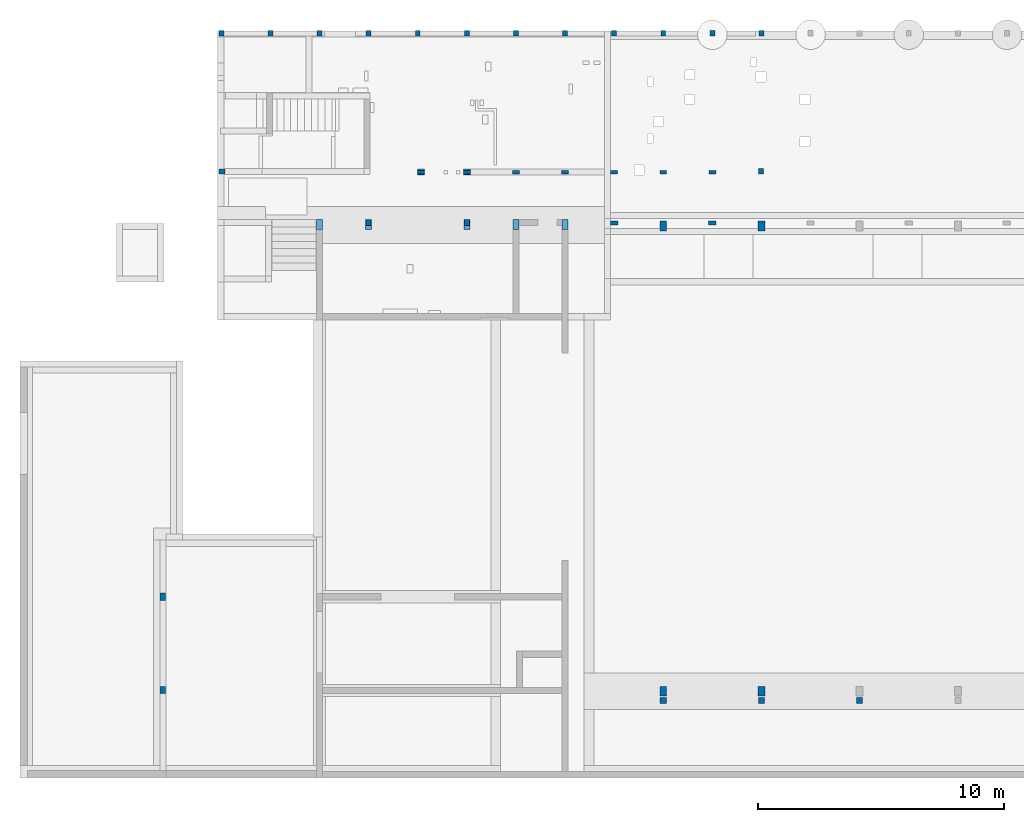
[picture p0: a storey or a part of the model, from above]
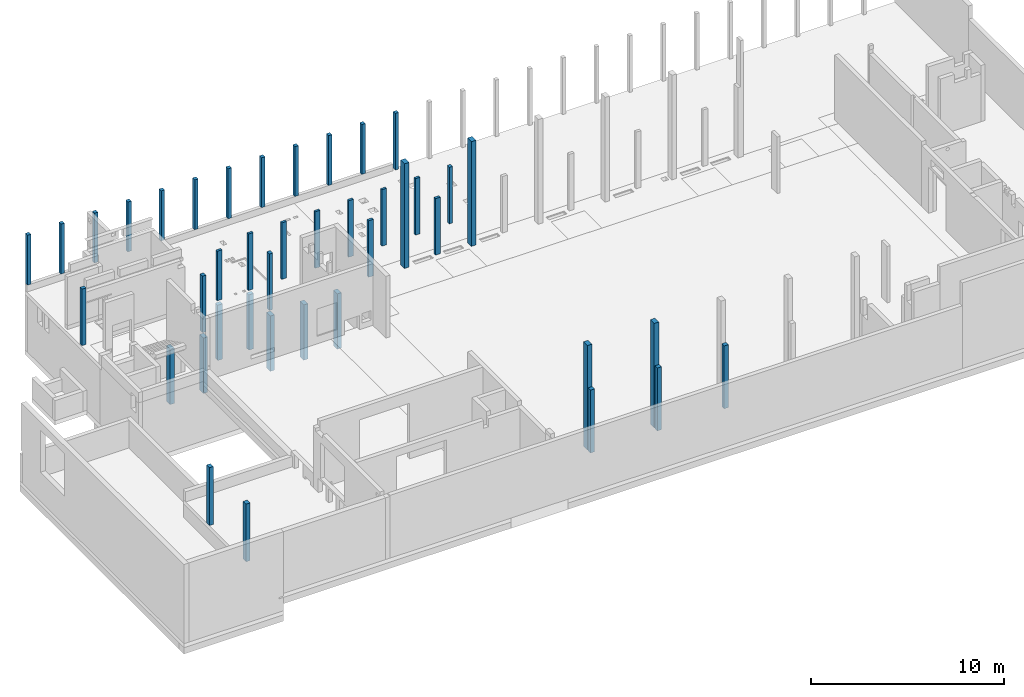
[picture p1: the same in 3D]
Properties of the parts of a building model (IFC2X3), part 1 of 6

# File
Description: ViewDefinition [CoordinationView_V2.0], RevitIdentifiers [ContentGUID: , VersionGUID: a09f6c8c-cfaa-406c-b728-5db6d23b4cc1, NumberOfSaves: 307], CoordinateReference [CoordinateBase: Projekt-Basispunkt, ProjectSite: Intern]
File name: 223092_BWS_Bürgerhaus_Weil_im_Schönbuch_rvt_23.ifc
Time: 2025-05-28T14:49:00+01:00
Written by: ODA SDAI 22.12
Made in: Autodesk Revit 23.1.60.36 (DEU) - IFC 23.4.0.0

# IfcProject, 223092
LongName: Bürgerhaus Weil im Schönbuch; Phase: Projektstatus

# IfcSite, Default
RefLatitude: 48, 8, 20, 852966; RefLongitude: 11, 34, 48, 669204; RefElevation: 0 m
Sonstige - Auftraggeber: Gemeinde Weil im Schönbuch; Kategorie: Projektinformationen; Projektadresse: Seesteige 11, 71093 Weil im Schönbuch; Projektausgabedatum: 21.02.2025; Projektname: Bürgerhaus Weil im Schönbuch; Projektnummer: 223092; Projektstatus: Projektstatus; WS_CLIENT_ADDRESS: Marktplatz 3, 71093 Weil im Schönbuch
Daten - WS_ARCHITECT: Architekt Name; WS_ARCHITECT_INFO: Architekt StraßeArchitekt PLZ OrtArchitekt Telefon; WS_PLANNER_1: Fachplaner 1 Name; WS_PLANNER_1_INFO: Fachplaner StraßeFachplaner PLZ OrtFachplaner Telefon; WS_PLANNER_2: Fachplaner 2 Name; WS_PLANNER_2_INFO: Fachplaner StraßeFachplaner PLZ OrtFachplaner Telefon; WS_PLANNER_3: Fachplaner 3 Name; WS_PLANNER_3_INFO: Fachplaner StraßeFachplaner PLZ OrtFachplaner Telefon; WS_PLANNER_4: Fachplaner 4 Name; WS_PLANNER_4_INFO: Fachplaner StraßeFachplaner PLZ OrtFachplaner Telefon; WS_PROJECT_CONTROLLER: Projektsteuerer; WS_PROJECT_CONTROLLER_INFO: Projektsteuerer StraßeProjektsteuerer PLZ OrtProjektsteuerer Telefon; WS_STRUCTURAL_PLANNER: Tragwerksplaner Name; WS_STRUCTURAL_PLANNER_INFO: Tragwerksplaner StraßeTragwerksplaner PLZ OrtTragwerksplaner Telefon; WS_SUBJECT: Objektplanung

# IfcBuilding
Pset_BuildingCommon - NumberOfStoreys: 2
Sonstige - Auftraggeber: Gemeinde Weil im Schönbuch; Kategorie: Projektinformationen; Projektadresse: Seesteige 11, 71093 Weil im Schönbuch; Projektausgabedatum: 21.02.2025; Projektname: Bürgerhaus Weil im Schönbuch; Projektnummer: 223092; Projektstatus: Projektstatus; WS_CLIENT_ADDRESS: Marktplatz 3, 71093 Weil im Schönbuch
Daten - WS_ARCHITECT: Architekt Name; WS_ARCHITECT_INFO: Architekt StraßeArchitekt PLZ OrtArchitekt Telefon; WS_PLANNER_1: Fachplaner 1 Name; WS_PLANNER_1_INFO: Fachplaner StraßeFachplaner PLZ OrtFachplaner Telefon; WS_PLANNER_2: Fachplaner 2 Name; WS_PLANNER_2_INFO: Fachplaner StraßeFachplaner PLZ OrtFachplaner Telefon; WS_PLANNER_3: Fachplaner 3 Name; WS_PLANNER_3_INFO: Fachplaner StraßeFachplaner PLZ OrtFachplaner Telefon; WS_PLANNER_4: Fachplaner 4 Name; WS_PLANNER_4_INFO: Fachplaner StraßeFachplaner PLZ OrtFachplaner Telefon; WS_PROJECT_CONTROLLER: Projektsteuerer; WS_PROJECT_CONTROLLER_INFO: Projektsteuerer StraßeProjektsteuerer PLZ OrtProjektsteuerer Telefon; WS_STRUCTURAL_PLANNER: Tragwerksplaner Name; WS_STRUCTURAL_PLANNER_INFO: Tragwerksplaner StraßeTragwerksplaner PLZ OrtTragwerksplaner Telefon; WS_SUBJECT: Objektplanung

# IfcBuildingStorey: Ebene:TAG_TFFL (2)
Pset_AirSideSystemInformation - sets with these values: 2
Sonstige - Familie: Ebene; Familie und Typ: Ebene: TAG_TFFL; Kategorie: Ebenen; Typ: TAG_TFFL; Typ-ID: 310376
Bemaßungen - Höhe für Berechnung: 0 m
ID-Daten - Gebäudegeschoss: yes; Tragwerk: no
Sonstige(Type) - Kategorie: Ebenen; Familienname: Ebene
Abhängigkeiten(Type) - Basishöhe: Projekt-Basispunkt
Grafiken(Type) - Farbe: 16711680; Linienmuster: WS_DOT; Linienstärke: 1; Symbol: WS_TAG_LEVEL1 : TAG_TFFL 2; Symbol bei Ende 1 Standard: no; Symbol bei Ende 2 Standard: yes
ID-Daten(Type) - Typname: TAG_TFFL
Name | LongName = Pset_AirSideSystemInformation, Name = ID-Daten, Name | Elevation (m) = Höhe (m) | WS_LEVEL
FB_U01_OKFB | FB_U01_OKFB | -3.8 | UG1
FB_E00_OKFB | FB_E00_OKFB | 0 | EG

# IfcBeam: WS_CBM_REC:CBM_REC_240x250 (3)
In: FB_E00_OKFB
Type - PredefinedType: BEAM
Type - Sonstige - Kategorie: Skelettbau; Familienname: WS_CBM_REC
Type - Bemaßungen - Height: 0.25 m; Höhe: 0.25 m; WS_HEIGHT: 0.25 m; WS_WIDTH: 0.24 m
Type - ID-Daten - Typname: CBM_REC_240x250; WS_COMMENT_DIMENSION: UZ 24/25cm
Type - Materialien und Oberflächen - Tragendes Material: WS_CONCRETE_REINFORCED
Type - Tragwerk - Querschnittsform: 0
Type - Pset_BeamCommon - LoadBearing: yes
Material: WS_CONCRETE_REINFORCED
Pset_BeamCommon - IsExternal: no; Slope: 0 deg; Reference: CBM_REC_240x250
Pset_QuantityTakeOff - Reference: CBM_REC_240x250; sets with these values: 2
Sonstige - Familie: WS_CBM_REC; Familie und Typ: WS_CBM_REC: CBM_REC_240x250; Typ: CBM_REC_240x250; Typ-ID: 3908165; WS_END_EXTENSION_CALCULATED: 3 m; WS_START_EXTENSION_CALCULATED: 3 m
Abhängigkeiten - Querschnittdrehung: 0 deg; Ausrichtung: Normal; Arbeitsebene: <nicht verknüpft>
Konstruktion - WS_END_EXTENSION: 0 m; WS_START_EXTENSION: 0 m
Bemaßungen - Höhe oben: 1.01 m; Höhe unten: 0.76 m
ID-Daten - Hat Verknüpfung: no; WS_COMMENT_MATERIAL: C25/30 RC; WS_POSITIONNUMBER: 003.1; WS_TYPE_BUILDING_ELEMENT: B
Phasen - Phase erstellt: Phase 1
Tragwerk - Betonüberdeckung - Andere Flächen: Bewehrungsüberdeckung 1 <25 mm>; Betonüberdeckung - Obere Fläche: Bewehrungsüberdeckung 1 <25 mm>; Betonüberdeckung - Untere Fläche: Bewehrungsüberdeckung 1 <25 mm>; Tragwerksverwendung: Sonstige; Anfangsverbindung - Typ: Endhöhe
Text - WS_LEVEL: 00
Geometrische Position - y-Ausrichtung: Ursprung; y-Versatzwert: 0 m; yz-Ausrichtung: Einheitlich; z-Ausrichtung: Oben; Verbindungsstatus: Beide Verbindungen aktiviert; z-Versatzwert: 0.08 m
Name (WS_CBM_REC:CBM_REC_240x250:...) | Span (m) = Länge (m) | Volumen (m3) | Endverbindung - Typ | Schnittlänge (m)
4185140 | 2.3125 | 0.129552 | Endhöhe | 2.16
4185141 | 3.52 | 0.21 | Endhöhe | 3.5
4185142 | 3.29271 | 0.1878 |  | 3.13001

# IfcBeam: WS_CBM_REC:CBM_REC_240x500 (3)
In: FB_E00_OKFB
Type - PredefinedType: BEAM
Type - Sonstige - Kategorie: Skelettbau; Familienname: WS_CBM_REC
Type - Bemaßungen - Height: 0.5 m; Höhe: 0.5 m; WS_HEIGHT: 0.5 m; WS_WIDTH: 0.24 m
Type - ID-Daten - Typname: CBM_REC_240x500; WS_COMMENT_DIMENSION: UZ 24/50cm
Type - Materialien und Oberflächen - Tragendes Material: WS_CONCRETE_REINFORCED
Type - Tragwerk - Querschnittsform: 0
Type - Pset_BeamCommon - LoadBearing: yes
Material: WS_CONCRETE_REINFORCED
Pset_BeamCommon - IsExternal: no; Slope: 0 deg; Reference: CBM_REC_240x500
Pset_QuantityTakeOff - Reference: CBM_REC_240x500; sets with these values: 2
Sonstige - Familie: WS_CBM_REC; Familie und Typ: WS_CBM_REC: CBM_REC_240x500; Typ: CBM_REC_240x500; Typ-ID: 3907001; WS_END_EXTENSION_CALCULATED: 3 m; WS_START_EXTENSION_CALCULATED: 3 m
Abhängigkeiten - Endebenenversatz: 0 m; Querschnittdrehung: 0 deg; Startebenenversatz: 0 m; Ausrichtung: Normal; Arbeitsebene: Ebene : Dü_EG_OKRD_+4,035; Höhe Referenzebene: 4.035 m; Referenzebene: Dü_EG_OKRD_+4,035
Konstruktion - WS_END_EXTENSION: 0 m; WS_START_EXTENSION: 0 m
Bemaßungen - Höhe oben: 4.035 m; Höhe unten: 3.535 m
ID-Daten - Hat Verknüpfung: no; WS_COMMENT_MATERIAL: C25/30 RC; WS_TYPE_BUILDING_ELEMENT: B
Phasen - Phase erstellt: Phase 1
Tragwerk - Betonüberdeckung - Andere Flächen: Bewehrungsüberdeckung 1 <25 mm>; Betonüberdeckung - Untere Fläche: Bewehrungsüberdeckung 1 <25 mm>; Tragwerksverwendung: Sonstige; Anfangsverbindung - Typ: Endhöhe
Text - WS_LEVEL: 00
Geometrische Position - y-Ausrichtung: Ursprung; y-Versatzwert: 0 m; yz-Ausrichtung: Einheitlich; z-Ausrichtung: Oben; Verbindungsstatus: Beide Verbindungen aktiviert; z-Versatzwert: 0 m
Name (WS_CBM_REC:CBM_REC_240x500:...) | Span (m) = Länge (m) | Volumen (m3) | WS_POSITIONNUMBER | Schnittlänge (m)
3907054 | 6.825 | 0.405 | 001.2 | 6.75 | Tragwerk - Endverbindung - Typ: Endhöhe
3908007 | 9.54001 | 0.5634 | 001.3 | 9.39001
3925428 | 6.225 | 0.3621 | 001.1 | 6.075

# IfcBeam: WS_CBM_REC:CBM_REC_240x600, WS_CBM_REC:CBM_REC_240x600:3857827
In: FB_U01_OKFB
Type - PredefinedType: BEAM
Type - Sonstige - Kategorie: Skelettbau; Familienname: WS_CBM_REC
Type - Bemaßungen - Height: 0.6 m; Höhe: 0.6 m; WS_HEIGHT: 0.6 m; WS_WIDTH: 0.24 m
Type - ID-Daten - Typname: CBM_REC_240x600; WS_COMMENT_DIMENSION: UZ 24/60cm
Type - Materialien und Oberflächen - Tragendes Material: WS_CONCRETE_REINFORCED
Type - Tragwerk - Querschnittsform: 0
Type - Pset_BeamCommon - LoadBearing: yes
Material: WS_CONCRETE_REINFORCED
Pset_BeamCommon - IsExternal: no; Slope: 0 deg; Reference: CBM_REC_240x600; Span: 5.725 m
Pset_QuantityTakeOff - Reference: CBM_REC_240x600; sets with these values: 2
Sonstige - Familie: WS_CBM_REC; Familie und Typ: WS_CBM_REC: CBM_REC_240x600; Typ: CBM_REC_240x600; Typ-ID: 4411974; WS_END_EXTENSION_CALCULATED: 3.15571 m; WS_START_EXTENSION_CALCULATED: 3 m
Abhängigkeiten - Endebenenversatz: 0 m; Querschnittdrehung: 0 deg; Startebenenversatz: 0 m; Ausrichtung: Normal; Referenzebene: Dü_U01_OKRD_-0,12; Arbeitsebene: Ebene : Dü_U01_OKRD_-0,12; Höhe Referenzebene: -0.12 m
Konstruktion - WS_START_EXTENSION: 0 m; WS_END_EXTENSION: 0.155715 m
Bemaßungen - Höhe oben: -0.12 m; Höhe unten: -0.72 m; Länge: 5.725 m; Volumen: 0.45864 m3
ID-Daten - Hat Verknüpfung: no; WS_COMMENT_MATERIAL: C25/30 RC; WS_POSITIONNUMBER: 001; WS_TYPE_BUILDING_ELEMENT: B
Phasen - Phase erstellt: Phase 1
Tragwerk - Betonüberdeckung - Andere Flächen: Bewehrungsüberdeckung 1 <25 mm>; Betonüberdeckung - Untere Fläche: Bewehrungsüberdeckung 1 <25 mm>; Tragwerksverwendung: Sonstige; Endverbindung - Typ: Endhöhe; Schnittlänge: 5.46 m
Text - WS_LEVEL: U1
Geometrische Position - y-Ausrichtung: Ursprung; y-Versatzwert: 0 m; yz-Ausrichtung: Einheitlich; z-Ausrichtung: Oben; Verbindungsstatus: Beide Verbindungen aktiviert; z-Versatzwert: 0 m

# IfcBeam: WS_CBM_REC:CBM_REC_250x1065, WS_CBM_REC:CBM_REC_250x1065:3713072
In: FB_E00_OKFB
Type - PredefinedType: BEAM; Material: WS_CONCRETE_REINFORCED
Type - Sonstige - Kategorie: Skelettbau; Familienname: WS_CBM_REC
Type - Bemaßungen - Height: 1.065 m; Höhe: 1.065 m; WS_HEIGHT: 1.065 m; WS_WIDTH: 0.25 m
Type - ID-Daten - Typname: CBM_REC_250x1065; WS_COMMENT_DIMENSION: UZ 25/106,5cm
Type - Materialien und Oberflächen - Tragendes Material: WS_CONCRETE_REINFORCED
Type - Tragwerk - Querschnittsform: 0
Type - Pset_BeamCommon - LoadBearing: yes
Pset_BeamCommon - IsExternal: no; Slope: 0 deg; Reference: CBM_REC_250x1065; Span: 20.18 m
Pset_QuantityTakeOff - Reference: CBM_REC_250x1065; sets with these values: 2
Sonstige - Familie: WS_CBM_REC; Familie und Typ: WS_CBM_REC: CBM_REC_250x1065; Typ: CBM_REC_250x1065; Typ-ID: 3712955; WS_END_EXTENSION_CALCULATED: 3 m; WS_START_EXTENSION_CALCULATED: 3 m
Abhängigkeiten - Endebenenversatz: 0 m; Höhe Referenzebene: 4.15 m; Querschnittdrehung: 0 deg; Referenzebene: Dü_EG_OKRD_+4,15; Startebenenversatz: 0 m
Konstruktion - WS_END_EXTENSION: 0 m; WS_START_EXTENSION: 0 m
Bemaßungen - Höhe oben: 4.61 m; Höhe unten: 3.545 m; Länge: 20.18 m; Volumen: 3.78816 m3
ID-Daten - Hat Verknüpfung: no; WS_COMMENT_MATERIAL: C25/30 RC; WS_POSITIONNUMBER: 003; WS_TYPE_BUILDING_ELEMENT: B
Phasen - Phase erstellt: Phase 1
Tragwerk - Betonüberdeckung - Andere Flächen: Bewehrungsüberdeckung 1 <25 mm>; Betonüberdeckung - Obere Fläche: Bewehrungsüberdeckung 1 <25 mm>; Betonüberdeckung - Untere Fläche: Bewehrungsüberdeckung 1 <25 mm>; Schnittlänge: 20.3074 m; Tragwerksverwendung: Sonstige
Text - WS_LEVEL: 00
Geometrische Position - Verbindungsstatus: Eine oder zwei Verbindungen deaktiviert; y-Ausrichtung: Ursprung; y-Versatzwert: 0 m; yz-Ausrichtung: Einheitlich; z-Ausrichtung: Oben; z-Versatzwert: 0.46 m

# IfcBeam: WS_CBM_REC:CBM_REC_250x580, WS_CBM_REC:CBM_REC_250x580:4160228
In: FB_E00_OKFB
Type - PredefinedType: BEAM; Material: WS_CONCRETE_REINFORCED
Type - Sonstige - Kategorie: Skelettbau; Familienname: WS_CBM_REC
Type - Bemaßungen - Height: 0.58 m; Höhe: 0.58 m; WS_HEIGHT: 0.58 m; WS_WIDTH: 0.25 m
Type - ID-Daten - Typname: CBM_REC_250x580; WS_COMMENT_DIMENSION: UZ 25/58cm
Type - Materialien und Oberflächen - Tragendes Material: WS_CONCRETE_REINFORCED
Type - Tragwerk - Querschnittsform: 0
Type - Pset_BeamCommon - LoadBearing: yes
Pset_BeamCommon - IsExternal: no; Slope: 0 deg; Reference: CBM_REC_250x580; Span: 10.075 m
Pset_QuantityTakeOff - Reference: CBM_REC_250x580; sets with these values: 2
Sonstige - Familie: WS_CBM_REC; Familie und Typ: WS_CBM_REC: CBM_REC_250x580; Typ: CBM_REC_250x580; Typ-ID: 4369942; WS_END_EXTENSION_CALCULATED: 3 m; WS_START_EXTENSION_CALCULATED: 3 m
Abhängigkeiten - Endebenenversatz: 0 m; Querschnittdrehung: 0 deg; Startebenenversatz: 0 m; Ausrichtung: Normal; Referenzebene: Dü_EG_OKRD_+4,035; Arbeitsebene: Ebene : Dü_EG_OKRD_+4,035; Höhe Referenzebene: 4.035 m
Konstruktion - WS_END_EXTENSION: 0 m; WS_START_EXTENSION: 0 m
Bemaßungen - Höhe oben: 4.035 m; Höhe unten: 3.455 m; Länge: 10.075 m; Volumen: 0.789995 m3
ID-Daten - Hat Verknüpfung: no; WS_COMMENT_MATERIAL: C25/30 RC; WS_POSITIONNUMBER: 002; WS_TYPE_BUILDING_ELEMENT: B
Phasen - Phase erstellt: Phase 1
Tragwerk - Betonüberdeckung - Andere Flächen: Bewehrungsüberdeckung 1 <25 mm>; Betonüberdeckung - Untere Fläche: Bewehrungsüberdeckung 1 <25 mm>; Tragwerksverwendung: Sonstige; Schnittlänge: 10.075 m
Text - WS_LEVEL: 00
Geometrische Position - y-Ausrichtung: Ursprung; y-Versatzwert: 0 m; yz-Ausrichtung: Einheitlich; z-Ausrichtung: Oben; Verbindungsstatus: Beide Verbindungen aktiviert; z-Versatzwert: 0 m

# IfcBeam: WS_CBM_UPST_REC:CBM_UPST_REC_200x1950, WS_CBM_UPST_REC:CBM_UPST_REC_200x1950:3713771
In: FB_E00_OKFB
Type - PredefinedType: BEAM
Type - Sonstige - Kategorie: Skelettbau; Familienname: WS_CBM_UPST_REC
Type - Bemaßungen - Height: 1.95 m; Höhe: 1.95 m; WS_HEIGHT: 1.95 m; WS_WIDTH: 0.2 m
Type - ID-Daten - Typname: CBM_UPST_REC_200x1950; WS_COMMENT_DIMENSION: ÜZ 20/195cm
Type - Materialien und Oberflächen - Tragendes Material: WS_CONCRETE_REINFORCED
Type - Tragwerk - Querschnittsform: 0
Type - Pset_BeamCommon - LoadBearing: yes
Material: WS_CONCRETE_REINFORCED
Pset_BeamCommon - IsExternal: no; Slope: 0 deg; Reference: CBM_UPST_REC_200x1950; Span: 9.905 m
Pset_QuantityTakeOff - Reference: CBM_UPST_REC_200x1950; sets with these values: 2
Sonstige - Familie: WS_CBM_UPST_REC; Familie und Typ: WS_CBM_UPST_REC: CBM_UPST_REC_200x1950; Typ: CBM_UPST_REC_200x1950; Typ-ID: 4167233; WS_END_EXTENSION_CALCULATED: 3 m; WS_START_EXTENSION_CALCULATED: 3 m
Abhängigkeiten - Endebenenversatz: 0 m; Querschnittdrehung: 0 deg; Startebenenversatz: 0 m; Arbeitsebene: Ebene : Dü_EG_UKRD_+3,85; Ausrichtung: Normal; Höhe Referenzebene: 3.85 m; Referenzebene: Dü_EG_UKRD_+3,85
Konstruktion - WS_END_EXTENSION: 0 m; WS_START_EXTENSION: 0 m
Bemaßungen - Höhe oben: 5.8 m; Höhe unten: 3.85 m; Länge: 9.905 m; Volumen: 2.8084 m3
ID-Daten - Hat Verknüpfung: no; WS_COMMENT_MATERIAL: C25/30 RC; WS_TYPE_BUILDING_ELEMENT: B
Phasen - Phase erstellt: Phase 1
Tragwerk - Betonüberdeckung - Andere Flächen: Bewehrungsüberdeckung 1 <25 mm>; Betonüberdeckung - Obere Fläche: Bewehrungsüberdeckung 1 <25 mm>; Tragwerksverwendung: Sonstige; Schnittlänge: 10.03 m
Text - WS_LEVEL: 00
Geometrische Position - y-Ausrichtung: Ursprung; y-Versatzwert: 0 m; yz-Ausrichtung: Einheitlich; Verbindungsstatus: Beide Verbindungen aktiviert; z-Ausrichtung: Unten; z-Versatzwert: 0 m

# IfcBeam: WS_CBM_UPST_REC:CBM_UPST_REC_200x850, WS_CBM_UPST_REC:CBM_UPST_REC_200x850:4435147
In: FB_E00_OKFB
Type - PredefinedType: BEAM
Type - Sonstige - Kategorie: Skelettbau; Familienname: WS_CBM_UPST_REC
Type - Bemaßungen - Height: 0.85 m; Höhe: 0.85 m; WS_HEIGHT: 0.85 m; WS_WIDTH: 0.2 m
Type - ID-Daten - Typname: CBM_UPST_REC_200x850; WS_COMMENT_DIMENSION: ÜZ 20/85cm
Type - Materialien und Oberflächen - Tragendes Material: WS_CONCRETE_REINFORCED
Type - Tragwerk - Querschnittsform: 0
Type - Pset_BeamCommon - LoadBearing: yes
Material: WS_CONCRETE_REINFORCED
Pset_BeamCommon - IsExternal: no; Slope: 0 deg; Reference: CBM_UPST_REC_200x850; Span: 8.13 m
Pset_QuantityTakeOff - Reference: CBM_UPST_REC_200x850; sets with these values: 2
Sonstige - Familie: WS_CBM_UPST_REC; Familie und Typ: WS_CBM_UPST_REC: CBM_UPST_REC_200x850; Typ: CBM_UPST_REC_200x850; Typ-ID: 4460570; WS_END_EXTENSION_CALCULATED: 3 m; WS_START_EXTENSION_CALCULATED: 3 m
Abhängigkeiten - Endebenenversatz: 0 m; Querschnittdrehung: 0 deg; Startebenenversatz: 0 m; Ausrichtung: Normal; Arbeitsebene: Ebene : Dü_EG_OKRD_+5,12; Höhe Referenzebene: 5.12 m; Referenzebene: Dü_EG_OKRD_+5,12
Konstruktion - WS_END_EXTENSION: 0 m; WS_START_EXTENSION: 0 m
Bemaßungen - Höhe oben: 5.77 m; Höhe unten: 4.92 m; Länge: 8.13 m; Volumen: 1.06665 m3
ID-Daten - Hat Verknüpfung: no; WS_COMMENT_MATERIAL: C25/30 RC; WS_POSITIONNUMBER: 004; WS_TYPE_BUILDING_ELEMENT: B
Phasen - Phase erstellt: Phase 1
Tragwerk - Betonüberdeckung - Andere Flächen: Bewehrungsüberdeckung 1 <25 mm>; Betonüberdeckung - Obere Fläche: Bewehrungsüberdeckung 1 <25 mm>; Betonüberdeckung - Untere Fläche: Bewehrungsüberdeckung 1 <25 mm>; Tragwerksverwendung: Sonstige; Schnittlänge: 8.255 m
Text - WS_LEVEL: 00
Geometrische Position - y-Ausrichtung: Ursprung; y-Versatzwert: 0 m; yz-Ausrichtung: Einheitlich; Verbindungsstatus: Beide Verbindungen aktiviert; z-Ausrichtung: Unten; z-Versatzwert: -0.2 m

# IfcBeam: WS_CBM_UPST_REC:CBM_UPST_REC_250x1015, WS_CBM_UPST_REC:CBM_UPST_REC_250x1015:4164935
In: FB_E00_OKFB
Type - PredefinedType: BEAM
Type - Sonstige - Kategorie: Skelettbau; Familienname: WS_CBM_UPST_REC
Type - Bemaßungen - Height: 1.015 m; Höhe: 1.015 m; WS_HEIGHT: 1.015 m; WS_WIDTH: 0.25 m
Type - ID-Daten - Typname: CBM_UPST_REC_250x1015; WS_COMMENT_DIMENSION: ÜZ 25/101,5
Type - Materialien und Oberflächen - Tragendes Material: WS_CONCRETE_REINFORCED
Type - Tragwerk - Querschnittsform: 0
Type - Pset_BeamCommon - LoadBearing: yes
Material: WS_CONCRETE_REINFORCED
Pset_BeamCommon - IsExternal: no; Slope: 0 deg; Reference: CBM_UPST_REC_250x1015; Span: 15.6524 m
Pset_QuantityTakeOff - Reference: CBM_UPST_REC_250x1015; sets with these values: 2
Sonstige - Familie: WS_CBM_UPST_REC; Familie und Typ: WS_CBM_UPST_REC: CBM_UPST_REC_250x1015; Typ: CBM_UPST_REC_250x1015; Typ-ID: 4164723; WS_END_EXTENSION_CALCULATED: 3 m; WS_START_EXTENSION_CALCULATED: 3 m
Abhängigkeiten - Endebenenversatz: 0 m; Querschnittdrehung: 0 deg; Startebenenversatz: 0 m; Ausrichtung: Normal; Referenzebene: Dü_EG_UKRD_+3,785; Arbeitsebene: Ebene : Dü_EG_UKRD_+3,785; Höhe Referenzebene: 3.785 m
Konstruktion - WS_END_EXTENSION: 0 m; WS_START_EXTENSION: 0 m
Bemaßungen - Höhe oben: 4.8 m; Höhe unten: 3.785 m; Länge: 15.6524 m; Volumen: 2.96369 m3
ID-Daten - Hat Verknüpfung: no; WS_COMMENT_MATERIAL: C25/30 RC; WS_POSITIONNUMBER: 021; WS_TYPE_BUILDING_ELEMENT: W
Phasen - Phase erstellt: Phase 1
Tragwerk - Betonüberdeckung - Andere Flächen: Bewehrungsüberdeckung 1 <25 mm>; Tragwerksverwendung: Sonstige; Schnittlänge: 15.6524 m
Text - WS_LEVEL: 00
Geometrische Position - y-Ausrichtung: Ursprung; y-Versatzwert: 0 m; yz-Ausrichtung: Einheitlich; Verbindungsstatus: Beide Verbindungen aktiviert; z-Ausrichtung: Unten; z-Versatzwert: 0 m

# IfcBeam: WS_CBM_UPST_REC:CBM_UPST_REC_250x137, WS_CBM_UPST_REC:CBM_UPST_REC_250x137:3872985
In: FB_E00_OKFB
Type - PredefinedType: BEAM
Type - Sonstige - Kategorie: Skelettbau; Familienname: WS_CBM_UPST_REC
Type - Bemaßungen - Height: 1.37 m; Höhe: 1.37 m; WS_HEIGHT: 1.37 m; WS_WIDTH: 0.25 m
Type - ID-Daten - Typname: CBM_UPST_REC_250x137; WS_COMMENT_DIMENSION: ÜZ 25/137cm
Type - Materialien und Oberflächen - Tragendes Material: WS_CONCRETE_REINFORCED
Type - Tragwerk - Querschnittsform: 0
Type - Pset_BeamCommon - LoadBearing: yes
Material: WS_CONCRETE_REINFORCED
Pset_BeamCommon - IsExternal: no; Slope: 0 deg; Reference: CBM_UPST_REC_250x137; Span: 5.93999 m
Pset_QuantityTakeOff - Reference: CBM_UPST_REC_250x137; sets with these values: 2
Sonstige - Familie: WS_CBM_UPST_REC; Familie und Typ: WS_CBM_UPST_REC: CBM_UPST_REC_250x137; Typ: CBM_UPST_REC_250x137; Typ-ID: 4178444; WS_END_EXTENSION_CALCULATED: 3 m; WS_START_EXTENSION_CALCULATED: 3 m
Abhängigkeiten - Endebenenversatz: 0 m; Querschnittdrehung: 0 deg; Startebenenversatz: 0 m; Ausrichtung: Normal; Referenzebene: Dü_EG_UKRD_+3,43; Arbeitsebene: Ebene : Dü_EG_UKRD_+3,43; Höhe Referenzebene: 3.43 m
Konstruktion - WS_END_EXTENSION: 0 m; WS_START_EXTENSION: 0 m
Bemaßungen - Höhe oben: 4.8 m; Höhe unten: 3.43 m; Länge: 5.93999 m; Volumen: 1.61291 m3
ID-Daten - Hat Verknüpfung: no; WS_COMMENT_MATERIAL: C25/30 RC
Phasen - Phase erstellt: Phase 1
Tragwerk - Betonüberdeckung - Andere Flächen: Bewehrungsüberdeckung 1 <25 mm>; Betonüberdeckung - Obere Fläche: Bewehrungsüberdeckung 1 <25 mm>; Tragwerksverwendung: Sonstige; Schnittlänge: 5.93999 m
Text - WS_LEVEL: 00
Geometrische Position - Verbindungsstatus: Eine oder zwei Verbindungen deaktiviert; y-Ausrichtung: Ursprung; y-Versatzwert: 0 m; yz-Ausrichtung: Einheitlich; z-Ausrichtung: Unten; z-Versatzwert: 0 m

# IfcBeam: WS_CBM_UPST_REC:CBM_UPST_REC_250x1400 (2)
In: FB_E00_OKFB
Type - PredefinedType: BEAM
Type - Sonstige - Kategorie: Skelettbau; Familienname: WS_CBM_UPST_REC
Type - Bemaßungen - Height: 1.4 m; Höhe: 1.4 m; WS_HEIGHT: 1.4 m; WS_WIDTH: 0.25 m
Type - ID-Daten - Typname: CBM_UPST_REC_250x1400; WS_COMMENT_DIMENSION: ÜZ 25/140cm
Type - Materialien und Oberflächen - Tragendes Material: WS_CONCRETE_REINFORCED
Type - Tragwerk - Querschnittsform: 0
Type - Pset_BeamCommon - LoadBearing: yes
Material: WS_CONCRETE_REINFORCED
Pset_BeamCommon - IsExternal: no; Slope: 0 deg; Reference: CBM_UPST_REC_250x1400
Pset_QuantityTakeOff - Reference: CBM_UPST_REC_250x1400; sets with these values: 2
Sonstige - Familie: WS_CBM_UPST_REC; Familie und Typ: WS_CBM_UPST_REC: CBM_UPST_REC_250x1400; Typ: CBM_UPST_REC_250x1400; Typ-ID: 3714466; WS_END_EXTENSION_CALCULATED: 3 m; WS_START_EXTENSION_CALCULATED: 3 m
Abhängigkeiten - Endebenenversatz: 0 m; Querschnittdrehung: 0 deg; Startebenenversatz: 0 m; Ausrichtung: Normal; Referenzebene: Dü_EG_UKRD_+3,85; Arbeitsebene: Ebene : Dü_EG_UKRD_+3,85; Höhe Referenzebene: 3.85 m
Konstruktion - WS_END_EXTENSION: 0 m; WS_START_EXTENSION: 0 m
Bemaßungen - Höhe oben: 5.25 m; Höhe unten: 3.85 m
ID-Daten - Hat Verknüpfung: no; WS_COMMENT_MATERIAL: C25/30 RC
Phasen - Phase erstellt: Phase 1
Tragwerk - Betonüberdeckung - Andere Flächen: Bewehrungsüberdeckung 1 <25 mm>; Betonüberdeckung - Obere Fläche: Bewehrungsüberdeckung 1 <25 mm>; Tragwerksverwendung: Sonstige
Text - WS_LEVEL: 00
Geometrische Position - y-Ausrichtung: Ursprung; y-Versatzwert: 0 m; yz-Ausrichtung: Einheitlich; Verbindungsstatus: Beide Verbindungen aktiviert; z-Ausrichtung: Unten; z-Versatzwert: 0 m
Name (WS_CBM_UPST_REC:CBM_UPST_REC_250x1400:...) | Span (m) = Länge (m) | Volumen (m3) | WS_POSITIONNUMBER | WS_TYPE_BUILDING_ELEMENT | Schnittlänge (m)
4168769 | 34.375 | 9.41875 | 103 | W | 34.25
4172455 | 3.0251 | 0.843776 | 031 | B | 3.2751

# IfcBeam: WS_CBM_UPST_REC:CBM_UPST_REC_250x2015, WS_CBM_UPST_REC:CBM_UPST_REC_250x2015:4165731
In: FB_E00_OKFB
Type - PredefinedType: BEAM; Material: WS_CONCRETE_REINFORCED
Type - Sonstige - Kategorie: Skelettbau; Familienname: WS_CBM_UPST_REC
Type - Bemaßungen - Height: 2.015 m; Höhe: 2.015 m; WS_HEIGHT: 2.015 m; WS_WIDTH: 0.25 m
Type - ID-Daten - Typname: CBM_UPST_REC_250x2015; WS_COMMENT_DIMENSION: ÜZ 25/201,5cm
Type - Materialien und Oberflächen - Tragendes Material: WS_CONCRETE_REINFORCED
Type - Tragwerk - Querschnittsform: 0
Type - Pset_BeamCommon - LoadBearing: yes
Pset_BeamCommon - IsExternal: no; Slope: 0 deg; Reference: CBM_UPST_REC_250x2015; Span: 2.68255 m
Pset_QuantityTakeOff - Reference: CBM_UPST_REC_250x2015; sets with these values: 2
Sonstige - Familie: WS_CBM_UPST_REC; Familie und Typ: WS_CBM_UPST_REC: CBM_UPST_REC_250x2015; Typ: CBM_UPST_REC_250x2015; Typ-ID: 4166134; WS_END_EXTENSION_CALCULATED: 3 m; WS_START_EXTENSION_CALCULATED: 3 m
Abhängigkeiten - Endebenenversatz: 0 m; Querschnittdrehung: 0 deg; Startebenenversatz: 0 m; Ausrichtung: Normal; Referenzebene: Dü_EG_UKRD_+3,785; Arbeitsebene: Ebene : Dü_EG_UKRD_+3,785; Höhe Referenzebene: 3.785 m
Konstruktion - WS_END_EXTENSION: 0 m; WS_START_EXTENSION: 0 m
Bemaßungen - Höhe oben: 5.8 m; Höhe unten: 3.785 m; Länge: 2.68255 m; Volumen: 0.990225 m3
ID-Daten - Hat Verknüpfung: no; WS_COMMENT_MATERIAL: C25/30 RC; WS_POSITIONNUMBER: 013; WS_TYPE_BUILDING_ELEMENT: W
Phasen - Phase erstellt: Phase 1
Tragwerk - Betonüberdeckung - Andere Flächen: Bewehrungsüberdeckung 1 <25 mm>; Betonüberdeckung - Obere Fläche: Bewehrungsüberdeckung 1 <25 mm>; Tragwerksverwendung: Sonstige; Schnittlänge: 2.68255 m
Text - WS_LEVEL: 00
Geometrische Position - y-Ausrichtung: Ursprung; y-Versatzwert: 0 m; yz-Ausrichtung: Einheitlich; Verbindungsstatus: Beide Verbindungen aktiviert; z-Ausrichtung: Unten; z-Versatzwert: 0 m

# IfcBeam: WS_CBM_UPST_REC:CBM_UPST_REC_250x2035, WS_CBM_UPST_REC:CBM_UPST_REC_250x2035:4176563
In: FB_E00_OKFB
Type - PredefinedType: BEAM
Type - Sonstige - Kategorie: Skelettbau; Familienname: WS_CBM_UPST_REC
Type - Bemaßungen - Height: 2.035 m; Höhe: 2.035 m; WS_HEIGHT: 2.035 m; WS_WIDTH: 0.25 m
Type - ID-Daten - Typname: CBM_UPST_REC_250x2035; WS_COMMENT_DIMENSION: ÜZ 25/203,5cm
Type - Materialien und Oberflächen - Tragendes Material: WS_CONCRETE_REINFORCED
Type - Tragwerk - Querschnittsform: 0
Type - Pset_BeamCommon - LoadBearing: yes
Material: WS_CONCRETE_REINFORCED
Pset_BeamCommon - IsExternal: no; Slope: 0 deg; Reference: CBM_UPST_REC_250x2035; Span: 4.90491 m
Pset_QuantityTakeOff - Reference: CBM_UPST_REC_250x2035; sets with these values: 2
Sonstige - Familie: WS_CBM_UPST_REC; Familie und Typ: WS_CBM_UPST_REC: CBM_UPST_REC_250x2035; Typ: CBM_UPST_REC_250x2035; Typ-ID: 4176715; WS_END_EXTENSION_CALCULATED: 3 m; WS_START_EXTENSION_CALCULATED: 3 m
Abhängigkeiten - Endebenenversatz: 0 m; Querschnittdrehung: 0 deg; Startebenenversatz: 0 m; Ausrichtung: Normal; Arbeitsebene: Ebene : Dü_EG_UKRD1_+3,735; Höhe Referenzebene: 3.735 m; Referenzebene: Dü_EG_UKRD1_+3,735
Konstruktion - WS_END_EXTENSION: 0 m; WS_START_EXTENSION: 0 m
Bemaßungen - Höhe oben: 5.77 m; Höhe unten: 3.735 m; Länge: 4.90491 m; Volumen: 2.17202 m3
ID-Daten - Hat Verknüpfung: no; WS_COMMENT_MATERIAL: C25/30
Phasen - Phase erstellt: Phase 1
Tragwerk - Betonüberdeckung - Andere Flächen: Bewehrungsüberdeckung 1 <25 mm>; Betonüberdeckung - Obere Fläche: Bewehrungsüberdeckung 1 <25 mm>; Betonüberdeckung - Untere Fläche: Bewehrungsüberdeckung 1 <25 mm>; Tragwerksverwendung: Sonstige; Schnittlänge: 4.84557 m
Text - WS_LEVEL: 00
Geometrische Position - Verbindungsstatus: Eine oder zwei Verbindungen deaktiviert; y-Ausrichtung: Ursprung; y-Versatzwert: 0 m; yz-Ausrichtung: Einheitlich; z-Ausrichtung: Unten; z-Versatzwert: 0 m

# IfcBeam: WS_CBM_UPST_REC:CBM_UPST_REC_250x480 (2)
In: FB_E00_OKFB
Type - PredefinedType: BEAM
Type - Sonstige - Kategorie: Skelettbau; Familienname: WS_CBM_UPST_REC
Type - Bemaßungen - Height: 0.48 m; Höhe: 0.48 m; WS_HEIGHT: 0.48 m; WS_WIDTH: 0.25 m
Type - ID-Daten - Typname: CBM_UPST_REC_250x480; WS_COMMENT_DIMENSION: ÜZ 25/48cm
Type - Materialien und Oberflächen - Tragendes Material: WS_CONCRETE_REINFORCED
Type - Tragwerk - Querschnittsform: 0
Type - Pset_BeamCommon - LoadBearing: yes
Material: WS_CONCRETE_REINFORCED
Pset_BeamCommon - IsExternal: no; Slope: 0 deg; Reference: CBM_UPST_REC_250x480
Pset_QuantityTakeOff - Reference: CBM_UPST_REC_250x480; sets with these values: 2
Sonstige - Familie: WS_CBM_UPST_REC; Familie und Typ: WS_CBM_UPST_REC: CBM_UPST_REC_250x480; Typ: CBM_UPST_REC_250x480; Typ-ID: 4168103; WS_END_EXTENSION_CALCULATED: 3 m; WS_START_EXTENSION_CALCULATED: 3 m
Abhängigkeiten - Endebenenversatz: 0 m; Querschnittdrehung: 0 deg; Startebenenversatz: 0 m; Ausrichtung: Normal; Arbeitsebene: Ebene : Dü_EG_UKRD_+3,785; Höhe Referenzebene: 3.785 m; Referenzebene: Dü_EG_UKRD_+3,785
Konstruktion - WS_END_EXTENSION: 0 m; WS_START_EXTENSION: 0 m
Bemaßungen - Höhe oben: 4.265 m; Höhe unten: 3.785 m
ID-Daten - Hat Verknüpfung: no; WS_COMMENT_MATERIAL: C25/30 RC; WS_TYPE_BUILDING_ELEMENT: W
Phasen - Phase erstellt: Phase 1
Tragwerk - Betonüberdeckung - Andere Flächen: Bewehrungsüberdeckung 1 <25 mm>; Betonüberdeckung - Obere Fläche: Bewehrungsüberdeckung 1 <25 mm>; Tragwerksverwendung: Sonstige
Text - WS_LEVEL: 00
Geometrische Position - y-Ausrichtung: Ursprung; y-Versatzwert: 0 m; yz-Ausrichtung: Einheitlich; z-Ausrichtung: Unten; z-Versatzwert: 0 m
Name (WS_CBM_UPST_REC:CBM_UPST_REC_250x480:...) | Span (m) = Länge (m) | Volumen (m3) | WS_POSITIONNUMBER | Schnittlänge (m) | Verbindungsstatus
3919060 | 11.565 | 0.672173 | 101 | 11.69 | Beide Verbindungen aktiviert
4168264 | 7.9 | 0.4485 | 107 | 7.8 | Eine oder zwei Verbindungen deaktiviert

# IfcBeam: WS_CBM_UPST_REC:CBM_UPST_REC_250x615, WS_CBM_UPST_REC:CBM_UPST_REC_250x615:4165654
In: FB_E00_OKFB
Type - PredefinedType: BEAM
Type - Sonstige - Kategorie: Skelettbau; Familienname: WS_CBM_UPST_REC
Type - Bemaßungen - Height: 0.615 m; Höhe: 0.615 m; WS_HEIGHT: 0.615 m; WS_WIDTH: 0.25 m
Type - ID-Daten - Typname: CBM_UPST_REC_250x615; WS_COMMENT_DIMENSION: Attika
Type - Materialien und Oberflächen - Tragendes Material: WS_CONCRETE_REINFORCED
Type - Tragwerk - Querschnittsform: 0
Type - Pset_BeamCommon - LoadBearing: yes
Material: WS_CONCRETE_REINFORCED
Pset_BeamCommon - IsExternal: no; Slope: 0 deg; Reference: CBM_UPST_REC_250x615; Span: 1.27 m
Pset_QuantityTakeOff - Reference: CBM_UPST_REC_250x615; sets with these values: 2
Sonstige - Familie: WS_CBM_UPST_REC; Familie und Typ: WS_CBM_UPST_REC: CBM_UPST_REC_250x615; Typ: CBM_UPST_REC_250x615; Typ-ID: 4707557; WS_END_EXTENSION_CALCULATED: 3 m; WS_START_EXTENSION_CALCULATED: 3 m
Abhängigkeiten - Endebenenversatz: 0 m; Querschnittdrehung: 0 deg; Startebenenversatz: 0 m; Ausrichtung: Normal; Referenzebene: Dü_EG_UKRD_+3,785; Arbeitsebene: Ebene : Dü_EG_UKRD_+3,785; Höhe Referenzebene: 3.785 m
Konstruktion - WS_END_EXTENSION: 0 m; WS_START_EXTENSION: 0 m
Bemaßungen - Höhe oben: 4.4 m; Höhe unten: 3.785 m; Länge: 1.27 m; Volumen: 0.0365125 m3
ID-Daten - Hat Verknüpfung: no; WS_COMMENT_MATERIAL: C25/30 RC; WS_POSITIONNUMBER: 013; WS_TYPE_BUILDING_ELEMENT: W
Phasen - Phase erstellt: Phase 1
Tragwerk - Betonüberdeckung - Andere Flächen: Bewehrungsüberdeckung 1 <25 mm>; Tragwerksverwendung: Sonstige; Schnittlänge: 1.27 m
Text - WS_LEVEL: 00
Geometrische Position - y-Ausrichtung: Ursprung; y-Versatzwert: 0 m; yz-Ausrichtung: Einheitlich; Verbindungsstatus: Beide Verbindungen aktiviert; z-Ausrichtung: Unten; z-Versatzwert: 0 m

# IfcBeam: WS_CBM_UPST_REC:CBM_UPST_REC_250x760, WS_CBM_UPST_REC:CBM_UPST_REC_250x760:4375847
In: FB_E00_OKFB
Type - PredefinedType: BEAM
Type - Sonstige - Kategorie: Skelettbau; Familienname: WS_CBM_UPST_REC
Type - Bemaßungen - Height: 0.76 m; Höhe: 0.76 m; WS_HEIGHT: 0.76 m; WS_WIDTH: 0.25 m
Type - ID-Daten - Typname: CBM_UPST_REC_250x760; WS_COMMENT_DIMENSION: ÜZ 25/76cm
Type - Materialien und Oberflächen - Tragendes Material: WS_CONCRETE_REINFORCED
Type - Tragwerk - Querschnittsform: 0
Type - Pset_BeamCommon - LoadBearing: yes
Material: WS_CONCRETE_REINFORCED
Pset_BeamCommon - IsExternal: no; Slope: 0 deg; Reference: CBM_UPST_REC_250x760; Span: 3.945 m
Pset_QuantityTakeOff - Reference: CBM_UPST_REC_250x760; sets with these values: 2
Sonstige - Familie: WS_CBM_UPST_REC; Familie und Typ: WS_CBM_UPST_REC: CBM_UPST_REC_250x760; Typ: CBM_UPST_REC_250x760; Typ-ID: 3713280; WS_END_EXTENSION_CALCULATED: 3 m; WS_START_EXTENSION_CALCULATED: 3 m
Abhängigkeiten - Endebenenversatz: 0 m; Querschnittdrehung: 0 deg; Startebenenversatz: 0 m; Ausrichtung: Normal; Referenzebene: Dü_EG_UKRD_+3,85; Arbeitsebene: Ebene : Dü_EG_UKRD_+3,85; Höhe Referenzebene: 3.85 m
Konstruktion - WS_END_EXTENSION: 0 m; WS_START_EXTENSION: 0 m
Bemaßungen - Höhe oben: 4.61 m; Höhe unten: 3.85 m; Länge: 3.945 m; Volumen: 0.399287 m3
ID-Daten - Hat Verknüpfung: no; WS_COMMENT_MATERIAL: C25/30 RC; WS_POSITIONNUMBER: 004; WS_TYPE_BUILDING_ELEMENT: B
Phasen - Phase erstellt: Phase 1
Tragwerk - Betonüberdeckung - Andere Flächen: Bewehrungsüberdeckung 1 <25 mm>; Betonüberdeckung - Obere Fläche: Bewehrungsüberdeckung 1 <25 mm>; Tragwerksverwendung: Sonstige; Schnittlänge: 3.695 m
Text - WS_LEVEL: 00
Geometrische Position - y-Ausrichtung: Ursprung; y-Versatzwert: 0 m; yz-Ausrichtung: Einheitlich; Verbindungsstatus: Beide Verbindungen aktiviert; z-Ausrichtung: Unten; z-Versatzwert: 0 m

# IfcBeam: WS_CBM_UPST_REC:CBM_UPST_REC_250x835, WS_CBM_UPST_REC:CBM_UPST_REC_250x835:3716441
In: FB_E00_OKFB
Type - PredefinedType: BEAM
Type - Sonstige - Kategorie: Skelettbau; Familienname: WS_CBM_UPST_REC
Type - Bemaßungen - Height: 0.835 m; Höhe: 0.835 m; WS_HEIGHT: 0.835 m; WS_WIDTH: 0.25 m
Type - ID-Daten - Typname: CBM_UPST_REC_250x835; WS_COMMENT_DIMENSION: ÜZ 25/83,5cm
Type - Materialien und Oberflächen - Tragendes Material: WS_CONCRETE_REINFORCED
Type - Tragwerk - Querschnittsform: 0
Type - Pset_BeamCommon - LoadBearing: yes
Material: WS_CONCRETE_REINFORCED
Pset_BeamCommon - IsExternal: no; Slope: 0 deg; Reference: CBM_UPST_REC_250x835; Span: 4.10712 m
Pset_QuantityTakeOff - Reference: CBM_UPST_REC_250x835; sets with these values: 2
Sonstige - Familie: WS_CBM_UPST_REC; Familie und Typ: WS_CBM_UPST_REC: CBM_UPST_REC_250x835; Typ: CBM_UPST_REC_250x835; Typ-ID: 3716195; WS_END_EXTENSION_CALCULATED: 3 m; WS_START_EXTENSION_CALCULATED: 3.315 m
Abhängigkeiten - Endebenenversatz: 0 m; Querschnittdrehung: 0 deg; Startebenenversatz: 0 m; Ausrichtung: Normal; Referenzebene: Dü_EG_UKRD_+3,43; Arbeitsebene: Ebene : Dü_EG_UKRD_+3,43; Höhe Referenzebene: 3.43 m
Konstruktion - WS_END_EXTENSION: 0 m; WS_START_EXTENSION: 0.315 m
Bemaßungen - Höhe oben: 4.265 m; Höhe unten: 3.43 m; Länge: 4.10712 m; Volumen: 0.595979 m3
ID-Daten - Hat Verknüpfung: no; WS_COMMENT_MATERIAL: C25/30 RC; WS_POSITIONNUMBER: 106; WS_TYPE_BUILDING_ELEMENT: W
Phasen - Phase erstellt: Phase 1
Tragwerk - Betonüberdeckung - Andere Flächen: Bewehrungsüberdeckung 1 <25 mm>; Betonüberdeckung - Obere Fläche: Bewehrungsüberdeckung 1 <25 mm>; Tragwerksverwendung: Sonstige; Schnittlänge: 4.25712 m
Text - WS_LEVEL: 00
Geometrische Position - y-Ausrichtung: Ursprung; y-Versatzwert: 0 m; yz-Ausrichtung: Einheitlich; Verbindungsstatus: Beide Verbindungen aktiviert; z-Ausrichtung: Unten; z-Versatzwert: 0 m

# IfcBeam: WS_CBM_UPST_REC:CBM_UPST_REC_250x880, WS_CBM_UPST_REC:CBM_UPST_REC_250x880:4444293
In: FB_E00_OKFB
Type - PredefinedType: BEAM
Type - Sonstige - Kategorie: Skelettbau; Familienname: WS_CBM_UPST_REC
Type - Bemaßungen - Height: 0.88 m; Höhe: 0.88 m; WS_HEIGHT: 0.88 m; WS_WIDTH: 0.25 m
Type - ID-Daten - Typname: CBM_UPST_REC_250x880; WS_COMMENT_DIMENSION: ÜZ 25/88cm
Type - Materialien und Oberflächen - Tragendes Material: WS_CONCRETE_REINFORCED
Type - Tragwerk - Querschnittsform: 0
Type - Pset_BeamCommon - LoadBearing: yes
Material: WS_CONCRETE_REINFORCED
Pset_BeamCommon - IsExternal: no; Slope: 0 deg; Reference: CBM_UPST_REC_250x880; Span: 3.8 m
Pset_QuantityTakeOff - Reference: CBM_UPST_REC_250x880; sets with these values: 2
Sonstige - Familie: WS_CBM_UPST_REC; Familie und Typ: WS_CBM_UPST_REC: CBM_UPST_REC_250x880; Typ: CBM_UPST_REC_250x880; Typ-ID: 4444380; WS_END_EXTENSION_CALCULATED: 3 m; WS_START_EXTENSION_CALCULATED: 3 m
Abhängigkeiten - Endebenenversatz: 0 m; Querschnittdrehung: 0 deg; Startebenenversatz: 0 m; Ausrichtung: Normal; Referenzebene: Dü_EG_UKRD_+3,43; Arbeitsebene: Ebene : Dü_EG_UKRD_+3,43; Höhe Referenzebene: 3.43 m
Konstruktion - WS_END_EXTENSION: 0 m; WS_START_EXTENSION: 0 m
Bemaßungen - Höhe oben: 4.31 m; Höhe unten: 3.43 m; Länge: 3.8 m; Volumen: 0.5403 m3
ID-Daten - Hat Verknüpfung: no; WS_COMMENT_MATERIAL: C25/30 RC
Phasen - Phase erstellt: Phase 1
Tragwerk - Betonüberdeckung - Andere Flächen: Bewehrungsüberdeckung 1 <25 mm>; Betonüberdeckung - Obere Fläche: Bewehrungsüberdeckung 1 <25 mm>; Tragwerksverwendung: Sonstige; Schnittlänge: 3.8 m
Text - WS_LEVEL: 00
Geometrische Position - Verbindungsstatus: Eine oder zwei Verbindungen deaktiviert; y-Ausrichtung: Ursprung; y-Versatzwert: 0 m; yz-Ausrichtung: Einheitlich; z-Ausrichtung: Unten; z-Versatzwert: 0 m

# IfcBeam: WS_CBM_UPST_REC:CBM_UPST_REC_300x605, WS_CBM_UPST_REC:CBM_UPST_REC_300x605:3716240
In: FB_E00_OKFB
Type - PredefinedType: BEAM
Type - Sonstige - Kategorie: Skelettbau; Familienname: WS_CBM_UPST_REC
Type - Bemaßungen - Height: 0.605 m; Höhe: 0.605 m; WS_HEIGHT: 0.605 m; WS_WIDTH: 0.3 m
Type - ID-Daten - Typname: CBM_UPST_REC_300x605; WS_COMMENT_DIMENSION: Attika
Type - Materialien und Oberflächen - Tragendes Material: WS_CONCRETE_REINFORCED
Type - Tragwerk - Querschnittsform: 0
Type - Pset_BeamCommon - LoadBearing: yes
Material: WS_CONCRETE_REINFORCED
Pset_BeamCommon - IsExternal: no; Slope: 0 deg; Reference: CBM_UPST_REC_300x605; Span: 6.025 m
Pset_QuantityTakeOff - Reference: CBM_UPST_REC_300x605; sets with these values: 2
Sonstige - Familie: WS_CBM_UPST_REC; Familie und Typ: WS_CBM_UPST_REC: CBM_UPST_REC_300x605; Typ: CBM_UPST_REC_300x605; Typ-ID: 4685405; WS_END_EXTENSION_CALCULATED: 3 m; WS_START_EXTENSION_CALCULATED: 3 m
Abhängigkeiten - Endebenenversatz: 0 m; Querschnittdrehung: 0 deg; Startebenenversatz: 0 m; Ausrichtung: Normal; Arbeitsebene: Ebene : Dü_EG_UKRD_+3,43; Höhe Referenzebene: 3.43 m; Referenzebene: Dü_EG_UKRD_+3,43
Konstruktion - WS_END_EXTENSION: 0 m; WS_START_EXTENSION: 0 m
Bemaßungen - Höhe oben: 4.035 m; Höhe unten: 3.43 m; Länge: 6.025 m; Volumen: 0.815505 m3
ID-Daten - Hat Verknüpfung: no; WS_COMMENT_MATERIAL: C25/30 RC; WS_POSITIONNUMBER: 005; WS_TYPE_BUILDING_ELEMENT: B
Phasen - Phase erstellt: Phase 1
Tragwerk - Betonüberdeckung - Andere Flächen: Bewehrungsüberdeckung 1 <25 mm>; Betonüberdeckung - Obere Fläche: Bewehrungsüberdeckung 1 <25 mm>; Betonüberdeckung - Untere Fläche: Bewehrungsüberdeckung 1 <25 mm>; Tragwerksverwendung: Sonstige; Schnittlänge: 6.275 m
Text - WS_LEVEL: 00
Geometrische Position - y-Ausrichtung: Ursprung; y-Versatzwert: 0 m; yz-Ausrichtung: Einheitlich; Verbindungsstatus: Beide Verbindungen aktiviert; z-Ausrichtung: Unten; z-Versatzwert: 0 m

# IfcBeam: WS_FDN_REC:FDN_REC_1500x650_WT (2)
In: FB_U01_OKFB
Type - PredefinedType: BEAM
Type - Sonstige - Kategorie: Skelettbau; Familienname: WS_FDN_REC
Type - Bemaßungen - Height: 0.65 m; Höhe: 0.65 m; WS_HEIGHT: 0.65 m; WS_WIDTH: 1.5 m
Type - ID-Daten - Typname: FDN_REC_1500x650_WT; WS_COMMENT_DIMENSION: FU-ST 150/65cm
Type - Materialien und Oberflächen - Tragendes Material: WS_CONCRETE_REINFORCED_WATERTIGHT
Type - Tragwerk - Querschnittsform: 0
Type - Pset_BeamCommon - LoadBearing: yes
Material: WS_CONCRETE_REINFORCED_WATERTIGHT
Pset_BeamCommon - IsExternal: no; Slope: 0 deg; Reference: FDN_REC_1500x650_WT
Pset_QuantityTakeOff - Reference: FDN_REC_1500x650_WT; sets with these values: 2
Sonstige - Familie: WS_FDN_REC; Familie und Typ: WS_FDN_REC: FDN_REC_1500x650_WT; Typ: FDN_REC_1500x650_WT; Typ-ID: 3903142; WS_END_EXTENSION_CALCULATED: 3 m; WS_START_EXTENSION_CALCULATED: 3 m
Abhängigkeiten - Endebenenversatz: 0 m; Querschnittdrehung: 0 deg; Startebenenversatz: 0 m; Ausrichtung: Normal
Konstruktion - WS_END_EXTENSION: 0 m; WS_START_EXTENSION: 0 m
ID-Daten - Hat Verknüpfung: no; WS_COMMENT_MATERIAL: C25/30 WU; WS_TYPE_BUILDING_ELEMENT: F
Phasen - Phase erstellt: Phase 1
Tragwerk - Betonüberdeckung - Andere Flächen: Bewehrungsüberdeckung 1 <25 mm>; Betonüberdeckung - Untere Fläche: Bewehrungsüberdeckung 1 <25 mm>
Geometrische Position - y-Ausrichtung: Ursprung; y-Versatzwert: 0 m; yz-Ausrichtung: Einheitlich; z-Ausrichtung: Oben; Verbindungsstatus: Beide Verbindungen aktiviert; z-Versatzwert: 0 m
Name (WS_FDN_REC:FDN_REC_1500x650_WT:...) | Span (m) = Länge (m) | Referenzebene | Arbeitsebene | Höhe Referenzebene (m) = Höhe oben (m) | Höhe unten (m) | Volumen (m3) | WS_POSITIONNUMBER | Tragwerksverwendung | Schnittlänge (m) | WS_LEVEL
3718978 | 31.875 | Dü_U01_OKRD_-0,12 | Ebene : Dü_U01_OKRD_-0,12 | -0.12 | -0.77 | 17.6937 | 005 | Sonstige | 30.8495 | U1
3795049 | 13.8 | BP_UG1_OKBP_-3,87 | Ebene : BP_UG1_OKBP_-3,87 | -3.87 | -4.52 | 7.29094 | 001 | Tragwerk | 14.05 | FU

# IfcBeam: WS_FDN_REC:FDN_REC_205x670 (2)
In: FB_U01_OKFB
Type - PredefinedType: BEAM
Type - Sonstige - Kategorie: Skelettbau; Familienname: WS_FDN_REC
Type - Bemaßungen - Height: 0.67 m; Höhe: 0.67 m; WS_HEIGHT: 0.67 m; WS_WIDTH: 0.205 m
Type - ID-Daten - Typname: FDN_REC_205x670; WS_COMMENT_DIMENSION: ÜZ 20,5/67cm
Type - Materialien und Oberflächen - Tragendes Material: WS_CONCRETE_REINFORCED
Type - Tragwerk - Querschnittsform: 0
Type - Pset_BeamCommon - LoadBearing: yes
Material: WS_CONCRETE_REINFORCED
Pset_BeamCommon - IsExternal: no; Slope: 0 deg; Reference: FDN_REC_205x670
Pset_QuantityTakeOff - Reference: FDN_REC_205x670; sets with these values: 2
Sonstige - Familie: WS_FDN_REC; Familie und Typ: WS_FDN_REC: FDN_REC_205x670; Typ: FDN_REC_205x670; Typ-ID: 4244128; WS_END_EXTENSION_CALCULATED: 3 m; WS_START_EXTENSION_CALCULATED: 3 m
Abhängigkeiten - Endebenenversatz: 0 m; Querschnittdrehung: 0 deg; Startebenenversatz: 0 m; Ausrichtung: Normal; Arbeitsebene: Ebene : Dü_U01_UKRD_-0,37; Höhe Referenzebene: -0.37 m; Referenzebene: Dü_U01_UKRD_-0,37
Konstruktion - WS_END_EXTENSION: 0 m; WS_START_EXTENSION: 0 m
Bemaßungen - Höhe oben: 0.3 m; Höhe unten: -0.37 m
ID-Daten - Hat Verknüpfung: no; WS_COMMENT_MATERIAL: C25/30 RC; WS_POSITIONNUMBER: 104; WS_TYPE_BUILDING_ELEMENT: W
Phasen - Phase erstellt: Phase 1
Tragwerk - Betonüberdeckung - Andere Flächen: Bewehrungsüberdeckung 1 <25 mm>; Betonüberdeckung - Obere Fläche: Bewehrungsüberdeckung 1 <25 mm>; Tragwerksverwendung: Sonstige
Text - WS_LEVEL: U1
Geometrische Position - y-Ausrichtung: Ursprung; y-Versatzwert: 0 m; yz-Ausrichtung: Einheitlich; Verbindungsstatus: Beide Verbindungen aktiviert; z-Ausrichtung: Unten; z-Versatzwert: 0 m
Name (WS_FDN_REC:FDN_REC_205x670:...) | Span (m) = Länge (m) = Schnittlänge (m) | Volumen (m3)
4244102 | 4.35 | 0.374535
4810268 | 16.29 | 1.40257 | Tragwerk - Betonüberdeckung - Untere Fläche: Bewehrungsüberdeckung 1 <25 mm>

# IfcBeam: WS_FDN_REC:FDN_REC_350x1100, WS_FDN_REC:FDN_REC_350x1100:3716911
In: FB_U01_OKFB
Type - PredefinedType: BEAM
Type - Sonstige - Kategorie: Skelettbau; Familienname: WS_FDN_REC
Type - Bemaßungen - Height: 1.1 m; Höhe: 1.1 m; WS_HEIGHT: 1.1 m; WS_WIDTH: 0.35 m
Type - ID-Daten - Typname: FDN_REC_350x1100; WS_COMMENT_DIMENSION: FU-ST 35/110cm
Type - Materialien und Oberflächen - Tragendes Material: WS_CONCRETE_REINFORCED
Type - Tragwerk - Querschnittsform: 0
Type - Pset_BeamCommon - LoadBearing: yes
Material: WS_CONCRETE_REINFORCED
Pset_BeamCommon - IsExternal: no; Slope: 0 deg; Reference: FDN_REC_350x1100; Span: 36.3 m
Pset_QuantityTakeOff - Reference: FDN_REC_350x1100; sets with these values: 2
Sonstige - Familie: WS_FDN_REC; Familie und Typ: WS_FDN_REC: FDN_REC_350x1100; Typ: FDN_REC_350x1100; Typ-ID: 3790078; WS_END_EXTENSION_CALCULATED: 3 m; WS_START_EXTENSION_CALCULATED: 3 m
Abhängigkeiten - Endebenenversatz: 0 m; Querschnittdrehung: 0 deg; Startebenenversatz: 0 m; Ausrichtung: Normal; Arbeitsebene: Ebene : Dü_U01_OKRD_-0,12; Höhe Referenzebene: -0.12 m; Referenzebene: Dü_U01_OKRD_-0,12
Konstruktion - WS_END_EXTENSION: 0 m; WS_START_EXTENSION: 0 m
Bemaßungen - Höhe oben: -0.12 m; Höhe unten: -1.22 m; Länge: 36.3 m; Volumen: 10.7992 m3
ID-Daten - Hat Verknüpfung: no; WS_COMMENT_MATERIAL: C25/30 RC; WS_POSITIONNUMBER: 016; WS_TYPE_BUILDING_ELEMENT: F
Phasen - Phase erstellt: Phase 1
Tragwerk - Betonüberdeckung - Andere Flächen: Bewehrungsüberdeckung 1 <25 mm>; Betonüberdeckung - Untere Fläche: Bewehrungsüberdeckung 1 <25 mm>; Tragwerksverwendung: Sonstige; Schnittlänge: 36.3 m
Text - WS_LEVEL: U1
Geometrische Position - y-Ausrichtung: Ursprung; y-Versatzwert: 0 m; yz-Ausrichtung: Einheitlich; z-Ausrichtung: Oben; Verbindungsstatus: Beide Verbindungen aktiviert; z-Versatzwert: 0 m

# IfcBeam: WS_FDN_REC:FDN_REC_500x1100 (4)
Type - PredefinedType: BEAM
Type - Sonstige - Kategorie: Skelettbau; Familienname: WS_FDN_REC
Type - Bemaßungen - Height: 1.1 m; Höhe: 1.1 m; WS_HEIGHT: 1.1 m; WS_WIDTH: 0.5 m
Type - ID-Daten - Typname: FDN_REC_500x1100; WS_COMMENT_DIMENSION: FU-ST 50/110cm
Type - Materialien und Oberflächen - Tragendes Material: WS_CONCRETE_REINFORCED
Type - Tragwerk - Querschnittsform: 0
Type - Pset_BeamCommon - LoadBearing: yes
Material: WS_CONCRETE_REINFORCED
Pset_BeamCommon - IsExternal: no; Slope: 0 deg; Reference: FDN_REC_500x1100
Pset_QuantityTakeOff - Reference: FDN_REC_500x1100; sets with these values: 2
Sonstige - Familie: WS_FDN_REC; Familie und Typ: WS_FDN_REC: FDN_REC_500x1100; Typ: FDN_REC_500x1100; Typ-ID: 3792184; WS_END_EXTENSION_CALCULATED: 3 m; WS_START_EXTENSION_CALCULATED: 3 m
Abhängigkeiten - Endebenenversatz: 0 m; Querschnittdrehung: 0 deg; Startebenenversatz: 0 m; Ausrichtung: Normal
Konstruktion - WS_END_EXTENSION: 0 m; WS_START_EXTENSION: 0 m
ID-Daten - Hat Verknüpfung: no; WS_COMMENT_MATERIAL: C25/30 RC; WS_TYPE_BUILDING_ELEMENT: F
Phasen - Phase erstellt: Phase 1
Tragwerk - Betonüberdeckung - Andere Flächen: Bewehrungsüberdeckung 1 <25 mm>; Betonüberdeckung - Untere Fläche: Bewehrungsüberdeckung 1 <25 mm>; Tragwerksverwendung: Sonstige
Text - WS_LEVEL: U1
Geometrische Position - y-Ausrichtung: Ursprung; y-Versatzwert: 0 m; yz-Ausrichtung: Einheitlich; z-Ausrichtung: Oben; z-Versatzwert: 0 m
Name (WS_FDN_REC:FDN_REC_500x1100:...) | In | Span (m) = Länge (m) | Arbeitsebene | Höhe Referenzebene (m) = Höhe oben (m) | Referenzebene | Höhe unten (m) | Volumen (m3) | WS_POSITIONNUMBER | Schnittlänge (m) | Verbindungsstatus
3718528 | FB_E00_OKFB | 5.47001 | Ebene : Dü_U01_OKBP_+0,78 | 0.78 | Dü_U01_OKBP_+0,78 | -0.32 | 2.22913 | 111.1 | 5.59501 | Beide Verbindungen aktiviert
3718580 | FB_E00_OKFB | 3.785 | Ebene : Dü_U01_OKBP_+0,78 | 0.78 | Dü_U01_OKBP_+0,78 | -0.32 | 1.60862 | 110 | 3.785 | Eine oder zwei Verbindungen deaktiviert
3718823 | FB_E00_OKFB | 2.44001 | Ebene : Dü_U01_OKBP_+0,78 | 0.78 | Dü_U01_OKBP_+0,78 | -0.32 | 0.930753 | 110 | 2.19001 | Beide Verbindungen aktiviert
3792157 | FB_U01_OKFB | 2.825 | Ebene : Dü_U01_OKRD_-0,12 | -0.12 | Dü_U01_OKRD_-0,12 | -1.22 | 1.12625 | 015 | 2.65 | Beide Verbindungen aktiviert

# IfcBeam: WS_FDN_REC:FDN_REC_500x650, WS_FDN_REC:FDN_REC_500x650:4218941
In: FB_U01_OKFB
Type - PredefinedType: BEAM
Type - Sonstige - Kategorie: Skelettbau; Familienname: WS_FDN_REC
Type - Bemaßungen - Height: 0.65 m; Höhe: 0.65 m; WS_HEIGHT: 0.65 m; WS_WIDTH: 0.5 m
Type - ID-Daten - Typname: FDN_REC_500x650; WS_COMMENT_DIMENSION: FU-ST 50/65cm
Type - Materialien und Oberflächen - Tragendes Material: WS_CONCRETE_REINFORCED
Type - Tragwerk - Querschnittsform: 0
Type - Pset_BeamCommon - LoadBearing: yes
Material: WS_CONCRETE_REINFORCED
Pset_BeamCommon - IsExternal: no; Slope: 0 deg; Reference: FDN_REC_500x650; Span: 5.4 m
Pset_QuantityTakeOff - Reference: FDN_REC_500x650; sets with these values: 2
Sonstige - Familie: WS_FDN_REC; Familie und Typ: WS_FDN_REC: FDN_REC_500x650; Typ: FDN_REC_500x650; Typ-ID: 3791940; WS_END_EXTENSION_CALCULATED: 3 m; WS_START_EXTENSION_CALCULATED: 3 m
Abhängigkeiten - Endebenenversatz: 0 m; Querschnittdrehung: 0 deg; Startebenenversatz: 0 m; Ausrichtung: Normal; Referenzebene: Dü_U01_OKRD_-0,12; Arbeitsebene: Ebene : Dü_U01_OKRD_-0,12; Höhe Referenzebene: -0.12 m
Konstruktion - WS_END_EXTENSION: 0 m; WS_START_EXTENSION: 0 m
Bemaßungen - Höhe oben: -0.12 m; Höhe unten: -0.77 m; Länge: 5.4 m; Volumen: 1.009 m3
ID-Daten - Hat Verknüpfung: no; WS_COMMENT_MATERIAL: C25/30 RC; WS_POSITIONNUMBER: 015; WS_TYPE_BUILDING_ELEMENT: F
Phasen - Phase erstellt: Phase 1
Tragwerk - Betonüberdeckung - Andere Flächen: Bewehrungsüberdeckung 1 <25 mm>; Betonüberdeckung - Untere Fläche: Bewehrungsüberdeckung 1 <25 mm>; Tragwerksverwendung: Sonstige; Schnittlänge: 5.045 m
Text - WS_LEVEL: U1
Geometrische Position - y-Ausrichtung: Ursprung; y-Versatzwert: 0 m; yz-Ausrichtung: Einheitlich; z-Ausrichtung: Oben; Verbindungsstatus: Beide Verbindungen aktiviert; z-Versatzwert: 0 m

# IfcBeam: WS_FDN_REC:FDN_REC_500x650_WT, WS_FDN_REC:FDN_REC_500x650_WT:3717625
In: FB_U01_OKFB
Type - PredefinedType: BEAM; Material: WS_CONCRETE_REINFORCED_WATERTIGHT
Type - Sonstige - Kategorie: Skelettbau; Familienname: WS_FDN_REC
Type - Bemaßungen - Height: 0.65 m; Höhe: 0.65 m; WS_HEIGHT: 0.65 m; WS_WIDTH: 0.5 m
Type - ID-Daten - Typname: FDN_REC_500x650_WT; WS_COMMENT_DIMENSION: FU-ST 50/65cm
Type - Materialien und Oberflächen - Tragendes Material: WS_CONCRETE_REINFORCED_WATERTIGHT
Type - Tragwerk - Querschnittsform: 0
Type - Pset_BeamCommon - LoadBearing: yes
Pset_BeamCommon - IsExternal: no; Slope: 0 deg; Reference: FDN_REC_500x650_WT; Span: 48.254 m
Pset_QuantityTakeOff - Reference: FDN_REC_500x650_WT; sets with these values: 2
Sonstige - Familie: WS_FDN_REC; Familie und Typ: WS_FDN_REC: FDN_REC_500x650_WT; Typ: FDN_REC_500x650_WT; Typ-ID: 4042624; WS_END_EXTENSION_CALCULATED: 3 m; WS_START_EXTENSION_CALCULATED: 3 m
Abhängigkeiten - Endebenenversatz: 0 m; Querschnittdrehung: 0 deg; Startebenenversatz: 0 m; Ausrichtung: Normal; Referenzebene: Dü_U01_OKRD_-0,12; Arbeitsebene: Ebene : Dü_U01_OKRD_-0,12; Höhe Referenzebene: -0.12 m
Konstruktion - WS_END_EXTENSION: 0 m; WS_START_EXTENSION: 0 m
Bemaßungen - Höhe oben: -0.12 m; Höhe unten: -0.77 m; Länge: 48.254 m; Volumen: 8.82919 m3
ID-Daten - Hat Verknüpfung: no; WS_COMMENT_MATERIAL: C25/30 WU; WS_POSITIONNUMBER: 112.2; WS_TYPE_BUILDING_ELEMENT: F
Phasen - Phase erstellt: Phase 1
Tragwerk - Betonüberdeckung - Andere Flächen: Bewehrungsüberdeckung 1 <25 mm>; Betonüberdeckung - Obere Fläche: Bewehrungsüberdeckung 1 <25 mm>; Betonüberdeckung - Untere Fläche: Bewehrungsüberdeckung 1 <25 mm>; Tragwerksverwendung: Sonstige; Schnittlänge: 47.879 m
Text - WS_LEVEL: U1
Geometrische Position - y-Ausrichtung: Ursprung; y-Versatzwert: 0 m; yz-Ausrichtung: Einheitlich; z-Ausrichtung: Oben; Verbindungsstatus: Beide Verbindungen aktiviert; z-Versatzwert: 0 m

# IfcBeam: WS_FDN_REC:FDN_REC_500x650_WT (13)
In: FB_U01_OKFB
Type - PredefinedType: BEAM
Type - Sonstige - Kategorie: Skelettbau; Familienname: WS_FDN_REC
Type - Bemaßungen - Height: 0.65 m; Höhe: 0.65 m; WS_HEIGHT: 0.65 m; WS_WIDTH: 0.5 m
Type - ID-Daten - Typname: FDN_REC_500x650_WT; WS_COMMENT_DIMENSION: FU-ST 50/65cm
Type - Materialien und Oberflächen - Tragendes Material: WS_CONCRETE_REINFORCED_WATERTIGHT
Type - Tragwerk - Querschnittsform: 0
Type - Pset_BeamCommon - LoadBearing: yes
Material: WS_CONCRETE_REINFORCED_WATERTIGHT
Pset_BeamCommon - IsExternal: no; Slope: 0 deg; Reference: FDN_REC_500x650_WT
Pset_QuantityTakeOff - Reference: FDN_REC_500x650_WT; sets with these values: 2
Sonstige - Familie: WS_FDN_REC; Familie und Typ: WS_FDN_REC: FDN_REC_500x650_WT; Typ: FDN_REC_500x650_WT; Typ-ID: 4042624; WS_END_EXTENSION_CALCULATED: 3 m; WS_START_EXTENSION_CALCULATED: 3 m
Abhängigkeiten - Endebenenversatz: 0 m; Querschnittdrehung: 0 deg; Startebenenversatz: 0 m; Ausrichtung: Normal
Konstruktion - WS_END_EXTENSION: 0 m; WS_START_EXTENSION: 0 m
ID-Daten - Hat Verknüpfung: no; WS_COMMENT_MATERIAL: C25/30 WU; WS_TYPE_BUILDING_ELEMENT: F
Phasen - Phase erstellt: Phase 1
Tragwerk - Betonüberdeckung - Andere Flächen: Bewehrungsüberdeckung 1 <25 mm>; Betonüberdeckung - Untere Fläche: Bewehrungsüberdeckung 1 <25 mm>; Tragwerksverwendung: Sonstige
Text - WS_LEVEL: U1
Geometrische Position - y-Ausrichtung: Ursprung; y-Versatzwert: 0 m; yz-Ausrichtung: Einheitlich; z-Ausrichtung: Oben; Verbindungsstatus: Beide Verbindungen aktiviert; z-Versatzwert: 0 m
Name (WS_FDN_REC:FDN_REC_500x650_WT:...) | Span (m) = Länge (m) | Referenzebene | Arbeitsebene | Höhe Referenzebene (m) = Höhe oben (m) | Höhe unten (m) | Volumen (m3) | WS_POSITIONNUMBER | Schnittlänge (m)
3717094 | 18.83 | Dü_U01_OKRD_-0,12 | Ebene : Dü_U01_OKRD_-0,12 | -0.12 | -0.77 | 3.791 | 115.1 | 18.955
3717300 | 6.025 | Dü_U01_OKRD_-0,12 | Ebene : Dü_U01_OKRD_-0,12 | -0.12 | -0.77 | 0.975 | 114 | 4.875
3717636 | 3.55501 | Dü_U01_OKRD_-0,12 | Ebene : Dü_U01_OKRD_-0,12 | -0.12 | -0.77 | 0.686001 | 113 | 3.43001
3718035 | 5.67097 | Dü_U01_OKBP_-1,22_RLT | Ebene : Dü_U01_OKBP_-1,22_RLT | -1.22 | -1.87 | 1.18919 | 112.1 | 5.94597
3718194 | 16.715 | Dü_U01_OKBP_-1,22_RLT | Ebene : Dü_U01_OKBP_-1,22_RLT | -1.22 | -1.87 | 3.298 | 111.2 | 16.49
3793288 | 8.14 | Dü_U01_OKRD_-0,12 | Ebene : Dü_U01_OKRD_-0,12 | -0.12 | -0.77 | 1.5 | 119 | 7.5
3793734 | 8.15 | Dü_U01_OKRD_-0,12 | Ebene : Dü_U01_OKRD_-0,12 | -0.12 | -0.77 | 1.5 | 118 | 7.5
3793745 | 18.655 | Dü_U01_OKRD_-0,12 | Ebene : Dü_U01_OKRD_-0,12 | -0.12 | -0.77 | 3.481 | 117 | 18.155
4428329 | 9.53001 | Dü_U01_OKBP_-1,22_RLT | Ebene : Dü_U01_OKBP_-1,22_RLT | -1.22 | -1.87 | 1.83659 | 122 | 9.68001 | Tragwerk - Betonüberdeckung - Obere Fläche: Bewehrungsüberdeckung 1 <25 mm>
4428387 | 6.35 | Dü_U01_OKBP_-1,22_RLT | Ebene : Dü_U01_OKBP_-1,22_RLT | -1.22 | -1.87 | 1.225 | 120 | 6.125
4428569 | 6.37903 | Dü_U01_OKRD_-0,12 | Ebene : Dü_U01_OKRD_-0,12 | -0.12 | -0.77 | 1.1329 | 123 | 6.00403
4428882 | 7.06 | Dü_U01_OKBP_-1,22_RLT | Ebene : Dü_U01_OKBP_-1,22_RLT | -1.22 | -1.87 | 1.362 | 121 | 6.81
4429066 | 1.055 | Dü_U01_OKBP_-1,22_RLT | Ebene : Dü_U01_OKBP_-1,22_RLT | -1.22 | -1.87 | 0.136 | 122 | 0.68

# IfcBeam: WS_FDN_REC:FDN_REC_775x650_WT, WS_FDN_REC:FDN_REC_775x650_WT:3795277
In: FB_U01_OKFB
Type - PredefinedType: BEAM
Type - Sonstige - Kategorie: Skelettbau; Familienname: WS_FDN_REC
Type - Bemaßungen - Height: 0.65 m; Höhe: 0.65 m; WS_HEIGHT: 0.65 m; WS_WIDTH: 0.775 m
Type - ID-Daten - Typname: FDN_REC_775x650_WT; WS_COMMENT_DIMENSION: FU-ST 77,5/65cm; WU-Beton
Type - Materialien und Oberflächen - Tragendes Material: WS_CONCRETE_REINFORCED_WATERTIGHT
Type - Tragwerk - Querschnittsform: 0
Type - Pset_BeamCommon - LoadBearing: yes
Material: WS_CONCRETE_REINFORCED_WATERTIGHT
Pset_BeamCommon - IsExternal: no; Slope: 0 deg; Reference: FDN_REC_775x650_WT; Span: 1.84 m
Pset_QuantityTakeOff - Reference: FDN_REC_775x650_WT; sets with these values: 2
Sonstige - Familie: WS_FDN_REC; Familie und Typ: WS_FDN_REC: FDN_REC_775x650_WT; Typ: FDN_REC_775x650_WT; Typ-ID: 4394169; WS_END_EXTENSION_CALCULATED: 3 m; WS_START_EXTENSION_CALCULATED: 3 m
Abhängigkeiten - Endebenenversatz: 0 m; Querschnittdrehung: 0 deg; Startebenenversatz: 0 m; Ausrichtung: Normal; Referenzebene: BP_UG1_OKBP_-3,87; Arbeitsebene: Ebene : BP_UG1_OKBP_-3,87; Höhe Referenzebene: -3.87 m
Konstruktion - WS_END_EXTENSION: 0 m; WS_START_EXTENSION: 0 m
Bemaßungen - Höhe oben: -3.87 m; Höhe unten: -4.52 m; Länge: 1.84 m; Volumen: 0.358312 m3
ID-Daten - Hat Verknüpfung: no; WS_COMMENT_MATERIAL: C25/30 WU; WS_POSITIONNUMBER: 001; WS_TYPE_BUILDING_ELEMENT: F
Phasen - Phase erstellt: Phase 1
Tragwerk - Betonüberdeckung - Andere Flächen: Bewehrungsüberdeckung 1 <25 mm>; Betonüberdeckung - Untere Fläche: Bewehrungsüberdeckung 1 <25 mm>; Tragwerksverwendung: Tragwerk; Schnittlänge: 1.95 m
Text - WS_LEVEL: FU
Geometrische Position - y-Ausrichtung: Ursprung; y-Versatzwert: 0 m; yz-Ausrichtung: Einheitlich; z-Ausrichtung: Oben; Verbindungsstatus: Beide Verbindungen aktiviert; z-Versatzwert: 0 m

# IfcBeam: WS_FDN_Voute:FDN_REC_250x750_Voute (3)
In: FB_U01_OKFB
Type - PredefinedType: BEAM
Type - Sonstige - Kategorie: Skelettbau; Familienname: WS_FDN_Voute
Type - Bemaßungen - Height: 0.75 m; Höhe: 0.75 m; WS_HEIGHT: 0.75 m; WS_WIDTH: 0.25 m
Type - ID-Daten - Typname: FDN_REC_250x750_Voute
Type - Materialien und Oberflächen - Tragendes Material: WS_CONCRETE_REINFORCED
Type - Tragwerk - Querschnittsform: 0
Type - Pset_BeamCommon - LoadBearing: yes
Material: WS_CONCRETE_REINFORCED
Pset_BeamCommon - IsExternal: no; Slope: 0 deg; Reference: FDN_REC_250x750_Voute
Pset_QuantityTakeOff - Reference: FDN_REC_250x750_Voute; sets with these values: 2
Sonstige - Familie: WS_FDN_Voute; Familie und Typ: WS_FDN_Voute: FDN_REC_250x750_Voute; Typ: FDN_REC_250x750_Voute; Typ-ID: 3817147; WS_END_EXTENSION_CALCULATED: 3 m; WS_START_EXTENSION_CALCULATED: 3 m
Abhängigkeiten - Endebenenversatz: 0 m; Querschnittdrehung: 0 deg; Startebenenversatz: 0 m; Ausrichtung: Normal; Referenzebene: Dü_U01_OKRD_-0,12; Arbeitsebene: Ebene : Dü_U01_OKRD_-0,12; Höhe Referenzebene: -0.12 m
Konstruktion - WS_END_EXTENSION: 0 m; WS_START_EXTENSION: 0 m
Bemaßungen - Höhe oben: -0.12 m; Höhe unten: -0.77 m
ID-Daten - Hat Verknüpfung: no; WS_COMMENT_MATERIAL: C25/30 RC; WS_POSITIONNUMBER: 003; WS_TYPE_BUILDING_ELEMENT: F
Phasen - Phase erstellt: Phase 1
Tragwerk - Betonüberdeckung - Andere Flächen: Bewehrungsüberdeckung 1 <25 mm>; Tragwerksverwendung: Tragwerk
Text - WS_LEVEL: U1
Geometrische Position - y-Ausrichtung: Ursprung; y-Versatzwert: 0 m; yz-Ausrichtung: Einheitlich; z-Ausrichtung: Oben; Verbindungsstatus: Beide Verbindungen aktiviert; z-Versatzwert: 0 m
Name (WS_FDN_Voute:FDN_REC_250x750_Voute:...) | Span (m) = Länge (m) | Volumen (m3) | Schnittlänge (m)
3819464 | 1.25659 | 0.0862661 | 1.34499
3819606 | 3.92319 | 0.305333 | 4.35
3819745 | 1.25659 | 0.0862661 | 1.34499

# IfcBeam: WS_FDN_Voute:FDN_REC_250x750_Voute_WT (11)
In: FB_U01_OKFB
Type - PredefinedType: BEAM; Material: WS_CONCRETE_REINFORCED_WATERTIGHT
Type - Sonstige - Kategorie: Skelettbau; Familienname: WS_FDN_Voute
Type - Bemaßungen - Height: 0.75 m; Höhe: 0.75 m; WS_HEIGHT: 0.75 m; WS_WIDTH: 0.25 m
Type - ID-Daten - Typname: FDN_REC_250x750_Voute_WT
Type - Materialien und Oberflächen - Tragendes Material: WS_CONCRETE_REINFORCED_WATERTIGHT
Type - Tragwerk - Querschnittsform: 0
Type - Pset_BeamCommon - LoadBearing: yes
Pset_BeamCommon - IsExternal: no; Slope: 0 deg; Reference: FDN_REC_250x750_Voute_WT
Pset_QuantityTakeOff - Reference: FDN_REC_250x750_Voute_WT; sets with these values: 2
Sonstige - Familie: WS_FDN_Voute; Familie und Typ: WS_FDN_Voute: FDN_REC_250x750_Voute_WT; Typ: FDN_REC_250x750_Voute_WT; Typ-ID: 4042904; WS_END_EXTENSION_CALCULATED: 3 m; WS_START_EXTENSION_CALCULATED: 3 m
Abhängigkeiten - Endebenenversatz: 0 m; Querschnittdrehung: 0 deg; Startebenenversatz: 0 m; Ausrichtung: Normal; Referenzebene: Dü_U01_OKRD_-0,12; Arbeitsebene: Ebene : Dü_U01_OKRD_-0,12; Höhe Referenzebene: -0.12 m
Konstruktion - WS_END_EXTENSION: 0 m; WS_START_EXTENSION: 0 m
Bemaßungen - Höhe oben: -0.12 m; Höhe unten: -0.77 m
ID-Daten - Hat Verknüpfung: no; WS_COMMENT_MATERIAL: C25/30 WU; WS_POSITIONNUMBER: 005; WS_TYPE_BUILDING_ELEMENT: F
Phasen - Phase erstellt: Phase 1
Tragwerk - Betonüberdeckung - Andere Flächen: Bewehrungsüberdeckung 1 <25 mm>; Tragwerksverwendung: Tragwerk
Text - WS_LEVEL: U1
Geometrische Position - y-Ausrichtung: Ursprung; y-Versatzwert: 0 m; yz-Ausrichtung: Einheitlich; z-Ausrichtung: Oben; Verbindungsstatus: Beide Verbindungen aktiviert; z-Versatzwert: 0 m
Name (WS_FDN_Voute:FDN_REC_250x750_Voute_WT:...) | Span (m) = Länge (m) | Volumen (m3) | Schnittlänge (m)
3816332 | 18.655 | 1.3324 | 18.155
3818139 | 18.655 | 1.3724 | 18.155
3819238 | 16.655 | 1.2924 | 16.155
3819334 | 16.68 | 1.2644 | 15.805
3969093 | 3.16655 | 0.239064 | 3.25496
3969148 | 3.16655 | 0.239064 | 3.25496
3969177 | 1.97319 | 0.149333 | 2.4
3969269 | 3.37319 | 0.261333 | 3.8
3969270 | 3.37319 | 0.261333 | 3.8
3969271 | 1.97319 | 0.149333 | 2.4
3969303 | 1.97319 | 0.149333 | 2.4

# IfcBeam: WS_SBM_L:SBM_L_100x50x6, WS_SBM_L:SBM_L_100x50x6:4558625
In: FB_E00_OKFB
Type - PredefinedType: BEAM
Type - Sonstige - Kategorie: Skelettbau; Familienname: WS_SBM_L
Type - Bemaßungen - WS_HEIGHT: 0.1 m; WS_OFFSET_1: 0.001 m; WS_OFFSET_2: 0.0005 m; WS_RADIUS_1: 0.0035 m; WS_RADIUS_2: 0.002 m; WS_THICKNESS: 0.006 m; WS_WIDTH: 0.05 m
Type - ID-Daten - OmniClass-Nummer: 23.25.30.11.14.14; OmniClass-Titel: Beams; Typname: SBM_L_100x50x6
Type - Materialien und Oberflächen - Tragendes Material: WS_STEEL
Type - Tragwerk - Querschnittsform: 0
Type - Pset_BeamCommon - LoadBearing: yes
Material: WS_STEEL
Pset_BeamCommon - IsExternal: no; Slope: 0 deg; Reference: SBM_L_100x50x6; Span: 0.240005 m
Pset_QuantityTakeOff - Reference: SBM_L_100x50x6; sets with these values: 2
Sonstige - Familie: WS_SBM_L; Familie und Typ: WS_SBM_L: SBM_L_100x50x6; Typ: SBM_L_100x50x6; Typ-ID: 4558507
Abhängigkeiten - Querschnittdrehung: 0 deg; Ausrichtung: Normal; Arbeitsebene: <nicht verknüpft>
Bemaßungen - Höhe oben: 2.594 m; Höhe unten: 2.494 m; Länge: 0.240005 m; Volumen: 0.000207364 m3
ID-Daten - Hat Verknüpfung: no
Phasen - Phase erstellt: Phase 1
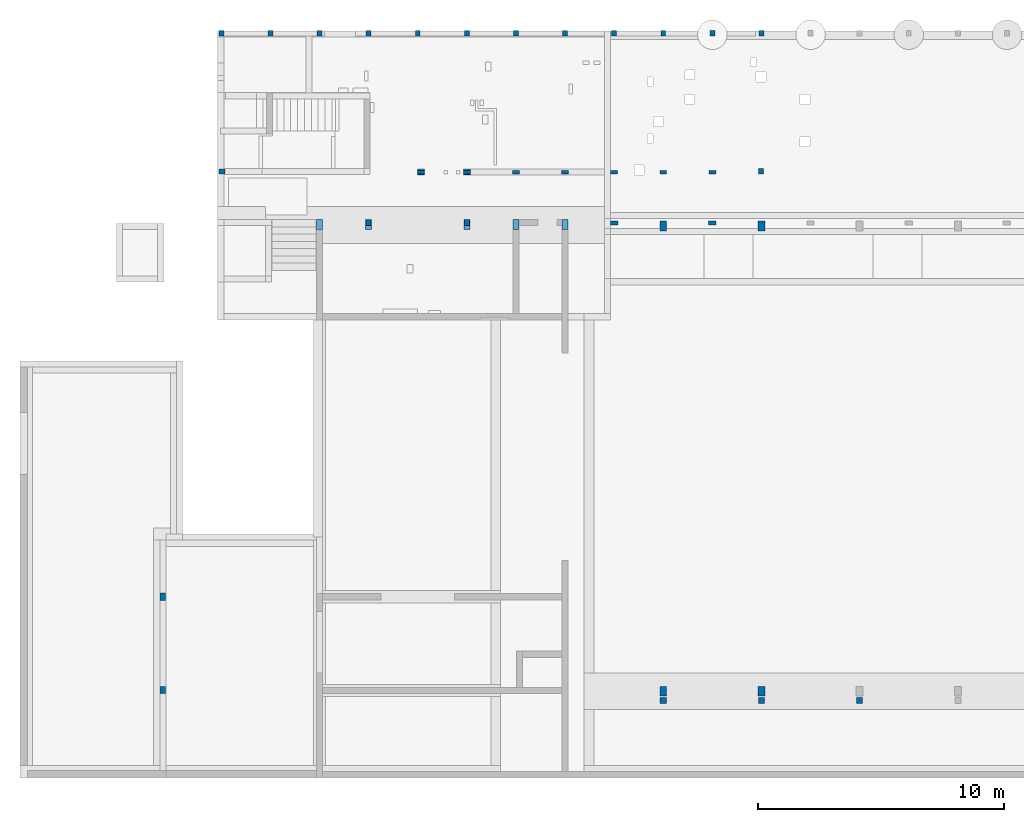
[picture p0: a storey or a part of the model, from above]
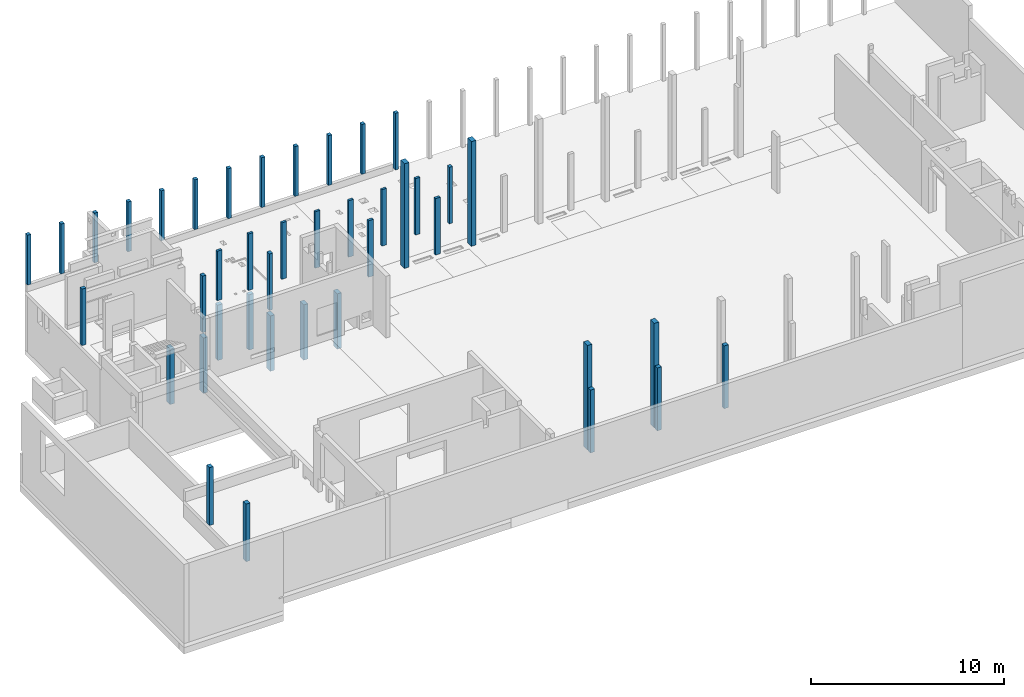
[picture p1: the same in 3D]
Properties of the parts of a building model (IFC2X3), part 2 of 6

# IfcBeam: WS_SBM_L:SBM_L_100x50x6, WS_SBM_L:SBM_L_100x50x6:4558625
Tragwerk - Tragwerksverwendung: Sonstige; Schnittlänge: 0.240005 m
Geometrische Position - y-Ausrichtung: Ursprung; y-Versatzwert: 0 m; yz-Ausrichtung: Einheitlich; z-Ausrichtung: Oben; Verbindungsstatus: Beide Verbindungen aktiviert; Endverlängerung: 0 m; Startverlängerung: 0 m; z-Versatzwert: -0.006 m

# IfcBeam: WS_TBM_GLT:TBM_GLT_120/400 (8)
In: FB_E00_OKFB
Type - PredefinedType: BEAM
Type - Sonstige - Kategorie: Skelettbau; Familienname: WS_TBM_GLT
Type - Bemaßungen - WS_HEIGHT: 0.4 m; WS_WIDTH: 0.12 m
Type - ID-Daten - Baugruppenkennzeichen: 300; OmniClass-Nummer: 23.25.30.00; OmniClass-Titel: Structural Framing Products; Typname: TBM_GLT_120/400; WS_COMMENT_DIMENSION: BSH 120/400mm
Type - Tragwerk - Querschnittsform: 0
Type - Pset_BeamCommon - LoadBearing: yes
Classification: 300 (Uniformat); Material: WS_TIMBER_GLT_0°
Pset_BeamCommon - IsExternal: no; Slope: 0 deg; Reference: TBM_GLT_120/400
Pset_QuantityTakeOff - Reference: TBM_GLT_120/400; sets with these values: 2
Sonstige - Familie: WS_TBM_GLT; Familie und Typ: WS_TBM_GLT: TBM_GLT_120/400; Typ: TBM_GLT_120/400; Typ-ID: 3802983
Abhängigkeiten - Endebenenversatz: 0 m; Querschnittdrehung: 0 deg; Startebenenversatz: 0 m; Ausrichtung: Normal; Arbeitsebene: Ebene : Dü_OG1_OKHT_+8,005_Träger OG; Höhe Referenzebene: 8.005 m; Referenzebene: Dü_OG1_OKHT_+8,005_Träger OG
Bemaßungen - Höhe oben: 8.005 m; Höhe unten: 7.605 m
ID-Daten - Hat Verknüpfung: no; WS_COMMENT_MATERIAL: GL24h; WS_POSITIONNUMBER: 013; WS_TYPE_BUILDING_ELEMENT: B
Materialien und Oberflächen - Tragendes Material: WS_TIMBER_GLT_0°
Phasen - Phase erstellt: Phase 1
Tragwerk - Tragwerksverwendung: Sonstige
Text - WS_COMMENT: OK=+8,005; WS_LEVEL: 01
Geometrische Position - y-Ausrichtung: Ursprung; y-Versatzwert: 0 m; yz-Ausrichtung: Einheitlich; z-Ausrichtung: Oben; Verbindungsstatus: Beide Verbindungen aktiviert; z-Versatzwert: 0 m; Endverlängerung: 0 m; Startverlängerung: 0 m
Name (WS_TBM_GLT:TBM_GLT_120/400:...) | Span (m) = Länge (m) | Volumen (m3) | Schnittlänge (m) | Anfangsfugenkürzung (m)
3733656 | 7.925 | 0.37656 | 7.845 | 0
3733881 | 7.925 | 0.37656 | 7.845 | 0
3733950 | 7.925 | 0.37656 | 7.845 | 0
3733960 | 7.925 | 0.37656 | 7.845 | 0
3733968 | 7.925 | 0.37656 | 7.845 | 0
3733976 | 7.925 | 0.36612 | 7.845 | 0
3733984 | 5.725 | 0.27288 | 5.725
3733992 | 5.85 | 0.27288 | 5.725 | 0

# IfcBeam: WS_TBM_GLT:TBM_GLT_150/240 (2)
In: FB_E00_OKFB
Type - PredefinedType: BEAM
Type - Sonstige - Kategorie: Skelettbau; Familienname: WS_TBM_GLT
Type - Bemaßungen - WS_HEIGHT: 0.24 m; WS_WIDTH: 0.15 m
Type - ID-Daten - Baugruppenkennzeichen: 300; OmniClass-Nummer: 23.25.30.00; OmniClass-Titel: Structural Framing Products; Typenkommentare: TBM_SST_240x150; Typname: TBM_GLT_150/240; WS_COMMENT_DIMENSION: BSH 150/240mm
Type - Tragwerk - Querschnittsform: 0
Type - Pset_BeamCommon - LoadBearing: yes
Classification: 300 (Uniformat); Material: WS_TIMBER_GLT_0°
Pset_BeamCommon - IsExternal: no; Slope: 0 deg; Reference: TBM_GLT_150/240; Span: 1.575 m
Pset_QuantityTakeOff - Reference: TBM_GLT_150/240; sets with these values: 2
Sonstige - Familie: WS_TBM_GLT; Familie und Typ: WS_TBM_GLT: TBM_GLT_150/240; Typ: TBM_GLT_150/240; Typ-ID: 3780422
Abhängigkeiten - Endebenenversatz: 0 m; Querschnittdrehung: 0 deg; Startebenenversatz: 0 m; Ausrichtung: Normal; Referenzebene: Dü_EG_OKHT_+3,765_Auskragung; Arbeitsebene: Ebene : Dü_EG_OKHT_+3,765_Auskragung; Höhe Referenzebene: 3.765 m
Bemaßungen - Höhe oben: 3.765 m; Höhe unten: 3.525 m; Länge: 1.575 m; Volumen: 0.0535158 m3
ID-Daten - Hat Verknüpfung: no; WS_COMMENT_MATERIAL: GL28h; WS_TYPE_BUILDING_ELEMENT: B
Materialien und Oberflächen - Tragendes Material: WS_TIMBER_GLT_0°
Phasen - Phase erstellt: Phase 1
Tragwerk - Tragwerksverwendung: Sonstige; Schnittlänge: 1.575 m
Text - WS_COMMENT: OK=+3,750; WS_LEVEL: 00
Geometrische Position - y-Ausrichtung: Ursprung; y-Versatzwert: 0 m; yz-Ausrichtung: Einheitlich; z-Ausrichtung: Oben; Verbindungsstatus: Beide Verbindungen aktiviert; z-Versatzwert: 0 m; Endverlängerung: 0 m; Startverlängerung: 0 m
Name (WS_TBM_GLT:TBM_GLT_150/240:...) | WS_POSITIONNUMBER
3751456 | 027
3751544 | 028

# IfcBeam: WS_TBM_GLT:TBM_GLT_160/400 (2)
In: FB_E00_OKFB
Type - PredefinedType: BEAM
Type - Sonstige - Kategorie: Skelettbau; Familienname: WS_TBM_GLT
Type - Bemaßungen - WS_HEIGHT: 0.4 m; WS_WIDTH: 0.16 m
Type - ID-Daten - Baugruppenkennzeichen: 300; OmniClass-Nummer: 23.25.30.00; OmniClass-Titel: Structural Framing Products; Typname: TBM_GLT_160/400; WS_COMMENT_DIMENSION: BSH 160/400mm
Type - Tragwerk - Querschnittsform: 0
Type - Pset_BeamCommon - LoadBearing: yes
Classification: 300 (Uniformat); Material: WS_TIMBER_GLT_0°
Pset_BeamCommon - IsExternal: no; Slope: 0 deg; Reference: TBM_GLT_160/400
Pset_QuantityTakeOff - Reference: TBM_GLT_160/400; sets with these values: 2
Sonstige - Familie: WS_TBM_GLT; Familie und Typ: WS_TBM_GLT: TBM_GLT_160/400; Typ: TBM_GLT_160/400; Typ-ID: 3802967
Abhängigkeiten - Endebenenversatz: 0 m; Querschnittdrehung: 0 deg; Startebenenversatz: 0 m; Ausrichtung: Normal; Referenzebene: Dü_OG1_OKHT_+8,005_Träger OG; Arbeitsebene: Ebene : Dü_OG1_OKHT_+8,005_Träger OG; Höhe Referenzebene: 8.005 m
Bemaßungen - Höhe oben: 8.005 m; Höhe unten: 7.605 m
ID-Daten - Hat Verknüpfung: no; WS_COMMENT_MATERIAL: GL24h; WS_POSITIONNUMBER: 017; WS_TYPE_BUILDING_ELEMENT: B
Materialien und Oberflächen - Tragendes Material: WS_TIMBER_GLT_0°
Phasen - Phase erstellt: Phase 1
Tragwerk - Tragwerksverwendung: Sonstige
Text - WS_COMMENT: OK=+8,005; WS_LEVEL: 01
Geometrische Position - y-Ausrichtung: Ursprung; y-Versatzwert: 0 m; yz-Ausrichtung: Einheitlich; z-Ausrichtung: Oben; Verbindungsstatus: Beide Verbindungen aktiviert; z-Versatzwert: 0 m; Startverlängerung: 0 m
Name (WS_TBM_GLT:TBM_GLT_160/400:...) | Span (m) = Länge (m) | Volumen (m3) | Schnittlänge (m) | Endverlängerung (m)
3866061 | 5.36 | 0.33408 | 5.22 | -0.08 | Geometrische Position - Endfugenkürzung: 0 m
3867652 | 11.39 | 0.732803 | 11.45 | 0

# IfcBeam: WS_TBM_GLT:TBM_GLT_160/480 (12)
In: FB_E00_OKFB
Type - PredefinedType: BEAM
Type - Sonstige - Kategorie: Skelettbau; Familienname: WS_TBM_GLT
Type - Bemaßungen - WS_HEIGHT: 0.48 m; WS_WIDTH: 0.16 m
Type - ID-Daten - Baugruppenkennzeichen: 300; OmniClass-Nummer: 23.25.30.00; OmniClass-Titel: Structural Framing Products; Typname: TBM_GLT_160/480; WS_COMMENT_DIMENSION: BSH 160/480mm
Type - Tragwerk - Querschnittsform: 0
Type - Pset_BeamCommon - LoadBearing: yes
Classification: 300 (Uniformat); Material: WS_TIMBER_GLT_0°
Pset_BeamCommon - IsExternal: no; Slope: 0 deg; Reference: TBM_GLT_160/480; Span: 2 m
Pset_QuantityTakeOff - Reference: TBM_GLT_160/480; sets with these values: 2
Sonstige - Familie: WS_TBM_GLT; Familie und Typ: WS_TBM_GLT: TBM_GLT_160/480; Typ: TBM_GLT_160/480; Typ-ID: 3878350
Abhängigkeiten - Endebenenversatz: 0 m; Querschnittdrehung: 0 deg; Startebenenversatz: 0 m; Ausrichtung: Normal; Referenzebene: Dü_EG_OKHT_+3,935_Foyer 1; Arbeitsebene: Ebene : Dü_EG_OKHT_+3,935_Foyer 1; Höhe Referenzebene: 3.935 m
Bemaßungen - Höhe oben: 3.935 m; Höhe unten: 3.455 m; Länge: 2 m
ID-Daten - Hat Verknüpfung: no; WS_COMMENT_MATERIAL: GL24h; WS_POSITIONNUMBER: 025; WS_TYPE_BUILDING_ELEMENT: B
Materialien und Oberflächen - Tragendes Material: WS_TIMBER_GLT_0°
Phasen - Phase erstellt: Phase 1
Tragwerk - Tragwerksverwendung: Sonstige
Text - WS_COMMENT: OK=+3,935; WS_LEVEL: 00
Geometrische Position - y-Ausrichtung: Ursprung; y-Versatzwert: 0 m; yz-Ausrichtung: Einheitlich; z-Ausrichtung: Oben; Verbindungsstatus: Beide Verbindungen aktiviert; z-Versatzwert: 0 m; Endverlängerung: -0.3 m; Startverlängerung: -0.3 m
Name (WS_TBM_GLT:TBM_GLT_160/480:...) | Volumen (m3) | Schnittlänge (m) | Endfugenkürzung (m) | Anfangsfugenkürzung (m)
3731081 | 0.131328 | 1.71 | 0 | -0.01
3919917 | 0.128256 | 1.67 | 0 | 0 | Tragwerk - Endverbindung - Typ: Endhöhe
3921274 | 0.131328 | 1.71 | 0 | -0.01
3921276 | 0.131328 | 1.71 | -0.01 | 0
3921292 | 0.131328 | 1.71 | 0 | -0.01
3921294 | 0.131328 | 1.71 | -0.01 | 0
3921308 | 0.131328 | 1.71 | 0 | -0.01
3921310 | 0.131328 | 1.71 | -0.01 | 0
3921326 | 0.131328 | 1.71 | 0 | -0.01
3921328 | 0.131328 | 1.71 | -0.01 | 0
3921342 | 0.13248 | 1.725 | 0 | -0.0249999
3921344 | 0.131328 | 1.71 | -0.01 | 0

# IfcBeam: WS_TBM_GLT:TBM_GLT_180/320 (4)
In: FB_E00_OKFB
Type - PredefinedType: BEAM
Type - Sonstige - Kategorie: Skelettbau; Familienname: WS_TBM_GLT
Type - Bemaßungen - WS_HEIGHT: 0.32 m; WS_WIDTH: 0.18 m
Type - ID-Daten - Baugruppenkennzeichen: 300; OmniClass-Nummer: 23.25.30.00; OmniClass-Titel: Structural Framing Products; Typname: TBM_GLT_180/320; WS_COMMENT_DIMENSION: BSH 180/320mm
Type - Tragwerk - Querschnittsform: 0
Type - Pset_BeamCommon - LoadBearing: yes
Classification: 300 (Uniformat); Material: WS_TIMBER_GLT_0°
Pset_BeamCommon - IsExternal: no; Slope: 0 deg; Reference: TBM_GLT_180/320
Pset_QuantityTakeOff - Reference: TBM_GLT_180/320; sets with these values: 2
Sonstige - Familie: WS_TBM_GLT; Familie und Typ: WS_TBM_GLT: TBM_GLT_180/320; Typ: TBM_GLT_180/320; Typ-ID: 3724892
Abhängigkeiten - Endebenenversatz: 0 m; Querschnittdrehung: 0 deg; Startebenenversatz: 0 m; Ausrichtung: Normal; Referenzebene: Dü_OG1_OKHT_+7,780_Binder; Arbeitsebene: Ebene : Dü_OG1_OKHT_+7,780_Binder; Höhe Referenzebene: 7.78 m
Bemaßungen - Höhe oben: 7.78 m; Höhe unten: 7.46 m
ID-Daten - Hat Verknüpfung: no; WS_COMMENT_MATERIAL: GL24c; WS_POSITIONNUMBER: 024; WS_TYPE_BUILDING_ELEMENT: B
Materialien und Oberflächen - Tragendes Material: WS_TIMBER_GLT_0°
Phasen - Phase erstellt: Phase 1
Tragwerk - Tragwerksverwendung: Sonstige
Text - WS_COMMENT: OK=+7,78; WS_LEVEL: 01
Geometrische Position - y-Ausrichtung: Ursprung; y-Versatzwert: 0 m; yz-Ausrichtung: Einheitlich; z-Ausrichtung: Oben; Verbindungsstatus: Beide Verbindungen aktiviert; z-Versatzwert: 0 m; Startverlängerung: 0 m
Name (WS_TBM_GLT:TBM_GLT_180/320:...) | Span (m) = Länge (m) | Volumen (m3) | Schnittlänge (m) | Endverlängerung (m) | Anfangsfugenkürzung (m) | Endfugenkürzung (m)
3724859 | 3.97 | 0.22608 | 3.925 | 0 | 0 | -0.16 | Tragwerk - Endverbindung - Typ: Endhöhe
3725025 | 3.82005 | 0.217443 | 3.77505 | 0 | -0.16 | 0 | Tragwerk - Anfangsverbindung - Typ: Endhöhe
3725664 | 3.97 | 0.22608 | 3.925 | 0.08 | 0
3725665 | 3.82005 | 0.217443 | 3.77505 | 0 | -0.16 | 0 | Tragwerk - Anfangsverbindung - Typ: Endhöhe

# IfcBeam: WS_TBM_GLT:TBM_GLT_180/800, WS_TBM_GLT:TBM_GLT_180/800:3801966
In: FB_E00_OKFB
Type - PredefinedType: BEAM
Type - Sonstige - Kategorie: Skelettbau; Familienname: WS_TBM_GLT
Type - Bemaßungen - WS_HEIGHT: 0.8 m; WS_WIDTH: 0.18 m
Type - ID-Daten - Baugruppenkennzeichen: 300; OmniClass-Nummer: 23.25.30.00; OmniClass-Titel: Structural Framing Products; Typname: TBM_GLT_180/800; WS_COMMENT_DIMENSION: BSH 180/800mm
Type - Tragwerk - Querschnittsform: 0
Type - Pset_BeamCommon - LoadBearing: yes
Classification: 300 (Uniformat); Material: WS_TIMBER_GLT_0°
Pset_BeamCommon - IsExternal: no; Slope: 0 deg; Reference: TBM_GLT_180/800; Span: 19.23 m
Pset_QuantityTakeOff - Reference: TBM_GLT_180/800; sets with these values: 2
Sonstige - Familie: WS_TBM_GLT; Familie und Typ: WS_TBM_GLT: TBM_GLT_180/800; Typ: TBM_GLT_180/800; Typ-ID: 3802012
Abhängigkeiten - Endebenenversatz: 0 m; Querschnittdrehung: 0 deg; Startebenenversatz: 0 m; Ausrichtung: Normal; Referenzebene: Dü_OG1_OKHT_+8,040_Nebenträger Halle; Arbeitsebene: Ebene : Dü_OG1_OKHT_+8,040_Nebenträger Halle; Höhe Referenzebene: 8.04 m
Bemaßungen - Höhe oben: 8.04 m; Höhe unten: 7.24 m; Länge: 19.23 m; Volumen: 2.77127 m3
ID-Daten - Hat Verknüpfung: no; WS_COMMENT_MATERIAL: GL24h; WS_POSITIONNUMBER: 021; WS_TYPE_BUILDING_ELEMENT: B
Materialien und Oberflächen - Tragendes Material: WS_TIMBER_GLT_0°
Phasen - Phase erstellt: Phase 1
Tragwerk - Tragwerksverwendung: Sonstige; Schnittlänge: 19.35 m
Text - WS_COMMENT: OK=+8,040; WS_LEVEL: 01
Geometrische Position - y-Ausrichtung: Ursprung; y-Versatzwert: 0 m; yz-Ausrichtung: Einheitlich; z-Ausrichtung: Oben; Verbindungsstatus: Beide Verbindungen aktiviert; z-Versatzwert: 0 m; Endverlängerung: 0 m; Startverlängerung: 0 m; Anfangsfugenkürzung: -0.12 m; Endfugenkürzung: -0.12 m

# IfcBeam: WS_TBM_GLT:TBM_GLT_200/400 (12)
In: FB_E00_OKFB
Type - PredefinedType: BEAM
Type - Sonstige - Kategorie: Skelettbau; Familienname: WS_TBM_GLT
Type - Bemaßungen - WS_HEIGHT: 0.4 m; WS_WIDTH: 0.2 m
Type - ID-Daten - Baugruppenkennzeichen: 300; OmniClass-Nummer: 23.25.30.00; OmniClass-Titel: Structural Framing Products; Typname: TBM_GLT_200/400; WS_COMMENT_DIMENSION: BSH 200/400mm
Type - Tragwerk - Querschnittsform: 0
Type - Pset_BeamCommon - LoadBearing: yes
Classification: 300 (Uniformat); Material: WS_TIMBER_GLT_0°
Pset_BeamCommon - IsExternal: no; Slope: 0 deg; Reference: TBM_GLT_200/400
Pset_QuantityTakeOff - Reference: TBM_GLT_200/400; sets with these values: 2
Sonstige - Familie: WS_TBM_GLT; Familie und Typ: WS_TBM_GLT: TBM_GLT_200/400; Typ: TBM_GLT_200/400; Typ-ID: 3825372
Abhängigkeiten - Endebenenversatz: 0 m; Querschnittdrehung: 0 deg; Startebenenversatz: 0 m; Ausrichtung: Normal; Referenzebene: Dü_OG1_OKHT_+7,780_Binder; Arbeitsebene: Ebene : Dü_OG1_OKHT_+7,780_Binder; Höhe Referenzebene: 7.78 m
Bemaßungen - Höhe oben: 7.78 m; Höhe unten: 7.38 m
ID-Daten - Hat Verknüpfung: no; WS_COMMENT_MATERIAL: GL24c; WS_POSITIONNUMBER: 016; WS_TYPE_BUILDING_ELEMENT: B
Materialien und Oberflächen - Tragendes Material: WS_TIMBER_GLT_0°
Phasen - Phase erstellt: Phase 1
Tragwerk - Tragwerksverwendung: Sonstige
Text - WS_COMMENT: OK=+7,78; WS_LEVEL: 01
Geometrische Position - y-Ausrichtung: Ursprung; y-Versatzwert: 0 m; yz-Ausrichtung: Einheitlich; z-Ausrichtung: Oben; z-Versatzwert: 0 m; Startverlängerung: 0 m; Anfangsfugenkürzung: 0 m
Name (WS_TBM_GLT:TBM_GLT_200/400:...) | Span (m) = Länge (m) | Volumen (m3) | Schnittlänge (m) | Verbindungsstatus | Endverlängerung (m)
3825231 | 3.86 | 0.2976 | 3.72 | Eine oder zwei Verbindungen deaktiviert | 0
3825817 | 3.86 | 0.2976 | 3.72 | Eine oder zwei Verbindungen deaktiviert | 0
3825827 | 3.86 | 0.2976 | 3.72 | Eine oder zwei Verbindungen deaktiviert | 0
3825839 | 3.86 | 0.2976 | 3.72 | Eine oder zwei Verbindungen deaktiviert | 0
3825848 | 4 | 0.3016 | 3.77 | Eine oder zwei Verbindungen deaktiviert | -0.0899982
3826093 | 3.86 | 0.2988 | 3.735 | Eine oder zwei Verbindungen deaktiviert | 0
3827276 | 3.86 | 0.2976 | 3.72 | Eine oder zwei Verbindungen deaktiviert | 0
3827277 | 3.86 | 0.2976 | 3.72 | Eine oder zwei Verbindungen deaktiviert | 0
3827278 | 3.86 | 0.2976 | 3.72 | Eine oder zwei Verbindungen deaktiviert | 0
3827279 | 3.86 | 0.2976 | 3.72 | Eine oder zwei Verbindungen deaktiviert | 0
3827280 | 3.97 | 0.3064 | 3.83 | Beide Verbindungen aktiviert | 0
3827281 | 3.86 | 0.2988 | 3.735 | Eine oder zwei Verbindungen deaktiviert | 0

# IfcBeam: WS_TBM_GLT:TBM_GLT_220/440, WS_TBM_GLT:TBM_GLT_220/440:3732825
In: FB_E00_OKFB
Type - PredefinedType: BEAM
Type - Sonstige - Kategorie: Skelettbau; Familienname: WS_TBM_GLT
Type - Bemaßungen - WS_HEIGHT: 0.44 m; WS_WIDTH: 0.22 m
Type - ID-Daten - Baugruppenkennzeichen: 300; OmniClass-Nummer: 23.25.30.00; OmniClass-Titel: Structural Framing Products; Typname: TBM_GLT_220/440; WS_COMMENT_DIMENSION: BSH 220/440mm
Type - Tragwerk - Querschnittsform: 0
Type - Pset_BeamCommon - LoadBearing: yes
Classification: 300 (Uniformat); Material: WS_TIMBER_GLT_0°
Pset_BeamCommon - IsExternal: no; Slope: 0 deg; Reference: TBM_GLT_220/440; Span: 2.5 m
Pset_QuantityTakeOff - Reference: TBM_GLT_220/440; sets with these values: 2
Sonstige - Familie: WS_TBM_GLT; Familie und Typ: WS_TBM_GLT: TBM_GLT_220/440; Typ: TBM_GLT_220/440; Typ-ID: 3874770
Abhängigkeiten - Endebenenversatz: 0 m; Querschnittdrehung: 0 deg; Startebenenversatz: 0 m; Ausrichtung: Normal; Arbeitsebene: Ebene : Dü_EG_UKHT_+3,455_Foyer 1, 2; Höhe Referenzebene: 3.455 m; Referenzebene: Dü_EG_UKHT_+3,455_Foyer 1, 2
Bemaßungen - Höhe oben: 3.455 m; Höhe unten: 3.015 m; Länge: 2.5 m; Volumen: 0.242 m3
ID-Daten - Hat Verknüpfung: no; WS_COMMENT_MATERIAL: GL24h; WS_POSITIONNUMBER: 026; WS_TYPE_BUILDING_ELEMENT: B
Materialien und Oberflächen - Tragendes Material: WS_TIMBER_GLT_0°
Phasen - Phase erstellt: Phase 1
Tragwerk - Tragwerksverwendung: Sonstige; Schnittlänge: 2.5 m
Text - WS_COMMENT: OK=+3,460; WS_LEVEL: 00
Geometrische Position - y-Ausrichtung: Ursprung; y-Versatzwert: 0 m; yz-Ausrichtung: Einheitlich; z-Ausrichtung: Oben; Verbindungsstatus: Beide Verbindungen aktiviert; z-Versatzwert: 0 m; Endverlängerung: 0 m; Startverlängerung: 0 m

# IfcBeam: WS_TBM_GLT:TBM_GLT_220/480 (26)
In: FB_E00_OKFB
Type - PredefinedType: BEAM
Type - Sonstige - Kategorie: Skelettbau; Familienname: WS_TBM_GLT
Type - Bemaßungen - WS_HEIGHT: 0.48 m; WS_WIDTH: 0.22 m
Type - ID-Daten - Baugruppenkennzeichen: 300; OmniClass-Nummer: 23.25.30.00; OmniClass-Titel: Structural Framing Products; Typname: TBM_GLT_220/480; WS_COMMENT_DIMENSION: BSH 220/480mm
Type - Tragwerk - Querschnittsform: 0
Type - Pset_BeamCommon - LoadBearing: yes
Classification: 300 (Uniformat); Material: WS_TIMBER_GLT_0°
Pset_BeamCommon - IsExternal: no; Slope: 0 deg; Reference: TBM_GLT_220/480
Pset_QuantityTakeOff - Reference: TBM_GLT_220/480; sets with these values: 2
Sonstige - Familie: WS_TBM_GLT; Familie und Typ: WS_TBM_GLT: TBM_GLT_220/480; Typ: TBM_GLT_220/480; Typ-ID: 3821563
Abhängigkeiten - Endebenenversatz: 0 m; Querschnittdrehung: 0 deg; Startebenenversatz: 0 m; Ausrichtung: Normal; Referenzebene: Dü_EG_OKHT_+3,935_Foyer 1; Arbeitsebene: Ebene : Dü_EG_OKHT_+3,935_Foyer 1; Höhe Referenzebene: 3.935 m
Bemaßungen - Höhe oben: 3.935 m; Höhe unten: 3.455 m
ID-Daten - Hat Verknüpfung: no; WS_COMMENT_MATERIAL: GL24h; WS_POSITIONNUMBER: 024; WS_TYPE_BUILDING_ELEMENT: B
Materialien und Oberflächen - Tragendes Material: WS_TIMBER_GLT_0°
Phasen - Phase erstellt: Phase 1
Tragwerk - Tragwerksverwendung: Sonstige
Text - WS_COMMENT: OK=+3,935; WS_LEVEL: 00
Geometrische Position - y-Ausrichtung: Ursprung; y-Versatzwert: 0 m; yz-Ausrichtung: Einheitlich; z-Ausrichtung: Oben; Verbindungsstatus: Beide Verbindungen aktiviert; z-Versatzwert: 0 m
Name (WS_TBM_GLT:TBM_GLT_220/480:...) | Span (m) = Länge (m) | Volumen (m3) | Schnittlänge (m) | Endverlängerung (m) | Startverlängerung (m) | Anfangsfugenkürzung (m)
3727989 | 2 | 0.17952 | 1.7 | -0.3 | -0.3 | Geometrische Position - Endfugenkürzung: 0 m
4308498 | 2.025 | 0.1848 | 1.75 | -0.125 | -0.81458 | 0 | Geometrische Position - Endfugenkürzung: 0 m
4310341 | 2 | 0.17952 | 1.7 | -0.3 | -0.3
4310353 | 2 | 0.17952 | 1.7 | -0.3 | -0.3 | 0
4310366 | 2 | 0.17952 | 1.7 | -0.3 | -0.3 | 0
4310376 | 2 | 0.17952 | 1.7 | -0.3 | -0.3 | 0
4310386 | 2 | 0.17952 | 1.7 | -0.3 | -0.3 | 0
4310397 | 2 | 0.17952 | 1.7 | -0.3 | -0.3 | 0
4310408 | 2 | 0.17952 | 1.7 | -0.3 | -0.3 | 0
4310419 | 2 | 0.17952 | 1.7 | -0.3 | -0.3 | 0
4310429 | 2 | 0.17952 | 1.7 | -0.3 | -0.3 | 0
4310439 | 2 | 0.17952 | 1.7 | -0.3 | -0.3 | 0
4310449 | 2 | 0.17952 | 1.7 | -0.3 | -0.3 | 0
4310459 | 2 | 0.17952 | 1.7 | -0.3 | -0.3 | 0
4310469 | 2 | 0.17952 | 1.7 | -0.3 | -0.3 | 0
4310479 | 2 | 0.17952 | 1.7 | -0.3 | -0.3 | 0
4310493 | 2 | 0.17952 | 1.7 | -0.3 | -0.3 | 0
4310503 | 2 | 0.17952 | 1.7 | -0.3 | -0.3 | 0
4310513 | 2 | 0.17952 | 1.7 | -0.3 | -0.3 | 0
4310523 | 2 | 0.17952 | 1.7 | -0.3 | -0.3 | 0
4310532 | 2 | 0.17952 | 1.7 | -0.3 | -0.3 | 0
4310543 | 2 | 0.17952 | 1.7 | -0.3 | -0.3 | 0
4310553 | 2 | 0.17952 | 1.7 | -0.3 | -0.3 | 0
4310566 | 2 | 0.17952 | 1.7 | -0.3 | -0.3 | 0
4310576 | 2 | 0.17952 | 1.7 | -0.3 | -0.3 | 0
4310586 | 2 | 0.17952 | 1.7 | -0.3 | -0.3 | 0

# IfcBeam: WS_TBM_GLT:TBM_GLT_240/440 (9)
In: FB_E00_OKFB
Type - PredefinedType: BEAM
Type - Sonstige - Kategorie: Skelettbau; Familienname: WS_TBM_GLT
Type - Bemaßungen - WS_HEIGHT: 0.44 m; WS_WIDTH: 0.24 m
Type - ID-Daten - Baugruppenkennzeichen: 300; OmniClass-Nummer: 23.25.30.00; OmniClass-Titel: Structural Framing Products; Typname: TBM_GLT_240/440; WS_COMMENT_DIMENSION: BSH 240/440mm
Type - Tragwerk - Querschnittsform: 0
Type - Pset_BeamCommon - LoadBearing: yes
Classification: 300 (Uniformat); Material: WS_TIMBER_GLT_0°
Pset_BeamCommon - IsExternal: no; Slope: 0 deg; Reference: TBM_GLT_240/440; Span: 5.85 m
Pset_QuantityTakeOff - Reference: TBM_GLT_240/440; sets with these values: 2
Sonstige - Familie: WS_TBM_GLT; Familie und Typ: WS_TBM_GLT: TBM_GLT_240/440; Typ: TBM_GLT_240/440; Typ-ID: 3913098
Abhängigkeiten - Endebenenversatz: 0 m; Querschnittdrehung: 0 deg; Startebenenversatz: 0 m; Ausrichtung: Normal; Arbeitsebene: Ebene : Dü_EG_OKHT_+3,895_Foyer 2; Höhe Referenzebene: 3.895 m; Referenzebene: Dü_EG_OKHT_+3,895_Foyer 2
Bemaßungen - Höhe oben: 3.895 m; Höhe unten: 3.455 m; Länge: 5.85 m; Volumen: 0.59976 m3
ID-Daten - Hat Verknüpfung: no; WS_COMMENT_MATERIAL: GL24h; WS_POSITIONNUMBER: 011; WS_TYPE_BUILDING_ELEMENT: B
Materialien und Oberflächen - Tragendes Material: WS_TIMBER_GLT_0°
Phasen - Phase erstellt: Phase 1
Tragwerk - Tragwerksverwendung: Sonstige; Schnittlänge: 5.725 m
Text - WS_COMMENT: OK=+3,895; WS_LEVEL: 00
Geometrische Position - y-Ausrichtung: Ursprung; y-Versatzwert: 0 m; yz-Ausrichtung: Einheitlich; z-Ausrichtung: Oben; Verbindungsstatus: Beide Verbindungen aktiviert; z-Versatzwert: 0 m; Endverlängerung: 0 m; Anfangsfugenkürzung: -1.524e-07 m
Name (WS_TBM_GLT:TBM_GLT_240/440:...) | Startverlängerung (m)
3731778 | 1.15203
3732439 | 1.15203
3732448 | 1.15203
3732457 | 1.15203
3732466 | 1.15203
3732475 | 1.15203
3732484 | 1.15203
3732493 | -0.125
3732505 | -0.125

# IfcBeam: WS_TBM_GLT:TBM_GLT_240/800 (3)
In: FB_E00_OKFB
Type - PredefinedType: BEAM
Type - Sonstige - Kategorie: Skelettbau; Familienname: WS_TBM_GLT
Type - Bemaßungen - WS_HEIGHT: 0.8 m; WS_WIDTH: 0.24 m
Type - ID-Daten - Baugruppenkennzeichen: 240; OmniClass-Nummer: 23.25.30.00; OmniClass-Titel: Structural Framing Products; Typname: TBM_GLT_240/800; WS_COMMENT_DIMENSION: BSH 240/800mm
Type - Tragwerk - Querschnittsform: 0
Type - Pset_BeamCommon - LoadBearing: yes
Classification: 240 (Uniformat); Material: WS_TIMBER_GLT_0°
Pset_BeamCommon - IsExternal: no; Slope: 0 deg; Reference: TBM_GLT_240/800; Span: 11.4 m
Pset_QuantityTakeOff - Reference: TBM_GLT_240/800; sets with these values: 2
Sonstige - Familie: WS_TBM_GLT; Familie und Typ: WS_TBM_GLT: TBM_GLT_240/800; Typ: TBM_GLT_240/800; Typ-ID: 4384989
Abhängigkeiten - Endebenenversatz: 0 m; Querschnittdrehung: 0 deg; Startebenenversatz: 0 m; Ausrichtung: Normal; Referenzebene: Dü_OG1_OKHT_+7,780_Binder; Arbeitsebene: Ebene : Dü_OG1_OKHT_+7,780_Binder; Höhe Referenzebene: 7.78 m
Bemaßungen - Höhe oben: 7.78 m; Höhe unten: 6.98 m; Länge: 11.4 m; Volumen: 2.1408 m3
ID-Daten - Hat Verknüpfung: no; WS_COMMENT_MATERIAL: GL24c; WS_TYPE_BUILDING_ELEMENT: B
Materialien und Oberflächen - Tragendes Material: WS_TIMBER_GLT_0°
Phasen - Phase erstellt: Phase 1
Tragwerk - Tragwerksverwendung: Sonstige; Schnittlänge: 11.15 m
Text - WS_COMMENT: OK=+7,78; WS_LEVEL: 01
Geometrische Position - y-Ausrichtung: Ursprung; y-Versatzwert: 0 m; yz-Ausrichtung: Einheitlich; z-Ausrichtung: Oben; Verbindungsstatus: Beide Verbindungen aktiviert; z-Versatzwert: 0 m; Endverlängerung: 0 m; Endfugenkürzung: 0 m; Startverlängerung: 0 m
Name (WS_TBM_GLT:TBM_GLT_240/800:...) | WS_POSITIONNUMBER | Anfangsfugenkürzung (m)
3724652 | 023 | -9.88723e-08
3725663 | 023 | 0
3861254 | 022 | 0

# IfcBeam: WS_TBM_GLT:TBM_GLT_260/1200, WS_TBM_GLT:TBM_GLT_260/1200:4626589
In: FB_E00_OKFB
Type - PredefinedType: BEAM
Type - Sonstige - Kategorie: Skelettbau; Familienname: WS_TBM_GLT
Type - Bemaßungen - WS_HEIGHT: 1.2 m; WS_WIDTH: 0.26 m
Type - ID-Daten - Baugruppenkennzeichen: 300; OmniClass-Nummer: 23.25.30.00; OmniClass-Titel: Structural Framing Products; Typname: TBM_GLT_260/1200; WS_COMMENT_DIMENSION: BSH 260/1200mm
Type - Tragwerk - Querschnittsform: 0
Type - Pset_BeamCommon - LoadBearing: yes
Classification: 300 (Uniformat); Material: WS_TIMBER_GLT_0°
Pset_BeamCommon - IsExternal: no; Slope: 0 deg; Reference: TBM_GLT_260/1200; Span: 19.53 m
Pset_QuantityTakeOff - Reference: TBM_GLT_260/1200; sets with these values: 2
Sonstige - Familie: WS_TBM_GLT; Familie und Typ: WS_TBM_GLT: TBM_GLT_260/1200; Typ: TBM_GLT_260/1200; Typ-ID: 4626632
Abhängigkeiten - Endebenenversatz: 0 m; Querschnittdrehung: 0 deg; Startebenenversatz: 0 m; Ausrichtung: Normal; Arbeitsebene: Ebene : Dü_EG_OKHT_+4,655_Randträger Foyer 2; Höhe Referenzebene: 4.655 m; Referenzebene: Dü_EG_OKHT_+4,655_Randträger Foyer 2
Bemaßungen - Höhe oben: 4.655 m; Höhe unten: 3.455 m; Länge: 19.53 m; Volumen: 5.19457 m3
ID-Daten - Hat Verknüpfung: no; WS_COMMENT_MATERIAL: mit Aussparung b/h=80/480mm; GL24h; WS_POSITIONNUMBER: 012; WS_TYPE_BUILDING_ELEMENT: B
Materialien und Oberflächen - Tragendes Material: WS_TIMBER_GLT_0°
Phasen - Phase erstellt: Phase 1
Tragwerk - Tragwerksverwendung: Sonstige; Anfangsverbindung - Typ: Endhöhe; Schnittlänge: 19.005 m
Text - WS_COMMENT: OK=+4,655; WS_LEVEL: 00
Geometrische Position - y-Ausrichtung: Ursprung; y-Versatzwert: 0 m; yz-Ausrichtung: Einheitlich; z-Ausrichtung: Oben; Verbindungsstatus: Beide Verbindungen aktiviert; z-Versatzwert: 0 m; Endverlängerung: 0 m; Endfugenkürzung: 0 m; Startverlängerung: 0 m; Anfangsfugenkürzung: 0 m

# IfcBeam: WS_TBM_GLT:TBM_GLT_280/1280 (5)
In: FB_E00_OKFB
Type - PredefinedType: BEAM
Type - Sonstige - Kategorie: Skelettbau; Familienname: WS_TBM_GLT
Type - Bemaßungen - WS_HEIGHT: 1.28 m; WS_WIDTH: 0.28 m
Type - ID-Daten - Baugruppenkennzeichen: 300; OmniClass-Nummer: 23.25.30.00; OmniClass-Titel: Structural Framing Products; Typname: TBM_GLT_280/1280; WS_COMMENT_DIMENSION: BSH 280/1280mm
Type - Tragwerk - Querschnittsform: 0
Type - Pset_BeamCommon - LoadBearing: yes
Classification: 300 (Uniformat); Material: WS_TIMBER_GLT_0°
Pset_BeamCommon - IsExternal: no; Slope: 0 deg; Reference: TBM_GLT_280/1280; Span: 19.15 m
Pset_QuantityTakeOff - Reference: TBM_GLT_280/1280; sets with these values: 2
Sonstige - Familie: WS_TBM_GLT; Familie und Typ: WS_TBM_GLT: TBM_GLT_280/1280; Typ: TBM_GLT_280/1280; Typ-ID: 4410857
Abhängigkeiten - Endebenenversatz: 0 m; Querschnittdrehung: 0 deg; Startebenenversatz: 0 m; Ausrichtung: Normal; Arbeitsebene: Ebene : Dü_OG1_OKHT_+7,780_Binder; Höhe Referenzebene: 7.78 m; Referenzebene: Dü_OG1_OKHT_+7,780_Binder
Bemaßungen - Höhe oben: 7.78 m; Höhe unten: 6.5 m; Länge: 19.15 m
ID-Daten - Hat Verknüpfung: no; WS_COMMENT_MATERIAL: GL28c; WS_POSITIONNUMBER: 020; WS_TYPE_BUILDING_ELEMENT: B
Materialien und Oberflächen - Tragendes Material: WS_TIMBER_GLT_0°
Phasen - Phase erstellt: Phase 1
Tragwerk - Tragwerksverwendung: Sonstige; Schnittlänge: 19.35 m
Text - WS_COMMENT: OK=+7,78; WS_LEVEL: 01
Geometrische Position - y-Ausrichtung: Ursprung; y-Versatzwert: 0 m; yz-Ausrichtung: Einheitlich; z-Ausrichtung: Oben; Verbindungsstatus: Beide Verbindungen aktiviert; z-Versatzwert: 0 m; Anfangsfugenkürzung: -0.2 m; Endfugenkürzung: -0.2 m; Endverlängerung: 0 m; Startverlängerung: 0.18 m
Name (WS_TBM_GLT:TBM_GLT_280/1280:...) | Volumen (m3)
3724477 | 6.93506
3724493 | 6.93189
3724501 | 6.93189
4045735 | 6.93189
4045742 | 6.93506

# IfcBeam: WS_TBM_GLT:TBM_GLT_280/400 (3)
In: FB_E00_OKFB
Type - PredefinedType: BEAM
Type - Sonstige - Kategorie: Skelettbau; Familienname: WS_TBM_GLT
Type - Bemaßungen - WS_HEIGHT: 0.4 m; WS_WIDTH: 0.28 m
Type - ID-Daten - Baugruppenkennzeichen: 300; OmniClass-Nummer: 23.25.30.00; OmniClass-Titel: Structural Framing Products; Typname: TBM_GLT_280/400; WS_COMMENT_DIMENSION: BSH 280/400mm
Type - Tragwerk - Querschnittsform: 0
Type - Pset_BeamCommon - LoadBearing: yes
Classification: 300 (Uniformat); Material: WS_TIMBER_GLT_0°
Pset_BeamCommon - IsExternal: no; Slope: 0 deg; Reference: TBM_GLT_280/400; Span: 7.925 m
Pset_QuantityTakeOff - Reference: TBM_GLT_280/400; sets with these values: 2
Sonstige - Familie: WS_TBM_GLT; Familie und Typ: WS_TBM_GLT: TBM_GLT_280/400; Typ: TBM_GLT_280/400; Typ-ID: 4385758
Abhängigkeiten - Endebenenversatz: 0 m; Querschnittdrehung: 0 deg; Startebenenversatz: 0 m; Ausrichtung: Normal; Referenzebene: Dü_OG1_OKHT_+8,005_Träger OG; Arbeitsebene: Ebene : Dü_OG1_OKHT_+8,005_Träger OG; Höhe Referenzebene: 8.005 m
Bemaßungen - Höhe oben: 8.005 m; Höhe unten: 7.605 m; Länge: 7.925 m
ID-Daten - Hat Verknüpfung: no; WS_COMMENT_MATERIAL: GL24h; WS_POSITIONNUMBER: 014; WS_TYPE_BUILDING_ELEMENT: B
Materialien und Oberflächen - Tragendes Material: WS_TIMBER_GLT_0°
Phasen - Phase erstellt: Phase 1
Tragwerk - Tragwerksverwendung: Sonstige
Text - WS_COMMENT: OK=+8,005; WS_LEVEL: 01
Geometrische Position - y-Ausrichtung: Ursprung; y-Versatzwert: 0 m; yz-Ausrichtung: Einheitlich; z-Ausrichtung: Oben; Verbindungsstatus: Beide Verbindungen aktiviert; z-Versatzwert: 0 m; Endverlängerung: 0 m; Startverlängerung: 0 m
Name (WS_TBM_GLT:TBM_GLT_280/400:...) | Volumen (m3) | Schnittlänge (m) | Anfangsfugenkürzung (m)
3734003 | 0.877233 | 7.845 | 0
3734012 | 0.877233 | 7.845 | 0
3734020 | 0.895153 | 8.005

# IfcBeam: WS_TBM_GLT:TBM_GLT_300/240 (11)
In: FB_E00_OKFB
Type - PredefinedType: BEAM
Type - Sonstige - Kategorie: Skelettbau; Familienname: WS_TBM_GLT
Type - Bemaßungen - WS_HEIGHT: 0.24 m; WS_WIDTH: 0.3 m
Type - ID-Daten - Baugruppenkennzeichen: 300; OmniClass-Nummer: 23.25.30.00; OmniClass-Titel: Structural Framing Products; Typenkommentare: TBM_SST_240x300; Typname: TBM_GLT_300/240; WS_COMMENT_DIMENSION: BSH 300/240mm
Type - Tragwerk - Querschnittsform: 0
Type - Pset_BeamCommon - LoadBearing: yes
Classification: 300 (Uniformat); Material: WS_TIMBER_GLT_0°
Pset_BeamCommon - IsExternal: no; Slope: 0 deg; Reference: TBM_GLT_300/240; Span: 1.575 m
Pset_QuantityTakeOff - Reference: TBM_GLT_300/240; sets with these values: 2
Sonstige - Familie: WS_TBM_GLT; Familie und Typ: WS_TBM_GLT: TBM_GLT_300/240; Typ: TBM_GLT_300/240; Typ-ID: 3762528
Abhängigkeiten - Endebenenversatz: 0 m; Querschnittdrehung: 0 deg; Startebenenversatz: 0 m; Ausrichtung: Normal; Arbeitsebene: Ebene : Dü_EG_OKHT_+3,765_Auskragung; Höhe Referenzebene: 3.765 m; Referenzebene: Dü_EG_OKHT_+3,765_Auskragung
Bemaßungen - Höhe oben: 3.765 m; Höhe unten: 3.525 m; Länge: 1.575 m; Volumen: 0.107032 m3
ID-Daten - Hat Verknüpfung: no; WS_COMMENT_MATERIAL: GL28h; WS_POSITIONNUMBER: 021; WS_TYPE_BUILDING_ELEMENT: B
Materialien und Oberflächen - Tragendes Material: WS_TIMBER_GLT_0°
Phasen - Phase erstellt: Phase 1
Tragwerk - Tragwerksverwendung: Sonstige; Schnittlänge: 1.575 m
Text - WS_COMMENT: OK=+3,765; WS_LEVEL: 00
Geometrische Position - y-Ausrichtung: Ursprung; y-Versatzwert: 0 m; yz-Ausrichtung: Einheitlich; z-Ausrichtung: Oben; Verbindungsstatus: Beide Verbindungen aktiviert; z-Versatzwert: 0 m; Endverlängerung: 0 m; Startverlängerung: 0 m
Name (WS_TBM_GLT:TBM_GLT_300/240:...)
3751220
3751438
3751446
3751470
3751478
3751486
3751496
3751508
3751518
3751526
3751534

# IfcBeam: WS_TBM_GLT:TBM_GLT_300/480 (26)
In: FB_E00_OKFB
Type - PredefinedType: BEAM
Type - Sonstige - Kategorie: Skelettbau; Familienname: WS_TBM_GLT
Type - Bemaßungen - WS_HEIGHT: 0.48 m; WS_WIDTH: 0.3 m
Type - ID-Daten - Baugruppenkennzeichen: 300; OmniClass-Nummer: 23.25.30.00; OmniClass-Titel: Structural Framing Products; Typname: TBM_GLT_300/480; WS_COMMENT_DIMENSION: BSH 300/480mm
Type - Tragwerk - Querschnittsform: 0
Type - Pset_BeamCommon - LoadBearing: yes
Classification: 300 (Uniformat); Material: WS_TIMBER_GLT_0°
Pset_BeamCommon - IsExternal: no; Slope: 0 deg; Reference: TBM_GLT_300/480
Pset_QuantityTakeOff - Reference: TBM_GLT_300/480; sets with these values: 2
Sonstige - Familie: WS_TBM_GLT; Familie und Typ: WS_TBM_GLT: TBM_GLT_300/480; Typ: TBM_GLT_300/480; Typ-ID: 3726094
Abhängigkeiten - Endebenenversatz: 0 m; Querschnittdrehung: 0 deg; Startebenenversatz: 0 m; Ausrichtung: Normal; Arbeitsebene: Ebene : Dü_EG_OKHT_+3,935_Foyer 1; Höhe Referenzebene: 3.935 m; Referenzebene: Dü_EG_OKHT_+3,935_Foyer 1
Bemaßungen - Höhe oben: 3.935 m; Höhe unten: 3.455 m
ID-Daten - Hat Verknüpfung: no; WS_COMMENT_MATERIAL: GL28h; WS_TYPE_BUILDING_ELEMENT: B
Materialien und Oberflächen - Tragendes Material: WS_TIMBER_GLT_0°
Phasen - Phase erstellt: Phase 1
Tragwerk - Tragwerksverwendung: Sonstige
Text - WS_COMMENT: OK=+3,935; WS_LEVEL: 00
Geometrische Position - y-Ausrichtung: Ursprung; y-Versatzwert: 0 m; yz-Ausrichtung: Einheitlich; z-Ausrichtung: Oben; Verbindungsstatus: Beide Verbindungen aktiviert; z-Versatzwert: 0 m; Endverlängerung: 0 m; Anfangsfugenkürzung: -0.22 m
Name (WS_TBM_GLT:TBM_GLT_300/480:...) | Span (m) = Länge (m) | Volumen (m3) | WS_POSITIONNUMBER | Schnittlänge (m) | Endfugenkürzung (m) | Startverlängerung (m)
3726130 | 7.73495 | 1.11215 | 021 | 7.76495 | 0 | 0.11
3726331 | 7.73495 | 1.13519 | 021 | 7.92495 | -0.16 | 0.11
3726339 | 7.73495 | 1.11215 | 021 | 7.76495 | 0 | 0.11
3726349 | 7.73495 | 1.13519 | 021 | 7.92495 | -0.16 | 0.11
3726359 | 7.73495 | 1.11215 | 021 | 7.76495 | 0 | 0.11
3726369 | 7.73495 | 1.13519 | 021 | 7.92495 | -0.16 | 0.11
3726377 | 7.65501 | 1.11215 | 021 | 7.76495 | 0.00000148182 | 0.11 | Tragwerk - Endverbindung - Typ: Endhöhe
3726385 | 7.53495 | 1.09487 | 021 | 7.64495 |  | 0.11
3726393 | 7.53495 | 1.09487 | 021 | 7.64495 |  | 0.11
3726401 | 7.55 | 1.09704 | 021 | 7.66 |  | 0.11
3726409 | 7.55001 | 1.09023 | 021 | 7.66001 |  | 0.11
3726419 | 7.55001 | 1.09704 | 021 | 7.66001 |  | 0.11
3726427 | 7.55001 | 1.09704 | 021 | 7.66001 |  | 0
3726435 | 7.73495 | 1.13519 | 021 | 7.92495 | -0.16 | 0.11
3726443 | 7.73495 | 1.11815 | 022 | 7.76495 | 0 | 0.11
3726451 | 7.73495 | 1.14119 | 022 | 7.92495 | -0.16 | 0.11
3726459 | 7.73495 | 1.11815 | 022 | 7.76495 | 0 | 0.11
3726467 | 7.73495 | 1.14119 | 022 | 7.92495 | -0.16 | 0.11
3726477 | 7.715 | 1.1088 | 022 | 7.7 | 0 | 0.11
3726488 | 7.59 | 1.1088 | 022 | 7.7 |  | 0.11
3726591 | 7.59 | 1.1088 | 022 | 7.7 |  | 0.11
3726599 | 7.59 | 1.1088 | 022 | 7.7 |  | 0.11
3726695 | 7.59 | 1.1088 | 023 | 7.7 |  | 0.11
3726703 | 7.59 | 1.1058 | 023 | 7.7 |  | 0.11
3726711 | 7.59 | 1.10541 | 023 | 7.7 |  | 0
3726719 | 7.715 | 1.1088 | 023 | 7.7 | 0 | 0

# IfcBeam: WS_TBM_GLT:TBM_GLT_400/880, WS_TBM_GLT:TBM_GLT_400/880:3731249
In: FB_E00_OKFB
Type - PredefinedType: BEAM
Type - Sonstige - Kategorie: Skelettbau; Familienname: WS_TBM_GLT
Type - Bemaßungen - WS_HEIGHT: 0.88 m; WS_WIDTH: 0.4 m
Type - ID-Daten - Baugruppenkennzeichen: 300; OmniClass-Nummer: 23.25.30.00; OmniClass-Titel: Structural Framing Products; Typname: TBM_GLT_400/880; WS_COMMENT_DIMENSION: BSH 400/880mm
Type - Tragwerk - Querschnittsform: 0
Type - Pset_BeamCommon - LoadBearing: yes
Classification: 300 (Uniformat); Material: WS_TIMBER_GLT_0°
Pset_BeamCommon - IsExternal: no; Slope: 0 deg; Reference: TBM_GLT_400/880; Span: 5.91 m
Pset_QuantityTakeOff - Reference: TBM_GLT_400/880; sets with these values: 2
Sonstige - Familie: WS_TBM_GLT; Familie und Typ: WS_TBM_GLT: TBM_GLT_400/880; Typ: TBM_GLT_400/880; Typ-ID: 4687498
Abhängigkeiten - Endebenenversatz: 0 m; Querschnittdrehung: 0 deg; Startebenenversatz: 0 m; Ausrichtung: Normal; Arbeitsebene: Ebene : Dü_EG_OKHT_+4,335_Übergangsträger Foyer; Höhe Referenzebene: 4.335 m; Referenzebene: Dü_EG_OKHT_+4,335_Übergangsträger Foyer
Bemaßungen - Höhe oben: 4.335 m; Höhe unten: 3.455 m; Länge: 5.91 m; Volumen: 1.7324 m3
ID-Daten - Hat Verknüpfung: no; WS_COMMENT_MATERIAL: mit Aussparung b/h=120/400mm; GL28h; WS_POSITIONNUMBER: 027; WS_TYPE_BUILDING_ELEMENT: B
Materialien und Oberflächen - Tragendes Material: WS_TIMBER_GLT_0°
Phasen - Phase erstellt: Phase 1
Tragwerk - Tragwerksverwendung: Sonstige; Endverbindung - Typ: Endhöhe; Schnittlänge: 5.72501 m
Text - WS_COMMENT: OK=+4,335; WS_LEVEL: 00
Geometrische Position - y-Ausrichtung: Ursprung; y-Versatzwert: 0 m; yz-Ausrichtung: Einheitlich; z-Ausrichtung: Oben; Verbindungsstatus: Beide Verbindungen aktiviert; z-Versatzwert: 0 m; Endverlängerung: 0 m; Endfugenkürzung: 0 m; Anfangsfugenkürzung: -1.524e-07 m; Startverlängerung: 1.15203 m

# IfcBeam: WS_TBM_KVH:TBM_KVH_100/260 (74)
In: FB_E00_OKFB
Type - PredefinedType: BEAM
Type - Sonstige - Kategorie: Skelettbau; Familienname: WS_TBM_KVH
Type - Bemaßungen - WS_HEIGHT: 0.26 m; WS_WIDTH: 0.1 m
Type - ID-Daten - Baugruppenkennzeichen: 300; OmniClass-Nummer: 23.25.30.00; OmniClass-Titel: Structural Framing Products; Typname: TBM_KVH_100/260; WS_COMMENT_DIMENSION: KVH 100/260mm
Type - Tragwerk - Querschnittsform: 0
Type - Pset_BeamCommon - LoadBearing: yes
Classification: 300 (Uniformat); Material: WS_TIMBER
Pset_BeamCommon - IsExternal: no; Slope: 0 deg; Reference: TBM_KVH_100/260
Pset_QuantityTakeOff - Reference: TBM_KVH_100/260; sets with these values: 2
Sonstige - Familie: WS_TBM_KVH; Familie und Typ: WS_TBM_KVH: TBM_KVH_100/260; Typ: TBM_KVH_100/260; Typ-ID: 3813854
Abhängigkeiten - Endebenenversatz: 0 m; Querschnittdrehung: 0 deg; Startebenenversatz: 0 m; Ausrichtung: Normal; Arbeitsebene: Ebene : Dü_OG1_OKHT_+8,040_Nebenträger Halle; Höhe Referenzebene: 8.04 m; Referenzebene: Dü_OG1_OKHT_+8,040_Nebenträger Halle
Bemaßungen - Höhe oben: 8.04 m; Höhe unten: 7.78 m
ID-Daten - Hat Verknüpfung: no; WS_COMMENT_MATERIAL: C24; WS_TYPE_BUILDING_ELEMENT: B
Materialien und Oberflächen - Tragendes Material: WS_TIMBER
Phasen - Phase erstellt: Phase 1
Tragwerk - Tragwerksverwendung: Sonstige
Text - WS_COMMENT: OK=+8,040; WS_LEVEL: 01
Geometrische Position - y-Ausrichtung: Ursprung; y-Versatzwert: 0 m; yz-Ausrichtung: Einheitlich; z-Ausrichtung: Oben; Verbindungsstatus: Beide Verbindungen aktiviert; z-Versatzwert: 0 m
Name (WS_TBM_KVH:TBM_KVH_100/260:...) | Span (m) = Länge (m) | Volumen (m3) | WS_POSITIONNUMBER | Schnittlänge (m) | Endverlängerung (m) | Endfugenkürzung (m) | Startverlängerung (m) | Anfangsfugenkürzung (m)
3733404 | 24.06 | 0.62166 | 10 | 23.91 | 0 | 0 | 0 | 0
3733412 | 24.06 | 0.62166 | 10 | 23.91 | 0 | 0 | 0 | 0
3733420 | 24.06 | 0.62166 | 10 | 23.91 | 0 | 0 | 0 | 0
3733428 | 24.06 | 0.62166 | 10 | 23.91 | 0 | 0 | 0 | 0
3733436 | 24.06 | 0.62166 | 10 | 23.91 | 0 | 0 | 0 | 0
3733444 | 24.06 | 0.62166 | 10 | 23.91 | 0 | 0 | 0 | 0
3733452 | 24.06 | 0.62166 | 10 | 23.91 | 0 | 0 | 0 | 0
3733460 | 24.06 | 0.62166 | 10 | 23.91 | 0 | 0 | 0 | 0
3733470 | 24.06 | 0.62166 | 010 | 23.91 | 0 | 0 | 0 | 0
3733478 | 24.06 | 0.62166 | 10 | 23.91 | 0 | 0 | 0 | 0
3733486 | 24.06 | 0.62166 | 10 | 23.91 | 0 | 0 | 0 | 0
3733494 | 24.06 | 0.62166 | 10 | 23.91 | 0 | 0 | 0 | 0
3733502 | 24.06 | 0.62166 | 10 | 23.91 | 0 | 0 | 0 | 0
3733512 | 24.06 | 0.62166 | 10 | 23.91 | 0 | 0 | 0 | 0
3733522 | 24.06 | 0.62166 | 10 | 23.91 | 0 | 0 | 0 | 0
3733530 | 24.06 | 0.62166 | 10 | 23.91 | 0 | 0 | 0 | 0
3733538 | 24.06 | 0.62166 | 10 | 23.91 | 0 | 0 | 0 | 0
3737762 | 6.26913 | 0.161697 | 10 | 6.21913 | 0 |  | 0 | 0
3737785 | 6.31913 | 0.161697 | 10 | 6.21913 | 0 | 0 | 0 | 0
3737805 | 7.9725 | 0.20696 | 010 | 7.96 | 0 | -0.185 | 0 | 0
3737820 | 8.1475 | 0.20696 | 10 | 7.96 | 0 | -0.185 | 0 | 0.1
3737838 | 8.1475 | 0.20696 | 10 | 7.96 | 0 | -0.185 | 0 | 0.1
3762740 | 24.06 | 0.61737 | 10 | 23.745 | 0 | 0.1 | 0 | 0
3762747 | 24.06 | 0.61737 | 10 | 23.745 | 0 | 0.1 | 0 | 0
3762755 | 24.06 | 0.61737 | 10 | 23.745 | 0 | 0.1 | 0 | 0
3762763 | 24.06 | 0.61737 | 10 | 23.745 | 0 | 0.1 | 0 | 0
3762771 | 24.06 | 0.61737 | 10 | 23.745 | 0 | 0.1 | 0 | 0
3762779 | 24.06 | 0.61737 | 10 | 23.745 | 0 | 0.1 | 0 | 0
3831864 | 10.183 | 0.267032 | 10 | 10.2705 | 0 | -0.185 | 0
3835578 | 7.9725 | 0.20696 | 10 | 7.96 | 0 | -0.185 | 0 | 0
3835663 | 3.99 | 0.0989301 | 010 | 3.805 | 0 | 0 | 0 | 0
3836486 | 4.165 | 0.10543 | 010 | 4.055 | 0 | 0 | 0 | 0
3837053 | 10.1825 | 0.26702 | 010 | 10.27 | 0 | -0.185 | 0.05 | -0.1
3837129 | 4.01505 | 0.101531 | 010 | 3.90505 | 0 | 0 | 0 | 0
3837592 | 3.84005 | 0.0924312 | 010 | 3.55505 | 0 | 0 | 0 | 0.1
3837701 | 9.8325 | 0.25792 | 10 | 9.92 | 0 | -0.185 | 0.05 | -0.1
3838540 | 8.635 | 0.22191 | 10 | 8.535 | 0 | 0 | 0 | 0
3838742 | 23.885 | 0.61737 | 10 | 23.745 | 0 | 0 | 0 | 0
3838743 | 9.8325 | 0.25532 | 10 | 9.82 | 0 | -0.185 | 0 | 0
3838753 | 23.885 | 0.61737 | 10 | 23.745 | 0 | 0 | 0 | 0
3838754 | 9.8325 | 0.25532 | 010 | 9.82 | 0 | -0.185 | 0 | 0
3838764 | 23.885 | 0.61737 | 10 | 23.745 | 0 | 0 | 0 | 0
3838765 | 9.8325 | 0.25532 | 10 | 9.82 | 0 | -0.185 | 0 | 0
3838848 | 23.885 | 0.61737 | 10 | 23.745 | 0 | 0 | 0 | 0
3838849 | 9.8325 | 0.25532 | 10 | 9.82 | 0 | -0.185 | 0 | 0
3838941 | 23.885 | 0.61737 | 10 | 23.745 | 0 | 0 | 0 | 0
3839052 | 23.885 | 0.61737 | 10 | 23.745 | 0 | 0 | 0 | 0
3861766 | 10.0075 | 0.25961 | 10 | 9.985 | 0 | -0.185 | 0 | 0
3861973 | 10.0075 | 0.25961 | 10 | 9.985 | 0 | -0.185 | 0 | 0
3861997 | 10.0075 | 0.25961 | 10 | 9.985 | 0 | -0.185 | 0 | 0
3862019 | 10.0075 | 0.25961 | 10 | 9.985 | 0 | -0.185 | 0 | 0
3862056 | 10.0075 | 0.25961 | 10 | 9.985 | 0 | -0.185 | 0 | 0
3862474 | 10.0075 | 0.25961 | 10 | 9.985 | 0 | -0.185 | 0 | 0
3862525 | 10.0075 | 0.25961 | 10 | 9.985 | 0 | -0.185 | 0 | 0
3862567 | 10.0075 | 0.25961 | 10 | 9.985 | 0 | -0.185 | 0 | 0
3862604 | 10.0075 | 0.25961 | 10 | 9.985 | 0 | -0.185 | 0 | 0
3862659 | 10.0075 | 0.25961 | 10 | 9.985 | 0 | -0.185 | 0 | 0
3862693 | 10.0075 | 0.25961 | 10 | 9.985 | 0 | -0.185 | 0 | 0
3862706 | 10.0075 | 0.25961 | 10 | 9.985 | 0 | -0.185 | 0 | 0
3862728 | 10.0075 | 0.25961 | 10 | 9.985 | 0 | -0.185 | 0 | 0
3862747 | 10.0075 | 0.25961 | 10 | 9.985 | 0 | -0.185 | 0 | 0
3862769 | 10.0075 | 0.25961 | 10 | 9.985 | 0 | -0.185 | 0 | 0
3862809 | 10.0075 | 0.25961 | 10 | 9.985 | 0 | -0.185 | 0 | 0
3863818 | 10.0075 | 0.25961 | 10 | 9.985 | 0 | -0.185 | 0 | 0
4146729 | 0.85337 | 0.0218626 | 10 | 0.84087 | 0 | -0.185 | 0 | 0
4146774 | 0.80337 | 0.0218626 | 10 | 0.84087 | 0 | -0.185 | 0
4146944 | 0.83 | 0.04641 | 10 | 1.785 | 1.005 |  | 0 | 0
4147237 | 0.83 | 0.04641 | 10 | 1.785 | 1.005 |  | 0 | 0
4147363 | 0.8 | 0.0182 | 10 | 0.7 | 0 | 0 | 0 | 0
4147487 | 0.5975 | 0.01521 | 10 | 0.585 | 0 | -0.185 | 0 | 0
4147672 | 1.23754 | 0.0295761 | 10 | 1.13754 | 1.02764 | 0 | 0 | 0
4147858 | 1.23754 | 0.0295761 | 10 | 1.13754 | 1.02764 | 0 | 0 | 0
4828180 | 0.6 | 0.013 | 10 | 0.5 | 0 | 0 | 0 | 0
4828325 | 0.6 | 0.013 | 10 | 0.5 | 0 | 0 | 0 | 0

# IfcBeam: WS_TBM_KVH:TBM_KVH_120/260 (6)
In: FB_E00_OKFB
Type - PredefinedType: BEAM
Type - Sonstige - Kategorie: Skelettbau; Familienname: WS_TBM_KVH
Type - Bemaßungen - WS_HEIGHT: 0.26 m; WS_WIDTH: 0.12 m
Type - ID-Daten - Baugruppenkennzeichen: 300; OmniClass-Nummer: 23.25.30.00; OmniClass-Titel: Structural Framing Products; Typname: TBM_KVH_120/260; WS_COMMENT_DIMENSION: KVH 120/260mm
Type - Tragwerk - Querschnittsform: 0
Type - Pset_BeamCommon - LoadBearing: yes
Classification: 300 (Uniformat); Material: WS_TIMBER
Pset_BeamCommon - IsExternal: no; Slope: 0 deg; Reference: TBM_KVH_120/260
Pset_QuantityTakeOff - Reference: TBM_KVH_120/260; sets with these values: 2
Sonstige - Familie: WS_TBM_KVH; Familie und Typ: WS_TBM_KVH: TBM_KVH_120/260; Typ: TBM_KVH_120/260; Typ-ID: 3827983
Abhängigkeiten - Endebenenversatz: 0 m; Querschnittdrehung: 0 deg; Startebenenversatz: 0 m; Ausrichtung: Normal; Referenzebene: Dü_OG1_OKHT_+8,040_Nebenträger Halle; Arbeitsebene: Ebene : Dü_OG1_OKHT_+8,040_Nebenträger Halle; Höhe Referenzebene: 8.04 m
Bemaßungen - Höhe oben: 8.04 m; Höhe unten: 7.78 m
ID-Daten - Hat Verknüpfung: no; WS_COMMENT_MATERIAL: C24; WS_POSITIONNUMBER: 015; WS_TYPE_BUILDING_ELEMENT: B
Materialien und Oberflächen - Tragendes Material: WS_TIMBER
Phasen - Phase erstellt: Phase 1
Tragwerk - Tragwerksverwendung: Sonstige
Text - WS_COMMENT: OK=+8,040; WS_LEVEL: 01
Geometrische Position - y-Ausrichtung: Ursprung; y-Versatzwert: 0 m; yz-Ausrichtung: Einheitlich; z-Ausrichtung: Oben; Verbindungsstatus: Beide Verbindungen aktiviert; z-Versatzwert: 0 m
Name (WS_TBM_KVH:TBM_KVH_120/260:...) | Span (m) = Länge (m) | Volumen (m3) | Schnittlänge (m) | Endverlängerung (m) | Anfangsfugenkürzung (m) | Startverlängerung (m) | Endfugenkürzung (m)
3827910 | 23.885 | 0.743964 | 23.845 | 0 | 0 | -0.09
3828199 | 24.06 | 0.743964 | 23.845 | 0 | 0 | 0 | 0
3828400 | 8.1475 | 0.251472 | 8.06 | 0 | 0 | 0 | -0.185 | Text - WS_COMMENT_ADDITIONAL: Randträger
3832090 | 19.23 | 0.60372 | 19.35 | 0 | -0.06 | 0 | -0.0599454 | Text - WS_COMMENT_ADDITIONAL: Kopfträger
3855273 | 10.0075 | 0.309504 | 9.92 | -0.12 | 0 | 0 | -0.185
3861479 | 11.05 | 0.34164 | 10.95 | 0 | 0 | 0 | 0

# IfcBuildingElementProxy: WS_VOI_REC:WS_VOI_REC, WS_VOI_REC:WS_VOI_REC:4353769
In: FB_E00_OKFB
Type - Material: <Unnamed>
Type - Sonstige(Type) - Kategorie: Allgemeines Modell; Familienname: WS_VOI_REC
Type - Abhängigkeiten(Type) - Vorgabe-Ansicht: 1.2 m
Type - ID-Daten(Type) - Hersteller: Werner Sobek; Typname: WS_VOI_REC
Type - Pset_ManufacturerTypeInformation - Manufacturer: Werner Sobek
Pset_BuildingElementProxyCommon - Reference: WS_VOI_REC; sets with these values: 2
Sonstige - Kategorie: Allgemeines Modell; Familie: WS_VOI_REC; Familie und Typ: WS_VOI_REC: WS_VOI_REC; Typ: WS_VOI_REC; Typ-ID: 3401340
Abhängigkeiten - Ebene: Dü_U01_OKBP_+0,78; Basisbauteil: WS_CCL_REC : CCL_REC_920x240; Bauteillistenebene: Dü_U01_OKBP_+0,78; Höhe von Ebene: -0.45 m
Bemaßungen - WS_DEPTH: -0.24 m; WS_HEIGHT: 0.24 m; WS_WIDTH: 0.9 m
Phasen - Phase erstellt: Phase 1

# IfcColumn: WS_CCL_REC:CCL_REC_200x250 (2)
In: FB_U01_OKFB
Type - PredefinedType: COLUMN; Material: WS_CONCRETE_REINFORCED
Type - Sonstige - Kategorie: Tragwerksstützen; Familienname: WS_CCL_REC
Type - Bemaßungen - WS_DEPTH: 0.25 m; WS_WIDTH: 0.2 m
Type - ID-Daten - Typname: CCL_REC_200x250; WS_COMMENT_DIMENSION: 20/25cm
Type - Materialien und Oberflächen - Tragendes Material: WS_CONCRETE_REINFORCED
Type - Tragwerk - Querschnittsform: 0
Type - Pset_ColumnCommon - LoadBearing: yes
Pset_ColumnCommon - IsExternal: no; Reference: CCL_REC_200x250
Pset_QuantityTakeOff - Reference: CCL_REC_200x250; sets with these values: 2
Sonstige - Familie: WS_CCL_REC; Familie und Typ: WS_CCL_REC: CCL_REC_200x250; Typ: CCL_REC_200x250; Typ-ID: 3709741
Abhängigkeiten - Raumbegrenzung: yes; Versatz oben: 0 m; Versatz unten: 0 m; Ebene: Dü_U01_OKRD_-0,12; Stützenstil: Vertikal; Verschieben mit Raster: yes; Basisebene: Dü_U01_OKRD_-0,12; Oberste Ebene: Dü_EG_UKHT_+3,455_Foyer 1, 2
Bemaßungen - Länge: 3.575 m; Volumen: 0.17875 m3
ID-Daten - Hat Verknüpfung: no; WS_COMMENT_MATERIAL: C25/30 RC; WS_TYPE_BUILDING_ELEMENT: C
Phasen - Phase erstellt: Phase 1
Tragwerk - Betonüberdeckung - Andere Flächen: Bewehrungsüberdeckung 1 <25 mm>
Text - WS_LEVEL: 00
Name (WS_CCL_REC:CCL_REC_200x250:...) | Stützenpositionsmarkierung
3709744 | E-2
3710144 | D-2

# IfcColumn: WS_CCL_REC:CCL_REC_240x280 (2)
In: FB_U01_OKFB
Type - PredefinedType: COLUMN; Material: WS_CONCRETE_REINFORCED
Type - Sonstige - Kategorie: Tragwerksstützen; Familienname: WS_CCL_REC
Type - Bemaßungen - WS_DEPTH: 0.28 m; WS_WIDTH: 0.24 m
Type - ID-Daten - Typname: CCL_REC_240x280; WS_COMMENT_DIMENSION: 24/28cm
Type - Materialien und Oberflächen - Tragendes Material: WS_CONCRETE_REINFORCED
Type - Tragwerk - Querschnittsform: 0
Type - Pset_ColumnCommon - LoadBearing: yes
Pset_ColumnCommon - IsExternal: no; Reference: CCL_REC_240x280
Pset_QuantityTakeOff - Reference: CCL_REC_240x280; sets with these values: 2
Sonstige - Familie: WS_CCL_REC; Familie und Typ: WS_CCL_REC: CCL_REC_240x280; Typ: CCL_REC_240x280; Typ-ID: 4412019
Abhängigkeiten - Raumbegrenzung: yes; Versatz oben: 0 m; Versatz unten: 0 m; Ebene: BP_UG1_OKBP_-3,87; Basisebene: BP_UG1_OKBP_-3,87; Oberste Ebene: Dü_U01_UKRD_-0,37; Stützenstil: Vertikal; Verschieben mit Raster: yes
Bemaßungen - Länge: 3.5 m; Volumen: 0.2352 m3
ID-Daten - Hat Verknüpfung: no; WS_COMMENT_MATERIAL: C25/30 RC; WS_TYPE_BUILDING_ELEMENT: C
Phasen - Phase erstellt: Phase 1
Tragwerk - Betonüberdeckung - Andere Flächen: Bewehrungsüberdeckung 1 <25 mm>
Text - WS_LEVEL: U1
Name (WS_CCL_REC:CCL_REC_240x280:...) | Stützenpositionsmarkierung
3671015 | E(-1,860)-2(2,095)
3671384 | E-2(2,095) | Pset_ColumnCommon - Slope: 0 deg

# IfcColumn: WS_CCL_REC:CCL_REC_240x300 (4)
Type - PredefinedType: COLUMN; Material: WS_CONCRETE_REINFORCED
Type - Sonstige - Kategorie: Tragwerksstützen; Familienname: WS_CCL_REC
Type - Bemaßungen - WS_DEPTH: 0.3 m; WS_WIDTH: 0.24 m
Type - ID-Daten - Typname: CCL_REC_240x300; WS_COMMENT_DIMENSION: 24/30cm
Type - Materialien und Oberflächen - Tragendes Material: WS_CONCRETE_REINFORCED
Type - Tragwerk - Querschnittsform: 0
Type - Pset_ColumnCommon - LoadBearing: yes
Pset_ColumnCommon - IsExternal: no; Slope: 0 deg; Reference: CCL_REC_240x300
Pset_QuantityTakeOff - Reference: CCL_REC_240x300; sets with these values: 2
Sonstige - Familie: WS_CCL_REC; Familie und Typ: WS_CCL_REC: CCL_REC_240x300; Typ: CCL_REC_240x300; Typ-ID: 3873409
Abhängigkeiten - Raumbegrenzung: yes; Versatz unten: 0 m; Stützenstil: Vertikal; Verschieben mit Raster: yes; Oberste Ebene: Dü_EG_OKRD_+4,035
ID-Daten - Hat Verknüpfung: no; WS_COMMENT_MATERIAL: C25/30 RC; WS_TYPE_BUILDING_ELEMENT: C
Phasen - Phase erstellt: Phase 1
Tragwerk - Betonüberdeckung - Andere Flächen: Bewehrungsüberdeckung 1 <25 mm>
Text - WS_LEVEL: 00
Name (WS_CCL_REC:CCL_REC_240x300:...) | In | Ebene = Basisebene | Stützenpositionsmarkierung | Versatz oben (m) | Länge (m) | Volumen (m3)
3704276 | FB_U01_OKFB | Dü_U01_OKRD_-0,12 | B(-0,385)-5 | -0.5 | 3.655 | 0.26316 | Tragwerk - Betonüberdeckung - Untere Fläche: Bewehrungsüberdeckung 1 <25 mm>
3704668 | FB_U01_OKFB | Dü_U01_OKRD_-0,12 | B(-0,385)-6 | -0.5 | 3.655 | 0.26316 | Tragwerk - Betonüberdeckung - Untere Fläche: Bewehrungsüberdeckung 1 <25 mm>
3704746 | FB_E00_OKFB | Dü_U01_OKBP_+0,78 | B(0,295)-4 | -0.5 | 2.755 | 0.19836
3704758 | FB_E00_OKFB | Dü_U01_OKBP_+0,78 | B(0,295)-3(-1,950) | 0 | 3.255 | 0.21636

# IfcColumn: WS_CCL_REC:CCL_REC_250x250 (4)
In: FB_U01_OKFB
Type - PredefinedType: COLUMN; Material: WS_CONCRETE_REINFORCED
Type - Sonstige - Kategorie: Tragwerksstützen; Familienname: WS_CCL_REC
Type - Bemaßungen - WS_DEPTH: 0.25 m; WS_WIDTH: 0.25 m
Type - ID-Daten - Typname: CCL_REC_250x250; WS_COMMENT_DIMENSION: 25/25cm
Type - Materialien und Oberflächen - Tragendes Material: WS_CONCRETE_REINFORCED
Type - Tragwerk - Querschnittsform: 0
Type - Pset_ColumnCommon - LoadBearing: yes
Pset_ColumnCommon - IsExternal: no; Reference: CCL_REC_250x250
Pset_QuantityTakeOff - Reference: CCL_REC_250x250; sets with these values: 2
Sonstige - Familie: WS_CCL_REC; Familie und Typ: WS_CCL_REC: CCL_REC_250x250; Typ: CCL_REC_250x250; Typ-ID: 3698645
Abhängigkeiten - Raumbegrenzung: yes; Versatz oben: 0 m; Versatz unten: 0 m; Ebene: Dü_U01_OKRD_-0,12; Stützenstil: Vertikal; Verschieben mit Raster: yes; Basisebene: Dü_U01_OKRD_-0,12; Oberste Ebene: Dü_EG_UKRD_+3,85
Bemaßungen - Länge: 3.97 m; Volumen: 0.248125 m3
ID-Daten - Hat Verknüpfung: no; WS_COMMENT_MATERIAL: C25/30 RC; WS_TYPE_BUILDING_ELEMENT: C
Phasen - Phase erstellt: Phase 1
Tragwerk - Betonüberdeckung - Andere Flächen: Bewehrungsüberdeckung 1 <25 mm>
Text - WS_LEVEL: 00
Name (WS_CCL_REC:CCL_REC_250x250:...) | Stützenpositionsmarkierung
3698648 | J-6(-0,430)
3699233 | I-6(-0,430)
3699246 | H-6(-0,430)
3699256 | G-6(-0,430)

# IfcColumn: WS_CCL_REC:CCL_REC_250x400 (5)
In: FB_U01_OKFB
Type - PredefinedType: COLUMN; Material: WS_CONCRETE_REINFORCED
Type - Sonstige - Kategorie: Tragwerksstützen; Familienname: WS_CCL_REC
Type - Bemaßungen - WS_DEPTH: 0.4 m; WS_WIDTH: 0.25 m
Type - ID-Daten - Typname: CCL_REC_250x400; WS_COMMENT_DIMENSION: 25/40cm
Type - Materialien und Oberflächen - Tragendes Material: WS_CONCRETE_REINFORCED
Type - Tragwerk - Querschnittsform: 0
Type - Pset_ColumnCommon - LoadBearing: yes
Pset_ColumnCommon - IsExternal: no; Reference: CCL_REC_250x400
Pset_QuantityTakeOff - Reference: CCL_REC_250x400; sets with these values: 2
Sonstige - Familie: WS_CCL_REC; Familie und Typ: WS_CCL_REC: CCL_REC_250x400; Typ: CCL_REC_250x400; Typ-ID: 3669714
Abhängigkeiten - Raumbegrenzung: yes; Versatz oben: 0 m; Versatz unten: 0 m; Ebene: BP_UG1_OKBP_-3,87; Basisebene: BP_UG1_OKBP_-3,87; Oberste Ebene: Dü_U01_UKRD_-0,37; Stützenstil: Vertikal; Verschieben mit Raster: yes
Bemaßungen - Länge: 3.5 m; Volumen: 0.35 m3
ID-Daten - Hat Verknüpfung: no; WS_COMMENT_MATERIAL: C25/30 RC; WS_TYPE_BUILDING_ELEMENT: C
Phasen - Phase erstellt: Phase 1
Tragwerk - Betonüberdeckung - Andere Flächen: Bewehrungsüberdeckung 1 <25 mm>
Text - WS_LEVEL: U1
Name (WS_CCL_REC:CCL_REC_250x400:...) | Stützenpositionsmarkierung
3669717 | C-2
3669825 | D-2
3670134 | E-2
3670243 | F-2
3857508 | E(2,000)-2

# IfcColumn: WS_CCL_REC:CCL_REC_920x240, WS_CCL_REC:CCL_REC_920x240:3704682
In: FB_E00_OKFB
Type - PredefinedType: COLUMN; Material: WS_CONCRETE_REINFORCED
Type - Sonstige - Kategorie: Tragwerksstützen; Familienname: WS_CCL_REC
Type - Bemaßungen - WS_DEPTH: 0.24 m; WS_WIDTH: 0.92 m
Type - ID-Daten - Typname: CCL_REC_920x240; WS_COMMENT_DIMENSION: 92/24cm
Type - Materialien und Oberflächen - Tragendes Material: WS_CONCRETE_REINFORCED
Type - Tragwerk - Querschnittsform: 0
Type - Pset_ColumnCommon - LoadBearing: yes
Pset_ColumnCommon - IsExternal: no; Reference: CCL_REC_920x240
Pset_QuantityTakeOff - Reference: CCL_REC_920x240; sets with these values: 2
Sonstige - Familie: WS_CCL_REC; Familie und Typ: WS_CCL_REC: CCL_REC_920x240; Typ: CCL_REC_920x240; Typ-ID: 4352674
Abhängigkeiten - Raumbegrenzung: yes; Versatz oben: 0 m; Versatz unten: 0 m; Stützenstil: Vertikal; Verschieben mit Raster: yes; Ebene: Dü_U01_OKBP_+0,78; Oberste Ebene: Dü_EG_OKRD_+4,035; Basisebene: Dü_U01_OKBP_+0,78; Stützenpositionsmarkierung: B-5(2,430)
Bemaßungen - Länge: 3.255 m; Volumen: 0.663504 m3
ID-Daten - Hat Verknüpfung: no; WS_COMMENT_MATERIAL: C25/30 RC; WS_TYPE_BUILDING_ELEMENT: C
Phasen - Phase erstellt: Phase 1
Tragwerk - Betonüberdeckung - Andere Flächen: Bewehrungsüberdeckung 1 <25 mm>
Text - WS_LEVEL: 00

# IfcColumn: WS_TCL_GLT:TCL_GLT_140x280 (7)
In: FB_U01_OKFB
Type - PredefinedType: COLUMN; Material: WS_TIMBER_GLT_90°
Type - Sonstige - Kategorie: Tragwerksstützen; Familienname: WS_TCL_GLT
Type - Bemaßungen - WS_DEPTH: 0.28 m; WS_WIDTH: 0.14 m
Type - ID-Daten - Baugruppenkennzeichen: 300; Typname: TCL_GLT_140x280; WS_COMMENT_DIMENSION: BSH 140/280mm
Type - Materialien und Oberflächen - Tragendes Material: WS_TIMBER_GLT_90°
Type - Tragwerk - Querschnittsform: 0
Type - Pset_ColumnCommon - LoadBearing: yes
Classification: 300 (Uniformat)
Pset_ColumnCommon - IsExternal: no; Slope: 0 deg; Reference: TCL_GLT_140x280
Pset_QuantityTakeOff - Reference: TCL_GLT_140x280; sets with these values: 2
Sonstige - Familie: WS_TCL_GLT; Familie und Typ: WS_TCL_GLT: TCL_GLT_140x280; Typ: TCL_GLT_140x280; Typ-ID: 4181329
Abhängigkeiten - Versatz unten: 0 m; Ebene: Dü_U01_OKRD_-0,12; Basisebene: Dü_U01_OKRD_-0,12; Oberste Ebene: Dü_EG_UKHT_+3,455_Foyer 1, 2
ID-Daten - Hat Verknüpfung: no; WS_COMMENT_MATERIAL: GL24h; WS_POSITIONNUMBER: 022; WS_TYPE_BUILDING_ELEMENT: C
Phasen - Phase erstellt: Phase 1
Text - WS_LEVEL: 00
Name (WS_TCL_GLT:TCL_GLT_140x280:...) | Versatz oben (m) | Stützenstil | Länge (m) | Volumen (m3) | Basis mit Rasterlinien verschieben = Oberes Ende mit Rasterlinien verschieben | Querschnittdrehung (deg) | Basisschnitt - Stil = Oberer Schnitt - Stil | Basisverlängerung (m) = Obere Verlängerung (m)
3721972 | 0 | Vertikal | 3.575 | 0.14014 | Abhängigkeiten - Verschieben mit Raster: yes; Stützenpositionsmarkierung: E(2,000)-2(2,095)
3722143 | 0 | Geneigt - endpunktgesteuert | 3.575 | 0.14014 | yes | 270 | Lotrecht | 0
3722154 | -0.44 | Geneigt - endpunktgesteuert | 3.135 | 0.122892 | yes | 270 | Lotrecht | 0
3722172 | 0 | Geneigt - endpunktgesteuert | 3.575 | 0.14014 | yes | 270 | Lotrecht | 0
3722183 | 0 | Geneigt - endpunktgesteuert | 3.575 | 0.14014 | yes | 270 | Lotrecht | 0
3722192 | 0 | Geneigt - endpunktgesteuert | 3.575 | 0.14014 | yes | 270 | Lotrecht | 0
3858055 | 0 | Vertikal | 3.575 | 0.14014 | Abhängigkeiten - Verschieben mit Raster: yes; Stützenpositionsmarkierung: F-2(2,095)

# IfcColumn: WS_TCL_GLT:TCL_GLT_160/300 (6)
In: FB_U01_OKFB
Type - PredefinedType: COLUMN; Material: WS_TIMBER_GLT_90°
Type - Sonstige - Kategorie: Tragwerksstützen; Familienname: WS_TCL_GLT
Type - Bemaßungen - WS_DEPTH: 0.3 m; WS_WIDTH: 0.16 m
Type - ID-Daten - Baugruppenkennzeichen: 300; Typname: TCL_GLT_160/300; WS_COMMENT_DIMENSION: BSH 160/300mm
Type - Materialien und Oberflächen - Tragendes Material: WS_TIMBER_GLT_90°
Type - Tragwerk - Querschnittsform: 0
Type - Pset_ColumnCommon - LoadBearing: yes
Classification: 300 (Uniformat)
Pset_ColumnCommon - IsExternal: no; Slope: 0 deg; Reference: TCL_GLT_160/300
Pset_QuantityTakeOff - Reference: TCL_GLT_160/300; sets with these values: 2
Sonstige - Familie: WS_TCL_GLT; Familie und Typ: WS_TCL_GLT: TCL_GLT_160/300; Typ: TCL_GLT_160/300; Typ-ID: 3878269
Abhängigkeiten - Versatz oben: 0 m; Versatz unten: 0 m; Ebene: Dü_U01_OKRD_-0,12; Stützenstil: Vertikal; Verschieben mit Raster: yes; Basisebene: Dü_U01_OKRD_-0,12; Oberste Ebene: Dü_EG_UKHT_+3,455_Foyer 1, 2
Bemaßungen - Länge: 3.575 m; Volumen: 0.1716 m3
ID-Daten - Hat Verknüpfung: no; WS_COMMENT_MATERIAL: GL24h; WS_POSITIONNUMBER: 020; WS_TYPE_BUILDING_ELEMENT: C
Phasen - Phase erstellt: Phase 1
Text - WS_LEVEL: 00
Name (WS_TCL_GLT:TCL_GLT_160/300:...) | Stützenpositionsmarkierung
3722490 | K(2,000)-2
3920847 | J(2,000)-2
3921158 | I(2,000)-2
3921167 | H(2,000)-2
3921176 | G(2,000)-2
3921189 | F(2,000)-2

# IfcColumn: WS_TCL_GLT:TCL_GLT_160x180 (4)
In: FB_E00_OKFB
Type - PredefinedType: COLUMN; Material: WS_TIMBER_GLT_0°
Type - Sonstige - Kategorie: Tragwerksstützen; Familienname: WS_TCL_GLT
Type - Bemaßungen - WS_DEPTH: 0.18 m; WS_WIDTH: 0.16 m
Type - ID-Daten - Baugruppenkennzeichen: 300; Typname: TCL_GLT_160x180; WS_COMMENT_DIMENSION: BSH 180/160mm
Type - Materialien und Oberflächen - Tragendes Material: WS_TIMBER_GLT_0°
Type - Tragwerk - Querschnittsform: 0
Type - Pset_ColumnCommon - LoadBearing: yes
Classification: 300 (Uniformat)
Pset_ColumnCommon - IsExternal: no; Reference: TCL_GLT_160x180
Pset_QuantityTakeOff - Reference: TCL_GLT_160x180; sets with these values: 2
Sonstige - Familie: WS_TCL_GLT; Familie und Typ: WS_TCL_GLT: TCL_GLT_160x180; Typ: TCL_GLT_160x180; Typ-ID: 3823716
Abhängigkeiten - Versatz unten: 0 m; Oberste Ebene: Dü_OG1_OKHT_+7,780_Binder; Versatz oben: -0.32 m
ID-Daten - Hat Verknüpfung: no; WS_COMMENT_MATERIAL: GL24h; WS_POSITIONNUMBER: 006; WS_TYPE_BUILDING_ELEMENT: C
Phasen - Phase erstellt: Phase 1
Text - WS_LEVEL: 01
Name (WS_TCL_GLT:TCL_GLT_160x180:...) | Stützenstil | Verschieben mit Raster | Ebene = Basisebene | Stützenpositionsmarkierung | Länge (m) | Volumen (m3) | Slope (deg)
3725160 | Vertikal | yes | Dü_EG_OKRD_+4,035 | E-2 | 3.425 | 0.09864
3725471 | Vertikal | yes | Dü_EG_OKRD_+4,40 | E-6(-0,170) | 3.06 | 0.088128 | 0
3725666 | Vertikal | yes | Dü_EG_OKRD_+4,035 | D-2 | 3.425 | 0.09864 | 0
3725668 | Geneigt - endpunktgesteuert |  | Dü_EG_OKRD_+4,40 |  | 3.06 | 0.088128 | 0 | Abhängigkeiten - Basis mit Rasterlinien verschieben: yes; Oberes Ende mit Rasterlinien verschieben: yes; Querschnittdrehung: 270 deg; Konstruktion - Basisschnitt - Stil: Lotrecht; Basisverlängerung: 0 m; Oberer Schnitt - Stil: Lotrecht; Obere Verlängerung: 0 m

# IfcColumn: WS_TCL_GLT:TCL_GLT_180x180, WS_TCL_GLT:TCL_GLT_180x180:4383363
In: FB_E00_OKFB
Type - PredefinedType: COLUMN; Material: WS_TIMBER_GLT_0°
Type - Sonstige - Kategorie: Tragwerksstützen; Familienname: WS_TCL_GLT
Type - Bemaßungen - WS_DEPTH: 0.18 m; WS_WIDTH: 0.18 m
Type - ID-Daten - Baugruppenkennzeichen: 300; Typname: TCL_GLT_180x180; WS_COMMENT_DIMENSION: BSH 180/180mm
Type - Materialien und Oberflächen - Tragendes Material: WS_TIMBER_GLT_0°
Type - Tragwerk - Querschnittsform: 0
Type - Pset_ColumnCommon - LoadBearing: yes
Classification: 300 (Uniformat)
Pset_ColumnCommon - IsExternal: no; Slope: 0 deg; Reference: TCL_GLT_180x180
Pset_QuantityTakeOff - Reference: TCL_GLT_180x180; sets with these values: 2
Sonstige - Familie: WS_TCL_GLT; Familie und Typ: WS_TCL_GLT: TCL_GLT_180x180; Typ: TCL_GLT_180x180; Typ-ID: 3801151
Abhängigkeiten - Versatz oben: 0 m; Versatz unten: 0 m; Stützenstil: Vertikal; Verschieben mit Raster: yes; Oberste Ebene: Dü_OG1_UKHT_+7,240_Zwischenträger; Basisebene: Dü_EG_OKHT_+4,655_Randträger Foyer 2; Ebene: Dü_EG_OKHT_+4,655_Randträger Foyer 2; Stützenpositionsmarkierung: L-6(-0,160)
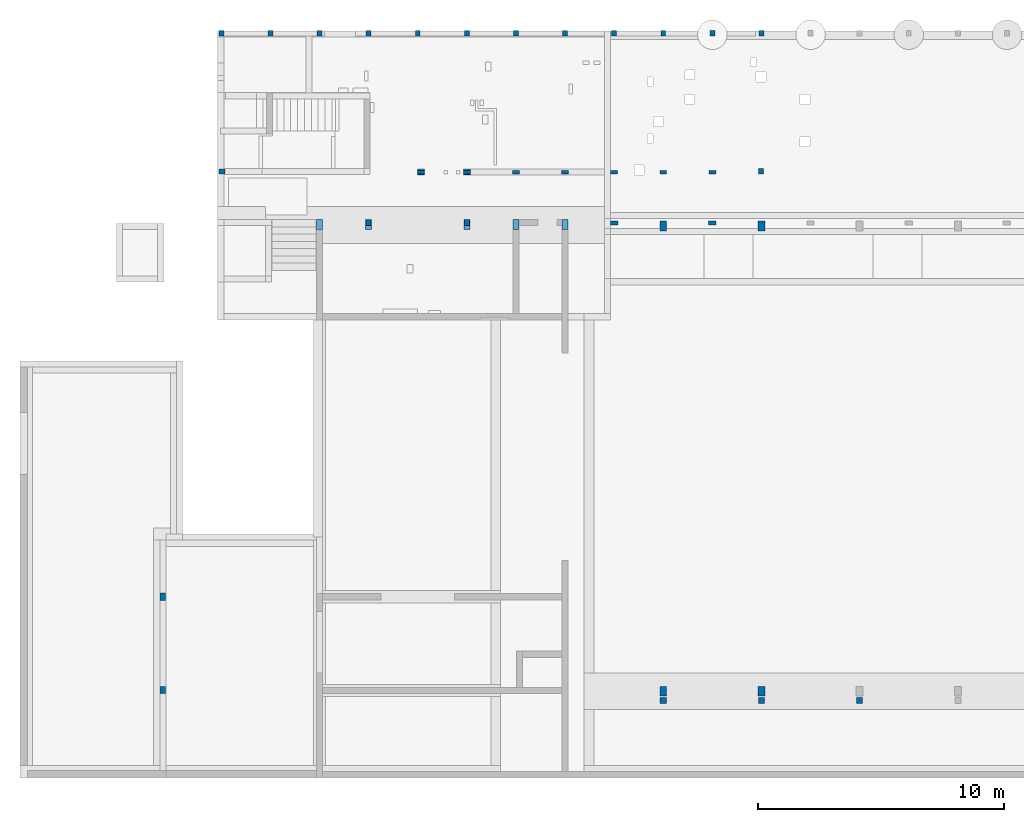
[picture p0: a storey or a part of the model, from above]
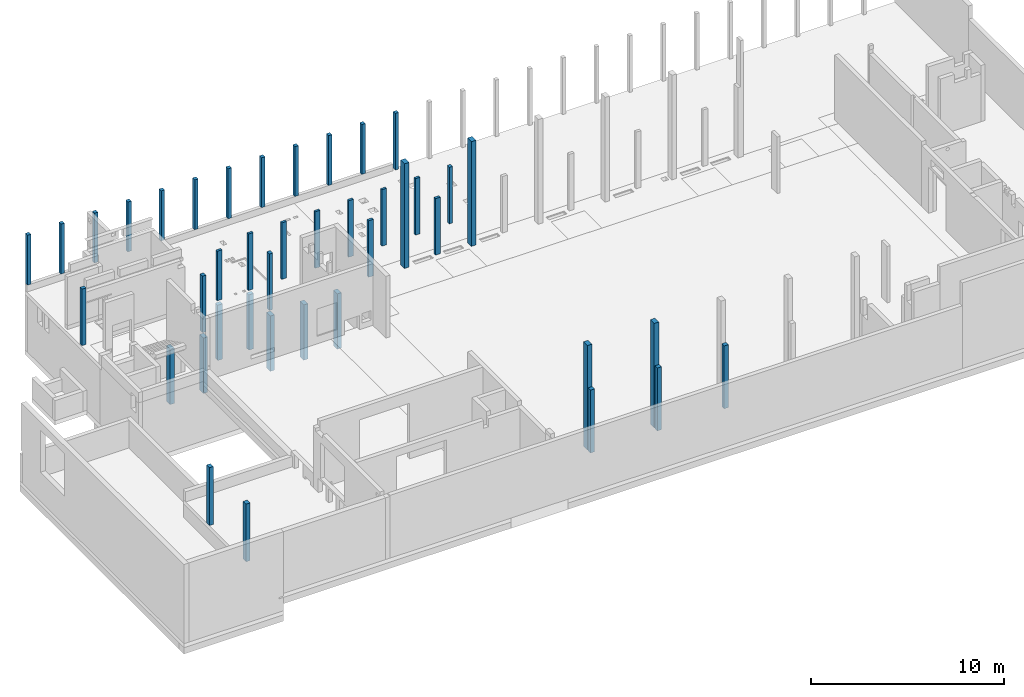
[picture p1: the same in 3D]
Properties of the parts of a building model (IFC2X3), part 3 of 6

# IfcColumn: WS_TCL_GLT:TCL_GLT_180x180, WS_TCL_GLT:TCL_GLT_180x180:4383363
Bemaßungen - Länge: 2.585 m; Volumen: 0.083754 m3
ID-Daten - Hat Verknüpfung: no; WS_COMMENT_MATERIAL: GL24h; WS_POSITIONNUMBER: 005; WS_TYPE_BUILDING_ELEMENT: C
Phasen - Phase erstellt: Phase 1
Text - WS_LEVEL: 01

# IfcColumn: WS_TCL_GLT:TCL_GLT_180x600 (4)
Type - PredefinedType: COLUMN; Material: WS_TIMBER_GLT_0°
Type - Sonstige - Kategorie: Tragwerksstützen; Familienname: WS_TCL_GLT
Type - Bemaßungen - WS_DEPTH: 0.6 m; WS_WIDTH: 0.18 m
Type - ID-Daten - Baugruppenkennzeichen: 300; Typname: TCL_GLT_180x600; WS_COMMENT_DIMENSION: BSH 180/600mm
Type - Materialien und Oberflächen - Tragendes Material: WS_TIMBER_GLT_0°
Type - Tragwerk - Querschnittsform: 0
Type - Pset_ColumnCommon - LoadBearing: yes
Classification: 300 (Uniformat)
Pset_ColumnCommon - IsExternal: no; Reference: TCL_GLT_180x600
Pset_QuantityTakeOff - Reference: TCL_GLT_180x600; sets with these values: 2
Sonstige - Familie: WS_TCL_GLT; Familie und Typ: WS_TCL_GLT: TCL_GLT_180x600; Typ: TCL_GLT_180x600; Typ-ID: 3797850
Abhängigkeiten - Versatz oben: 0 m; Versatz unten: 0 m
ID-Daten - Hat Verknüpfung: no; WS_COMMENT_MATERIAL: GL24h; WS_POSITIONNUMBER: 004; WS_TYPE_BUILDING_ELEMENT: C
Phasen - Phase erstellt: Phase 1
Name (WS_TCL_GLT:TCL_GLT_180x600:...) | In | Ebene = Basisebene | Oberste Ebene | Stützenstil | Länge (m) | Volumen (m3) | WS_LEVEL
3723041 | FB_U01_OKFB | Dü_U01_OKRD_-0,12 | Dü_EG_UKHT_+3,455_Foyer 1, 2 | Geneigt - endpunktgesteuert | 3.575 | 0.3861 | 00 | Pset_ColumnCommon - Slope: 0 deg; Abhängigkeiten - Querschnittdrehung: 0 deg; Basis mit Rasterlinien verschieben: yes; Oberes Ende mit Rasterlinien verschieben: yes; Konstruktion - Basisschnitt - Stil: Lotrecht; Basisverlängerung: 0 m; Oberer Schnitt - Stil: Lotrecht; Obere Verlängerung: 0 m
3723170 | FB_U01_OKFB | Dü_U01_OKRD_-0,12 | Dü_EG_UKHT_+3,455_Foyer 1, 2 | Geneigt - endpunktgesteuert | 3.575 | 0.3861 | 00 | Pset_ColumnCommon - Slope: 0 deg; Abhängigkeiten - Querschnittdrehung: 0 deg; Basis mit Rasterlinien verschieben: yes; Oberes Ende mit Rasterlinien verschieben: yes; Konstruktion - Basisschnitt - Stil: Lotrecht; Basisverlängerung: 0 m; Oberer Schnitt - Stil: Lotrecht; Obere Verlängerung: 0 m
3802225 | FB_E00_OKFB | Dü_EG_OKHT_+4,655_Randträger Foyer 2 | Dü_OG1_UKHT_+7,240_Zwischenträger | Vertikal | 2.585 | 0.27918 | 01 | Abhängigkeiten - Verschieben mit Raster: yes; Stützenpositionsmarkierung: L-5
3802897 | FB_E00_OKFB | Dü_EG_OKHT_+4,655_Randträger Foyer 2 | Dü_OG1_UKHT_+7,240_Zwischenträger | Vertikal | 2.585 | 0.27918 | 01 | Abhängigkeiten - Verschieben mit Raster: yes; Stützenpositionsmarkierung: L-3

# IfcColumn: WS_TCL_GLT:TCL_GLT_200x220 (27)
In: FB_U01_OKFB
Type - PredefinedType: COLUMN; Material: WS_TIMBER_GLT_0°
Type - Sonstige - Kategorie: Tragwerksstützen; Familienname: WS_TCL_GLT
Type - Bemaßungen - WS_DEPTH: 0.22 m; WS_WIDTH: 0.2 m
Type - ID-Daten - Baugruppenkennzeichen: 300; Typname: TCL_GLT_200x220; WS_COMMENT_DIMENSION: BSH 200/220mm
Type - Materialien und Oberflächen - Tragendes Material: WS_TIMBER_GLT_0°
Type - Tragwerk - Querschnittsform: 0
Type - Pset_ColumnCommon - LoadBearing: yes
Classification: 300 (Uniformat)
Pset_ColumnCommon - IsExternal: no; Slope: 0 deg; Reference: TCL_GLT_200x220
Pset_QuantityTakeOff - Reference: TCL_GLT_200x220; sets with these values: 2
Sonstige - Familie: WS_TCL_GLT; Familie und Typ: WS_TCL_GLT: TCL_GLT_200x220; Typ: TCL_GLT_200x220; Typ-ID: 3721687
Abhängigkeiten - Versatz oben: 0 m; Ebene: Dü_U01_OKRD_-0,12; Basisebene: Dü_U01_OKRD_-0,12; Oberste Ebene: Dü_EG_UKHT_+3,455_Foyer 1, 2
ID-Daten - Hat Verknüpfung: no; WS_COMMENT_MATERIAL: GL24h; WS_TYPE_BUILDING_ELEMENT: C
Phasen - Phase erstellt: Phase 1
Text - WS_LEVEL: 00
Name (WS_TCL_GLT:TCL_GLT_200x220:...) | Versatz unten (m) | Stützenstil | Verschieben mit Raster | Stützenpositionsmarkierung | Länge (m) | Volumen (m3) | WS_POSITIONNUMBER
3721493 | 0 | Vertikal | yes | H(2,000)-1(0,155) | 3.575 | 0.1573 | 021
3721822 | 0.42 | Vertikal | yes | F(2,000)-1(0,155) | 3.155 | 0.13882 | 021
3721831 | 0.42 | Vertikal | yes | F-1(0,155) | 3.155 | 0.13882 | 021
3721842 | 0.42 | Vertikal | yes | E(2,000)-1(0,155) | 3.155 | 0.13882 | 021
3721851 | 0.42 | Vertikal | yes | E-1(0,155) | 3.155 | 0.13882 | 021
3721860 | 0.42 | Vertikal | yes | D(2,000)-1(0,155) | 3.155 | 0.13882 | 021
3721871 | 0.42 | Vertikal | yes | D-1(0,155) | 3.155 | 0.13882 | 021
3721886 | 0.42 | Vertikal | yes | C-1(0,155) | 3.155 | 0.13882 | 021
3721897 | 0.42 | Geneigt - endpunktgesteuert |  |  | 3.155 | 0.13882 | 021 | Abhängigkeiten - Querschnittdrehung: 0 deg; Basis mit Rasterlinien verschieben: yes; Oberes Ende mit Rasterlinien verschieben: yes; Konstruktion - Basisschnitt - Stil: Lotrecht; Basisverlängerung: 0 m; Oberer Schnitt - Stil: Lotrecht; Obere Verlängerung: 0 m
3721904 | 0.42 | Vertikal | yes | B(2,000)-1(0,155) | 3.155 | 0.13882 | 021
3722201 | 0 | Geneigt - endpunktgesteuert |  |  | 3.575 | 0.1573 | 023 | Abhängigkeiten - Querschnittdrehung: 180 deg; Basis mit Rasterlinien verschieben: yes; Oberes Ende mit Rasterlinien verschieben: yes; Konstruktion - Basisschnitt - Stil: Lotrecht; Basisverlängerung: 0 m; Oberer Schnitt - Stil: Lotrecht; Obere Verlängerung: 0 m
3790881 | 0.42 | Vertikal | yes | G-1(0,155) | 3.155 | 0.13882 | 021
3791065 | 0 | Vertikal | yes | H-1(0,155) | 3.575 | 0.1573 | 021
3791075 | 0.42 | Vertikal | yes | G(2,000)-1(0,155) | 3.155 | 0.13882 | 021
3821153 | 0 | Vertikal | yes | I-1(0,155) | 3.575 | 0.1573 | 021
3821203 | 0 | Vertikal | yes | J-1(0,155) | 3.575 | 0.1573 | 021
3821215 | 0 | Vertikal | yes | K-1(0,155) | 3.575 | 0.1573 | 021
3821225 | 0 | Vertikal | yes | L-1(0,155) | 3.575 | 0.1573 | 021
3821239 | 0 | Vertikal | yes | M-1(0,155) | 3.575 | 0.1573 | 021
3821249 | 0 | Vertikal | yes | N-1(0,155) | 3.575 | 0.1573 | 021
3821293 | 0 | Vertikal | yes | I(2,000)-1(0,155) | 3.575 | 0.1573 | 021
3821303 | 0 | Vertikal | yes | J(2,000)-1(0,155) | 3.575 | 0.1573 | 021
3821311 | 0 | Vertikal | yes | K(2,000)-1(0,155) | 3.575 | 0.1573 | 021
3821321 | 0 | Vertikal | yes | M(-2,000)-1(0,155) | 3.575 | 0.1573 | 021
3821380 | 0 | Vertikal | yes | L(2,000)-1(0,155) | 3.575 | 0.1573 | 021
3821445 | 0 | Vertikal | yes | N(2,000)-1(0,155) | 3.575 | 0.1573 | 021
3821446 | 0 | Vertikal | yes | N(4,000)-1(0,155) | 3.575 | 0.1573 | 021

# IfcColumn: WS_TCL_GLT:TCL_GLT_200x240, WS_TCL_GLT:TCL_GLT_200x240:4522837
In: FB_U01_OKFB
Type - PredefinedType: COLUMN; Material: WS_TIMBER_GLT_0°
Type - Sonstige - Kategorie: Tragwerksstützen; Familienname: WS_TCL_GLT
Type - Bemaßungen - WS_DEPTH: 0.2 m; WS_WIDTH: 0.24 m
Type - ID-Daten - Baugruppenkennzeichen: 300; Typname: TCL_GLT_200x240; WS_COMMENT_DIMENSION: BSH 240/200mm
Type - Materialien und Oberflächen - Tragendes Material: WS_TIMBER_GLT_0°
Type - Tragwerk - Querschnittsform: 0
Type - Pset_ColumnCommon - LoadBearing: yes
Classification: 300 (Uniformat)
Pset_ColumnCommon - IsExternal: no; Slope: 0 deg; Reference: TCL_GLT_200x240
Pset_QuantityTakeOff - Reference: TCL_GLT_200x240; sets with these values: 2
Sonstige - Familie: WS_TCL_GLT; Familie und Typ: WS_TCL_GLT: TCL_GLT_200x240; Typ: TCL_GLT_200x240; Typ-ID: 4531510
Abhängigkeiten - Versatz oben: 0 m; Versatz unten: 0 m; Ebene: Dü_U01_OKRD_-0,12; Basisebene: Dü_U01_OKRD_-0,12; Oberste Ebene: Dü_EG_UKHT_+3,455_Foyer 1, 2; Querschnittdrehung: 0 deg; Basis mit Rasterlinien verschieben: yes; Oberes Ende mit Rasterlinien verschieben: yes; Stützenstil: Geneigt - endpunktgesteuert
Konstruktion - Basisschnitt - Stil: Lotrecht; Basisverlängerung: 0 m; Oberer Schnitt - Stil: Lotrecht; Obere Verlängerung: 0 m
Bemaßungen - Länge: 3.575 m; Volumen: 0.1716 m3
ID-Daten - Hat Verknüpfung: no; WS_COMMENT_MATERIAL: GL24; WS_POSITIONNUMBER: 024; WS_TYPE_BUILDING_ELEMENT: C
Phasen - Phase erstellt: Phase 1
Text - WS_LEVEL: 00

# IfcColumn: WS_TCL_GLT:TCL_GLT_280x400 (10)
In: FB_U01_OKFB
Type - PredefinedType: COLUMN; Material: WS_TIMBER_GLT_0°
Type - Sonstige - Kategorie: Tragwerksstützen; Familienname: WS_TCL_GLT
Type - Bemaßungen - WS_DEPTH: 0.4 m; WS_WIDTH: 0.28 m
Type - ID-Daten - Baugruppenkennzeichen: 300; Typenkommentare: TCL_GLT_280x400; Typname: TCL_GLT_280x400; WS_COMMENT_DIMENSION: BSH 280/400mm
Type - Materialien und Oberflächen - Tragendes Material: WS_TIMBER_GLT_0°
Type - Tragwerk - Querschnittsform: 0
Type - Pset_ColumnCommon - LoadBearing: yes
Classification: 300 (Uniformat)
Pset_ColumnCommon - IsExternal: no; Reference: TCL_GLT_280x400
Pset_QuantityTakeOff - Reference: TCL_GLT_280x400; sets with these values: 2
Sonstige - Familie: WS_TCL_GLT; Familie und Typ: WS_TCL_GLT: TCL_GLT_280x400; Typ: TCL_GLT_280x400; Typ-ID: 4384636
Abhängigkeiten - Versatz oben: 0 m; Versatz unten: 0 m; Ebene: Dü_U01_OKRD_-0,12; Basisebene: Dü_U01_OKRD_-0,12; Oberste Ebene: Dü_OG1_UKHT_+6,500_Binder
Bemaßungen - Länge: 6.62 m; Volumen: 0.74144 m3
ID-Daten - Hat Verknüpfung: no; WS_COMMENT_MATERIAL: GL24h; WS_TYPE_BUILDING_ELEMENT: C
Phasen - Phase erstellt: Phase 1
Text - WS_LEVEL: 00
Name (WS_TCL_GLT:TCL_GLT_280x400:...) | Stützenstil | WS_POSITIONNUMBER
3722572 | Geneigt - endpunktgesteuert | 002 | Pset_ColumnCommon - Slope: 0 deg; Abhängigkeiten - Querschnittdrehung: 0 deg; Basis mit Rasterlinien verschieben: yes; Oberes Ende mit Rasterlinien verschieben: yes; Konstruktion - Basisschnitt - Stil: Lotrecht; Basisverlängerung: 0 m; Oberer Schnitt - Stil: Lotrecht; Obere Verlängerung: 0 m
3722767 | Geneigt - endpunktgesteuert | 002 | Pset_ColumnCommon - Slope: 0 deg; Abhängigkeiten - Querschnittdrehung: 0 deg; Basis mit Rasterlinien verschieben: yes; Oberes Ende mit Rasterlinien verschieben: yes; Konstruktion - Basisschnitt - Stil: Lotrecht; Basisverlängerung: 0 m; Oberer Schnitt - Stil: Lotrecht; Obere Verlängerung: 0 m
3722787 | Geneigt - endpunktgesteuert | 002 | Pset_ColumnCommon - Slope: 0 deg; Abhängigkeiten - Querschnittdrehung: 0 deg; Basis mit Rasterlinien verschieben: yes; Oberes Ende mit Rasterlinien verschieben: yes; Konstruktion - Basisschnitt - Stil: Lotrecht; Basisverlängerung: 0 m; Oberer Schnitt - Stil: Lotrecht; Obere Verlängerung: 0 m
3722796 | Geneigt - endpunktgesteuert | 002 | Pset_ColumnCommon - Slope: 0 deg; Abhängigkeiten - Querschnittdrehung: 0 deg; Basis mit Rasterlinien verschieben: yes; Oberes Ende mit Rasterlinien verschieben: yes; Konstruktion - Basisschnitt - Stil: Lotrecht; Basisverlängerung: 0 m; Oberer Schnitt - Stil: Lotrecht; Obere Verlängerung: 0 m
3722809 | Geneigt - endpunktgesteuert | 002 | Pset_ColumnCommon - Slope: 0 deg; Abhängigkeiten - Querschnittdrehung: 0 deg; Basis mit Rasterlinien verschieben: yes; Oberes Ende mit Rasterlinien verschieben: yes; Konstruktion - Basisschnitt - Stil: Lotrecht; Basisverlängerung: 0 m; Oberer Schnitt - Stil: Lotrecht; Obere Verlängerung: 0 m
3722878 | Vertikal | 001 | Abhängigkeiten - Verschieben mit Raster: yes; Stützenpositionsmarkierung: J-6
3722879 | Vertikal | 001 | Abhängigkeiten - Verschieben mit Raster: yes; Stützenpositionsmarkierung: K-6
3722880 | Vertikal | 001 | Abhängigkeiten - Verschieben mit Raster: yes; Stützenpositionsmarkierung: I-6
3722881 | Vertikal | 001 | Abhängigkeiten - Verschieben mit Raster: yes; Stützenpositionsmarkierung: H-6
3722882 | Vertikal | 001 | Abhängigkeiten - Verschieben mit Raster: yes; Stützenpositionsmarkierung: G-6

# IfcColumn: WS_TCL_GLT:TCL_GLT_330x400, WS_TCL_GLT:TCL_GLT_330x400:3722776
In: FB_U01_OKFB
Type - PredefinedType: COLUMN; Material: WS_TIMBER_GLT_0°
Type - Sonstige - Kategorie: Tragwerksstützen; Familienname: WS_TCL_GLT
Type - Bemaßungen - WS_DEPTH: 0.4 m; WS_WIDTH: 0.33 m
Type - ID-Daten - Baugruppenkennzeichen: 300; Typname: TCL_GLT_330x400; WS_COMMENT_DIMENSION: BSH 330/400mm
Type - Materialien und Oberflächen - Tragendes Material: WS_TIMBER_GLT_0°
Type - Tragwerk - Querschnittsform: 0
Type - Pset_ColumnCommon - LoadBearing: yes
Classification: 300 (Uniformat)
Pset_ColumnCommon - IsExternal: no; Reference: TCL_GLT_330x400
Pset_QuantityTakeOff - Reference: TCL_GLT_330x400; sets with these values: 2
Sonstige - Familie: WS_TCL_GLT; Familie und Typ: WS_TCL_GLT: TCL_GLT_330x400; Typ: TCL_GLT_330x400; Typ-ID: 4627370
Abhängigkeiten - Versatz oben: 0 m; Versatz unten: 0 m; Ebene: Dü_U01_OKRD_-0,12; Stützenstil: Vertikal; Verschieben mit Raster: yes; Basisebene: Dü_U01_OKRD_-0,12; Oberste Ebene: Dü_OG1_UKHT_+7,240_Zwischenträger; Stützenpositionsmarkierung: L-2
Bemaßungen - Länge: 7.36 m; Volumen: 0.79722 m3
ID-Daten - Hat Verknüpfung: no; WS_COMMENT_MATERIAL: GL24h; WS_POSITIONNUMBER: 003; WS_TYPE_BUILDING_ELEMENT: C
Phasen - Phase erstellt: Phase 1
Text - WS_LEVEL: 00

# IfcColumn: WS_TCL_KVH:TCL_LVL_120/280 (9)
In: FB_E00_OKFB
Type - PredefinedType: COLUMN; Material: WS_TIMBER
Type - Sonstige - Kategorie: Tragwerksstützen; Familienname: WS_TCL_KVH
Type - Bemaßungen - WS_DEPTH: 0.28 m; WS_WIDTH: 0.12 m
Type - ID-Daten - Baugruppenkennzeichen: 300; Typname: TCL_LVL_120/280; WS_COMMENT_DIMENSION: KVH 120/280mm
Type - Materialien und Oberflächen - Tragendes Material: WS_TIMBER
Type - Tragwerk - Querschnittsform: 0
Type - Pset_ColumnCommon - LoadBearing: yes
Classification: 300 (Uniformat)
Pset_ColumnCommon - IsExternal: no; Reference: TCL_LVL_120/280
Pset_QuantityTakeOff - Reference: TCL_LVL_120/280; sets with these values: 2
Sonstige - Familie: WS_TCL_KVH; Familie und Typ: WS_TCL_KVH: TCL_LVL_120/280; Typ: TCL_LVL_120/280; Typ-ID: 4388088
Abhängigkeiten - Versatz oben: 0 m; Stützenstil: Vertikal; Verschieben mit Raster: yes; Oberste Ebene: Dü_OG1_UKHT_+7,605_Träger OG
ID-Daten - Hat Verknüpfung: no; WS_COMMENT_MATERIAL: C24; WS_POSITIONNUMBER: 017; WS_TYPE_BUILDING_ELEMENT: C
Phasen - Phase erstellt: Phase 1
Text - WS_LEVEL: 01
Name (WS_TCL_KVH:TCL_LVL_120/280:...) | Ebene = Basisebene | Stützenpositionsmarkierung | Versatz unten (m) | Länge (m) | Volumen (m3)
3809116 | Dü_EG_OKRD_+3,985 | N-2(-1,900) | 0.815 | 2.805 | 0.094248
3812831 | Dü_EG_OKRD_+3,985 | N-2 | 0.815 | 2.805 | 0.094248
3812841 | Dü_EG_OKRD_+3,985 | N-3 | 0.815 | 2.805 | 0.094248
3812851 | Dü_EG_OKRD_+3,985 | N-3(-1,900) | 0.815 | 2.805 | 0.094248
3812861 | Dü_EG_OKRD_+3,985 | N-4(1,900) | 0.325 | 3.295 | 0.110712
3812871 | Dü_EG_OKRD_+3,985 | N-4 | 0.325 | 3.295 | 0.110712
3812883 | Dü_EG_OKRD_+5,12 | N-5 | 0.65 | 1.835 | 0.061656
3812893 | Dü_EG_OKRD_+5,12 | N-5(-1,900) | 0.65 | 1.835 | 0.061656
3812903 | Dü_EG_OKRD_+5,12 | N-6(-0,110) | 0.65 | 1.835 | 0.061656

# IfcOpeningElement: Opening (280)
Name | In | Reference | sets with these values | Familie | Familie und Typ | Host-ID | Sonstige, Kategorie | Typ | Typ-ID | Ebene | WS_DEPTH (m) | WS_WIDTH (m) | WS_COVER_BACKGROUND | WS_LINES_CONTINUOUS | WS_LINES_HIDDEN = WS_SYMBOL | Phase erstellt | WS_COMMENT | Sonstige(Type), Kategorie | Familienname | Vorgabe-Ansicht (m) | Typname | Hersteller
Basiswand:WS_WAL_CON_250_WT:3665461 | FB_U01_OKFB | WS_VOI_WAL_REC | 2 | WS_VOI_WAL_REC | WS_VOI_WAL_REC: WS_VOI_WAL_REC | 3665461 | Allgemeines Modell | WS_VOI_WAL_REC | 3394965 | BP_UG1_OKBP_-3,87 | 0.25 | 0.5 | yes | no | yes | Phase 1 | KBZ | Allgemeines Modell | WS_VOI_WAL_REC | 0 | WS_VOI_WAL_REC | Modelleigenschaften - WS_DUMMY_EXTENSION_BOT: -1 m; WS_DUMMY_EXTENSION_TOP: 0.1 m; Abhängigkeiten - Höhe von Ebene: 2.5 m; Bemaßungen - Fläche: 0.182 m2; Height: 1 m; Höhe: 1 m; Volumen: 0.0066 m3; WS_HEIGHT: 1 m; Grafiken - WS_2D_SYM_VISIBLE: yes; WS_DETAIL_SYMBOL: WS_DET_2D_REC_OPG : Sym_02; WS_SYMBOL_OFFSET: 0.04 m; Text - WS_COMMENT_1: OK=UKRD=-0,37; ID-Daten(Type) - Typenkommentare: WS_Aussparung
2 x Basiswand:WS_WAL_CON_250_WT:3665461 | FB_U01_OKFB | WS_VOI_WAL_REC | 2 | WS_VOI_WAL_REC | WS_VOI_WAL_REC: WS_VOI_WAL_REC | 3665461 | Allgemeines Modell | WS_VOI_WAL_REC | 3394965 | BP_UG1_OKBP_-3,87 | 0.25 | 0.425 | no | no | yes | Phase 1 | WD | Allgemeines Modell | WS_VOI_WAL_REC | 0 | WS_VOI_WAL_REC | Modelleigenschaften - WS_DUMMY_EXTENSION_BOT: -0.1 m; WS_DUMMY_EXTENSION_TOP: 0.1 m; Abhängigkeiten - Höhe von Ebene: 2.06 m; Bemaßungen - Fläche: 0.038 m2; Height: 0.64 m; Höhe: 0.64 m; Volumen: 0.0012 m3; WS_HEIGHT: 0.64 m; Grafiken - WS_2D_SYM_VISIBLE: yes; WS_DETAIL_SYMBOL: WS_DET_2D_REC_OPG : Sym_02; WS_SYMBOL_OFFSET: 0.04 m; Text - WS_COMMENT_1: OK=-1,17; ID-Daten(Type) - Typenkommentare: WS_Aussparung
Basiswand:WS_WAL_CON_250_WT:3665462 | FB_U01_OKFB | WS_VOI_WAL_REC | 2 | WS_VOI_WAL_REC | WS_VOI_WAL_REC: WS_VOI_WAL_REC | 3708113 | Allgemeines Modell | WS_VOI_WAL_REC | 3394965 | Dü_U01_OKRD_-0,12 | 0.25 | 0.5 | yes | no | yes | Phase 1 | KBZ | Allgemeines Modell | WS_VOI_WAL_REC | 0 | WS_VOI_WAL_REC | Modelleigenschaften - WS_DUMMY_EXTENSION_BOT: -1 m; WS_DUMMY_EXTENSION_TOP: 0.1 m; Abhängigkeiten - Höhe von Ebene: -0.8 m; Bemaßungen - Fläche: 0.182 m2; Height: 1 m; Höhe: 1 m; Volumen: 0.0066 m3; WS_HEIGHT: 1 m; Grafiken - WS_2D_SYM_VISIBLE: yes; WS_DETAIL_SYMBOL: WS_DET_2D_REC_OPG : Sym_02; WS_SYMBOL_OFFSET: 0.04 m; Text - WS_COMMENT_1: OK=UKRD -45cm; ID-Daten(Type) - Typenkommentare: WS_Aussparung
Basiswand:WS_WAL_CON_250_WT:3665464 | FB_U01_OKFB | WS_VOI_WAL_REC | 2 | WS_VOI_WAL_REC | WS_VOI_WAL_REC: WS_VOI_WAL_REC | 3665464 | Allgemeines Modell | WS_VOI_WAL_REC | 3394965 | BP_UG1_OKBP_-3,87 | 0.25 | 1.8 | no | no | yes | Phase 1 | WD | Allgemeines Modell | WS_VOI_WAL_REC | 0 | WS_VOI_WAL_REC | Modelleigenschaften - WS_DUMMY_EXTENSION_BOT: -0.1 m; WS_DUMMY_EXTENSION_TOP: 0.1 m; Abhängigkeiten - Höhe von Ebene: 2.1 m; Bemaßungen - Fläche: 0.038 m2; Height: 1.4 m; Höhe: 1.4 m; Volumen: 0.0012 m3; WS_HEIGHT: 1.4 m; Grafiken - WS_2D_SYM_VISIBLE: yes; WS_DETAIL_SYMBOL: WS_DET_2D_REC_OPG : Sym_02; WS_SYMBOL_OFFSET: 0.04 m; Text - WS_COMMENT_1: OK=UKRD=-0,37; ID-Daten(Type) - Typenkommentare: WS_Aussparung
Basiswand:WS_WAL_CON_250_WT:3665464 | FB_U01_OKFB | WS_VOI_WAL_REC | 2 | WS_VOI_WAL_REC | WS_VOI_WAL_REC: WS_VOI_WAL_REC | 3665464 | Allgemeines Modell | WS_VOI_WAL_REC | 3394965 | BP_UG1_OKBP_-3,87 | 0.25 | 0.4 | no | no | yes | Phase 1 | WD | Allgemeines Modell | WS_VOI_WAL_REC | 0 | WS_VOI_WAL_REC | Modelleigenschaften - WS_DUMMY_EXTENSION_BOT: -1 m; WS_DUMMY_EXTENSION_TOP: 0.1 m; Abhängigkeiten - Höhe von Ebene: 2.3 m; Bemaßungen - Fläche: 0.182 m2; Height: 1.2 m; Höhe: 1.2 m; Volumen: 0.0066 m3; WS_HEIGHT: 1.2 m; Grafiken - WS_2D_SYM_VISIBLE: yes; WS_DETAIL_SYMBOL: WS_DET_2D_REC_OPG : Sym_02; WS_SYMBOL_OFFSET: 0.04 m; Text - WS_COMMENT_1: OK=UKRD; ID-Daten(Type) - Typenkommentare: WS_Aussparung
Basiswand:WS_WAL_CON_250_WT:3665464 | FB_U01_OKFB | WS_VOI_WAL_REC | 2 | WS_VOI_WAL_REC | WS_VOI_WAL_REC: WS_VOI_WAL_REC | 3665464 | Allgemeines Modell | WS_VOI_WAL_REC | 3394965 | BP_UG1_OKBP_-3,87 | 0.25 | 0.5 | yes | no | yes | Phase 1 | KBZ | Allgemeines Modell | WS_VOI_WAL_REC | 0 | WS_VOI_WAL_REC | Modelleigenschaften - WS_DUMMY_EXTENSION_BOT: -0.1 m; WS_DUMMY_EXTENSION_TOP: 0.1 m; Abhängigkeiten - Höhe von Ebene: 2.05 m; Bemaßungen - Fläche: 0.038 m2; Height: 1 m; Höhe: 1 m; Volumen: 0.0012 m3; WS_HEIGHT: 1 m; Grafiken - WS_2D_SYM_VISIBLE: yes; WS_DETAIL_SYMBOL: WS_DET_2D_REC_OPG : Sym_02; WS_SYMBOL_OFFSET: 0.04 m; Text - WS_COMMENT_1: OK=UKRD -45cm; ID-Daten(Type) - Typenkommentare: WS_Aussparung
Geschossdecke:WS_SLB_CON_250:3671416 | FB_U01_OKFB | WS_VOI_SLB_REC | 2 | WS_VOI_SLB_REC | WS_VOI_SLB_REC: WS_VOI_SLB_REC | 3671416 | Allgemeines Modell | WS_VOI_SLB_REC | 3396807 | Dü_U01_OKRD_-0,12 |  | 0.2 | no | yes | no | Phase 1 | DD | Allgemeines Modell | WS_VOI_SLB_REC | 0 | WS_VOI_SLB_REC | Werner Sobek | Abhängigkeiten - Verschieben mit umliegenden Elementen: no; Bemaßungen - WS_LENGTH: 1.4 m; Grafiken - WS_Aussparung_Symboltyp: WS_DET_2D_REC_OPG_SLB : WS_SYM_REC_OPG_SLB_02
Geschossdecke:WS_SLB_CON_250:3671416 | FB_U01_OKFB | WS_VOI_SLB_REC | 2 | WS_VOI_SLB_REC | WS_VOI_SLB_REC: WS_VOI_SLB_REC | 3671416 | Allgemeines Modell | WS_VOI_SLB_REC | 3396807 | Dü_U01_OKRD_-0,12 |  | 3.59 | no | yes | no | Phase 1 | DD | Allgemeines Modell | WS_VOI_SLB_REC | 0 | WS_VOI_SLB_REC | Werner Sobek | Abhängigkeiten - Verschieben mit umliegenden Elementen: no; Bemaßungen - WS_LENGTH: 1.75 m; Grafiken - WS_Aussparung_Symboltyp: WS_DET_2D_REC_OPG_SLB : WS_SYM_REC_OPG_SLB_02
2 x Geschossdecke:WS_SLB_CON_250:3671416 | FB_U01_OKFB | WS_VOI_SLB_REC | 2 | WS_VOI_SLB_REC | WS_VOI_SLB_REC: WS_VOI_SLB_REC | 3671416 | Allgemeines Modell | WS_VOI_SLB_REC | 3396807 | Dü_U01_OKRD_-0,12 |  | 0.2 | no | yes | no | Phase 1 | DD | Allgemeines Modell | WS_VOI_SLB_REC | 0 | WS_VOI_SLB_REC | Werner Sobek | Abhängigkeiten - Verschieben mit umliegenden Elementen: no; Bemaßungen - WS_LENGTH: 0.4 m; Grafiken - WS_Aussparung_Symboltyp: WS_DET_2D_REC_OPG_SLB : WS_SYM_REC_OPG_SLB_02
Geschossdecke:WS_SLB_CON_250:3671416 | FB_U01_OKFB | WS_VOI_REC | 2 | WS_VOI_REC | WS_VOI_REC: WS_VOI_REC |  | Allgemeines Modell | WS_VOI_REC | 3401340 | Dü_U01_OKRD_-0,12 | -0.12 | 1.825 |  |  |  | Phase 1 | DA 1,825/18,5/12 | Abhängigkeiten - Höhe von Ebene: 0 m; Basisbauteil: Ebene : Dü_U01_OKRD_-0,12; Bauteillistenebene: Dü_U01_OKRD_-0,12; Bemaßungen - WS_HEIGHT: 0.185 m; Text - WS_COMMENT_1: UK = -0,24m
Geschossdecke:WS_SLB_CON_250:3671416 | FB_U01_OKFB | WS_VOI_SLB_TOP_REC | 2 | WS_VOI_SLB_TOP_REC | WS_VOI_SLB_TOP_REC: WS_VOI_SLB_TOP_REC | 3671416 | Allgemeines Modell | WS_VOI_SLB_TOP_REC | 3398654 | Dü_U01_OKRD_-0,12 | 0.12 | 1.32 | no | yes | no | Phase 1 | DA | Allgemeines Modell | WS_VOI_SLB_TOP_REC | 0 | WS_VOI_SLB_TOP_REC | Werner Sobek | Text - WS_COMMENT_1: UK = -0,24m; Abhängigkeiten - Verschieben mit umliegenden Elementen: no; Bemaßungen - WS_LENGTH: 0.14 m; Grafiken - WS_Aussparung_Symboltyp: WS_DET_2D_REC_OPG_SLB : WS_SYM_REC_OPG_SLB_01
Geschossdecke:WS_SLB_CON_250:3671416 | FB_U01_OKFB | WS_VOI_SLB_REC | 2 | WS_VOI_SLB_REC | WS_VOI_SLB_REC: WS_VOI_SLB_REC | 3671416 | Allgemeines Modell | WS_VOI_SLB_REC | 3396807 | Dü_U01_OKRD_-0,12 |  | 0.5 | no | yes | no | Phase 1 | DD | Allgemeines Modell | WS_VOI_SLB_REC | 0 | WS_VOI_SLB_REC | Werner Sobek | Abhängigkeiten - Verschieben mit umliegenden Elementen: no; Bemaßungen - WS_LENGTH: 0.14 m; Grafiken - WS_Aussparung_Symboltyp: WS_DET_2D_REC_OPG_SLB : WS_SYM_REC_OPG_SLB_02
Geschossdecke:WS_SLB_CON_250:3671416 | FB_U01_OKFB | WS_VOI_SLB_TOP_REC | 2 | WS_VOI_SLB_TOP_REC | WS_VOI_SLB_TOP_REC: WS_VOI_SLB_TOP_REC | 3671416 | Allgemeines Modell | WS_VOI_SLB_TOP_REC | 3398654 | Dü_U01_OKRD_-0,12 | 0.05 | 0.1 | no | yes | no | Phase 1 | DS | Allgemeines Modell | WS_VOI_SLB_TOP_REC | 0 | WS_VOI_SLB_TOP_REC | Werner Sobek | Abhängigkeiten - Verschieben mit umliegenden Elementen: no; Bemaßungen - WS_LENGTH: 0.75 m; Grafiken - WS_Aussparung_Symboltyp: WS_DET_2D_REC_OPG_SLB : WS_SYM_REC_OPG_SLB_01
Geschossdecke:WS_SLB_CON_250:3671416 | FB_U01_OKFB | WS_VOI_SLB_TOP_REC | 2 | WS_VOI_SLB_TOP_REC | WS_VOI_SLB_TOP_REC: WS_VOI_SLB_TOP_REC | 3671416 | Allgemeines Modell | WS_VOI_SLB_TOP_REC | 3398654 | Dü_U01_OKRD_-0,12 | 0.05 | 0.35 | no | yes | no | Phase 1 | DS | Allgemeines Modell | WS_VOI_SLB_TOP_REC | 0 | WS_VOI_SLB_TOP_REC | Werner Sobek | Abhängigkeiten - Verschieben mit umliegenden Elementen: no; Bemaßungen - WS_LENGTH: 0.1 m; Grafiken - WS_Aussparung_Symboltyp: WS_DET_2D_REC_OPG_SLB : WS_SYM_REC_OPG_SLB_01
Geschossdecke:WS_SLB_CON_250:3671416 | FB_U01_OKFB | WS_VOI_SLB_TOP_REC | 2 | WS_VOI_SLB_TOP_REC | WS_VOI_SLB_TOP_REC: WS_VOI_SLB_TOP_REC | 3671416 | Allgemeines Modell | WS_VOI_SLB_TOP_REC | 3398654 | Dü_U01_OKRD_-0,12 | 0.05 | 2.3 | no | yes | no | Phase 1 | DS | Allgemeines Modell | WS_VOI_SLB_TOP_REC | 0 | WS_VOI_SLB_TOP_REC | Werner Sobek | Abhängigkeiten - Verschieben mit umliegenden Elementen: no; Bemaßungen - WS_LENGTH: 0.1 m; Grafiken - WS_Aussparung_Symboltyp: WS_DET_2D_REC_OPG_SLB : WS_SYM_REC_OPG_SLB_01
Geschossdecke:WS_SLB_CON_250:3671416 | FB_U01_OKFB | WS_VOI_SLB_TOP_REC | 2 | WS_VOI_SLB_TOP_REC | WS_VOI_SLB_TOP_REC: WS_VOI_SLB_TOP_REC | 3671416 | Allgemeines Modell | WS_VOI_SLB_TOP_REC | 3398654 | Dü_U01_OKRD_-0,12 | 0.04 | 1.1 | no | yes | no | Phase 1 | DA | Allgemeines Modell | WS_VOI_SLB_TOP_REC | 0 | WS_VOI_SLB_TOP_REC | Werner Sobek | Text - WS_COMMENT_1: oberseitig; Abhängigkeiten - Verschieben mit umliegenden Elementen: no; Bemaßungen - WS_LENGTH: 0.3 m; Grafiken - WS_Aussparung_Symboltyp: WS_DET_2D_REC_OPG_SLB : WS_SYM_REC_OPG_SLB_01
Geschossdecke:WS_SLB_CON_250:3671416 | FB_U01_OKFB | WS_VOI_SLB_REC | 2 | WS_VOI_SLB_REC | WS_VOI_SLB_REC: WS_VOI_SLB_REC | 3671416 | Allgemeines Modell | WS_VOI_SLB_REC | 3396807 | Dü_U01_OKRD_-0,12 |  | 0.22 | no | yes | no | Phase 1 | DD | Allgemeines Modell | WS_VOI_SLB_REC | 0 | WS_VOI_SLB_REC | Werner Sobek | Abhängigkeiten - Verschieben mit umliegenden Elementen: no; Bemaßungen - WS_LENGTH: 1.02 m; Grafiken - WS_Aussparung_Symboltyp: WS_DET_2D_REC_OPG_SLB : WS_SYM_REC_OPG_SLB_02
3 x Geschossdecke:WS_SLB_CON_250:3671416 | FB_U01_OKFB | WS_VOI_SLB_REC | 2 | WS_VOI_SLB_REC | WS_VOI_SLB_REC: WS_VOI_SLB_REC | 3671416 | Allgemeines Modell | WS_VOI_SLB_REC | 3396807 | Dü_U01_OKRD_-0,12 |  | 0.36 | no | yes | no | Phase 1 | DD | Allgemeines Modell | WS_VOI_SLB_REC | 0 | WS_VOI_SLB_REC | Werner Sobek | Abhängigkeiten - Verschieben mit umliegenden Elementen: no; Bemaßungen - WS_LENGTH: 0.23 m; Grafiken - WS_Aussparung_Symboltyp: WS_DET_2D_REC_OPG_SLB : WS_SYM_REC_OPG_SLB_02
4 x Geschossdecke:WS_SLB_CON_250:3671416 | FB_U01_OKFB | WS_VOI_SLB_REC | 2 | WS_VOI_SLB_REC | WS_VOI_SLB_REC: WS_VOI_SLB_REC | 3671416 | Allgemeines Modell | WS_VOI_SLB_REC | 3396807 | Dü_U01_OKRD_-0,12 |  | 0.4 | no | yes | no | Phase 1 | DD | Allgemeines Modell | WS_VOI_SLB_REC | 0 | WS_VOI_SLB_REC | Werner Sobek | Abhängigkeiten - Verschieben mit umliegenden Elementen: no; Bemaßungen - WS_LENGTH: 0.14 m; Grafiken - WS_Aussparung_Symboltyp: WS_DET_2D_REC_OPG_SLB : WS_SYM_REC_OPG_SLB_02
2 x Geschossdecke:WS_SLB_CON_250:3671416 | FB_U01_OKFB | WS_VOI_SLB_REC | 2 | WS_VOI_SLB_REC | WS_VOI_SLB_REC: WS_VOI_SLB_REC | 3671416 | Allgemeines Modell | WS_VOI_SLB_REC | 3396807 | Dü_U01_OKRD_-0,12 |  | 0.24 | no | yes | no | Phase 1 | DD | Allgemeines Modell | WS_VOI_SLB_REC | 0 | WS_VOI_SLB_REC | Werner Sobek | Abhängigkeiten - Verschieben mit umliegenden Elementen: no; Bemaßungen - WS_LENGTH: 0.14 m; Grafiken - WS_Aussparung_Symboltyp: WS_DET_2D_REC_OPG_SLB : WS_SYM_REC_OPG_SLB_02
2 x Geschossdecke:WS_SLB_CON_250:3671416 | FB_U01_OKFB | WS_VOI_SLB_REC | 2 | WS_VOI_SLB_REC | WS_VOI_SLB_REC: WS_VOI_SLB_REC | 3671416 | Allgemeines Modell | WS_VOI_SLB_REC | 3396807 | Dü_U01_OKRD_-0,12 |  | 0.14 | no | yes | no | Phase 1 | DD | Allgemeines Modell | WS_VOI_SLB_REC | 0 | WS_VOI_SLB_REC | Werner Sobek | Abhängigkeiten - Verschieben mit umliegenden Elementen: no; Bemaßungen - WS_LENGTH: 0.25 m; Grafiken - WS_Aussparung_Symboltyp: WS_DET_2D_REC_OPG_SLB : WS_SYM_REC_OPG_SLB_02
Geschossdecke:WS_SLB_CON_250:3671416 | FB_U01_OKFB | WS_VOI_SLB_REC | 2 | WS_VOI_SLB_REC | WS_VOI_SLB_REC: WS_VOI_SLB_REC | 3671416 | Allgemeines Modell | WS_VOI_SLB_REC | 3396807 | Dü_U01_OKRD_-0,12 |  | 0.2 | no | yes | no | Phase 1 | DD | Allgemeines Modell | WS_VOI_SLB_REC | 0 | WS_VOI_SLB_REC | Werner Sobek | Abhängigkeiten - Verschieben mit umliegenden Elementen: no; Bemaßungen - WS_LENGTH: 0.6 m; Grafiken - WS_Aussparung_Symboltyp: WS_DET_2D_REC_OPG_SLB : WS_SYM_REC_OPG_SLB_02
Geschossdecke:WS_SLB_CON_250:3671416 | FB_U01_OKFB | WS_VOI_SLB_REC | 2 | WS_VOI_SLB_REC | WS_VOI_SLB_REC: WS_VOI_SLB_REC | 3671416 | Allgemeines Modell | WS_VOI_SLB_REC | 3396807 | Dü_U01_OKRD_-0,12 |  | 0.25 | no | yes | no | Phase 1 | DD | Allgemeines Modell | WS_VOI_SLB_REC | 0 | WS_VOI_SLB_REC | Werner Sobek | Abhängigkeiten - Verschieben mit umliegenden Elementen: no; Bemaßungen - WS_LENGTH: 0.3 m; Grafiken - WS_Aussparung_Symboltyp: WS_DET_2D_REC_OPG_SLB : WS_SYM_REC_OPG_SLB_02
2 x Geschossdecke:WS_SLB_CON_250:3671416 | FB_U01_OKFB | WS_VOI_SLB_REC | 2 | WS_VOI_SLB_REC | WS_VOI_SLB_REC: WS_VOI_SLB_REC | 3671416 | Allgemeines Modell | WS_VOI_SLB_REC | 3396807 | Dü_U01_OKRD_-0,12 |  | 0.14 | no | yes | no | Phase 1 | DD | Allgemeines Modell | WS_VOI_SLB_REC | 0 | WS_VOI_SLB_REC | Werner Sobek | Abhängigkeiten - Verschieben mit umliegenden Elementen: no; Bemaßungen - WS_LENGTH: 0.14 m; Grafiken - WS_Aussparung_Symboltyp: WS_DET_2D_REC_OPG_SLB : WS_SYM_REC_OPG_SLB_02
Geschossdecke:WS_SLB_CON_250:3671416 | FB_U01_OKFB | WS_VOI_SLB_REC | 2 | WS_VOI_SLB_REC | WS_VOI_SLB_REC: WS_VOI_SLB_REC | 3671416 | Allgemeines Modell | WS_VOI_SLB_REC | 3396807 | Dü_U01_OKRD_-0,12 |  | 0.13 | no | yes | no | Phase 1 | DD | Allgemeines Modell | WS_VOI_SLB_REC | 0 | WS_VOI_SLB_REC | Werner Sobek | Abhängigkeiten - Verschieben mit umliegenden Elementen: no; Bemaßungen - WS_LENGTH: 0.13 m; Grafiken - WS_Aussparung_Symboltyp: WS_DET_2D_REC_OPG_SLB : WS_SYM_REC_OPG_SLB_02
Geschossdecke:WS_SLB_CON_250:3671416 | FB_U01_OKFB | WS_VOI_SLB_REC | 2 | WS_VOI_SLB_REC | WS_VOI_SLB_REC: WS_VOI_SLB_REC | 3671416 | Allgemeines Modell | WS_VOI_SLB_REC | 3396807 | Dü_U01_OKRD_-0,12 |  | 0.1 | no | yes | no | Phase 1 | DD | Allgemeines Modell | WS_VOI_SLB_REC | 0 | WS_VOI_SLB_REC | Werner Sobek | Abhängigkeiten - Verschieben mit umliegenden Elementen: no; Bemaßungen - WS_LENGTH: 0.1 m; Grafiken - WS_Aussparung_Symboltyp: WS_DET_2D_REC_OPG_SLB : WS_SYM_REC_OPG_SLB_02
Geschossdecke:WS_SLB_CON_250:3671416 | FB_U01_OKFB | WS_VOI_SLB_REC | 2 | WS_VOI_SLB_REC | WS_VOI_SLB_REC: WS_VOI_SLB_REC | 3671416 | Allgemeines Modell | WS_VOI_SLB_REC | 3396807 | Dü_U01_OKRD_-0,12 |  | 1.51 | no | yes | no | Phase 1 | DD | Allgemeines Modell | WS_VOI_SLB_REC | 0 | WS_VOI_SLB_REC | Werner Sobek | Abhängigkeiten - Verschieben mit umliegenden Elementen: no; Bemaßungen - WS_LENGTH: 3.2 m; Grafiken - WS_Aussparung_Symboltyp: WS_DET_2D_REC_OPG_SLB : WS_SYM_REC_OPG_SLB_02
Geschossdecke:WS_SLB_CON_250:488538 | FB_U01_OKFB | WS_SLB_CON_250 | 2 |  |  |  | Linien: <Skizze> | Sonstige - Betonauskragung: 0 m; Stahlauskragung: 0 m; Analytische Achse - Ausrichtungsmethode: Automatische Erkennung; Manuell angepasst: no; Projektion innerhalb Ebene: Geschossdecken-/Plattenkante; Abhängigkeiten - Bestimmt Neigung: no; Definiert die konstante Höhe: no; Versatz von Basis: 0 m; Bemaßungen - Länge: 1.52004 m; Neigung: 0.0833333
Basiswand:WS_WAL_CON_250:3674303 | FB_U01_OKFB | WS_VOI_WAL_REC | 2 | WS_VOI_WAL_REC | WS_VOI_WAL_REC: WS_VOI_WAL_REC | 3674526 | Allgemeines Modell | WS_VOI_WAL_REC | 3394965 | Dü_U01_OKRD_-0,12 | 0.25 | 0.6 | yes | no | yes | Phase 1 | KBZ | Allgemeines Modell | WS_VOI_WAL_REC | 0 | WS_VOI_WAL_REC | Modelleigenschaften - WS_DUMMY_EXTENSION_BOT: -1 m; WS_DUMMY_EXTENSION_TOP: 0 m; Abhängigkeiten - Höhe von Ebene: 3 m; Bemaßungen - Fläche: 0.166 m2; Height: 0.55 m; Höhe: 0.55 m; Volumen: 0.006 m3; WS_HEIGHT: 0.55 m; Grafiken - WS_2D_SYM_VISIBLE: yes; WS_DETAIL_SYMBOL: WS_DET_2D_REC_OPG : Sym_02; WS_SYMBOL_OFFSET: 0.04 m; Text - WS_COMMENT_1: OK=UKRD; ID-Daten(Type) - Typenkommentare: WS_Aussparung
Basiswand:WS_WAL_CON_250:3676359 | FB_U01_OKFB | WS_VOI_WAL_REC | 2 | WS_VOI_WAL_REC | WS_VOI_WAL_REC: WS_VOI_WAL_REC | 3676359 | Allgemeines Modell | WS_VOI_WAL_REC | 3394965 | Dü_U01_OKRD_-0,12 | 0.25 | 0.475048 | no | no | yes | Phase 1 | WD | Allgemeines Modell | WS_VOI_WAL_REC | 0 | WS_VOI_WAL_REC | Modelleigenschaften - WS_DUMMY_EXTENSION_BOT: -0.1 m; WS_DUMMY_EXTENSION_TOP: 0.1 m; Abhängigkeiten - Höhe von Ebene: 2.98 m; Bemaßungen - Fläche: 0.038 m2; Height: 0.99 m; Höhe: 0.99 m; Volumen: 0.0012 m3; WS_HEIGHT: 0.99 m; Grafiken - WS_2D_SYM_VISIBLE: yes; WS_DETAIL_SYMBOL: WS_DET_2D_REC_OPG : Sym_02; WS_SYMBOL_OFFSET: 0.04 m; Text - WS_COMMENT_1: OK=UKRD; ID-Daten(Type) - Typenkommentare: WS_Aussparung
Basiswand:WS_WAL_CON_250:3676966 | FB_U01_OKFB | WS_VOI_WAL_REC | 2 | WS_VOI_WAL_REC | WS_VOI_WAL_REC: WS_VOI_WAL_REC | 3676966 | Allgemeines Modell | WS_VOI_WAL_REC | 3394965 | Dü_U01_OKRD_-0,12 | 0.25 | 0.7 | no | no | yes | Phase 1 | WD | Allgemeines Modell | WS_VOI_WAL_REC | 0 | WS_VOI_WAL_REC | Modelleigenschaften - WS_DUMMY_EXTENSION_BOT: -0.1 m; WS_DUMMY_EXTENSION_TOP: 2 m; Abhängigkeiten - Höhe von Ebene: 0 m; Bemaßungen - Fläche: 0.342 m2; Height: 0.88 m; Höhe: 0.88 m; Volumen: 0.0126 m3; WS_HEIGHT: 0.88 m; Grafiken - WS_2D_SYM_VISIBLE: yes; WS_DETAIL_SYMBOL: WS_DET_2D_REC_OPG : Sym_02; WS_SYMBOL_OFFSET: 0.04 m; Text - WS_COMMENT_1: UK=OKBP; ID-Daten(Type) - Typenkommentare: WS_Aussparung
Basiswand:WS_WAL_CON_250:3676966 | FB_U01_OKFB | WS_VOI_WAL_REC | 2 | WS_VOI_WAL_REC | WS_VOI_WAL_REC: WS_VOI_WAL_REC | 3676966 | Allgemeines Modell | WS_VOI_WAL_REC | 3394965 | Dü_U01_OKRD_-0,12 | 0.25 | 0.9 | no | no | yes | Phase 1 | WD | Allgemeines Modell | WS_VOI_WAL_REC | 0 | WS_VOI_WAL_REC | Modelleigenschaften - WS_DUMMY_EXTENSION_BOT: -0.1 m; WS_DUMMY_EXTENSION_TOP: 2 m; Abhängigkeiten - Höhe von Ebene: 0 m; Bemaßungen - Fläche: 0.342 m2; Height: 0.88 m; Höhe: 0.88 m; Volumen: 0.0126 m3; WS_HEIGHT: 0.88 m; Grafiken - WS_2D_SYM_VISIBLE: yes; WS_DETAIL_SYMBOL: WS_DET_2D_REC_OPG : Sym_02; WS_SYMBOL_OFFSET: 0.04 m; Text - WS_COMMENT_1: UK=OKBP; ID-Daten(Type) - Typenkommentare: WS_Aussparung
Basiswand:WS_WAL_CON_250:3676966 | FB_U01_OKFB | WS_VOI_WAL_REC | 2 | WS_VOI_WAL_REC | WS_VOI_WAL_REC: WS_VOI_WAL_REC | 3676966 | Allgemeines Modell | WS_VOI_WAL_REC | 3394965 | Dü_U01_OKRD_-0,12 | 0.25 | 0.4 | no | no | yes | Phase 1 | WD | Allgemeines Modell | WS_VOI_WAL_REC | 0 | WS_VOI_WAL_REC | Modelleigenschaften - WS_DUMMY_EXTENSION_BOT: -0.01 m; WS_DUMMY_EXTENSION_TOP: 3 m; Abhängigkeiten - Höhe von Ebene: 0 m; Bemaßungen - Fläche: 0.4876 m2; Height: 0.15 m; Höhe: 0.15 m; Volumen: 0.01806 m3; WS_HEIGHT: 0.15 m; Grafiken - WS_2D_SYM_VISIBLE: yes; WS_DETAIL_SYMBOL: WS_DET_2D_REC_OPG : Sym_02; WS_SYMBOL_OFFSET: 0.04 m; Text - WS_COMMENT_1: UK=OKBP; ID-Daten(Type) - Typenkommentare: WS_Aussparung
Basiswand:WS_WAL_CON_250:3676966 | FB_U01_OKFB | WS_VOI_WAL_REC | 2 | WS_VOI_WAL_REC | WS_VOI_WAL_REC: WS_VOI_WAL_REC | 3676966 | Allgemeines Modell | WS_VOI_WAL_REC | 3394965 | Dü_U01_OKRD_-0,12 | 0.25 | 0.5 | yes | no | yes | Phase 1 | KBZ | Allgemeines Modell | WS_VOI_WAL_REC | 0 | WS_VOI_WAL_REC | Modelleigenschaften - WS_DUMMY_EXTENSION_BOT: -1 m; WS_DUMMY_EXTENSION_TOP: 0.1 m; Abhängigkeiten - Höhe von Ebene: 3.17 m; Bemaßungen - Fläche: 0.182 m2; Height: 0.8 m; Höhe: 0.8 m; Volumen: 0.0066 m3; WS_HEIGHT: 0.8 m; Grafiken - WS_2D_SYM_VISIBLE: yes; WS_DETAIL_SYMBOL: WS_DET_2D_REC_OPG : Sym_02; WS_SYMBOL_OFFSET: 0.04 m; Text - WS_COMMENT_1: OK=UKRD; ID-Daten(Type) - Typenkommentare: WS_Aussparung
Basiswand:WS_WAL_CON_250:3677671 | FB_U01_OKFB | WS_VOI_WAL_REC | 2 | WS_VOI_WAL_REC | WS_VOI_WAL_REC: WS_VOI_WAL_REC | 3677671 | Allgemeines Modell | WS_VOI_WAL_REC | 3394965 | Dü_U01_OKRD_-0,12 | 0.25 | 0.8 | no | no | yes | Phase 1 | WD | Allgemeines Modell | WS_VOI_WAL_REC | 0 | WS_VOI_WAL_REC | Modelleigenschaften - WS_DUMMY_EXTENSION_BOT: -0.01 m; WS_DUMMY_EXTENSION_TOP: 3 m; Abhängigkeiten - Höhe von Ebene: 2.20354e-09 m; Bemaßungen - Fläche: 0.4876 m2; Height: 0.9 m; Höhe: 0.9 m; Volumen: 0.01806 m3; WS_HEIGHT: 0.9 m; Grafiken - WS_2D_SYM_VISIBLE: yes; WS_DETAIL_SYMBOL: WS_DET_2D_REC_OPG : Sym_02; WS_SYMBOL_OFFSET: 0.04 m; Text - WS_COMMENT_1: UK=OKBP; ID-Daten(Type) - Typenkommentare: WS_Aussparung
Basiswand:WS_WAL_CON_250:3677925 | FB_U01_OKFB | WS_VOI_WAL_REC | 2 | WS_VOI_WAL_REC | WS_VOI_WAL_REC: WS_VOI_WAL_REC | 3677925 | Allgemeines Modell | WS_VOI_WAL_REC | 3394965 | Dü_U01_OKRD_-0,12 | 0.25 | 0.4 | no | no | yes | Phase 1 | WD | Allgemeines Modell | WS_VOI_WAL_REC | 0 | WS_VOI_WAL_REC | Modelleigenschaften - WS_DUMMY_EXTENSION_BOT: -0.01 m; WS_DUMMY_EXTENSION_TOP: 3 m; Abhängigkeiten - Höhe von Ebene: 0 m; Bemaßungen - Fläche: 0.4876 m2; Height: 0.15 m; Höhe: 0.15 m; Volumen: 0.01806 m3; WS_HEIGHT: 0.15 m; Grafiken - WS_2D_SYM_VISIBLE: yes; WS_DETAIL_SYMBOL: WS_DET_2D_REC_OPG : Sym_02; WS_SYMBOL_OFFSET: 0.04 m; Text - WS_COMMENT_1: UK=OKBP; ID-Daten(Type) - Typenkommentare: WS_Aussparung
Basiswand:WS_WAL_CON_250:3677925 | FB_U01_OKFB | WS_VOI_WAL_REC | 2 | WS_VOI_WAL_REC | WS_VOI_WAL_REC: WS_VOI_WAL_REC | 3677925 | Allgemeines Modell | WS_VOI_WAL_REC | 3394965 | Dü_U01_OKRD_-0,12 | 0.25 | 0.7 | no | no | yes | Phase 1 | WD | Allgemeines Modell | WS_VOI_WAL_REC | 0 | WS_VOI_WAL_REC | Modelleigenschaften - WS_DUMMY_EXTENSION_BOT: -0.01 m; WS_DUMMY_EXTENSION_TOP: 3 m; Abhängigkeiten - Höhe von Ebene: 0 m; Bemaßungen - Fläche: 0.4876 m2; Height: 0.2 m; Höhe: 0.2 m; Volumen: 0.01806 m3; WS_HEIGHT: 0.2 m; Grafiken - WS_2D_SYM_VISIBLE: yes; WS_DETAIL_SYMBOL: WS_DET_2D_REC_OPG : Sym_02; WS_SYMBOL_OFFSET: 0.04 m; Text - WS_COMMENT_1: UK=OKBP; ID-Daten(Type) - Typenkommentare: WS_Aussparung
2 x Basiswand:WS_WAL_CON_250:3678293 | FB_U01_OKFB | WS_VOI_WAL_REC | 2 | WS_VOI_WAL_REC | WS_VOI_WAL_REC: WS_VOI_WAL_REC | 3678293 | Allgemeines Modell | WS_VOI_WAL_REC | 3394965 | Dü_U01_OKRD_-0,12 | 0.25 | 0.9 | no | no | yes | Phase 1 | WD | Allgemeines Modell | WS_VOI_WAL_REC | 0 | WS_VOI_WAL_REC | Modelleigenschaften - WS_DUMMY_EXTENSION_BOT: -0.1 m; WS_DUMMY_EXTENSION_TOP: 2 m; Abhängigkeiten - Höhe von Ebene: 0 m; Bemaßungen - Fläche: 0.342 m2; Height: 0.88 m; Höhe: 0.88 m; Volumen: 0.0126 m3; WS_HEIGHT: 0.88 m; Grafiken - WS_2D_SYM_VISIBLE: yes; WS_DETAIL_SYMBOL: WS_DET_2D_REC_OPG : Sym_02; WS_SYMBOL_OFFSET: 0.04 m; Text - WS_COMMENT_1: UK=OKBP; ID-Daten(Type) - Typenkommentare: WS_Aussparung
Basiswand:WS_WAL_CON_250:3678293 | FB_U01_OKFB | WS_VOI_WAL_REC | 2 | WS_VOI_WAL_REC | WS_VOI_WAL_REC: WS_VOI_WAL_REC | 3678293 | Allgemeines Modell | WS_VOI_WAL_REC | 3394965 | Dü_U01_OKRD_-0,12 | 0.25 | 0.7 | no | no | yes | Phase 1 | WD | Allgemeines Modell | WS_VOI_WAL_REC | 0 | WS_VOI_WAL_REC | Modelleigenschaften - WS_DUMMY_EXTENSION_BOT: -0.1 m; WS_DUMMY_EXTENSION_TOP: 2 m; Abhängigkeiten - Höhe von Ebene: 0 m; Bemaßungen - Fläche: 0.342 m2; Height: 0.88 m; Höhe: 0.88 m; Volumen: 0.0126 m3; WS_HEIGHT: 0.88 m; Grafiken - WS_2D_SYM_VISIBLE: yes; WS_DETAIL_SYMBOL: WS_DET_2D_REC_OPG : Sym_02; WS_SYMBOL_OFFSET: 0.04 m; Text - WS_COMMENT_1: UK=OKBP; ID-Daten(Type) - Typenkommentare: WS_Aussparung
Basiswand:WS_WAL_CON_250:3678293 | FB_U01_OKFB | WS_VOI_WAL_REC | 2 | WS_VOI_WAL_REC | WS_VOI_WAL_REC: WS_VOI_WAL_REC | 3678293 | Allgemeines Modell | WS_VOI_WAL_REC | 3394965 | Dü_U01_OKRD_-0,12 | 0.25 | 0.9 | no | no | yes | Phase 1 | WD | Allgemeines Modell | WS_VOI_WAL_REC | 0 | WS_VOI_WAL_REC | Modelleigenschaften - WS_DUMMY_EXTENSION_BOT: -0.1 m; WS_DUMMY_EXTENSION_TOP: 2 m; Abhängigkeiten - Höhe von Ebene: 2.20354e-09 m; Bemaßungen - Fläche: 0.342 m2; Height: 0.88 m; Höhe: 0.88 m; Volumen: 0.0126 m3; WS_HEIGHT: 0.88 m; Grafiken - WS_2D_SYM_VISIBLE: yes; WS_DETAIL_SYMBOL: WS_DET_2D_REC_OPG : Sym_02; WS_SYMBOL_OFFSET: 0.04 m; Text - WS_COMMENT_1: UK=OKBP; ID-Daten(Type) - Typenkommentare: WS_Aussparung
Basiswand:WS_WAL_CON_250:3678293 | FB_U01_OKFB | WS_VOI_WAL_REC | 2 | WS_VOI_WAL_REC | WS_VOI_WAL_REC: WS_VOI_WAL_REC | 3678293 | Allgemeines Modell | WS_VOI_WAL_REC | 3394965 | Dü_U01_OKRD_-0,12 | 0.25 | 0.8 | no | no | yes | Phase 1 | WD | Allgemeines Modell | WS_VOI_WAL_REC | 0 | WS_VOI_WAL_REC | Modelleigenschaften - WS_DUMMY_EXTENSION_BOT: -0.1 m; WS_DUMMY_EXTENSION_TOP: 2 m; Abhängigkeiten - Höhe von Ebene: 2.20354e-09 m; Bemaßungen - Fläche: 0.342 m2; Height: 0.88 m; Höhe: 0.88 m; Volumen: 0.0126 m3; WS_HEIGHT: 0.88 m; Grafiken - WS_2D_SYM_VISIBLE: yes; WS_DETAIL_SYMBOL: WS_DET_2D_REC_OPG : Sym_02; WS_SYMBOL_OFFSET: 0.04 m; Text - WS_COMMENT_1: UK=OKBP; ID-Daten(Type) - Typenkommentare: WS_Aussparung
Basiswand:WS_WAL_CON_250:3678293 | FB_U01_OKFB | WS_VOI_WAL_REC | 2 | WS_VOI_WAL_REC | WS_VOI_WAL_REC: WS_VOI_WAL_REC | 3678293 | Allgemeines Modell | WS_VOI_WAL_REC | 3394965 | Dü_U01_OKRD_-0,12 | 0.25 | 0.8 | no | no | yes | Phase 1 | WD | Allgemeines Modell | WS_VOI_WAL_REC | 0 | WS_VOI_WAL_REC | Modelleigenschaften - WS_DUMMY_EXTENSION_BOT: -0.1 m; WS_DUMMY_EXTENSION_TOP: 2 m; Abhängigkeiten - Höhe von Ebene: 2.20355e-09 m; Bemaßungen - Fläche: 0.342 m2; Height: 0.88 m; Höhe: 0.88 m; Volumen: 0.0126 m3; WS_HEIGHT: 0.88 m; Grafiken - WS_2D_SYM_VISIBLE: yes; WS_DETAIL_SYMBOL: WS_DET_2D_REC_OPG : Sym_02; WS_SYMBOL_OFFSET: 0.04 m; Text - WS_COMMENT_1: UK=OKBP; ID-Daten(Type) - Typenkommentare: WS_Aussparung
Basiswand:WS_WAL_CON_250:3678293 | FB_U01_OKFB | WS_VOI_WAL_REC | 2 | WS_VOI_WAL_REC | WS_VOI_WAL_REC: WS_VOI_WAL_REC | 3678293 | Allgemeines Modell | WS_VOI_WAL_REC | 3394965 | Dü_U01_OKRD_-0,12 | 0.25 | 0.3 | yes | no | yes | Phase 1 | KBZ | Allgemeines Modell | WS_VOI_WAL_REC | 0 | WS_VOI_WAL_REC | Modelleigenschaften - WS_DUMMY_EXTENSION_BOT: -1 m; WS_DUMMY_EXTENSION_TOP: 0.1 m; Abhängigkeiten - Höhe von Ebene: 3.105 m; Bemaßungen - Fläche: 0.182 m2; Height: 0.8 m; Höhe: 0.8 m; Volumen: 0.0066 m3; WS_HEIGHT: 0.8 m; Grafiken - WS_2D_SYM_VISIBLE: yes; WS_DETAIL_SYMBOL: WS_DET_2D_REC_OPG : Sym_02; WS_SYMBOL_OFFSET: 0.04 m; Text - WS_COMMENT_1: OK=UKRD; ID-Daten(Type) - Typenkommentare: WS_Aussparung
Basiswand:WS_WAL_CON_250:3678293 | FB_U01_OKFB | WS_VOI_WAL_REC | 2 | WS_VOI_WAL_REC | WS_VOI_WAL_REC: WS_VOI_WAL_REC | 3678293 | Allgemeines Modell | WS_VOI_WAL_REC | 3394965 | Dü_U01_OKRD_-0,12 | 0.25 | 0.699344 | no | no | yes | Phase 1 | WD | Allgemeines Modell | WS_VOI_WAL_REC | 0 | WS_VOI_WAL_REC | Modelleigenschaften - WS_DUMMY_EXTENSION_BOT: -2 m; WS_DUMMY_EXTENSION_TOP: 0.01 m; Abhängigkeiten - Höhe von Ebene: 3.705 m; Bemaßungen - Fläche: 0.3276 m2; Height: 0.2 m; Höhe: 0.2 m; Volumen: 0.01206 m3; WS_HEIGHT: 0.2 m; Grafiken - WS_2D_SYM_VISIBLE: yes; WS_DETAIL_SYMBOL: WS_DET_2D_REC_OPG : Sym_02; WS_SYMBOL_OFFSET: 0.04 m; Text - WS_COMMENT_1: OK=UKRD; ID-Daten(Type) - Typenkommentare: WS_Aussparung
Basiswand:WS_WAL_CON_250:3678293 | FB_U01_OKFB | WS_VOI_WAL_REC | 2 | WS_VOI_WAL_REC | WS_VOI_WAL_REC: WS_VOI_WAL_REC | 3687736 | Allgemeines Modell | WS_VOI_WAL_REC | 3394965 | Dü_U01_OKRD_-0,12 | 0.25 | 0.6 | no | no | yes | Phase 1 | WD | Allgemeines Modell | WS_VOI_WAL_REC | 0 | WS_VOI_WAL_REC | Modelleigenschaften - WS_DUMMY_EXTENSION_BOT: -0.01 m; WS_DUMMY_EXTENSION_TOP: 2.5 m; Abhängigkeiten - Höhe von Ebene: 2.20355e-09 m; Bemaßungen - Fläche: 0.4076 m2; Height: 0.2 m; Höhe: 0.2 m; Volumen: 0.01506 m3; WS_HEIGHT: 0.2 m; Grafiken - WS_2D_SYM_VISIBLE: yes; WS_DETAIL_SYMBOL: WS_DET_2D_REC_OPG : Sym_02; WS_SYMBOL_OFFSET: 0.04 m; Text - WS_COMMENT_1: UK=OKBP; ID-Daten(Type) - Typenkommentare: WS_Aussparung
Basiswand:WS_WAL_CON_250:3678293 | FB_U01_OKFB | WS_VOI_WAL_REC | 2 | WS_VOI_WAL_REC | WS_VOI_WAL_REC: WS_VOI_WAL_REC | 3687736 | Allgemeines Modell | WS_VOI_WAL_REC | 3394965 | Dü_U01_OKRD_-0,12 | 0.25 | 0.9 | no | no | yes | Phase 1 | WD | Allgemeines Modell | WS_VOI_WAL_REC | 0 | WS_VOI_WAL_REC | Modelleigenschaften - WS_DUMMY_EXTENSION_BOT: -0.1 m; WS_DUMMY_EXTENSION_TOP: 2 m; Abhängigkeiten - Höhe von Ebene: 2.20356e-09 m; Bemaßungen - Fläche: 0.342 m2; Height: 0.88 m; Höhe: 0.88 m; Volumen: 0.0126 m3; WS_HEIGHT: 0.88 m; Grafiken - WS_2D_SYM_VISIBLE: yes; WS_DETAIL_SYMBOL: WS_DET_2D_REC_OPG : Sym_02; WS_SYMBOL_OFFSET: 0.04 m; Text - WS_COMMENT_1: UK=OKBP; ID-Daten(Type) - Typenkommentare: WS_Aussparung
Basiswand:WS_WAL_CON_250:3678293 | FB_U01_OKFB | WS_VOI_CIR | 2 | WS_VOI_CIR | WS_VOI_CIR: WS_VOI_CIR |  | Allgemeines Modell | WS_VOI_CIR | 3402115 | BP_UG1_OKBP_-3,87 | 0.25 |  |  |  |  | Phase 1 | KB Ø26cm | Allgemeines Modell | WS_VOI_CIR | 1.2 | WS_VOI_CIR | Werner Sobek | Abhängigkeiten - Höhe von Ebene: 7.29 m; Basisbauteil: <nicht verknüpft>; Bauteillistenebene: BP_UG1_OKBP_-3,87; WS_DIAMETER: 0.26 m; Text - WS_COMMENT_1: OK=UKRD -30cm=+3,55
Basiswand:WS_WAL_CON_250:3679313 | FB_U01_OKFB | WS_VOI_WAL_REC | 2 | WS_VOI_WAL_REC | WS_VOI_WAL_REC: WS_VOI_WAL_REC | 3679501 | Allgemeines Modell | WS_VOI_WAL_REC | 3394965 | Dü_U01_OKRD_-0,12 | 0.25 | 0.65 | no | no | yes | Phase 1 | KBZ | Allgemeines Modell | WS_VOI_WAL_REC | 0 | WS_VOI_WAL_REC | Modelleigenschaften - WS_DUMMY_EXTENSION_BOT: -1 m; WS_DUMMY_EXTENSION_TOP: 0.5 m; Abhängigkeiten - Höhe von Ebene: 3.255 m; Bemaßungen - Fläche: 0.246 m2; Height: 0.65 m; Höhe: 0.65 m; Volumen: 0.009 m3; WS_HEIGHT: 0.65 m; Grafiken - WS_2D_SYM_VISIBLE: yes; WS_DETAIL_SYMBOL: WS_DET_2D_REC_OPG : Sym_02; WS_SYMBOL_OFFSET: 0.04 m; Text - WS_COMMENT_1: OK=UKRD; ID-Daten(Type) - Typenkommentare: WS_Aussparung
2 x Basiswand:WS_WAL_CON_250:3679501 | FB_U01_OKFB | WS_VOI_WAL_REC | 2 | WS_VOI_WAL_REC | WS_VOI_WAL_REC: WS_VOI_WAL_REC | 3679501 | Allgemeines Modell | WS_VOI_WAL_REC | 3394965 | Dü_U01_OKRD_-0,12 | 0.25 | 0.8 | no | no | yes | Phase 1 | WD | Allgemeines Modell | WS_VOI_WAL_REC | 0 | WS_VOI_WAL_REC | Modelleigenschaften - WS_DUMMY_EXTENSION_BOT: -1 m; WS_DUMMY_EXTENSION_TOP: 0.5 m; Abhängigkeiten - Höhe von Ebene: 3.255 m; Bemaßungen - Fläche: 0.246 m2; Height: 0.65 m; Höhe: 0.65 m; Volumen: 0.009 m3; WS_HEIGHT: 0.65 m; Grafiken - WS_2D_SYM_VISIBLE: yes; WS_DETAIL_SYMBOL: WS_DET_2D_REC_OPG : Sym_02; WS_SYMBOL_OFFSET: 0.04 m; Text - WS_COMMENT_1: OK=UKRD; ID-Daten(Type) - Typenkommentare: WS_Aussparung
Basiswand:WS_WAL_CON_250:3679501 | FB_U01_OKFB | WS_VOI_WAL_REC | 2 | WS_VOI_WAL_REC | WS_VOI_WAL_REC: WS_VOI_WAL_REC | 3679501 | Allgemeines Modell | WS_VOI_WAL_REC | 3394965 | Dü_U01_OKRD_-0,12 | 0.25 | 0.75 | no | no | yes | Phase 1 | WD | Allgemeines Modell | WS_VOI_WAL_REC | 0 | WS_VOI_WAL_REC | Modelleigenschaften - WS_DUMMY_EXTENSION_BOT: -1 m; WS_DUMMY_EXTENSION_TOP: 0.5 m; Abhängigkeiten - Höhe von Ebene: 3.455 m; Bemaßungen - Fläche: 0.246 m2; Height: 0.45 m; Höhe: 0.45 m; Volumen: 0.009 m3; WS_HEIGHT: 0.45 m; Grafiken - WS_2D_SYM_VISIBLE: yes; WS_DETAIL_SYMBOL: WS_DET_2D_REC_OPG : Sym_02; WS_SYMBOL_OFFSET: 0.04 m; Text - WS_COMMENT_1: OK=UKRD; ID-Daten(Type) - Typenkommentare: WS_Aussparung
Basiswand:WS_WAL_CON_250:3679501 | FB_U01_OKFB | WS_VOI_WAL_REC | 2 | WS_VOI_WAL_REC | WS_VOI_WAL_REC: WS_VOI_WAL_REC | 3679501 | Allgemeines Modell | WS_VOI_WAL_REC | 3394965 | Dü_U01_OKRD_-0,12 | 0.25 | 0.65 | no | no | yes | Phase 1 | KBZ | Allgemeines Modell | WS_VOI_WAL_REC | 0 | WS_VOI_WAL_REC | Modelleigenschaften - WS_DUMMY_EXTENSION_BOT: -1 m; WS_DUMMY_EXTENSION_TOP: 0.5 m; Abhängigkeiten - Höhe von Ebene: 3.255 m; Bemaßungen - Fläche: 0.246 m2; Height: 0.65 m; Höhe: 0.65 m; Volumen: 0.009 m3; WS_HEIGHT: 0.65 m; Grafiken - WS_2D_SYM_VISIBLE: yes; WS_DETAIL_SYMBOL: WS_DET_2D_REC_OPG : Sym_02; WS_SYMBOL_OFFSET: 0.04 m; Text - WS_COMMENT_1: OK=UKRD; ID-Daten(Type) - Typenkommentare: WS_Aussparung
Basiswand:WS_WAL_CON_250:3679661 | FB_U01_OKFB | WS_VOI_WAL_REC | 2 | WS_VOI_WAL_REC | WS_VOI_WAL_REC: WS_VOI_WAL_REC | 3679661 | Allgemeines Modell | WS_VOI_WAL_REC | 3394965 | Dü_U01_OKRD_-0,12 | 0.25 | 0.9 | no | no | yes | Phase 1 | WD | Allgemeines Modell | WS_VOI_WAL_REC | 0 | WS_VOI_WAL_REC | Modelleigenschaften - WS_DUMMY_EXTENSION_BOT: -0.01 m; WS_DUMMY_EXTENSION_TOP: 2 m; Abhängigkeiten - Höhe von Ebene: 0 m; Bemaßungen - Fläche: 0.3276 m2; Height: 0.9 m; Höhe: 0.9 m; Volumen: 0.01206 m3; WS_HEIGHT: 0.9 m; Grafiken - WS_2D_SYM_VISIBLE: yes; WS_DETAIL_SYMBOL: WS_DET_2D_REC_OPG : Sym_02; WS_SYMBOL_OFFSET: 0.04 m; Text - WS_COMMENT_1: UK=OKBP; ID-Daten(Type) - Typenkommentare: WS_Aussparung
Basiswand:WS_WAL_CON_250:3679661 | FB_U01_OKFB | WS_VOI_WAL_REC | 2 | WS_VOI_WAL_REC | WS_VOI_WAL_REC: WS_VOI_WAL_REC | 3679661 | Allgemeines Modell | WS_VOI_WAL_REC | 3394965 | Dü_U01_OKRD_-0,12 | 0.25 | 0.55 | no | no | yes | Phase 1 | WD | Allgemeines Modell | WS_VOI_WAL_REC | 0 | WS_VOI_WAL_REC | Modelleigenschaften - WS_DUMMY_EXTENSION_BOT: -0.01 m; WS_DUMMY_EXTENSION_TOP: 2 m; Abhängigkeiten - Höhe von Ebene: 0.37 m; Bemaßungen - Fläche: 0.3276 m2; Height: 0.6 m; Höhe: 0.6 m; Volumen: 0.01206 m3; WS_HEIGHT: 0.6 m; Grafiken - WS_2D_SYM_VISIBLE: yes; WS_DETAIL_SYMBOL: WS_DET_2D_REC_OPG : Sym_02; WS_SYMBOL_OFFSET: 0.04 m; Text - WS_COMMENT_1: UK=OKBP +37cm; ID-Daten(Type) - Typenkommentare: WS_Aussparung
Basiswand:WS_WAL_CON_250:3679661 | FB_U01_OKFB | WS_VOI_WAL_REC | 2 | WS_VOI_WAL_REC | WS_VOI_WAL_REC: WS_VOI_WAL_REC | 3679661 | Allgemeines Modell | WS_VOI_WAL_REC | 3394965 | Dü_U01_OKRD_-0,12 | 0.25 | 1.4 | no | no | yes | Phase 1 | WD | Allgemeines Modell | WS_VOI_WAL_REC | 0 | WS_VOI_WAL_REC | Modelleigenschaften - WS_DUMMY_EXTENSION_BOT: -0.01 m; WS_DUMMY_EXTENSION_TOP: 2.5 m; Abhängigkeiten - Höhe von Ebene: 0.425 m; Bemaßungen - Fläche: 0.4076 m2; Height: 0.25 m; Höhe: 0.25 m; Volumen: 0.01506 m3; WS_HEIGHT: 0.25 m; Grafiken - WS_2D_SYM_VISIBLE: yes; WS_DETAIL_SYMBOL: WS_DET_2D_REC_OPG : Sym_02; WS_SYMBOL_OFFSET: 0.04 m; Text - WS_COMMENT_1: UK=OKBP +42,5cm; ID-Daten(Type) - Typenkommentare: WS_Aussparung
Basiswand:WS_WAL_CON_250:3683917 | FB_U01_OKFB | WS_VOI_WAL_REC | 2 | WS_VOI_WAL_REC | WS_VOI_WAL_REC: WS_VOI_WAL_REC | 3683917 | Allgemeines Modell | WS_VOI_WAL_REC | 3394965 | Dü_U01_OKRD_-0,12 | 0.25 | 0.699344 | no | no | yes | Phase 1 | WD | Allgemeines Modell | WS_VOI_WAL_REC | 0 | WS_VOI_WAL_REC | Modelleigenschaften - WS_DUMMY_EXTENSION_BOT: -2 m; WS_DUMMY_EXTENSION_TOP: 0.01 m; Abhängigkeiten - Höhe von Ebene: 3.705 m; Bemaßungen - Fläche: 0.3276 m2; Height: 0.2 m; Höhe: 0.2 m; Volumen: 0.01206 m3; WS_HEIGHT: 0.2 m; Grafiken - WS_2D_SYM_VISIBLE: yes; WS_DETAIL_SYMBOL: WS_DET_2D_REC_OPG : Sym_02; WS_SYMBOL_OFFSET: 0.04 m; Text - WS_COMMENT_1: OK=UKRD; ID-Daten(Type) - Typenkommentare: WS_Aussparung
Basiswand:WS_WAL_CON_250:3683917 | FB_U01_OKFB | WS_VOI_WAL_REC | 2 | WS_VOI_WAL_REC | WS_VOI_WAL_REC: WS_VOI_WAL_REC | 3683917 | Allgemeines Modell | WS_VOI_WAL_REC | 3394965 | Dü_U01_OKRD_-0,12 | 0.25 | 0.37504 | no | no | yes | Phase 1 | WD | Allgemeines Modell | WS_VOI_WAL_REC | 0 | WS_VOI_WAL_REC | Modelleigenschaften - WS_DUMMY_EXTENSION_BOT: -2 m; WS_DUMMY_EXTENSION_TOP: 0.01 m; Abhängigkeiten - Höhe von Ebene: 3.505 m; Bemaßungen - Fläche: 0.3276 m2; Height: 0.4 m; Höhe: 0.4 m; Volumen: 0.01206 m3; WS_HEIGHT: 0.4 m; Grafiken - WS_2D_SYM_VISIBLE: yes; WS_DETAIL_SYMBOL: WS_DET_2D_REC_OPG : Sym_02; WS_SYMBOL_OFFSET: 0.04 m; Text - WS_COMMENT_1: OK=UKRD; ID-Daten(Type) - Typenkommentare: WS_Aussparung
Geschossdecke:WS_SLB_CON_250:3684240 | FB_E00_OKFB | WS_VOI_SLB_REC | 2 | WS_VOI_SLB_REC | WS_VOI_SLB_REC: WS_VOI_SLB_REC | 3684240 | Allgemeines Modell | WS_VOI_SLB_REC | 3396807 | Dü_U01_OKBP_+0,78 |  | 2.04996 | no | yes | no | Phase 1 | U1 | Allgemeines Modell | WS_VOI_SLB_REC | 0 | WS_VOI_SLB_REC | Werner Sobek | Abhängigkeiten - Verschieben mit umliegenden Elementen: no; Bemaßungen - WS_LENGTH: 1.7 m; Grafiken - WS_Aussparung_Symboltyp: WS_DET_2D_REC_OPG_SLB : WS_SYM_REC_OPG_SLB_02
Geschossdecke:WS_SLB_CON_250:3684240 | FB_E00_OKFB | WS_VOI_REC | 2 | WS_VOI_REC | WS_VOI_REC: WS_VOI_REC |  | Allgemeines Modell | WS_VOI_REC | 3401340 | BP_UG1_OKBP_-3,87 | -0.12 | 1.825 |  |  |  | Phase 1 | DA 1,825/13/12 | Abhängigkeiten - Höhe von Ebene: 4.65 m; Basisbauteil: <nicht verknüpft>; Bauteillistenebene: BP_UG1_OKBP_-3,87; Bemaßungen - WS_HEIGHT: 0.13 m; Text - WS_COMMENT_1: UK = +0,66m
Basiswand:WS_WAL_CON_250:3687736 | FB_U01_OKFB | WS_VOI_WAL_REC | 2 | WS_VOI_WAL_REC | WS_VOI_WAL_REC: WS_VOI_WAL_REC | 3687736 | Allgemeines Modell | WS_VOI_WAL_REC | 3394965 | Dü_U01_OKRD_-0,12 | 0.25 | 0.6 | no | no | yes | Phase 1 | WD | Allgemeines Modell | WS_VOI_WAL_REC | 0 | WS_VOI_WAL_REC | Modelleigenschaften - WS_DUMMY_EXTENSION_BOT: -0.01 m; WS_DUMMY_EXTENSION_TOP: 2.5 m; Abhängigkeiten - Höhe von Ebene: 2.20355e-09 m; Bemaßungen - Fläche: 0.4076 m2; Height: 0.2 m; Höhe: 0.2 m; Volumen: 0.01506 m3; WS_HEIGHT: 0.2 m; Grafiken - WS_2D_SYM_VISIBLE: yes; WS_DETAIL_SYMBOL: WS_DET_2D_REC_OPG : Sym_02; WS_SYMBOL_OFFSET: 0.04 m; Text - WS_COMMENT_1: UK=OKBP; ID-Daten(Type) - Typenkommentare: WS_Aussparung
Basiswand:WS_WAL_CON_250:3687736 | FB_U01_OKFB | WS_VOI_WAL_REC | 2 | WS_VOI_WAL_REC | WS_VOI_WAL_REC: WS_VOI_WAL_REC | 3687736 | Allgemeines Modell | WS_VOI_WAL_REC | 3394965 | Dü_U01_OKRD_-0,12 | 0.25 | 0.9 | no | no | yes | Phase 1 | WD | Allgemeines Modell | WS_VOI_WAL_REC | 0 | WS_VOI_WAL_REC | Modelleigenschaften - WS_DUMMY_EXTENSION_BOT: -0.1 m; WS_DUMMY_EXTENSION_TOP: 2 m; Abhängigkeiten - Höhe von Ebene: 2.20356e-09 m; Bemaßungen - Fläche: 0.342 m2; Height: 0.88 m; Höhe: 0.88 m; Volumen: 0.0126 m3; WS_HEIGHT: 0.88 m; Grafiken - WS_2D_SYM_VISIBLE: yes; WS_DETAIL_SYMBOL: WS_DET_2D_REC_OPG : Sym_02; WS_SYMBOL_OFFSET: 0.04 m; Text - WS_COMMENT_1: UK=OKBP; ID-Daten(Type) - Typenkommentare: WS_Aussparung
2 x Basiswand:WS_WAL_CON_250:3687736 | FB_U01_OKFB | WS_VOI_WAL_REC | 2 | WS_VOI_WAL_REC | WS_VOI_WAL_REC: WS_VOI_WAL_REC | 3678293 | Allgemeines Modell | WS_VOI_WAL_REC | 3394965 | Dü_U01_OKRD_-0,12 | 0.25 | 0.9 | no | no | yes | Phase 1 | WD | Allgemeines Modell | WS_VOI_WAL_REC | 0 | WS_VOI_WAL_REC | Modelleigenschaften - WS_DUMMY_EXTENSION_BOT: -0.1 m; WS_DUMMY_EXTENSION_TOP: 2 m; Abhängigkeiten - Höhe von Ebene: 0 m; Bemaßungen - Fläche: 0.342 m2; Height: 0.88 m; Höhe: 0.88 m; Volumen: 0.0126 m3; WS_HEIGHT: 0.88 m; Grafiken - WS_2D_SYM_VISIBLE: yes; WS_DETAIL_SYMBOL: WS_DET_2D_REC_OPG : Sym_02; WS_SYMBOL_OFFSET: 0.04 m; Text - WS_COMMENT_1: UK=OKBP; ID-Daten(Type) - Typenkommentare: WS_Aussparung
Basiswand:WS_WAL_CON_250:3687736 | FB_U01_OKFB | WS_VOI_WAL_REC | 2 | WS_VOI_WAL_REC | WS_VOI_WAL_REC: WS_VOI_WAL_REC | 3678293 | Allgemeines Modell | WS_VOI_WAL_REC | 3394965 | Dü_U01_OKRD_-0,12 | 0.25 | 0.7 | no | no | yes | Phase 1 | WD | Allgemeines Modell | WS_VOI_WAL_REC | 0 | WS_VOI_WAL_REC | Modelleigenschaften - WS_DUMMY_EXTENSION_BOT: -0.1 m; WS_DUMMY_EXTENSION_TOP: 2 m; Abhängigkeiten - Höhe von Ebene: 0 m; Bemaßungen - Fläche: 0.342 m2; Height: 0.88 m; Höhe: 0.88 m; Volumen: 0.0126 m3; WS_HEIGHT: 0.88 m; Grafiken - WS_2D_SYM_VISIBLE: yes; WS_DETAIL_SYMBOL: WS_DET_2D_REC_OPG : Sym_02; WS_SYMBOL_OFFSET: 0.04 m; Text - WS_COMMENT_1: UK=OKBP; ID-Daten(Type) - Typenkommentare: WS_Aussparung
Basiswand:WS_WAL_CON_250:3687736 | FB_U01_OKFB | WS_VOI_WAL_REC | 2 | WS_VOI_WAL_REC | WS_VOI_WAL_REC: WS_VOI_WAL_REC | 3678293 | Allgemeines Modell | WS_VOI_WAL_REC | 3394965 | Dü_U01_OKRD_-0,12 | 0.25 | 0.9 | no | no | yes | Phase 1 | WD | Allgemeines Modell | WS_VOI_WAL_REC | 0 | WS_VOI_WAL_REC | Modelleigenschaften - WS_DUMMY_EXTENSION_BOT: -0.1 m; WS_DUMMY_EXTENSION_TOP: 2 m; Abhängigkeiten - Höhe von Ebene: 2.20354e-09 m; Bemaßungen - Fläche: 0.342 m2; Height: 0.88 m; Höhe: 0.88 m; Volumen: 0.0126 m3; WS_HEIGHT: 0.88 m; Grafiken - WS_2D_SYM_VISIBLE: yes; WS_DETAIL_SYMBOL: WS_DET_2D_REC_OPG : Sym_02; WS_SYMBOL_OFFSET: 0.04 m; Text - WS_COMMENT_1: UK=OKBP; ID-Daten(Type) - Typenkommentare: WS_Aussparung
Basiswand:WS_WAL_CON_250:3687736 | FB_U01_OKFB | WS_VOI_WAL_REC | 2 | WS_VOI_WAL_REC | WS_VOI_WAL_REC: WS_VOI_WAL_REC | 3678293 | Allgemeines Modell | WS_VOI_WAL_REC | 3394965 | Dü_U01_OKRD_-0,12 | 0.25 | 0.8 | no | no | yes | Phase 1 | WD | Allgemeines Modell | WS_VOI_WAL_REC | 0 | WS_VOI_WAL_REC | Modelleigenschaften - WS_DUMMY_EXTENSION_BOT: -0.1 m; WS_DUMMY_EXTENSION_TOP: 2 m; Abhängigkeiten - Höhe von Ebene: 2.20354e-09 m; Bemaßungen - Fläche: 0.342 m2; Height: 0.88 m; Höhe: 0.88 m; Volumen: 0.0126 m3; WS_HEIGHT: 0.88 m; Grafiken - WS_2D_SYM_VISIBLE: yes; WS_DETAIL_SYMBOL: WS_DET_2D_REC_OPG : Sym_02; WS_SYMBOL_OFFSET: 0.04 m; Text - WS_COMMENT_1: UK=OKBP; ID-Daten(Type) - Typenkommentare: WS_Aussparung
Basiswand:WS_WAL_CON_250:3687736 | FB_U01_OKFB | WS_VOI_WAL_REC | 2 | WS_VOI_WAL_REC | WS_VOI_WAL_REC: WS_VOI_WAL_REC | 3678293 | Allgemeines Modell | WS_VOI_WAL_REC | 3394965 | Dü_U01_OKRD_-0,12 | 0.25 | 0.8 | no | no | yes | Phase 1 | WD | Allgemeines Modell | WS_VOI_WAL_REC | 0 | WS_VOI_WAL_REC | Modelleigenschaften - WS_DUMMY_EXTENSION_BOT: -0.1 m; WS_DUMMY_EXTENSION_TOP: 2 m; Abhängigkeiten - Höhe von Ebene: 2.20355e-09 m; Bemaßungen - Fläche: 0.342 m2; Height: 0.88 m; Höhe: 0.88 m; Volumen: 0.0126 m3; WS_HEIGHT: 0.88 m; Grafiken - WS_2D_SYM_VISIBLE: yes; WS_DETAIL_SYMBOL: WS_DET_2D_REC_OPG : Sym_02; WS_SYMBOL_OFFSET: 0.04 m; Text - WS_COMMENT_1: UK=OKBP; ID-Daten(Type) - Typenkommentare: WS_Aussparung
Geschossdecke:WS_SLB_CON_250_WT:3689124 | FB_U01_OKFB | WS_VOI_SLB_REC | 2 | WS_VOI_SLB_REC | WS_VOI_SLB_REC: WS_VOI_SLB_REC | 3671416 | Allgemeines Modell | WS_VOI_SLB_REC | 3396807 | Dü_U01_OKRD_-0,12 |  | 0.5 | no | yes | no | Phase 1 | DD | Allgemeines Modell | WS_VOI_SLB_REC | 0 | WS_VOI_SLB_REC | Werner Sobek | Abhängigkeiten - Verschieben mit umliegenden Elementen: no; Bemaßungen - WS_LENGTH: 0.14 m; Grafiken - WS_Aussparung_Symboltyp: WS_DET_2D_REC_OPG_SLB : WS_SYM_REC_OPG_SLB_02
Geschossdecke:WS_SLB_CON_250_WT:3689124 | FB_U01_OKFB | WS_VOI_SLB_REC | 2 | WS_VOI_SLB_REC | WS_VOI_SLB_REC: WS_VOI_SLB_REC | 3671416 | Allgemeines Modell | WS_VOI_SLB_REC | 3396807 | Dü_U01_OKRD_-0,12 |  | 0.2 | no | yes | no | Phase 1 | DD | Allgemeines Modell | WS_VOI_SLB_REC | 0 | WS_VOI_SLB_REC | Werner Sobek | Abhängigkeiten - Verschieben mit umliegenden Elementen: no; Bemaßungen - WS_LENGTH: 1.4 m; Grafiken - WS_Aussparung_Symboltyp: WS_DET_2D_REC_OPG_SLB : WS_SYM_REC_OPG_SLB_02
Geschossdecke:WS_SLB_CON_250:3697365 | FB_E00_OKFB | WS_VOI_SLB_REC | 2 | WS_VOI_SLB_REC | WS_VOI_SLB_REC: WS_VOI_SLB_REC | 3697365 | Allgemeines Modell | WS_VOI_SLB_REC | 3396807 | Dü_EG_OKRD_+3,98 |  | 0.55 | no | yes | no | Phase 1 | DD | Allgemeines Modell | WS_VOI_SLB_REC | 0 | WS_VOI_SLB_REC | Werner Sobek | Abhängigkeiten - Verschieben mit umliegenden Elementen: no; Bemaßungen - WS_LENGTH: 1.75 m; Grafiken - WS_Aussparung_Symboltyp: WS_DET_2D_REC_OPG_SLB : WS_SYM_REC_OPG_SLB_02
Geschossdecke:WS_SLB_CON_250:3697365 | FB_E00_OKFB | WS_VOI_SLB_TOP_REC | 2 | WS_VOI_SLB_TOP_REC | WS_VOI_SLB_TOP_REC: WS_VOI_SLB_TOP_REC | 3697365 | Allgemeines Modell | WS_VOI_SLB_TOP_REC | 3398654 | Dü_EG_OKRD_+3,985 | 0.12 | 0.14 | no | yes | no | Phase 1 | DA | Allgemeines Modell | WS_VOI_SLB_TOP_REC | 0 | WS_VOI_SLB_TOP_REC | Werner Sobek | Text - WS_COMMENT_1: UK = +3,865m; Abhängigkeiten - Verschieben mit umliegenden Elementen: no; Bemaßungen - WS_LENGTH: 1.75 m; Grafiken - WS_Aussparung_Symboltyp: WS_DET_2D_REC_OPG_SLB : WS_SYM_REC_OPG_SLB_01
Geschossdecke:WS_SLB_CON_250:3697365 | FB_E00_OKFB | WS_VOI_SLB_REC | 2 | WS_VOI_SLB_REC | WS_VOI_SLB_REC: WS_VOI_SLB_REC | 3697365 | Allgemeines Modell | WS_VOI_SLB_REC | 3396807 | Dü_EG_OKRD_+3,98 |  | 1.9 | no | yes | no | Phase 1 | DD | Allgemeines Modell | WS_VOI_SLB_REC | 0 | WS_VOI_SLB_REC | Werner Sobek | Abhängigkeiten - Verschieben mit umliegenden Elementen: no; Bemaßungen - WS_LENGTH: 1.75 m; Grafiken - WS_Aussparung_Symboltyp: WS_DET_2D_REC_OPG_SLB : WS_SYM_REC_OPG_SLB_02
Geschossdecke:WS_SLB_CON_250:3698243 | FB_E00_OKFB | WS_VOI_SLB_REC | 2 | WS_VOI_SLB_REC | WS_VOI_SLB_REC: WS_VOI_SLB_REC | 3698243 | Allgemeines Modell | WS_VOI_SLB_REC | 3396807 | Dü_EG_OKRD_+3,68 |  | 0.15 | no | yes | no | Phase 1 | DD | Allgemeines Modell | WS_VOI_SLB_REC | 0 | WS_VOI_SLB_REC | Werner Sobek | Abhängigkeiten - Verschieben mit umliegenden Elementen: no; Bemaßungen - WS_LENGTH: 0.25 m; Grafiken - WS_Aussparung_Symboltyp: WS_DET_2D_REC_OPG_SLB : WS_SYM_REC_OPG_SLB_02
Geschossdecke:WS_SLB_CON_250:3698243 | FB_E00_OKFB | WS_VOI_CIR | 2 | WS_VOI_CIR | WS_VOI_CIR: WS_VOI_CIR |  | Allgemeines Modell | WS_VOI_CIR | 3402115 | Dü_EG_OKRD_+3,68 | -0.25 |  |  |  |  | Phase 1 |  | Allgemeines Modell | WS_VOI_CIR | 1.2 | WS_VOI_CIR | Werner Sobek | Abhängigkeiten - Höhe von Ebene: 0 m; Basisbauteil: Ebene : Dü_EG_OKRD_+3,68; Bauteillistenebene: Dü_EG_OKRD_+3,68; WS_DIAMETER: 0.16 m
Geschossdecke:WS_SLB_CON_250:3698243 | FB_E00_OKFB | WS_VOI_CIR | 2 | WS_VOI_CIR | WS_VOI_CIR: WS_VOI_CIR |  | Allgemeines Modell | WS_VOI_CIR | 3402115 | Dü_EG_OKRD_+3,68 | -0.05 |  |  |  |  | Phase 1 | DA Ø33cm | Allgemeines Modell | WS_VOI_CIR | 1.2 | WS_VOI_CIR | Werner Sobek | Abhängigkeiten - Höhe von Ebene: 0 m; Basisbauteil: Ebene : Dü_EG_OKRD_+3,68; Bauteillistenebene: Dü_EG_OKRD_+3,68; WS_DIAMETER: 0.33 m
7 x Geschossdecke:WS_SLB_CON_250:3698243 | FB_E00_OKFB | WS_VOI_CIR | 2 | WS_VOI_CIR | WS_VOI_CIR: WS_VOI_CIR |  | Allgemeines Modell | WS_VOI_CIR | 3402115 |  | 0.8 |  |  |  |  | Phase 1 | Leerrohr Ø6,3cm durch ÜZ und Decke | Allgemeines Modell | WS_VOI_CIR | 1.2 | WS_VOI_CIR | Werner Sobek | Abhängigkeiten - Höhe von Ebene: 0 m; Basisbauteil: <nicht verknüpft>; WS_DIAMETER: 0.063 m
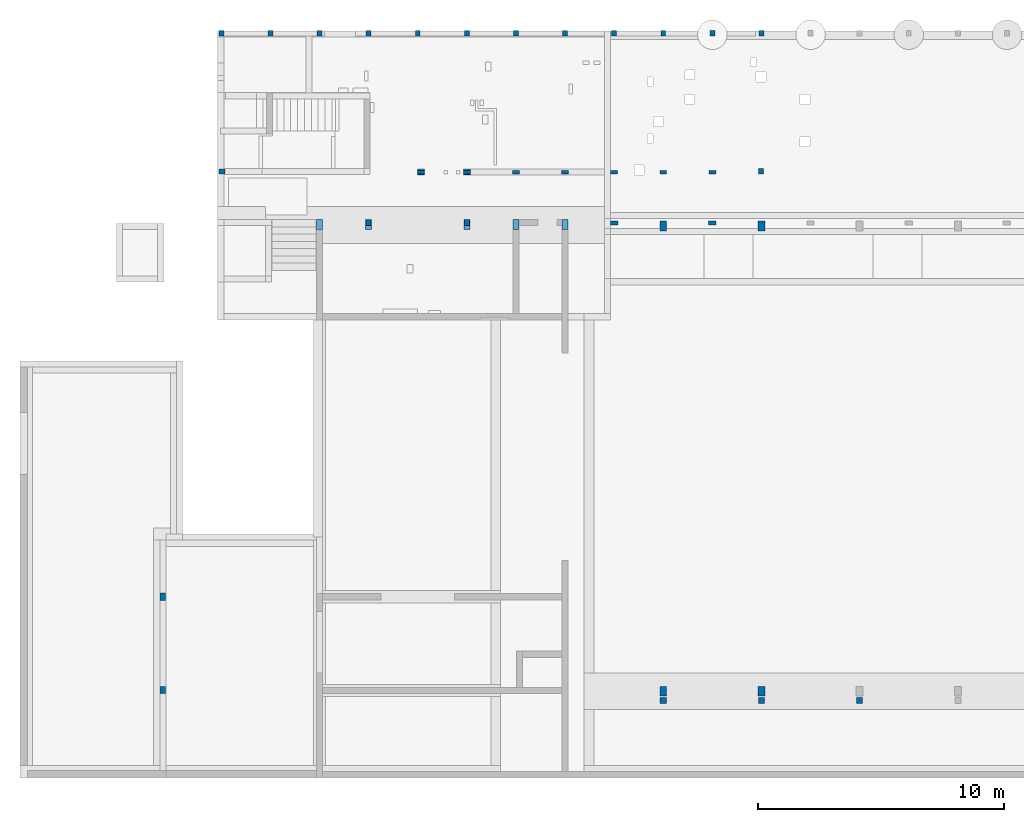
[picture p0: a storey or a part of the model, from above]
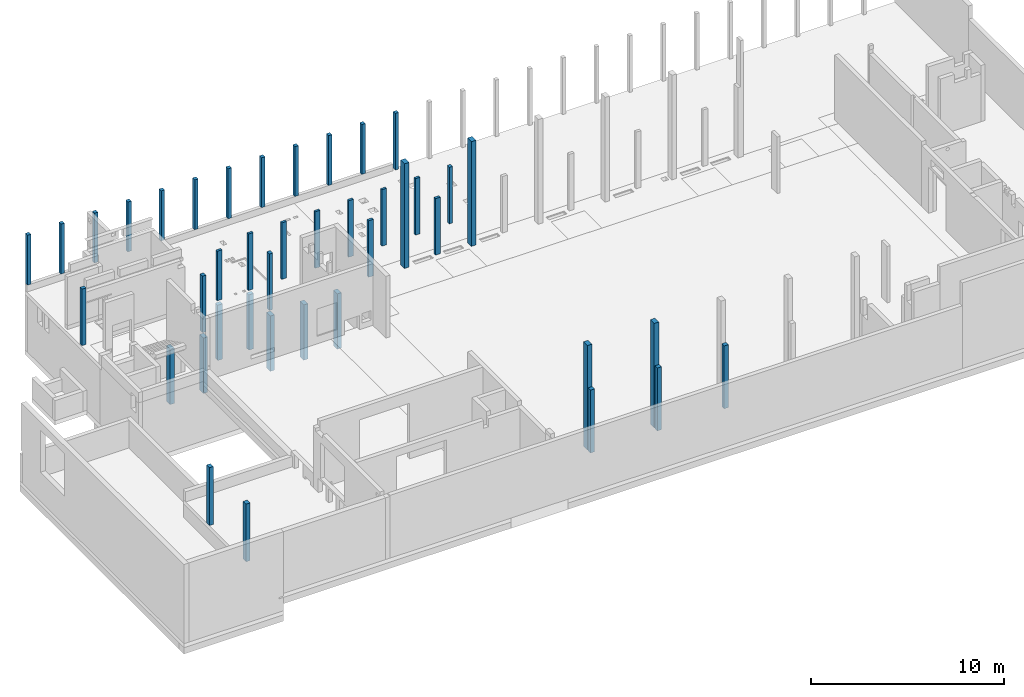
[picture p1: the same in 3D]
Properties of the parts of a building model (IFC2X3), part 4 of 6

# IfcOpeningElement: Opening (280)
Name | In | Reference | sets with these values | Familie | Familie und Typ | Host-ID | Sonstige, Kategorie | Typ | Typ-ID | Ebene | WS_DEPTH (m) | WS_WIDTH (m) | WS_COVER_BACKGROUND | WS_LINES_CONTINUOUS | WS_LINES_HIDDEN = WS_SYMBOL | Phase erstellt | WS_COMMENT | Sonstige(Type), Kategorie | Familienname | Vorgabe-Ansicht (m) | Typname | Hersteller
Geschossdecke:WS_SLB_CON_250:3698243 | FB_E00_OKFB | WS_VOI_CIR | 2 | WS_VOI_CIR | WS_VOI_CIR: WS_VOI_CIR |  | Allgemeines Modell | WS_VOI_CIR | 3402115 |  | 0.8 |  |  |  |  | Phase 1 | 8x Leerrohr Ø6,3cm | Allgemeines Modell | WS_VOI_CIR | 1.2 | WS_VOI_CIR | Werner Sobek | Abhängigkeiten - Höhe von Ebene: 0 m; Basisbauteil: <nicht verknüpft>; WS_DIAMETER: 0.063 m; Text - WS_COMMENT_1: durch ÜZ und Decke
Geschossdecke:WS_SLB_CON_250:3698243 | FB_E00_OKFB | Gussrohr | 2 | Gussrohr | Gussrohr: Gussrohr |  | Allgemeines Modell | Gussrohr | 4722093 |  |  |  |  |  |  | Phase 1 |  | Allgemeines Modell | Gussrohr |  | Gussrohr | Abhängigkeiten - Verschieben mit umliegenden Elementen: no
3 x Geschossdecke:WS_SLB_CON_300:3699280 | FB_E00_OKFB | WS_VOI_CIR | 2 | WS_VOI_CIR | WS_VOI_CIR: WS_VOI_CIR |  | Allgemeines Modell | WS_VOI_CIR | 3402115 | BP_UG1_OKBP_-3,87 | -0.3 |  |  |  |  | Phase 1 |  | Allgemeines Modell | WS_VOI_CIR | 1.2 | WS_VOI_CIR | Werner Sobek | Abhängigkeiten - Höhe von Ebene: 8.02 m; Basisbauteil: <nicht verknüpft>; Bauteillistenebene: BP_UG1_OKBP_-3,87; WS_DIAMETER: 0.16 m
3 x Geschossdecke:WS_SLB_CON_300:3699280 | FB_E00_OKFB | WS_VOI_CIR | 2 | WS_VOI_CIR | WS_VOI_CIR: WS_VOI_CIR |  | Allgemeines Modell | WS_VOI_CIR | 3402115 | BP_UG1_OKBP_-3,87 | -0.05 |  |  |  |  | Phase 1 |  | Allgemeines Modell | WS_VOI_CIR | 1.2 | WS_VOI_CIR | Werner Sobek | Abhängigkeiten - Höhe von Ebene: 8.02 m; Basisbauteil: <nicht verknüpft>; Bauteillistenebene: BP_UG1_OKBP_-3,87; WS_DIAMETER: 0.33 m
Geschossdecke:WS_SLB_CON_250:3702198 | FB_E00_OKFB | WS_VOI_SLB_REC | 2 | WS_VOI_SLB_REC | WS_VOI_SLB_REC: WS_VOI_SLB_REC | 3702198 | Allgemeines Modell | WS_VOI_SLB_REC | 3396807 | Dü_EG_OKRD_+4,035 |  | 0.6 | no | yes | no | Phase 1 | DD | Allgemeines Modell | WS_VOI_SLB_REC | 0 | WS_VOI_SLB_REC | Werner Sobek | Abhängigkeiten - Verschieben mit umliegenden Elementen: no; Bemaßungen - WS_LENGTH: 1.2 m; Grafiken - WS_Aussparung_Symboltyp: WS_DET_2D_REC_OPG_SLB : WS_SYM_REC_OPG_SLB_02
2 x Geschossdecke:WS_SLB_CON_250:3702198 | FB_E00_OKFB | WS_VOI_SLB_REC | 2 | WS_VOI_SLB_REC | WS_VOI_SLB_REC: WS_VOI_SLB_REC | 3702198 | Allgemeines Modell | WS_VOI_SLB_REC | 3396807 | Dü_EG_OKRD_+4,035 |  | 0.4 | no | yes | no | Phase 1 | DD | Allgemeines Modell | WS_VOI_SLB_REC | 0 | WS_VOI_SLB_REC | Werner Sobek | Abhängigkeiten - Verschieben mit umliegenden Elementen: no; Bemaßungen - WS_LENGTH: 0.4 m; Grafiken - WS_Aussparung_Symboltyp: WS_DET_2D_REC_OPG_SLB : WS_SYM_REC_OPG_SLB_02
Geschossdecke:WS_SLB_CON_250:3702198 | FB_E00_OKFB | WS_VOI_SLB_REC | 2 | WS_VOI_SLB_REC | WS_VOI_SLB_REC: WS_VOI_SLB_REC | 3702198 | Allgemeines Modell | WS_VOI_SLB_REC | 3396807 | Dü_EG_OKRD_+4,035 |  | 0.23 | no | yes | no | Phase 1 | DD | Allgemeines Modell | WS_VOI_SLB_REC | 0 | WS_VOI_SLB_REC | Werner Sobek | Abhängigkeiten - Verschieben mit umliegenden Elementen: no; Bemaßungen - WS_LENGTH: 0.23 m; Grafiken - WS_Aussparung_Symboltyp: WS_DET_2D_REC_OPG_SLB : WS_SYM_REC_OPG_SLB_02
Geschossdecke:WS_SLB_CON_250:3702198 | FB_E00_OKFB | WS_VOI_SLB_REC | 2 | WS_VOI_SLB_REC | WS_VOI_SLB_REC: WS_VOI_SLB_REC | 3702198 | Allgemeines Modell | WS_VOI_SLB_REC | 3396807 | Dü_EG_OKRD_+4,035 |  | 0.24996 | no | yes | no | Phase 1 | DD | Allgemeines Modell | WS_VOI_SLB_REC | 0 | WS_VOI_SLB_REC | Werner Sobek | Abhängigkeiten - Verschieben mit umliegenden Elementen: no; Bemaßungen - WS_LENGTH: 0.7 m; Grafiken - WS_Aussparung_Symboltyp: WS_DET_2D_REC_OPG_SLB : WS_SYM_REC_OPG_SLB_02
2 x Geschossdecke:WS_SLB_CON_250:3702198 | FB_E00_OKFB | WS_VOI_SLB_REC | 2 | WS_VOI_SLB_REC | WS_VOI_SLB_REC: WS_VOI_SLB_REC | 3702198 | Allgemeines Modell | WS_VOI_SLB_REC | 3396807 | Dü_EG_OKRD_+4,035 |  | 0.8 | no | yes | no | Phase 1 | DD | Allgemeines Modell | WS_VOI_SLB_REC | 0 | WS_VOI_SLB_REC | Werner Sobek | Abhängigkeiten - Verschieben mit umliegenden Elementen: no; Bemaßungen - WS_LENGTH: 0.6 m; Grafiken - WS_Aussparung_Symboltyp: WS_DET_2D_REC_OPG_SLB : WS_SYM_REC_OPG_SLB_02
Geschossdecke:WS_SLB_CON_250:3702198 | FB_E00_OKFB | WS_VOI_SLB_REC | 2 | WS_VOI_SLB_REC | WS_VOI_SLB_REC: WS_VOI_SLB_REC | 3702198 | Allgemeines Modell | WS_VOI_SLB_REC | 3396807 | Dü_EG_OKRD_+4,035 |  | 0.55 | no | yes | no | Phase 1 | DD | Allgemeines Modell | WS_VOI_SLB_REC | 0 | WS_VOI_SLB_REC | Werner Sobek | Abhängigkeiten - Verschieben mit umliegenden Elementen: no; Bemaßungen - WS_LENGTH: 0.299998 m; Grafiken - WS_Aussparung_Symboltyp: WS_DET_2D_REC_OPG_SLB : WS_SYM_REC_OPG_SLB_02
Geschossdecke:WS_SLB_CON_250:3702198 | FB_E00_OKFB | WS_VOI_SLB_REC | 2 | WS_VOI_SLB_REC | WS_VOI_SLB_REC: WS_VOI_SLB_REC | 3702198 | Allgemeines Modell | WS_VOI_SLB_REC | 3396807 | Dü_EG_OKRD_+4,035 |  | 0.149961 | no | yes | no | Phase 1 | DD | Allgemeines Modell | WS_VOI_SLB_REC | 0 | WS_VOI_SLB_REC | Werner Sobek | Abhängigkeiten - Verschieben mit umliegenden Elementen: no; Bemaßungen - WS_LENGTH: 0.3 m; Grafiken - WS_Aussparung_Symboltyp: WS_DET_2D_REC_OPG_SLB : WS_SYM_REC_OPG_SLB_02
Geschossdecke:WS_SLB_CON_250:3702198 | FB_E00_OKFB | WS_VOI_SLB_REC | 2 | WS_VOI_SLB_REC | WS_VOI_SLB_REC: WS_VOI_SLB_REC | 3702198 | Allgemeines Modell | WS_VOI_SLB_REC | 3396807 | Dü_EG_OKRD_+4,035 |  | 0.12996 | no | yes | no | Phase 1 | DD | Allgemeines Modell | WS_VOI_SLB_REC | 0 | WS_VOI_SLB_REC | Werner Sobek | Abhängigkeiten - Verschieben mit umliegenden Elementen: no; Bemaßungen - WS_LENGTH: 0.4 m; Grafiken - WS_Aussparung_Symboltyp: WS_DET_2D_REC_OPG_SLB : WS_SYM_REC_OPG_SLB_02
2 x Geschossdecke:WS_SLB_CON_250:3702198 | FB_E00_OKFB | WS_VOI_CIR | 2 | WS_VOI_CIR | WS_VOI_CIR: WS_VOI_CIR |  | Allgemeines Modell | WS_VOI_CIR | 3402115 | BP_UG1_OKBP_-3,87 | -0.05 |  |  |  |  | Phase 1 |  | Allgemeines Modell | WS_VOI_CIR | 1.2 | WS_VOI_CIR | Werner Sobek | Abhängigkeiten - Höhe von Ebene: 7.905 m; Basisbauteil: <nicht verknüpft>; Bauteillistenebene: BP_UG1_OKBP_-3,87; WS_DIAMETER: 0.33 m
2 x Geschossdecke:WS_SLB_CON_250:3702198 | FB_E00_OKFB | WS_VOI_CIR | 2 | WS_VOI_CIR | WS_VOI_CIR: WS_VOI_CIR |  | Allgemeines Modell | WS_VOI_CIR | 3402115 | BP_UG1_OKBP_-3,87 | -0.25 |  |  |  |  | Phase 1 |  | Allgemeines Modell | WS_VOI_CIR | 1.2 | WS_VOI_CIR | Werner Sobek | Abhängigkeiten - Höhe von Ebene: 7.905 m; Basisbauteil: <nicht verknüpft>; Bauteillistenebene: BP_UG1_OKBP_-3,87; WS_DIAMETER: 0.16 m
Geschossdecke:WS_SLB_CON_250:3702198 | FB_E00_OKFB | WS_VOI_SLB_REC | 2 | WS_VOI_SLB_REC | WS_VOI_SLB_REC: WS_VOI_SLB_REC | 3702198 | Allgemeines Modell | WS_VOI_SLB_REC | 3396807 | Dü_EG_OKRD_+4,035 |  | 1 | no | yes | no | Phase 1 | DD | Allgemeines Modell | WS_VOI_SLB_REC | 0 | WS_VOI_SLB_REC | Werner Sobek | Abhängigkeiten - Verschieben mit umliegenden Elementen: no; Bemaßungen - WS_LENGTH: 0.3 m; Grafiken - WS_Aussparung_Symboltyp: WS_DET_2D_REC_OPG_SLB : WS_SYM_REC_OPG_SLB_02
Geschossdecke:WS_SLB_CON_250:3702198 | FB_E00_OKFB | WS_VOI_CIR | 2 | WS_VOI_CIR | WS_VOI_CIR: WS_VOI_CIR |  | Allgemeines Modell | WS_VOI_CIR | 3402115 | Dü_EG_OKRD_+4,035 | -0.25 |  |  |  |  | Phase 1 |  | Allgemeines Modell | WS_VOI_CIR | 1.2 | WS_VOI_CIR | Werner Sobek | Abhängigkeiten - Höhe von Ebene: 0 m; Basisbauteil: Ebene : Dü_EG_OKRD_+4,035; Bauteillistenebene: Dü_EG_OKRD_+4,035; WS_DIAMETER: 0.2 m
Geschossdecke:WS_SLB_CON_250:3702850 | FB_E00_OKFB | WS_VOI_SLB_REC | 2 | WS_VOI_SLB_REC | WS_VOI_SLB_REC: WS_VOI_SLB_REC | 3702850 | Allgemeines Modell | WS_VOI_SLB_REC | 3396807 | Dü_EG_OKRD_+4,40 |  | 1.23 | no | yes | no | Phase 1 | DD | Allgemeines Modell | WS_VOI_SLB_REC | 0 | WS_VOI_SLB_REC | Werner Sobek | Abhängigkeiten - Verschieben mit umliegenden Elementen: no; Bemaßungen - WS_LENGTH: 1.61 m; Grafiken - WS_Aussparung_Symboltyp: WS_DET_2D_REC_OPG_SLB : WS_SYM_REC_OPG_SLB_02
Geschossdecke:WS_SLB_CON_250:3702850 | FB_E00_OKFB | WS_VOI_SLB_REC | 2 | WS_VOI_SLB_REC | WS_VOI_SLB_REC: WS_VOI_SLB_REC | 3702850 | Allgemeines Modell | WS_VOI_SLB_REC | 3396807 | Dü_EG_OKRD_+4,40 |  | 2.095 | no | yes | no | Phase 1 | DD | Allgemeines Modell | WS_VOI_SLB_REC | 0 | WS_VOI_SLB_REC | Werner Sobek | Abhängigkeiten - Verschieben mit umliegenden Elementen: no; Bemaßungen - WS_LENGTH: 1.62 m; Grafiken - WS_Aussparung_Symboltyp: WS_DET_2D_REC_OPG_SLB : WS_SYM_REC_OPG_SLB_02
Geschossdecke:WS_SLB_CON_250:3702850 | FB_E00_OKFB | WS_VOI_SLB_REC | 2 | WS_VOI_SLB_REC | WS_VOI_SLB_REC: WS_VOI_SLB_REC | 3702850 | Allgemeines Modell | WS_VOI_SLB_REC | 3396807 | Dü_EG_OKRD_+4,40 |  | 0.22 | no | yes | no | Phase 1 | DD | Allgemeines Modell | WS_VOI_SLB_REC | 0 | WS_VOI_SLB_REC | Werner Sobek | Abhängigkeiten - Verschieben mit umliegenden Elementen: no; Bemaßungen - WS_LENGTH: 0.22 m; Grafiken - WS_Aussparung_Symboltyp: WS_DET_2D_REC_OPG_SLB : WS_SYM_REC_OPG_SLB_02
Basiswand:WS_WAL_CON_250_WT:3708113 | FB_U01_OKFB | WS_VOI_WAL_REC | 2 | WS_VOI_WAL_REC | WS_VOI_WAL_REC: WS_VOI_WAL_REC | 3708113 | Allgemeines Modell | WS_VOI_WAL_REC | 3394965 | Dü_U01_OKRD_-0,12 | 0.25 | 0.5 | yes | no | yes | Phase 1 | KBZ | Allgemeines Modell | WS_VOI_WAL_REC | 0 | WS_VOI_WAL_REC | Modelleigenschaften - WS_DUMMY_EXTENSION_BOT: -1 m; WS_DUMMY_EXTENSION_TOP: 0.1 m; Abhängigkeiten - Höhe von Ebene: -0.8 m; Bemaßungen - Fläche: 0.182 m2; Height: 1 m; Höhe: 1 m; Volumen: 0.0066 m3; WS_HEIGHT: 1 m; Grafiken - WS_2D_SYM_VISIBLE: yes; WS_DETAIL_SYMBOL: WS_DET_2D_REC_OPG : Sym_02; WS_SYMBOL_OFFSET: 0.04 m; Text - WS_COMMENT_1: OK=UKRD -45cm; ID-Daten(Type) - Typenkommentare: WS_Aussparung
Basiswand:WS_WAL_CON_250:3709035 | FB_E00_OKFB | WS_VOI_WAL_REC | 2 | WS_VOI_WAL_REC | WS_VOI_WAL_REC: WS_VOI_WAL_REC | 3709035 | Allgemeines Modell | WS_VOI_WAL_REC | 3394965 | Dü_EG_OKRD_+4,035 | 0.25 | 0.4 | no | no | yes | Phase 1 | WD | Allgemeines Modell | WS_VOI_WAL_REC | 0 | WS_VOI_WAL_REC | Modelleigenschaften - WS_DUMMY_EXTENSION_BOT: -2 m; WS_DUMMY_EXTENSION_TOP: 0.1 m; Abhängigkeiten - Höhe von Ebene: 3.345 m; Bemaßungen - Fläche: 0.342 m2; Height: 0.4 m; Höhe: 0.4 m; Volumen: 0.0126 m3; WS_HEIGHT: 0.4 m; Grafiken - WS_2D_SYM_VISIBLE: yes; WS_DETAIL_SYMBOL: WS_DET_2D_REC_OPG : Sym_02; WS_SYMBOL_OFFSET: 0.04 m; Text - WS_COMMENT_1: OK=UKRD -26cm; ID-Daten(Type) - Typenkommentare: WS_Aussparung
Basiswand:WS_WAL_CON_250:3711501 | FB_E00_OKFB | WS_VOI_WAL_REC | 2 | WS_VOI_WAL_REC | WS_VOI_WAL_REC: WS_VOI_WAL_REC | 3711501 | Allgemeines Modell | WS_VOI_WAL_REC | 3394965 | Dü_EG_OKRD | 0.25 | 0.9 | no | no | yes | Phase 1 | WD | Allgemeines Modell | WS_VOI_WAL_REC | 0 | WS_VOI_WAL_REC | Modelleigenschaften - WS_DUMMY_EXTENSION_BOT: -1 m; WS_DUMMY_EXTENSION_TOP: 0.1 m; Abhängigkeiten - Höhe von Ebene: 0.15 m; Bemaßungen - Fläche: 0.182 m2; Height: 1.75 m; Höhe: 1.75 m; Volumen: 0.0066 m3; WS_HEIGHT: 1.75 m; Grafiken - WS_2D_SYM_VISIBLE: yes; WS_DETAIL_SYMBOL: WS_DET_2D_REC_OPG : Sym_02; WS_SYMBOL_OFFSET: 0.04 m; Text - WS_COMMENT_1: UK=OKRD +10cm = +4,50; ID-Daten(Type) - Typenkommentare: WS_Aussparung
Basiswand:WS_WAL_CON_250:3711878 | FB_E00_OKFB | WS_VOI_WAL_REC | 2 | WS_VOI_WAL_REC | WS_VOI_WAL_REC: WS_VOI_WAL_REC | 3711878 | Allgemeines Modell | WS_VOI_WAL_REC | 3394965 | Dü_EG_OKRD | 0.25 | 0.209954 | no | no | yes | Phase 1 | Auflagertasche | Allgemeines Modell | WS_VOI_WAL_REC | 0 | WS_VOI_WAL_REC | Modelleigenschaften - WS_DUMMY_EXTENSION_BOT: -0.1 m; WS_DUMMY_EXTENSION_TOP: 0.1 m; Abhängigkeiten - Höhe von Ebene: 3.23 m; Bemaßungen - Fläche: 0.038 m2; Height: 0.425 m; Höhe: 0.425 m; Volumen: 0.0012 m3; WS_HEIGHT: 0.425 m; Grafiken - WS_2D_SYM_VISIBLE: yes; WS_DETAIL_SYMBOL: WS_DET_2D_REC_OPG : Sym_02; WS_SYMBOL_OFFSET: 0.04 m; ID-Daten(Type) - Typenkommentare: WS_Aussparung
4 x Basiswand:WS_WAL_CON_250:3711878 | FB_E00_OKFB | WS_VOI_WAL_REC | 2 | WS_VOI_WAL_REC | WS_VOI_WAL_REC: WS_VOI_WAL_REC | 3711878 | Allgemeines Modell | WS_VOI_WAL_REC | 3394965 | Dü_EG_OKRD | 0.25 | 0.14 | no | no | yes | Phase 1 | Auflagertasche | Allgemeines Modell | WS_VOI_WAL_REC | 0 | WS_VOI_WAL_REC | Modelleigenschaften - WS_DUMMY_EXTENSION_BOT: -0.1 m; WS_DUMMY_EXTENSION_TOP: 0.1 m; Abhängigkeiten - Höhe von Ebene: 3.23 m; Bemaßungen - Fläche: 0.038 m2; Height: 0.425 m; Höhe: 0.425 m; Volumen: 0.0012 m3; WS_HEIGHT: 0.425 m; Grafiken - WS_2D_SYM_VISIBLE: yes; WS_DETAIL_SYMBOL: WS_DET_2D_REC_OPG : Sym_02; WS_SYMBOL_OFFSET: 0.04 m; ID-Daten(Type) - Typenkommentare: WS_Aussparung
Basiswand:WS_WAL_CON_250:3711878 | FB_E00_OKFB | WS_VOI_WAL_REC | 2 | WS_VOI_WAL_REC | WS_VOI_WAL_REC: WS_VOI_WAL_REC | 3711878 | Allgemeines Modell | WS_VOI_WAL_REC | 3394965 | Dü_EG_OKRD | 0.25 | 0.13 | no | no | yes | Phase 1 | Auflagertasche | Allgemeines Modell | WS_VOI_WAL_REC | 0 | WS_VOI_WAL_REC | Modelleigenschaften - WS_DUMMY_EXTENSION_BOT: -0.1 m; WS_DUMMY_EXTENSION_TOP: 0.1 m; Abhängigkeiten - Höhe von Ebene: 3.23 m; Bemaßungen - Fläche: 0.038 m2; Height: 0.425 m; Höhe: 0.425 m; Volumen: 0.0012 m3; WS_HEIGHT: 0.425 m; Grafiken - WS_2D_SYM_VISIBLE: yes; WS_DETAIL_SYMBOL: WS_DET_2D_REC_OPG : Sym_02; WS_SYMBOL_OFFSET: 0.04 m; ID-Daten(Type) - Typenkommentare: WS_Aussparung
Geschossdecke:WS_SLB_CON_150:3712874 | FB_E00_OKFB | WS_VOI_SLB_REC | 2 | WS_VOI_SLB_REC | WS_VOI_SLB_REC: WS_VOI_SLB_REC | 3712874 | Allgemeines Modell | WS_VOI_SLB_REC | 3396807 | Dü_OG1_OKRD_+8,065 |  | 0.4 | no | yes | no | Phase 1 | DD | Allgemeines Modell | WS_VOI_SLB_REC | 0 | WS_VOI_SLB_REC | Werner Sobek | Abhängigkeiten - Verschieben mit umliegenden Elementen: no; Bemaßungen - WS_LENGTH: 0.4 m; Grafiken - WS_Aussparung_Symboltyp: WS_DET_2D_REC_OPG_SLB : WS_SYM_REC_OPG_SLB_02
2 x Geschossdecke:WS_SLB_TIM_60:3737488 | FB_E00_OKFB | WS_VOI_CIR | 2 | WS_VOI_CIR | WS_VOI_CIR: WS_VOI_CIR |  | Allgemeines Modell | WS_VOI_CIR | 3402115 | Dü_OG1_OKHT_+8,005_Träger OG | 0.06 |  |  |  |  | Phase 1 | KB Ø15 | Allgemeines Modell | WS_VOI_CIR | 1.2 | WS_VOI_CIR | Werner Sobek | Abhängigkeiten - Höhe von Ebene: 0 m; Basisbauteil: Ebene : Dü_OG1_OKHT_+8,005_Träger OG; Bauteillistenebene: Dü_OG1_OKHT_+8,005_Träger OG; WS_DIAMETER: 0.15 m
3 x Geschossdecke:WS_SLB_TIM_60:3737488 | FB_E00_OKFB | WS_VOI_CIR | 2 | WS_VOI_CIR | WS_VOI_CIR: WS_VOI_CIR |  | Allgemeines Modell | WS_VOI_CIR | 3402115 | Dü_OG1_OKHT_+8,005_Träger OG | 0.06 |  |  |  |  | Phase 1 | DD Ø16 | Allgemeines Modell | WS_VOI_CIR | 1.2 | WS_VOI_CIR | Werner Sobek | Abhängigkeiten - Höhe von Ebene: 0 m; Basisbauteil: Ebene : Dü_OG1_OKHT_+8,005_Träger OG; Bauteillistenebene: Dü_OG1_OKHT_+8,005_Träger OG; WS_DIAMETER: 0.16 m
3 x Geschossdecke:WS_SLB_TIM_100:3738560 | FB_E00_OKFB | WS_VOI_CIR | 2 | WS_VOI_CIR | WS_VOI_CIR: WS_VOI_CIR |  | Allgemeines Modell | WS_VOI_CIR | 3402115 | BP_UG1_OKBP_-3,87 | -0.1 |  |  |  |  | Phase 1 |  | Allgemeines Modell | WS_VOI_CIR | 1.2 | WS_VOI_CIR | Werner Sobek | Abhängigkeiten - Höhe von Ebene: 7.905 m; Basisbauteil: <nicht verknüpft>; Bauteillistenebene: BP_UG1_OKBP_-3,87; WS_DIAMETER: 0.16 m
Geschossdecke:WS_SLB_TIM_90:3741551 | FB_E00_OKFB | WS_VOI_SLB_REC | 2 | WS_VOI_SLB_REC | WS_VOI_SLB_REC: WS_VOI_SLB_REC | 3741551 | Allgemeines Modell | WS_VOI_SLB_REC | 3396807 | Dü_EG_OKHD_+3,985_Foyer 2 |  | 0.21 | no | yes | no | Phase 1 | DD | Allgemeines Modell | WS_VOI_SLB_REC | 0 | WS_VOI_SLB_REC | Werner Sobek | Abhängigkeiten - Verschieben mit umliegenden Elementen: no; Bemaßungen - WS_LENGTH: 0.21 m; Grafiken - WS_Aussparung_Symboltyp: WS_DET_2D_REC_OPG_SLB : WS_SYM_REC_OPG_SLB_02
Geschossdecke:WS_SLB_TIM_90:3741551 | FB_E00_OKFB | WS_VOI_SLB_REC | 2 | WS_VOI_SLB_REC | WS_VOI_SLB_REC: WS_VOI_SLB_REC | 3741551 | Allgemeines Modell | WS_VOI_SLB_REC | 3396807 | Dü_EG_OKHD_+3,985_Foyer 2 |  | 0.26 | no | yes | no | Phase 1 | DD | Allgemeines Modell | WS_VOI_SLB_REC | 0 | WS_VOI_SLB_REC | Werner Sobek | Abhängigkeiten - Verschieben mit umliegenden Elementen: no; Bemaßungen - WS_LENGTH: 0.26 m; Grafiken - WS_Aussparung_Symboltyp: WS_DET_2D_REC_OPG_SLB : WS_SYM_REC_OPG_SLB_02
2 x Geschossdecke:WS_SLB_TIM_90:3741551 | FB_E00_OKFB | WS_VOI_CIR | 2 | WS_VOI_CIR | WS_VOI_CIR: WS_VOI_CIR |  | Allgemeines Modell | WS_VOI_CIR | 3402115 | Dü_EG_OKRD_+4,035 | -0.15 |  |  |  |  | Phase 1 |  | Allgemeines Modell | WS_VOI_CIR | 1.2 | WS_VOI_CIR | Werner Sobek | Abhängigkeiten - Höhe von Ebene: 0 m; Basisbauteil: Ebene : Dü_EG_OKRD_+4,035; Bauteillistenebene: Dü_EG_OKRD_+4,035; WS_DIAMETER: 0.25 m
Geschossdecke:WS_SLB_TIM_90:3741551 | FB_E00_OKFB | WS_VOI_CIR | 2 | WS_VOI_CIR | WS_VOI_CIR: WS_VOI_CIR |  | Allgemeines Modell | WS_VOI_CIR | 3402115 | Dü_EG_OKRD_+4,035 | -0.15 |  |  |  |  | Phase 1 |  | Allgemeines Modell | WS_VOI_CIR | 1.2 | WS_VOI_CIR | Werner Sobek | Abhängigkeiten - Höhe von Ebene: 0 m; Basisbauteil: Ebene : Dü_EG_OKRD_+4,035; Bauteillistenebene: Dü_EG_OKRD_+4,035; WS_DIAMETER: 0.18 m
Basiswand:WS_WAL_MAS_240:3799305 | FB_U01_OKFB | WS_VOI_WAL_REC | 2 | WS_VOI_WAL_REC | WS_VOI_WAL_REC: WS_VOI_WAL_REC | 3799305 | Allgemeines Modell | WS_VOI_WAL_REC | 3394965 | Dü_U01_OKRD_-0,12 | 0.24 | 0.3 | no | no | yes | Phase 1 | KBZ | Allgemeines Modell | WS_VOI_WAL_REC | 0 | WS_VOI_WAL_REC | Modelleigenschaften - WS_DUMMY_EXTENSION_BOT: -2 m; WS_DUMMY_EXTENSION_TOP: 0.01 m; Abhängigkeiten - Höhe von Ebene: 3.275 m; Bemaßungen - Fläche: 0.3276 m2; Height: 0.3 m; Höhe: 0.3 m; Volumen: 0.01206 m3; WS_HEIGHT: 0.3 m; Grafiken - WS_2D_SYM_VISIBLE: yes; WS_DETAIL_SYMBOL: WS_DET_2D_REC_OPG : Sym_02; WS_SYMBOL_OFFSET: 0.04 m; Text - WS_COMMENT_1: OK=UKRD -48cm; ID-Daten(Type) - Typenkommentare: WS_Aussparung
Basiswand:WS_WAL_MAS_240:3799667 | FB_U01_OKFB | WS_VOI_WAL_REC | 2 | WS_VOI_WAL_REC | WS_VOI_WAL_REC: WS_VOI_WAL_REC | 3798993 | Allgemeines Modell | WS_VOI_WAL_REC | 3394965 | Dü_U01_OKRD_-0,12 | 0.24 | 0.315003 | no | no | yes | Phase 1 |  | Allgemeines Modell | WS_VOI_WAL_REC | 0 | WS_VOI_WAL_REC | Modelleigenschaften - WS_DUMMY_EXTENSION_BOT: -1.5 m; WS_DUMMY_EXTENSION_TOP: 0.1 m; Abhängigkeiten - Höhe von Ebene: 3.55 m; Bemaßungen - Fläche: 0.262 m2; Height: 0.49 m; Höhe: 0.49 m; Volumen: 0.0096 m3; WS_HEIGHT: 0.49 m; Grafiken - WS_2D_SYM_VISIBLE: yes; WS_DETAIL_SYMBOL: WS_DET_2D_REC_OPG : Sym_02; WS_SYMBOL_OFFSET: 0.04 m; ID-Daten(Type) - Typenkommentare: WS_Aussparung
Basiswand:WS_WAL_MAS_240:3204820 | FB_U01_OKFB | WS_WAL_MAS_240 | 2 |  |  |  | Linien: <Skizze> | Bemaßungen - Länge: 0.184995 m
Geschossdecke:WS_SLB_CON_650_WT:3815205 | FB_U01_OKFB | WS_VOI_SLB_REC | 2 | WS_VOI_SLB_REC | WS_VOI_SLB_REC: WS_VOI_SLB_REC | 3671416 | Allgemeines Modell | WS_VOI_SLB_REC | 3396807 | Dü_U01_OKRD_-0,12 |  | 3.59 | no | yes | no | Phase 1 | DD | Allgemeines Modell | WS_VOI_SLB_REC | 0 | WS_VOI_SLB_REC | Werner Sobek | Abhängigkeiten - Verschieben mit umliegenden Elementen: no; Bemaßungen - WS_LENGTH: 1.75 m; Grafiken - WS_Aussparung_Symboltyp: WS_DET_2D_REC_OPG_SLB : WS_SYM_REC_OPG_SLB_02
4 x Geschossdecke:WS_SLB_CON_250:3815343 | FB_U01_OKFB | WS_VOI_SLB_REC | 2 | WS_VOI_SLB_REC | WS_VOI_SLB_REC: WS_VOI_SLB_REC | 3815343 | Allgemeines Modell | WS_VOI_SLB_REC | 3396807 | Dü_U01_OKRD_-0,12 |  | 2 | no | yes | no | Phase 1 | DD | Allgemeines Modell | WS_VOI_SLB_REC | 0 | WS_VOI_SLB_REC | Werner Sobek | Abhängigkeiten - Verschieben mit umliegenden Elementen: no; Bemaßungen - WS_LENGTH: 1.8 m; Grafiken - WS_Aussparung_Symboltyp: WS_DET_2D_REC_OPG_SLB : WS_SYM_REC_OPG_SLB_02
7 x Geschossdecke:WS_SLB_CON_250:3815343 | FB_U01_OKFB | WS_VOI_SLB_TOP_REC | 2 | WS_VOI_SLB_TOP_REC | WS_VOI_SLB_TOP_REC: WS_VOI_SLB_TOP_REC | 3815343 | Allgemeines Modell | WS_VOI_SLB_TOP_REC | 3398654 | Dü_U01_OKRD_-0,12 | 0.04 | 1.1 | no | yes | no | Phase 1 | DA | Allgemeines Modell | WS_VOI_SLB_TOP_REC | 0 | WS_VOI_SLB_TOP_REC | Werner Sobek | Text - WS_COMMENT_1: oberseitig; Abhängigkeiten - Verschieben mit umliegenden Elementen: no; Bemaßungen - WS_LENGTH: 0.3 m; Grafiken - WS_Aussparung_Symboltyp: WS_DET_2D_REC_OPG_SLB : WS_SYM_REC_OPG_SLB_01
Geschossdecke:WS_SLB_CON_250:3815343 | FB_U01_OKFB | WS_VOI_SLB_TOP_REC | 2 | WS_VOI_SLB_TOP_REC | WS_VOI_SLB_TOP_REC: WS_VOI_SLB_TOP_REC | 3671416 | Allgemeines Modell | WS_VOI_SLB_TOP_REC | 3398654 | Dü_U01_OKRD_-0,12 | 0.04 | 1.1 | no | yes | no | Phase 1 | DA | Allgemeines Modell | WS_VOI_SLB_TOP_REC | 0 | WS_VOI_SLB_TOP_REC | Werner Sobek | Text - WS_COMMENT_1: oberseitig; Abhängigkeiten - Verschieben mit umliegenden Elementen: no; Bemaßungen - WS_LENGTH: 0.3 m; Grafiken - WS_Aussparung_Symboltyp: WS_DET_2D_REC_OPG_SLB : WS_SYM_REC_OPG_SLB_01
7 x Geschossdecke:WS_SLB_CON_250:3815343 | FB_U01_OKFB | WS_VOI_SLB_REC | 2 | WS_VOI_SLB_REC | WS_VOI_SLB_REC: WS_VOI_SLB_REC | 3815343 | Allgemeines Modell | WS_VOI_SLB_REC | 3396807 | Dü_U01_OKRD_-0,12 |  | 1.02 | no | yes | no | Phase 1 | DD | Allgemeines Modell | WS_VOI_SLB_REC | 0 | WS_VOI_SLB_REC | Werner Sobek | Abhängigkeiten - Verschieben mit umliegenden Elementen: no; Bemaßungen - WS_LENGTH: 0.22 m; Grafiken - WS_Aussparung_Symboltyp: WS_DET_2D_REC_OPG_SLB : WS_SYM_REC_OPG_SLB_02
2 x Geschossdecke:WS_SLB_CON_250:3815343 | FB_U01_OKFB | WS_VOI_SLB_REC | 2 | WS_VOI_SLB_REC | WS_VOI_SLB_REC: WS_VOI_SLB_REC | 3815343 | Allgemeines Modell | WS_VOI_SLB_REC | 3396807 | Dü_U01_OKRD_-0,12 |  | 0.32 | no | yes | no | Phase 1 | DD | Allgemeines Modell | WS_VOI_SLB_REC | 0 | WS_VOI_SLB_REC | Werner Sobek | Abhängigkeiten - Verschieben mit umliegenden Elementen: no; Bemaßungen - WS_LENGTH: 0.32 m; Grafiken - WS_Aussparung_Symboltyp: WS_DET_2D_REC_OPG_SLB : WS_SYM_REC_OPG_SLB_02
Geschossdecke:WS_SLB_CON_250:3815343 | FB_U01_OKFB | WS_VOI_SLB_REC | 2 | WS_VOI_SLB_REC | WS_VOI_SLB_REC: WS_VOI_SLB_REC | 3671416 | Allgemeines Modell | WS_VOI_SLB_REC | 3396807 | Dü_U01_OKRD_-0,12 |  | 0.22 | no | yes | no | Phase 1 | DD | Allgemeines Modell | WS_VOI_SLB_REC | 0 | WS_VOI_SLB_REC | Werner Sobek | Abhängigkeiten - Verschieben mit umliegenden Elementen: no; Bemaßungen - WS_LENGTH: 1.02 m; Grafiken - WS_Aussparung_Symboltyp: WS_DET_2D_REC_OPG_SLB : WS_SYM_REC_OPG_SLB_02
Geschossdecke:WS_SLB_CON_650_WT:4042943 | FB_U01_OKFB | WS_SLB_CON_650_WT | 2 |  |  |  | Linien: <Skizze> | Sonstige - Betonauskragung: 0 m; Stahlauskragung: 0 m; Analytische Achse - Ausrichtungsmethode: Automatische Erkennung; Manuell angepasst: no; Projektion innerhalb Ebene: Geschossdecken-/Plattenkante; Abhängigkeiten - Bestimmt Neigung: no; Definiert die konstante Höhe: no; Versatz von Basis: 0 m; Bemaßungen - Länge: 1.9 m; Neigung: 0.0833333
Basiswand:WS_WAL_CON_250:3843718 | FB_E00_OKFB | WS_VOI_WAL_REC | 2 | WS_VOI_WAL_REC | WS_VOI_WAL_REC: WS_VOI_WAL_REC | 3843718 | Allgemeines Modell | WS_VOI_WAL_REC | 3394965 | Dü_EG_OKRD | 0.25 | 2.095 | no | no | yes | Phase 1 | WD | Allgemeines Modell | WS_VOI_WAL_REC | 0 | WS_VOI_WAL_REC | Modelleigenschaften - WS_DUMMY_EXTENSION_BOT: -2 m; WS_DUMMY_EXTENSION_TOP: 0.1 m; Abhängigkeiten - Höhe von Ebene: 3.03 m; Bemaßungen - Fläche: 0.342 m2; Height: 0.4 m; Höhe: 0.4 m; Volumen: 0.0126 m3; WS_HEIGHT: 0.4 m; Grafiken - WS_2D_SYM_VISIBLE: yes; WS_DETAIL_SYMBOL: WS_DET_2D_REC_OPG : Sym_02; WS_SYMBOL_OFFSET: 0.04 m; Text - WS_COMMENT_1: OK=UKRD -13,5cm = +7,78; ID-Daten(Type) - Typenkommentare: WS_Aussparung
Basiswand:WS_WAL_CON_250:329296 | FB_U01_OKFB | WS_WAL_CON_250 | 2 |  |  |  | Linien: <Skizze> | Bemaßungen - Länge: 0.505 m
Basiswand:WS_WAL_CON_250:3846240 | FB_U01_OKFB | WS_VOI_WAL_REC | 2 | WS_VOI_WAL_REC | WS_VOI_WAL_REC: WS_VOI_WAL_REC | 3846240 | Allgemeines Modell | WS_VOI_WAL_REC | 3394965 | Dü_U01_OKRD_-0,12 | 0.25 | 0.3 | no | no | yes | Phase 1 | WD | Allgemeines Modell | WS_VOI_WAL_REC | 0 | WS_VOI_WAL_REC | Modelleigenschaften - WS_DUMMY_EXTENSION_BOT: -0.1 m; WS_DUMMY_EXTENSION_TOP: 2.5 m; Abhängigkeiten - Höhe von Ebene: 0 m; Bemaßungen - Fläche: 0.422 m2; Height: 0.3 m; Höhe: 0.3 m; Volumen: 0.0156 m3; WS_HEIGHT: 0.3 m; Grafiken - WS_2D_SYM_VISIBLE: yes; WS_DETAIL_SYMBOL: WS_DET_2D_REC_OPG : Sym_02; WS_SYMBOL_OFFSET: 0.04 m; Text - WS_COMMENT_1: UK=OKBP=-0,12; ID-Daten(Type) - Typenkommentare: WS_Aussparung
Basiswand:WS_WAL_CON_250:3846240 | FB_U01_OKFB | WS_VOI_WAL_REC | 2 | WS_VOI_WAL_REC | WS_VOI_WAL_REC: WS_VOI_WAL_REC | 3846240 | Allgemeines Modell | WS_VOI_WAL_REC | 3394965 | Dü_U01_OKRD_-0,12 | 0.25 | 0.4 | no | no | yes | Phase 1 | WD | Allgemeines Modell | WS_VOI_WAL_REC | 0 | WS_VOI_WAL_REC | Modelleigenschaften - WS_DUMMY_EXTENSION_BOT: -2 m; WS_DUMMY_EXTENSION_TOP: 0.1 m; Abhängigkeiten - Höhe von Ebene: 2.95 m; Bemaßungen - Fläche: 0.342 m2; Height: 0.6 m; Höhe: 0.6 m; Volumen: 0.0126 m3; WS_HEIGHT: 0.6 m; Grafiken - WS_2D_SYM_VISIBLE: yes; WS_DETAIL_SYMBOL: WS_DET_2D_REC_OPG : Sym_02; WS_SYMBOL_OFFSET: 0.04 m; Text - WS_COMMENT_1: OK=UKRD=+3,43; ID-Daten(Type) - Typenkommentare: WS_Aussparung
2 x Basiswand:WS_WAL_CON_250:3846240 | FB_U01_OKFB | WS_VOI_WAL_REC | 2 | WS_VOI_WAL_REC | WS_VOI_WAL_REC: WS_VOI_WAL_REC | 3846240 | Allgemeines Modell | WS_VOI_WAL_REC | 3394965 | Dü_U01_OKRD_-0,12 | 0.25 | 0.2 | yes | no | yes | Phase 1 | KBZ | Allgemeines Modell | WS_VOI_WAL_REC | 0 | WS_VOI_WAL_REC | Modelleigenschaften - WS_DUMMY_EXTENSION_BOT: -2 m; WS_DUMMY_EXTENSION_TOP: 0.1 m; Abhängigkeiten - Höhe von Ebene: 3.25 m; Bemaßungen - Fläche: 0.342 m2; Height: 0.3 m; Höhe: 0.3 m; Volumen: 0.0126 m3; WS_HEIGHT: 0.3 m; Grafiken - WS_2D_SYM_VISIBLE: yes; WS_DETAIL_SYMBOL: WS_DET_2D_REC_OPG : Sym_02; WS_SYMBOL_OFFSET: 0.04 m; Text - WS_COMMENT_1: OK=UKRD=+3,43; ID-Daten(Type) - Typenkommentare: WS_Aussparung
Basiswand:WS_WAL_CON_250:3846240 | FB_U01_OKFB | WS_VOI_WAL_REC | 2 | WS_VOI_WAL_REC | WS_VOI_WAL_REC: WS_VOI_WAL_REC | 3846240 | Allgemeines Modell | WS_VOI_WAL_REC | 3394965 | Dü_U01_OKRD_-0,12 | 0.25 | 0.7 | no | no | yes | Phase 1 | KBZ | Allgemeines Modell | WS_VOI_WAL_REC | 0 | WS_VOI_WAL_REC | Modelleigenschaften - WS_DUMMY_EXTENSION_BOT: -2 m; WS_DUMMY_EXTENSION_TOP: 0.1 m; Abhängigkeiten - Höhe von Ebene: 2.995 m; Bemaßungen - Fläche: 0.342 m2; Height: 0.55 m; Höhe: 0.55 m; Volumen: 0.0126 m3; WS_HEIGHT: 0.55 m; Grafiken - WS_2D_SYM_VISIBLE: yes; WS_DETAIL_SYMBOL: WS_DET_2D_REC_OPG : Sym_02; WS_SYMBOL_OFFSET: 0.04 m; Text - WS_COMMENT_1: OK=UKRD -31cm= +3,425; ID-Daten(Type) - Typenkommentare: WS_Aussparung
Basiswand:WS_WAL_CON_250_WT:3848552 | FB_U01_OKFB | WS_VOI_WAL_REC | 2 | WS_VOI_WAL_REC | WS_VOI_WAL_REC: WS_VOI_WAL_REC | 3676966 | Allgemeines Modell | WS_VOI_WAL_REC | 3394965 | Dü_U01_OKRD_-0,12 | 0.25 | 0.5 | yes | no | yes | Phase 1 | KBZ | Allgemeines Modell | WS_VOI_WAL_REC | 0 | WS_VOI_WAL_REC | Modelleigenschaften - WS_DUMMY_EXTENSION_BOT: -1 m; WS_DUMMY_EXTENSION_TOP: 0.1 m; Abhängigkeiten - Höhe von Ebene: 3.17 m; Bemaßungen - Fläche: 0.182 m2; Height: 0.8 m; Höhe: 0.8 m; Volumen: 0.0066 m3; WS_HEIGHT: 0.8 m; Grafiken - WS_2D_SYM_VISIBLE: yes; WS_DETAIL_SYMBOL: WS_DET_2D_REC_OPG : Sym_02; WS_SYMBOL_OFFSET: 0.04 m; Text - WS_COMMENT_1: OK=UKRD; ID-Daten(Type) - Typenkommentare: WS_Aussparung
Geschossdecke:WS_SLB_CON_300_WT:4153378 | FB_U01_OKFB | WS_SLB_CON_300_WT | 2 |  |  |  | Linien: <Skizze> | Sonstige - Betonauskragung: 0 m; Stahlauskragung: 0 m; Analytische Achse - Ausrichtungsmethode: Automatische Erkennung; Manuell angepasst: no; Projektion innerhalb Ebene: Geschossdecken-/Plattenkante; Abhängigkeiten - Bestimmt Neigung: no; Definiert die konstante Höhe: no; Versatz von Basis: 0 m; Bemaßungen - Länge: 1.7 m; Neigung: 0.0833333
Geschossdecke:WS_SLB_CON_250:3855979 | FB_U01_OKFB | WS_VOI_SLB_REC | 2 | WS_VOI_SLB_REC | WS_VOI_SLB_REC: WS_VOI_SLB_REC | 4215173 | Allgemeines Modell | WS_VOI_SLB_REC | 3396807 | Dü_U01_OKRD_-0,12 |  | 1.5 | no | yes | no | Phase 1 | DD | Allgemeines Modell | WS_VOI_SLB_REC | 0 | WS_VOI_SLB_REC | Werner Sobek | Abhängigkeiten - Verschieben mit umliegenden Elementen: no; Bemaßungen - WS_LENGTH: 1.8 m; Grafiken - WS_Aussparung_Symboltyp: WS_DET_2D_REC_OPG_SLB : WS_SYM_REC_OPG_SLB_02
Basiswand:WS_WAL_CON_250:3856122 | FB_U01_OKFB | WS_VOI_WAL_REC | 2 | WS_VOI_WAL_REC | WS_VOI_WAL_REC: WS_VOI_WAL_REC | 3856122 | Allgemeines Modell | WS_VOI_WAL_REC | 3394965 | BP_UG1_OKBP_-3,87 | 0.25 | 1.27 | yes | no | yes | Phase 1 | KBZ | Allgemeines Modell | WS_VOI_WAL_REC | 0 | WS_VOI_WAL_REC | Modelleigenschaften - WS_DUMMY_EXTENSION_BOT: -2.5 m; WS_DUMMY_EXTENSION_TOP: 0.1 m; Abhängigkeiten - Höhe von Ebene: 3 m; Bemaßungen - Fläche: 0.422 m2; Height: 0.5 m; Höhe: 0.5 m; Volumen: 0.0156 m3; WS_HEIGHT: 0.5 m; Grafiken - WS_2D_SYM_VISIBLE: yes; WS_DETAIL_SYMBOL: WS_DET_2D_REC_OPG : Sym_02; WS_SYMBOL_OFFSET: 0.04 m; Text - WS_COMMENT_1: OK=UKRD; ID-Daten(Type) - Typenkommentare: WS_Aussparung
Basiswand:WS_WAL_CON_250:3856753 | FB_U01_OKFB | WS_VOI_WAL_REC | 2 | WS_VOI_WAL_REC | WS_VOI_WAL_REC: WS_VOI_WAL_REC | 3856753 | Allgemeines Modell | WS_VOI_WAL_REC | 3394965 | BP_UG1_OKBP_-3,87 | 0.25 | 1.27 | yes | no | yes | Phase 1 | KBZ | Allgemeines Modell | WS_VOI_WAL_REC | 0 | WS_VOI_WAL_REC | Modelleigenschaften - WS_DUMMY_EXTENSION_BOT: -2.5 m; WS_DUMMY_EXTENSION_TOP: 0.1 m; Abhängigkeiten - Höhe von Ebene: 3 m; Bemaßungen - Fläche: 0.422 m2; Height: 0.5 m; Höhe: 0.5 m; Volumen: 0.0156 m3; WS_HEIGHT: 0.5 m; Grafiken - WS_2D_SYM_VISIBLE: yes; WS_DETAIL_SYMBOL: WS_DET_2D_REC_OPG : Sym_02; WS_SYMBOL_OFFSET: 0.04 m; Text - WS_COMMENT_1: OK=UKRD; ID-Daten(Type) - Typenkommentare: WS_Aussparung
2 x Basiswand:WS_WAL_CON_250:3876193 | FB_E00_OKFB | WS_VOI_WAL_REC | 2 | WS_VOI_WAL_REC | WS_VOI_WAL_REC: WS_VOI_WAL_REC | 3678293 | Allgemeines Modell | WS_VOI_WAL_REC | 3394965 | Dü_U01_OKRD_-0,12 | 0.25 | 0.9 | no | no | yes | Phase 1 | WD | Allgemeines Modell | WS_VOI_WAL_REC | 0 | WS_VOI_WAL_REC | Modelleigenschaften - WS_DUMMY_EXTENSION_BOT: -0.1 m; WS_DUMMY_EXTENSION_TOP: 2 m; Abhängigkeiten - Höhe von Ebene: 0 m; Bemaßungen - Fläche: 0.342 m2; Height: 0.88 m; Höhe: 0.88 m; Volumen: 0.0126 m3; WS_HEIGHT: 0.88 m; Grafiken - WS_2D_SYM_VISIBLE: yes; WS_DETAIL_SYMBOL: WS_DET_2D_REC_OPG : Sym_02; WS_SYMBOL_OFFSET: 0.04 m; Text - WS_COMMENT_1: UK=OKBP; ID-Daten(Type) - Typenkommentare: WS_Aussparung
Basiswand:WS_WAL_CON_250:3876193 | FB_E00_OKFB | WS_VOI_WAL_REC | 2 | WS_VOI_WAL_REC | WS_VOI_WAL_REC: WS_VOI_WAL_REC | 3678293 | Allgemeines Modell | WS_VOI_WAL_REC | 3394965 | Dü_U01_OKRD_-0,12 | 0.25 | 0.7 | no | no | yes | Phase 1 | WD | Allgemeines Modell | WS_VOI_WAL_REC | 0 | WS_VOI_WAL_REC | Modelleigenschaften - WS_DUMMY_EXTENSION_BOT: -0.1 m; WS_DUMMY_EXTENSION_TOP: 2 m; Abhängigkeiten - Höhe von Ebene: 0 m; Bemaßungen - Fläche: 0.342 m2; Height: 0.88 m; Höhe: 0.88 m; Volumen: 0.0126 m3; WS_HEIGHT: 0.88 m; Grafiken - WS_2D_SYM_VISIBLE: yes; WS_DETAIL_SYMBOL: WS_DET_2D_REC_OPG : Sym_02; WS_SYMBOL_OFFSET: 0.04 m; Text - WS_COMMENT_1: UK=OKBP; ID-Daten(Type) - Typenkommentare: WS_Aussparung
Basiswand:WS_WAL_CON_250:3876193 | FB_E00_OKFB | WS_VOI_WAL_REC | 2 | WS_VOI_WAL_REC | WS_VOI_WAL_REC: WS_VOI_WAL_REC | 3678293 | Allgemeines Modell | WS_VOI_WAL_REC | 3394965 | Dü_U01_OKRD_-0,12 | 0.25 | 0.9 | no | no | yes | Phase 1 | WD | Allgemeines Modell | WS_VOI_WAL_REC | 0 | WS_VOI_WAL_REC | Modelleigenschaften - WS_DUMMY_EXTENSION_BOT: -0.1 m; WS_DUMMY_EXTENSION_TOP: 2 m; Abhängigkeiten - Höhe von Ebene: 2.20354e-09 m; Bemaßungen - Fläche: 0.342 m2; Height: 0.88 m; Höhe: 0.88 m; Volumen: 0.0126 m3; WS_HEIGHT: 0.88 m; Grafiken - WS_2D_SYM_VISIBLE: yes; WS_DETAIL_SYMBOL: WS_DET_2D_REC_OPG : Sym_02; WS_SYMBOL_OFFSET: 0.04 m; Text - WS_COMMENT_1: UK=OKBP; ID-Daten(Type) - Typenkommentare: WS_Aussparung
Basiswand:WS_WAL_CON_250:3876193 | FB_E00_OKFB | WS_VOI_WAL_REC | 2 | WS_VOI_WAL_REC | WS_VOI_WAL_REC: WS_VOI_WAL_REC | 3678293 | Allgemeines Modell | WS_VOI_WAL_REC | 3394965 | Dü_U01_OKRD_-0,12 | 0.25 | 0.8 | no | no | yes | Phase 1 | WD | Allgemeines Modell | WS_VOI_WAL_REC | 0 | WS_VOI_WAL_REC | Modelleigenschaften - WS_DUMMY_EXTENSION_BOT: -0.1 m; WS_DUMMY_EXTENSION_TOP: 2 m; Abhängigkeiten - Höhe von Ebene: 2.20354e-09 m; Bemaßungen - Fläche: 0.342 m2; Height: 0.88 m; Höhe: 0.88 m; Volumen: 0.0126 m3; WS_HEIGHT: 0.88 m; Grafiken - WS_2D_SYM_VISIBLE: yes; WS_DETAIL_SYMBOL: WS_DET_2D_REC_OPG : Sym_02; WS_SYMBOL_OFFSET: 0.04 m; Text - WS_COMMENT_1: UK=OKBP; ID-Daten(Type) - Typenkommentare: WS_Aussparung
Basiswand:WS_WAL_CON_250:3876193 | FB_E00_OKFB | WS_VOI_WAL_REC | 2 | WS_VOI_WAL_REC | WS_VOI_WAL_REC: WS_VOI_WAL_REC | 3678293 | Allgemeines Modell | WS_VOI_WAL_REC | 3394965 | Dü_U01_OKRD_-0,12 | 0.25 | 0.8 | no | no | yes | Phase 1 | WD | Allgemeines Modell | WS_VOI_WAL_REC | 0 | WS_VOI_WAL_REC | Modelleigenschaften - WS_DUMMY_EXTENSION_BOT: -0.1 m; WS_DUMMY_EXTENSION_TOP: 2 m; Abhängigkeiten - Höhe von Ebene: 2.20355e-09 m; Bemaßungen - Fläche: 0.342 m2; Height: 0.88 m; Höhe: 0.88 m; Volumen: 0.0126 m3; WS_HEIGHT: 0.88 m; Grafiken - WS_2D_SYM_VISIBLE: yes; WS_DETAIL_SYMBOL: WS_DET_2D_REC_OPG : Sym_02; WS_SYMBOL_OFFSET: 0.04 m; Text - WS_COMMENT_1: UK=OKBP; ID-Daten(Type) - Typenkommentare: WS_Aussparung
Basiswand:WS_WAL_CON_250:3876193 | FB_E00_OKFB | WS_VOI_WAL_REC | 2 | WS_VOI_WAL_REC | WS_VOI_WAL_REC: WS_VOI_WAL_REC | 3678293 | Allgemeines Modell | WS_VOI_WAL_REC | 3394965 | Dü_U01_OKRD_-0,12 | 0.25 | 0.3 | yes | no | yes | Phase 1 | KBZ | Allgemeines Modell | WS_VOI_WAL_REC | 0 | WS_VOI_WAL_REC | Modelleigenschaften - WS_DUMMY_EXTENSION_BOT: -1 m; WS_DUMMY_EXTENSION_TOP: 0.1 m; Abhängigkeiten - Höhe von Ebene: 3.105 m; Bemaßungen - Fläche: 0.182 m2; Height: 0.8 m; Höhe: 0.8 m; Volumen: 0.0066 m3; WS_HEIGHT: 0.8 m; Grafiken - WS_2D_SYM_VISIBLE: yes; WS_DETAIL_SYMBOL: WS_DET_2D_REC_OPG : Sym_02; WS_SYMBOL_OFFSET: 0.04 m; Text - WS_COMMENT_1: OK=UKRD; ID-Daten(Type) - Typenkommentare: WS_Aussparung
Basiswand:WS_WAL_CON_250:3876193 | FB_E00_OKFB | WS_VOI_WAL_REC | 2 | WS_VOI_WAL_REC | WS_VOI_WAL_REC: WS_VOI_WAL_REC | 3678293 | Allgemeines Modell | WS_VOI_WAL_REC | 3394965 | Dü_U01_OKRD_-0,12 | 0.25 | 0.699344 | no | no | yes | Phase 1 | WD | Allgemeines Modell | WS_VOI_WAL_REC | 0 | WS_VOI_WAL_REC | Modelleigenschaften - WS_DUMMY_EXTENSION_BOT: -2 m; WS_DUMMY_EXTENSION_TOP: 0.01 m; Abhängigkeiten - Höhe von Ebene: 3.705 m; Bemaßungen - Fläche: 0.3276 m2; Height: 0.2 m; Höhe: 0.2 m; Volumen: 0.01206 m3; WS_HEIGHT: 0.2 m; Grafiken - WS_2D_SYM_VISIBLE: yes; WS_DETAIL_SYMBOL: WS_DET_2D_REC_OPG : Sym_02; WS_SYMBOL_OFFSET: 0.04 m; Text - WS_COMMENT_1: OK=UKRD; ID-Daten(Type) - Typenkommentare: WS_Aussparung
Geschossdecke:WS_SLB_TIM_25:3915004 | FB_E00_OKFB | WS_VOI_SLB_REC | 2 | WS_VOI_SLB_REC | WS_VOI_SLB_REC: WS_VOI_SLB_REC | 3915004 | Allgemeines Modell | WS_VOI_SLB_REC | 3396807 | Dü_OG1_OKHD_+8,065 |  | 1.4 | no | yes | no | Phase 1 | DD | Allgemeines Modell | WS_VOI_SLB_REC | 0 | WS_VOI_SLB_REC | Werner Sobek | Abhängigkeiten - Verschieben mit umliegenden Elementen: no; Bemaßungen - WS_LENGTH: 0.7 m; Grafiken - WS_Aussparung_Symboltyp: WS_DET_2D_REC_OPG_SLB : WS_SYM_REC_OPG_SLB_02
Geschossdecke:WS_SLB_TIM_25:3915004 | FB_E00_OKFB | WS_VOI_SLB_REC | 2 | WS_VOI_SLB_REC | WS_VOI_SLB_REC: WS_VOI_SLB_REC | 3915004 | Allgemeines Modell | WS_VOI_SLB_REC | 3396807 | Dü_OG1_OKHD_+8,065 |  | 0.5 | no | yes | no | Phase 1 | DD | Allgemeines Modell | WS_VOI_SLB_REC | 0 | WS_VOI_SLB_REC | Werner Sobek | Abhängigkeiten - Verschieben mit umliegenden Elementen: no; Bemaßungen - WS_LENGTH: 0.65 m; Grafiken - WS_Aussparung_Symboltyp: WS_DET_2D_REC_OPG_SLB : WS_SYM_REC_OPG_SLB_02
3 x Geschossdecke:WS_SLB_TIM_25:3915004 | FB_E00_OKFB | WS_VOI_CIR | 2 | WS_VOI_CIR | WS_VOI_CIR: WS_VOI_CIR |  | Allgemeines Modell | WS_VOI_CIR | 3402115 | Dü_OG1_OKHT_+8,005_Träger OG | 0.06 |  |  |  |  | Phase 1 | DD Ø16 | Allgemeines Modell | WS_VOI_CIR | 1.2 | WS_VOI_CIR | Werner Sobek | Abhängigkeiten - Höhe von Ebene: 0 m; Basisbauteil: Ebene : Dü_OG1_OKHT_+8,005_Träger OG; Bauteillistenebene: Dü_OG1_OKHT_+8,005_Träger OG; WS_DIAMETER: 0.16 m
3 x Geschossdecke:WS_SLB_TIM_25:3915004 | FB_E00_OKFB | WS_VOI_SLB_REC | 2 | WS_VOI_SLB_REC | WS_VOI_SLB_REC: WS_VOI_SLB_REC | 3915004 | Allgemeines Modell | WS_VOI_SLB_REC | 3396807 | Dü_OG1_OKHD_+8,065 |  | 0.200003 | no | yes | no | Phase 1 | DD | Allgemeines Modell | WS_VOI_SLB_REC | 0 | WS_VOI_SLB_REC | Werner Sobek | Abhängigkeiten - Verschieben mit umliegenden Elementen: no; Bemaßungen - WS_LENGTH: 0.2 m; Grafiken - WS_Aussparung_Symboltyp: WS_DET_2D_REC_OPG_SLB : WS_SYM_REC_OPG_SLB_02
Geschossdecke:WS_SLB_TIM_25:3915004 | FB_E00_OKFB | WS_VOI_CIR | 2 | WS_VOI_CIR | WS_VOI_CIR: WS_VOI_CIR |  | Allgemeines Modell | WS_VOI_CIR | 3402115 | Dü_OG1_OKHT_+8,005_Träger OG | 0.06 |  |  |  |  | Phase 1 | DD Ø20 | Allgemeines Modell | WS_VOI_CIR | 1.2 | WS_VOI_CIR | Werner Sobek | Abhängigkeiten - Höhe von Ebene: 0 m; Basisbauteil: Ebene : Dü_OG1_OKHT_+8,005_Träger OG; Bauteillistenebene: Dü_OG1_OKHT_+8,005_Träger OG; WS_DIAMETER: 0.2 m
Basiswand:WS_WAL_TIM_305:4166193 | FB_E00_OKFB | 1,270x2,660 | 2 | 210294_Rohbauöffnung | 210294_Rohbauöffnung: 1,270x2,660 | 3808074 | Türen | 1,270x2,660 | 4146629 | Dü_EG_OKRD_+4,40 |  |  |  |  |  | Phase 1 |  | Türen | 210294_Rohbauöffnung |  | 1,270x2,660 | Sonstige - Sturzhöhe: 2.66 m; Abhängigkeiten - Schwelle/Brüstung: 0 m; ID-Daten - Kennzeichen: 612; Sichtbarkeit - WS_Sturz_verdecken_JN: yes; Konstruktion(Type) - Funktion: Innen; Wandabschluss: Nach Basisbauteil; Bemaßungen(Type) - Breite: 1.27 m; Höhe: 2.66 m; Rohbaubreite: 1.27 m; Rohbauhöhe: 2.66 m; ID-Daten(Type) - OmniClass-Nummer: 23.30.10.00; OmniClass-Titel: Doors; Typenmarkierung: 158; Analytische Eigenschaften(Type) - Analytische Konstruktion: <Keine Auswahl>; Thermische Eigenschaften definieren durch: Schemaplantypen
Basiswand:WS_WAL_CON_250:4174867 | FB_U01_OKFB | WS_VOI_WAL_REC | 2 | WS_VOI_WAL_REC | WS_VOI_WAL_REC: WS_VOI_WAL_REC | 4174867 | Allgemeines Modell | WS_VOI_WAL_REC | 3394965 | Dü_U01_OKRD_-0,12 | 0.25 | 0.7 | yes | no | yes | Phase 1 | KBZ | Allgemeines Modell | WS_VOI_WAL_REC | 0 | WS_VOI_WAL_REC | Modelleigenschaften - WS_DUMMY_EXTENSION_BOT: -1 m; WS_DUMMY_EXTENSION_TOP: 0.1 m; Abhängigkeiten - Höhe von Ebene: 3 m; Bemaßungen - Fläche: 0.182 m2; Height: 0.7 m; Höhe: 0.7 m; Volumen: 0.0066 m3; WS_HEIGHT: 0.7 m; Grafiken - WS_2D_SYM_VISIBLE: yes; WS_DETAIL_SYMBOL: WS_DET_2D_REC_OPG : Sym_02; WS_SYMBOL_OFFSET: 0.04 m; Text - WS_COMMENT_1: OK=+3,58; ID-Daten(Type) - Typenkommentare: WS_Aussparung
Basiswand:WS_WAL_CON_250:4174867 | FB_U01_OKFB | WS_VOI_WAL_REC | 2 | WS_VOI_WAL_REC | WS_VOI_WAL_REC: WS_VOI_WAL_REC | 4174867 | Allgemeines Modell | WS_VOI_WAL_REC | 3394965 | Dü_U01_OKRD_-0,12 | 0.25 | 0.4 | no | no | yes | Phase 1 | WD | Allgemeines Modell | WS_VOI_WAL_REC | 0 | WS_VOI_WAL_REC | Modelleigenschaften - WS_DUMMY_EXTENSION_BOT: -1 m; WS_DUMMY_EXTENSION_TOP: 0.1 m; Abhängigkeiten - Höhe von Ebene: 3.815 m; Bemaßungen - Fläche: 0.182 m2; Height: 0.2 m; Höhe: 0.2 m; Volumen: 0.0066 m3; WS_HEIGHT: 0.2 m; Grafiken - WS_2D_SYM_VISIBLE: yes; WS_DETAIL_SYMBOL: WS_DET_2D_REC_OPG : Sym_02; WS_SYMBOL_OFFSET: 0.04 m; Text - WS_COMMENT_1: OK=+3,895; ID-Daten(Type) - Typenkommentare: WS_Aussparung
Basiswand:WS_WAL_CON_250:4174867 | FB_U01_OKFB | WS_VOI_WAL_REC | 2 | WS_VOI_WAL_REC | WS_VOI_WAL_REC: WS_VOI_WAL_REC | 4174867 | Allgemeines Modell | WS_VOI_WAL_REC | 3394965 | Dü_U01_OKRD_-0,12 | 0.25 | 0.4 | no | no | yes | Phase 1 | WD | Allgemeines Modell | WS_VOI_WAL_REC | 0 | WS_VOI_WAL_REC | Modelleigenschaften - WS_DUMMY_EXTENSION_BOT: -0.01 m; WS_DUMMY_EXTENSION_TOP: 3 m; Abhängigkeiten - Höhe von Ebene: 0 m; Bemaßungen - Fläche: 0.4876 m2; Height: 0.04 m; Höhe: 0.04 m; Volumen: 0.01806 m3; WS_HEIGHT: 0.04 m; Grafiken - WS_2D_SYM_VISIBLE: yes; WS_DETAIL_SYMBOL: WS_DET_2D_REC_OPG : Sym_02; WS_SYMBOL_OFFSET: 0.04 m; Text - WS_COMMENT_1: UK=OKBP=-0,12; ID-Daten(Type) - Typenkommentare: WS_Aussparung
Basiswand:WS_WAL_CON_250:4174867 | FB_U01_OKFB | WS_VOI_WAL_REC | 2 | WS_VOI_WAL_REC | WS_VOI_WAL_REC: WS_VOI_WAL_REC | 4174867 | Allgemeines Modell | WS_VOI_WAL_REC | 3394965 | Dü_U01_OKRD_-0,12 | 0.25 | 0.12 | no | no | yes | Phase 1 | WD | Allgemeines Modell | WS_VOI_WAL_REC | 0 | WS_VOI_WAL_REC | Modelleigenschaften - WS_DUMMY_EXTENSION_BOT: -2 m; WS_DUMMY_EXTENSION_TOP: 0.1 m; Abhängigkeiten - Höhe von Ebene: 3.59 m; Bemaßungen - Fläche: 0.342 m2; Height: 0.105 m; Höhe: 0.105 m; Volumen: 0.0126 m3; WS_HEIGHT: 0.105 m; Grafiken - WS_2D_SYM_VISIBLE: yes; WS_DETAIL_SYMBOL: WS_DET_2D_REC_OPG : Sym_02; WS_SYMBOL_OFFSET: 0.04 m; Text - WS_COMMENT_1: UK=UK Sturz=+3,47; ID-Daten(Type) - Typenkommentare: WS_Aussparung
Basiswand:WS_WAL_CON_250:4174867 | FB_U01_OKFB | WS_VOI_WAL_REC | 2 | WS_VOI_WAL_REC | WS_VOI_WAL_REC: WS_VOI_WAL_REC | 4174867 | Allgemeines Modell | WS_VOI_WAL_REC | 3394965 | Dü_U01_OKRD_-0,12 | 0.25 | 1.3 | no | no | yes | Phase 1 | WD | Allgemeines Modell | WS_VOI_WAL_REC | 0 | WS_VOI_WAL_REC | Modelleigenschaften - WS_DUMMY_EXTENSION_BOT: -1 m; WS_DUMMY_EXTENSION_TOP: 0.1 m; Abhängigkeiten - Höhe von Ebene: 3.055 m; Bemaßungen - Fläche: 0.182 m2; Height: 0.5 m; Höhe: 0.5 m; Volumen: 0.0066 m3; WS_HEIGHT: 0.5 m; Grafiken - WS_2D_SYM_VISIBLE: yes; WS_DETAIL_SYMBOL: WS_DET_2D_REC_OPG : Sym_02; WS_SYMBOL_OFFSET: 0.04 m; Text - WS_COMMENT_1: OK=UKRD -30cm; ID-Daten(Type) - Typenkommentare: WS_Aussparung
Basiswand:WS_WAL_CON_250:4174867 | FB_U01_OKFB | WS_VOI_WAL_REC | 2 | WS_VOI_WAL_REC | WS_VOI_WAL_REC: WS_VOI_WAL_REC | 4174075 | Allgemeines Modell | WS_VOI_WAL_REC | 3394965 | Dü_EG_OKRD_+4,035 | 0.25 | 0.7 | yes | no | yes | Phase 1 | KBZ | Allgemeines Modell | WS_VOI_WAL_REC | 0 | WS_VOI_WAL_REC | Modelleigenschaften - WS_DUMMY_EXTENSION_BOT: -1 m; WS_DUMMY_EXTENSION_TOP: 0.1 m; Abhängigkeiten - Höhe von Ebene: -1.155 m; Bemaßungen - Fläche: 0.182 m2; Height: 0.7 m; Höhe: 0.7 m; Volumen: 0.0066 m3; WS_HEIGHT: 0.7 m; Grafiken - WS_2D_SYM_VISIBLE: yes; WS_DETAIL_SYMBOL: WS_DET_2D_REC_OPG : Sym_02; WS_SYMBOL_OFFSET: 0.04 m; Text - WS_COMMENT_1: OK=+3,58; ID-Daten(Type) - Typenkommentare: WS_Aussparung
Basiswand:WS_WAL_CON_250:4175413 | FB_U01_OKFB | WS_VOI_WAL_REC | 2 | WS_VOI_WAL_REC | WS_VOI_WAL_REC: WS_VOI_WAL_REC | 4175413 | Allgemeines Modell | WS_VOI_WAL_REC | 3394965 | Dü_U01_OKRD_-0,12 | 0.25 | 1.01 | yes | no | yes | Phase 1 | KBZ | Allgemeines Modell | WS_VOI_WAL_REC | 0 | WS_VOI_WAL_REC | Modelleigenschaften - WS_DUMMY_EXTENSION_BOT: -1 m; WS_DUMMY_EXTENSION_TOP: 0.1 m; Abhängigkeiten - Höhe von Ebene: 2.995 m; Bemaßungen - Fläche: 0.182 m2; Height: 0.7 m; Höhe: 0.7 m; Volumen: 0.0066 m3; WS_HEIGHT: 0.7 m; Grafiken - WS_2D_SYM_VISIBLE: yes; WS_DETAIL_SYMBOL: WS_DET_2D_REC_OPG : Sym_02; WS_SYMBOL_OFFSET: 0.04 m; Text - WS_COMMENT_1: OK=UKRD -16cm; ID-Daten(Type) - Typenkommentare: WS_Aussparung
Basiswand:WS_WAL_CON_250:329296 | FB_U01_OKFB | WS_WAL_CON_250 | 2 |  |  |  | Linien: <Skizze> | Bemaßungen - Länge: 0.0250072 m
2 x Geschossdecke:WS_SLB_CON_250:4213655 | FB_U01_OKFB | WS_VOI_SLB_REC | 2 | WS_VOI_SLB_REC | WS_VOI_SLB_REC: WS_VOI_SLB_REC | 3815343 | Allgemeines Modell | WS_VOI_SLB_REC | 3396807 | Dü_U01_OKRD_-0,12 |  | 0.32 | no | yes | no | Phase 1 | DD | Allgemeines Modell | WS_VOI_SLB_REC | 0 | WS_VOI_SLB_REC | Werner Sobek | Abhängigkeiten - Verschieben mit umliegenden Elementen: no; Bemaßungen - WS_LENGTH: 0.32 m; Grafiken - WS_Aussparung_Symboltyp: WS_DET_2D_REC_OPG_SLB : WS_SYM_REC_OPG_SLB_02
7 x Geschossdecke:WS_SLB_CON_250:4213655 | FB_U01_OKFB | WS_VOI_SLB_REC | 2 | WS_VOI_SLB_REC | WS_VOI_SLB_REC: WS_VOI_SLB_REC | 4213655 | Allgemeines Modell | WS_VOI_SLB_REC | 3396807 | Dü_U01_OKRD_-0,12 |  | 0.4 | no | yes | no | Phase 1 | BD | Allgemeines Modell | WS_VOI_SLB_REC | 0 | WS_VOI_SLB_REC | Werner Sobek | Abhängigkeiten - Verschieben mit umliegenden Elementen: no; Bemaßungen - WS_LENGTH: 0.4 m; Grafiken - WS_Aussparung_Symboltyp: WS_DET_2D_REC_OPG_SLB : WS_SYM_REC_OPG_SLB_02
3 x Geschossdecke:WS_SLB_CON_250:4213655 | FB_U01_OKFB | WS_VOI_SLB_REC | 2 | WS_VOI_SLB_REC | WS_VOI_SLB_REC: WS_VOI_SLB_REC | 4213655 | Allgemeines Modell | WS_VOI_SLB_REC | 3396807 | Dü_U01_OKRD_-0,12 |  | 0.36 | no | yes | no | Phase 1 | BD | Allgemeines Modell | WS_VOI_SLB_REC | 0 | WS_VOI_SLB_REC | Werner Sobek | Abhängigkeiten - Verschieben mit umliegenden Elementen: no; Bemaßungen - WS_LENGTH: 0.23 m; Grafiken - WS_Aussparung_Symboltyp: WS_DET_2D_REC_OPG_SLB : WS_SYM_REC_OPG_SLB_02
7 x Geschossdecke:WS_SLB_CON_250:4213655 | FB_U01_OKFB | WS_VOI_SLB_REC | 2 | WS_VOI_SLB_REC | WS_VOI_SLB_REC: WS_VOI_SLB_REC | 3815343 | Allgemeines Modell | WS_VOI_SLB_REC | 3396807 | Dü_U01_OKRD_-0,12 |  | 1.02 | no | yes | no | Phase 1 | DD | Allgemeines Modell | WS_VOI_SLB_REC | 0 | WS_VOI_SLB_REC | Werner Sobek | Abhängigkeiten - Verschieben mit umliegenden Elementen: no; Bemaßungen - WS_LENGTH: 0.22 m; Grafiken - WS_Aussparung_Symboltyp: WS_DET_2D_REC_OPG_SLB : WS_SYM_REC_OPG_SLB_02
7 x Geschossdecke:WS_SLB_CON_250:4213655 | FB_U01_OKFB | WS_VOI_SLB_TOP_REC | 2 | WS_VOI_SLB_TOP_REC | WS_VOI_SLB_TOP_REC: WS_VOI_SLB_TOP_REC | 3815343 | Allgemeines Modell | WS_VOI_SLB_TOP_REC | 3398654 | Dü_U01_OKRD_-0,12 | 0.04 | 1.1 | no | yes | no | Phase 1 | DA | Allgemeines Modell | WS_VOI_SLB_TOP_REC | 0 | WS_VOI_SLB_TOP_REC | Werner Sobek | Text - WS_COMMENT_1: oberseitig; Abhängigkeiten - Verschieben mit umliegenden Elementen: no; Bemaßungen - WS_LENGTH: 0.3 m; Grafiken - WS_Aussparung_Symboltyp: WS_DET_2D_REC_OPG_SLB : WS_SYM_REC_OPG_SLB_01
Geschossdecke:WS_SLB_CON_250:4215173 | FB_U01_OKFB | WS_VOI_SLB_REC | 2 | WS_VOI_SLB_REC | WS_VOI_SLB_REC: WS_VOI_SLB_REC | 4215173 | Allgemeines Modell | WS_VOI_SLB_REC | 3396807 | Dü_U01_OKRD_-0,12 |  | 1.00497 | no | yes | no | Phase 1 | DD | Allgemeines Modell | WS_VOI_SLB_REC | 0 | WS_VOI_SLB_REC | Werner Sobek | Abhängigkeiten - Verschieben mit umliegenden Elementen: no; Bemaßungen - WS_LENGTH: 2.17 m; Grafiken - WS_Aussparung_Symboltyp: WS_DET_2D_REC_OPG_SLB : WS_SYM_REC_OPG_SLB_02
Geschossdecke:WS_SLB_CON_250:4215173 | FB_U01_OKFB | WS_VOI_SLB_REC | 2 | WS_VOI_SLB_REC | WS_VOI_SLB_REC: WS_VOI_SLB_REC | 4215173 | Allgemeines Modell | WS_VOI_SLB_REC | 3396807 | Dü_U01_OKRD_-0,12 |  | 1.5 | no | yes | no | Phase 1 | DD | Allgemeines Modell | WS_VOI_SLB_REC | 0 | WS_VOI_SLB_REC | Werner Sobek | Abhängigkeiten - Verschieben mit umliegenden Elementen: no; Bemaßungen - WS_LENGTH: 1.8 m; Grafiken - WS_Aussparung_Symboltyp: WS_DET_2D_REC_OPG_SLB : WS_SYM_REC_OPG_SLB_02
Geschossdecke:WS_SLB_CON_250:4215173 | FB_U01_OKFB | WS_VOI_SLB_REC | 2 | WS_VOI_SLB_REC | WS_VOI_SLB_REC: WS_VOI_SLB_REC | 4215173 | Allgemeines Modell | WS_VOI_SLB_REC | 3396807 | Dü_U01_OKRD_-0,12 |  | 0.2 | no | yes | no | Phase 1 | DD | Allgemeines Modell | WS_VOI_SLB_REC | 0 | WS_VOI_SLB_REC | Werner Sobek | Abhängigkeiten - Verschieben mit umliegenden Elementen: no; Bemaßungen - WS_LENGTH: 0.7 m; Grafiken - WS_Aussparung_Symboltyp: WS_DET_2D_REC_OPG_SLB : WS_SYM_REC_OPG_SLB_02
Geschossdecke:WS_SLB_CON_250_WT:4215301 | FB_U01_OKFB | WS_VOI_SLB_REC | 2 | WS_VOI_SLB_REC | WS_VOI_SLB_REC: WS_VOI_SLB_REC | 4215173 | Allgemeines Modell | WS_VOI_SLB_REC | 3396807 | Dü_U01_OKRD_-0,12 |  | 1.5 | no | yes | no | Phase 1 | DD | Allgemeines Modell | WS_VOI_SLB_REC | 0 | WS_VOI_SLB_REC | Werner Sobek | Abhängigkeiten - Verschieben mit umliegenden Elementen: no; Bemaßungen - WS_LENGTH: 1.8 m; Grafiken - WS_Aussparung_Symboltyp: WS_DET_2D_REC_OPG_SLB : WS_SYM_REC_OPG_SLB_02
Geschossdecke:WS_SLB_CON_250_WT:4215301 | FB_U01_OKFB | WS_VOI_SLB_REC | 2 | WS_VOI_SLB_REC | WS_VOI_SLB_REC: WS_VOI_SLB_REC | 4215173 | Allgemeines Modell | WS_VOI_SLB_REC | 3396807 | Dü_U01_OKRD_-0,12 |  | 1.00497 | no | yes | no | Phase 1 | DD | Allgemeines Modell | WS_VOI_SLB_REC | 0 | WS_VOI_SLB_REC | Werner Sobek | Abhängigkeiten - Verschieben mit umliegenden Elementen: no; Bemaßungen - WS_LENGTH: 2.17 m; Grafiken - WS_Aussparung_Symboltyp: WS_DET_2D_REC_OPG_SLB : WS_SYM_REC_OPG_SLB_02
Geschossdecke:WS_SLB_CON_250_WT:4215301 | FB_U01_OKFB | WS_VOI_SLB_REC | 2 | WS_VOI_SLB_REC | WS_VOI_SLB_REC: WS_VOI_SLB_REC | 4215173 | Allgemeines Modell | WS_VOI_SLB_REC | 3396807 | Dü_U01_OKRD_-0,12 |  | 0.2 | no | yes | no | Phase 1 | DD | Allgemeines Modell | WS_VOI_SLB_REC | 0 | WS_VOI_SLB_REC | Werner Sobek | Abhängigkeiten - Verschieben mit umliegenden Elementen: no; Bemaßungen - WS_LENGTH: 0.7 m; Grafiken - WS_Aussparung_Symboltyp: WS_DET_2D_REC_OPG_SLB : WS_SYM_REC_OPG_SLB_02
4 x Geschossdecke:WS_SLB_CON_250_WT:4216407 | FB_U01_OKFB | WS_VOI_SLB_REC | 2 | WS_VOI_SLB_REC | WS_VOI_SLB_REC: WS_VOI_SLB_REC | 3815343 | Allgemeines Modell | WS_VOI_SLB_REC | 3396807 | Dü_U01_OKRD_-0,12 |  | 2 | no | yes | no | Phase 1 | DD | Allgemeines Modell | WS_VOI_SLB_REC | 0 | WS_VOI_SLB_REC | Werner Sobek | Abhängigkeiten - Verschieben mit umliegenden Elementen: no; Bemaßungen - WS_LENGTH: 1.8 m; Grafiken - WS_Aussparung_Symboltyp: WS_DET_2D_REC_OPG_SLB : WS_SYM_REC_OPG_SLB_02
Geschossdecke:WS_SLB_CON_250_WT:995882 | FB_U01_OKFB | WS_SLB_CON_250_WT | 2 |  |  |  | Linien: <Skizze> | Sonstige - Betonauskragung: 0 m; Stahlauskragung: 0 m; Analytische Achse - Ausrichtungsmethode: Automatische Erkennung; Manuell angepasst: no; Projektion innerhalb Ebene: Geschossdecken-/Plattenkante; Abhängigkeiten - Bestimmt Neigung: no; Definiert die konstante Höhe: no; Versatz von Basis: 0 m; Bemaßungen - Länge: 2.05 m; Neigung: 0.0833333
2 x Basiswand:WS_WAL_CON_250_WT:4218239 | FB_U01_OKFB | WS_VOI_WAL_REC | 2 | WS_VOI_WAL_REC | WS_VOI_WAL_REC: WS_VOI_WAL_REC | 4218239 | Allgemeines Modell | WS_VOI_WAL_REC | 3394965 | BP_UG1_OKBP_-3,87 | 0.25 | 0.5 | yes | no | yes | Phase 1 | KBZ | Allgemeines Modell | WS_VOI_WAL_REC | 0 | WS_VOI_WAL_REC | Modelleigenschaften - WS_DUMMY_EXTENSION_BOT: -1 m; WS_DUMMY_EXTENSION_TOP: 0.1 m; Abhängigkeiten - Höhe von Ebene: 2.5 m; Bemaßungen - Fläche: 0.182 m2; Height: 1 m; Höhe: 1 m; Volumen: 0.0066 m3; WS_HEIGHT: 1 m; Grafiken - WS_2D_SYM_VISIBLE: yes; WS_DETAIL_SYMBOL: WS_DET_2D_REC_OPG : Sym_02; WS_SYMBOL_OFFSET: 0.04 m; Text - WS_COMMENT_1: OK=UKRD=-0,37; ID-Daten(Type) - Typenkommentare: WS_Aussparung
Basiswand:WS_WAL_CON_250_WT:995991 | FB_U01_OKFB | WS_WAL_CON_250_WT | 2 |  |  |  | Linien: <Skizze> | Bemaßungen - Länge: 0.404911 m
2 x Geschossdecke:WS_SLB_CON_250:4333588 | FB_E00_OKFB | WS_VOI_SLB_TOP_REC | 2 | WS_VOI_SLB_TOP_REC | WS_VOI_SLB_TOP_REC: WS_VOI_SLB_TOP_REC | 4333588 | Allgemeines Modell | WS_VOI_SLB_TOP_REC | 3398654 | Dü_EG_OKRD_+4,035 | 0.12 | 0.14 | no | yes | no | Phase 1 | DA | Allgemeines Modell | WS_VOI_SLB_TOP_REC | 0 | WS_VOI_SLB_TOP_REC | Werner Sobek | Text - WS_COMMENT_1: UK = +1,965m; Abhängigkeiten - Verschieben mit umliegenden Elementen: no; Bemaßungen - WS_LENGTH: 1.75 m; Grafiken - WS_Aussparung_Symboltyp: WS_DET_2D_REC_OPG_SLB : WS_SYM_REC_OPG_SLB_01
2 x Basiswand:WS_WAL_CON_240:4526237 | FB_E00_OKFB | WS_VOI_WAL_REC | 2 | WS_VOI_WAL_REC | WS_VOI_WAL_REC: WS_VOI_WAL_REC | 3799918 | Allgemeines Modell | WS_VOI_WAL_REC | 3394965 | Dü_U01_OKRD_-0,12 | 0.24 | 0.32 | no | no | yes | Phase 1 | Auflagertasche | Allgemeines Modell | WS_VOI_WAL_REC | 0 | WS_VOI_WAL_REC | Modelleigenschaften - WS_DUMMY_EXTENSION_BOT: -1.5 m; WS_DUMMY_EXTENSION_TOP: 0.1 m; Abhängigkeiten - Höhe von Ebene: 3.55 m; Bemaßungen - Fläche: 0.262 m2; Height: 0.49 m; Höhe: 0.49 m; Volumen: 0.0096 m3; WS_HEIGHT: 0.49 m; Grafiken - WS_2D_SYM_VISIBLE: yes; WS_DETAIL_SYMBOL: WS_DET_2D_REC_OPG : Sym_02; WS_SYMBOL_OFFSET: 0.04 m; ID-Daten(Type) - Typenkommentare: WS_Aussparung
Basiswand:WS_WAL_CON_240:4526237 | FB_E00_OKFB | WS_VOI_WAL_REC | 2 | WS_VOI_WAL_REC | WS_VOI_WAL_REC: WS_VOI_WAL_REC | 3799918 | Allgemeines Modell | WS_VOI_WAL_REC | 3394965 | Dü_U01_OKRD_-0,12 | 0.24 | 0.0199006 | no | no | yes | Phase 1 | Auflagertasche | Allgemeines Modell | WS_VOI_WAL_REC | 0 | WS_VOI_WAL_REC | Modelleigenschaften - WS_DUMMY_EXTENSION_BOT: -1.5 m; WS_DUMMY_EXTENSION_TOP: 0.1 m; Abhängigkeiten - Höhe von Ebene: 3.55 m; Bemaßungen - Fläche: 0.262 m2; Height: 0.49 m; Höhe: 0.49 m; Volumen: 0.0096 m3; WS_HEIGHT: 0.49 m; Grafiken - WS_2D_SYM_VISIBLE: yes; WS_DETAIL_SYMBOL: WS_DET_2D_REC_OPG : Sym_02; WS_SYMBOL_OFFSET: 0.04 m; ID-Daten(Type) - Typenkommentare: WS_Aussparung
Basiswand:WS_WAL_CON_240:4527321 | FB_E00_OKFB | WS_VOI_WAL_REC | 2 | WS_VOI_WAL_REC | WS_VOI_WAL_REC: WS_VOI_WAL_REC | 3798993 | Allgemeines Modell | WS_VOI_WAL_REC | 3394965 | Dü_U01_OKRD_-0,12 | 0.24 | 0.32 | no | no | yes | Phase 1 |  | Allgemeines Modell | WS_VOI_WAL_REC | 0 | WS_VOI_WAL_REC | Modelleigenschaften - WS_DUMMY_EXTENSION_BOT: -1.5 m; WS_DUMMY_EXTENSION_TOP: 0.1 m; Abhängigkeiten - Höhe von Ebene: 3.55 m; Bemaßungen - Fläche: 0.262 m2; Height: 0.49 m; Höhe: 0.49 m; Volumen: 0.0096 m3; WS_HEIGHT: 0.49 m; Grafiken - WS_2D_SYM_VISIBLE: yes; WS_DETAIL_SYMBOL: WS_DET_2D_REC_OPG : Sym_02; WS_SYMBOL_OFFSET: 0.04 m; ID-Daten(Type) - Typenkommentare: WS_Aussparung
Basiswand:WS_WAL_CON_240:4527321 | FB_E00_OKFB | WS_VOI_WAL_REC | 2 | WS_VOI_WAL_REC | WS_VOI_WAL_REC: WS_VOI_WAL_REC | 3798993 | Allgemeines Modell | WS_VOI_WAL_REC | 3394965 | Dü_U01_OKRD_-0,12 | 0.24 | 0.315003 | no | no | yes | Phase 1 |  | Allgemeines Modell | WS_VOI_WAL_REC | 0 | WS_VOI_WAL_REC | Modelleigenschaften - WS_DUMMY_EXTENSION_BOT: -1.5 m; WS_DUMMY_EXTENSION_TOP: 0.1 m; Abhängigkeiten - Höhe von Ebene: 3.55 m; Bemaßungen - Fläche: 0.262 m2; Height: 0.49 m; Höhe: 0.49 m; Volumen: 0.0096 m3; WS_HEIGHT: 0.49 m; Grafiken - WS_2D_SYM_VISIBLE: yes; WS_DETAIL_SYMBOL: WS_DET_2D_REC_OPG : Sym_02; WS_SYMBOL_OFFSET: 0.04 m; ID-Daten(Type) - Typenkommentare: WS_Aussparung
Basiswand:WS_WAL_CON_240:4527321 | FB_E00_OKFB | WS_VOI_WAL_REC | 2 | WS_VOI_WAL_REC | WS_VOI_WAL_REC: WS_VOI_WAL_REC | 3798993 | Allgemeines Modell | WS_VOI_WAL_REC | 3394965 | Dü_U01_OKRD_-0,12 | 0.24 | 0.21 | no | no | yes | Phase 1 |  | Allgemeines Modell | WS_VOI_WAL_REC | 0 | WS_VOI_WAL_REC | Modelleigenschaften - WS_DUMMY_EXTENSION_BOT: -1.5 m; WS_DUMMY_EXTENSION_TOP: 0.1 m; Abhängigkeiten - Höhe von Ebene: 3.55 m; Bemaßungen - Fläche: 0.262 m2; Height: 0.49 m; Höhe: 0.49 m; Volumen: 0.0096 m3; WS_HEIGHT: 0.49 m; Grafiken - WS_2D_SYM_VISIBLE: yes; WS_DETAIL_SYMBOL: WS_DET_2D_REC_OPG : Sym_02; WS_SYMBOL_OFFSET: 0.04 m; ID-Daten(Type) - Typenkommentare: WS_Aussparung
Basiswand:WS_WAL_CON_240:4527830 | FB_E00_OKFB | WS_VOI_WAL_REC | 2 | WS_VOI_WAL_REC | WS_VOI_WAL_REC: WS_VOI_WAL_REC | 3798993 | Allgemeines Modell | WS_VOI_WAL_REC | 3394965 | Dü_U01_OKRD_-0,12 | 0.24 | 0.315003 | no | no | yes | Phase 1 |  | Allgemeines Modell | WS_VOI_WAL_REC | 0 | WS_VOI_WAL_REC | Modelleigenschaften - WS_DUMMY_EXTENSION_BOT: -1.5 m; WS_DUMMY_EXTENSION_TOP: 0.1 m; Abhängigkeiten - Höhe von Ebene: 3.55 m; Bemaßungen - Fläche: 0.262 m2; Height: 0.49 m; Höhe: 0.49 m; Volumen: 0.0096 m3; WS_HEIGHT: 0.49 m; Grafiken - WS_2D_SYM_VISIBLE: yes; WS_DETAIL_SYMBOL: WS_DET_2D_REC_OPG : Sym_02; WS_SYMBOL_OFFSET: 0.04 m; ID-Daten(Type) - Typenkommentare: WS_Aussparung
Basiswand:WS_WAL_CON_240:4528053 | FB_E00_OKFB | WS_VOI_WAL_REC | 2 | WS_VOI_WAL_REC | WS_VOI_WAL_REC: WS_VOI_WAL_REC | 3799543 | Allgemeines Modell | WS_VOI_WAL_REC | 3394965 | Dü_U01_OKRD_-0,12 | 0.24 | 0.184901 | no | no | yes | Phase 1 |  | Allgemeines Modell | WS_VOI_WAL_REC | 0 | WS_VOI_WAL_REC | Modelleigenschaften - WS_DUMMY_EXTENSION_BOT: -1.5 m; WS_DUMMY_EXTENSION_TOP: 0.1 m; Abhängigkeiten - Höhe von Ebene: 3.55 m; Bemaßungen - Fläche: 0.262 m2; Height: 0.49 m; Höhe: 0.49 m; Volumen: 0.0096 m3; WS_HEIGHT: 0.49 m; Grafiken - WS_2D_SYM_VISIBLE: yes; WS_DETAIL_SYMBOL: WS_DET_2D_REC_OPG : Sym_02; WS_SYMBOL_OFFSET: 0.04 m; ID-Daten(Type) - Typenkommentare: WS_Aussparung
Geschossdecke:WS_SLB_CON_250:4747582 | FB_U01_OKFB | WS_VOI_SLB_TOP_REC | 2 | WS_VOI_SLB_TOP_REC | WS_VOI_SLB_TOP_REC: WS_VOI_SLB_TOP_REC | 4747582 | Allgemeines Modell | WS_VOI_SLB_TOP_REC | 3398654 | Dü_U01_OKRD_-0,12 | 0.12 | 1.3075 | no | yes | no | Phase 1 | DA | Allgemeines Modell | WS_VOI_SLB_TOP_REC | 0 | WS_VOI_SLB_TOP_REC | Werner Sobek | Text - WS_COMMENT_1: UK = -2,015m; Abhängigkeiten - Verschieben mit umliegenden Elementen: no; Bemaßungen - WS_LENGTH: 0.14 m; Grafiken - WS_Aussparung_Symboltyp: WS_DET_2D_REC_OPG_SLB : WS_SYM_REC_OPG_SLB_01
Geschossdecke:WS_SLB_CON_250:4747582 | FB_U01_OKFB | WS_VOI_SLB_TOP_REC | 2 | WS_VOI_SLB_TOP_REC | WS_VOI_SLB_TOP_REC: WS_VOI_SLB_TOP_REC | 4747582 | Allgemeines Modell | WS_VOI_SLB_TOP_REC | 3398654 | Dü_U01_OKRD_-0,12 | 0.12 | 1.32 | no | yes | no | Phase 1 | DA | Allgemeines Modell | WS_VOI_SLB_TOP_REC | 0 | WS_VOI_SLB_TOP_REC | Werner Sobek | Text - WS_COMMENT_1: UK = -2,015m; Abhängigkeiten - Verschieben mit umliegenden Elementen: no; Bemaßungen - WS_LENGTH: 0.14 m; Grafiken - WS_Aussparung_Symboltyp: WS_DET_2D_REC_OPG_SLB : WS_SYM_REC_OPG_SLB_01
Basiswand:WS_WAL_CON_250:3665651 | FB_U01_OKFB
Basiswand:WS_WAL_CON_250:3675762 | FB_U01_OKFB
Basiswand:WS_WAL_CON_250:3677925 | FB_U01_OKFB
Basiswand:WS_WAL_CON_250:3678293 | FB_U01_OKFB
Basiswand:WS_WAL_CON_250:3679313 | FB_U01_OKFB
3 x Basiswand:WS_WAL_CON_250:3680377 | FB_E00_OKFB
Basiswand:WS_WAL_TIM_305:3808074 | FB_E00_OKFB
2 x Basiswand:WS_WAL_CON_250:3846240 | FB_U01_OKFB
Basiswand:WS_WAL_CON_250:3856122 | FB_U01_OKFB
Basiswand:WS_WAL_CON_250:3856753 | FB_U01_OKFB
2 x Basiswand:WS_WAL_CON_250:3876193 | FB_E00_OKFB
2 x Basiswand:WS_WAL_CON_250:4156973 | FB_E00_OKFB
2 x Basiswand:WS_WAL_CON_250:4174867 | FB_U01_OKFB
Basiswand:WS_WAL_CON_250:4175413 | FB_U01_OKFB

# IfcOpeningElement: Recess (7)
Pset_OpeningElementCommon - sets with these values: 2
Sonstige - Kategorie: Allgemeines Modell
Abhängigkeiten - Ebene: Dü_U01_OKRD_-0,12
Grafiken - WS_COVER_BACKGROUND: no
Phasen - Phase erstellt: Phase 1
Sonstige(Type) - Kategorie: Allgemeines Modell
Abhängigkeiten(Type) - Vorgabe-Ansicht: 0 m
Name | In | Reference = Familie = Typ = Familienname = Typname | Familie und Typ | Typ-ID | Host-ID | WS_DUMMY_EXTENSION_BOT (m) | WS_DUMMY_EXTENSION_TOP (m) | Höhe von Ebene (m) | Fläche (m2) | Height (m) = Höhe (m) = WS_HEIGHT (m) | Volumen (m3) | WS_DEPTH (m) | WS_WIDTH (m) | WS_2D_SYM_VISIBLE | WS_LINES_CONTINUOUS | WS_LINES_HIDDEN = WS_SYMBOL | WS_DETAIL_SYMBOL | WS_SYMBOL_OFFSET (m) | WS_COMMENT | Typenkommentare
Basiswand:WS_WAL_CON_250:3679661 | FB_U01_OKFB | WS_VOI_WAL_REC | WS_VOI_WAL_REC: WS_VOI_WAL_REC | 3394965 | 3679661 | -0.01 | 1 | 0.47 | 0.1676 | 1.73 | 0.00606 | 0.085 | 1.18 | yes | no | yes | WS_DET_2D_REC_OPG : Sym_01 | 0.04 | WA | WS_Aussparung | Text - WS_COMMENT_1: UK=OKBP +47cm
Basiswand:WS_WAL_MAS_240:3799806 | FB_U01_OKFB | WS_VOI_WAL_REC | WS_VOI_WAL_REC: WS_VOI_WAL_REC | 3394965 | 3798993 | -1.5 | 0.1 | 3.55 | 0.262 | 0.49 | 0.0096 | 0.24 | 0.21 | yes | no | yes | WS_DET_2D_REC_OPG : Sym_02 | 0.04 |  | WS_Aussparung
Basiswand:WS_WAL_MAS_240:3799806 | FB_U01_OKFB | WS_VOI_WAL_REC | WS_VOI_WAL_REC: WS_VOI_WAL_REC | 3394965 | 3799918 | -1.5 | 0.1 | 3.55 | 0.262 | 0.49 | 0.0096 | 0.24 | 0.21 | yes | no | yes | WS_DET_2D_REC_OPG : Sym_02 | 0.04 | Auflagertasche | WS_Aussparung
Geschossdecke:WS_SLB_CON_650_WT:3818305 | FB_U01_OKFB | WS_VOI_SLB_REC | WS_VOI_SLB_REC: WS_VOI_SLB_REC | 3396807 | 4215173 |  |  |  |  |  |  |  | 1.5 |  | yes | no |  |  | DD | Abhängigkeiten - Verschieben mit umliegenden Elementen: no; Bemaßungen - WS_LENGTH: 1.8 m; Grafiken - WS_Aussparung_Symboltyp: WS_DET_2D_REC_OPG_SLB : WS_SYM_REC_OPG_SLB_02; ID-Daten(Type) - Hersteller: Werner Sobek
Basiswand:WS_WAL_CON_250:3845556 | FB_U01_OKFB | WS_VOI_WAL_REC | WS_VOI_WAL_REC: WS_VOI_WAL_REC | 3394965 | 3845556 | -0.1 | 2.5 | 0 | 0.422 | 4.92744 | 0.0156 | 0.15 | 0.25 | yes | no | yes | WS_DET_2D_REC_OPG : Sym_01 | 0.04 | WS | WS_Aussparung | Text - WS_COMMENT_1: UK=OKBP=-0,12
Basiswand:WS_WAL_CON_250:3845556 | FB_U01_OKFB | WS_VOI_WAL_REC | WS_VOI_WAL_REC: WS_VOI_WAL_REC | 3394965 | 3845556 | -0.1 | 2 | 0 | 0.342 | 0.9 | 0.0126 | 0.12 | 1.1 | yes | no | yes | WS_DET_2D_REC_OPG : Sym_01 | 0.04 | WA | WS_Aussparung | Text - WS_COMMENT_1: UK=OKBP=-0,12
Basiswand:WS_WAL_CON_240:4527502 | FB_E00_OKFB | WS_VOI_WAL_REC | WS_VOI_WAL_REC: WS_VOI_WAL_REC | 3394965 | 3798993 | -1.5 | 0.1 | 3.55 | 0.262 | 0.49 | 0.0096 | 0.24 | 0.21 | yes | no | yes | WS_DET_2D_REC_OPG : Sym_02 | 0.04 |  | WS_Aussparung

# IfcSlab: Bodenplatte:WS_FDN_SLB_1025_Magerbeton, Bodenplatte:WS_FDN_SLB_1025_Magerbeton:3859108
In: FB_U01_OKFB
Type - PredefinedType: BASESLAB; Material: WS_CONCRETE 1.025 m
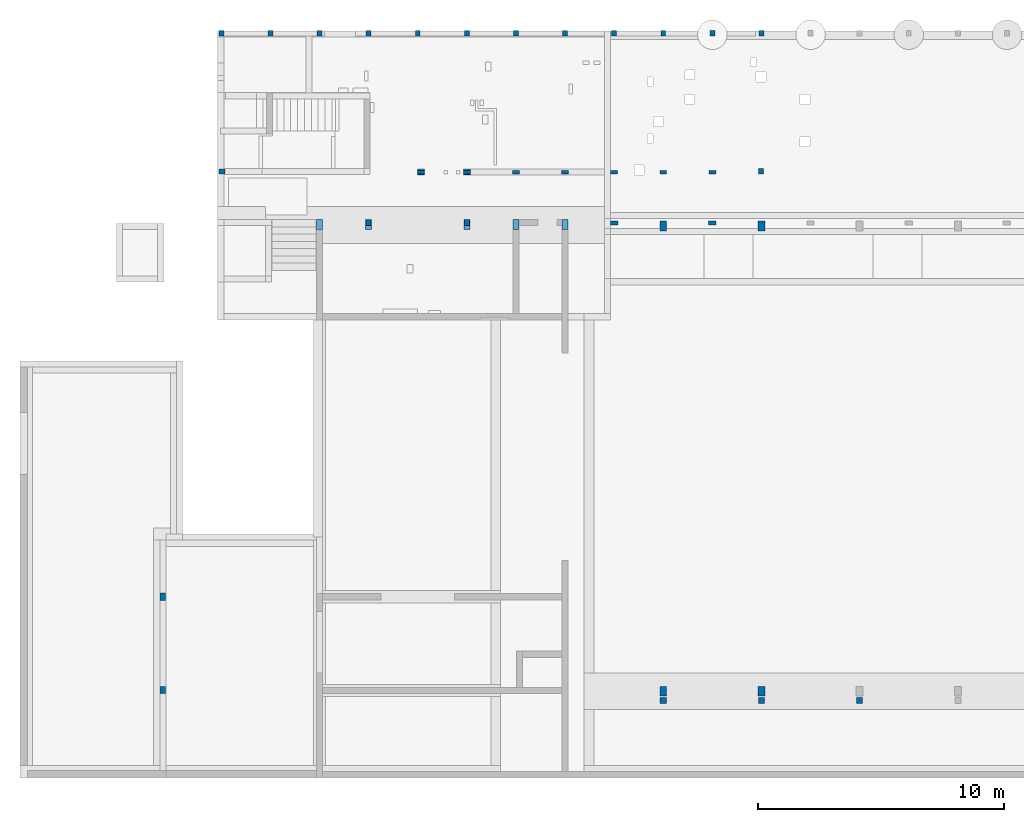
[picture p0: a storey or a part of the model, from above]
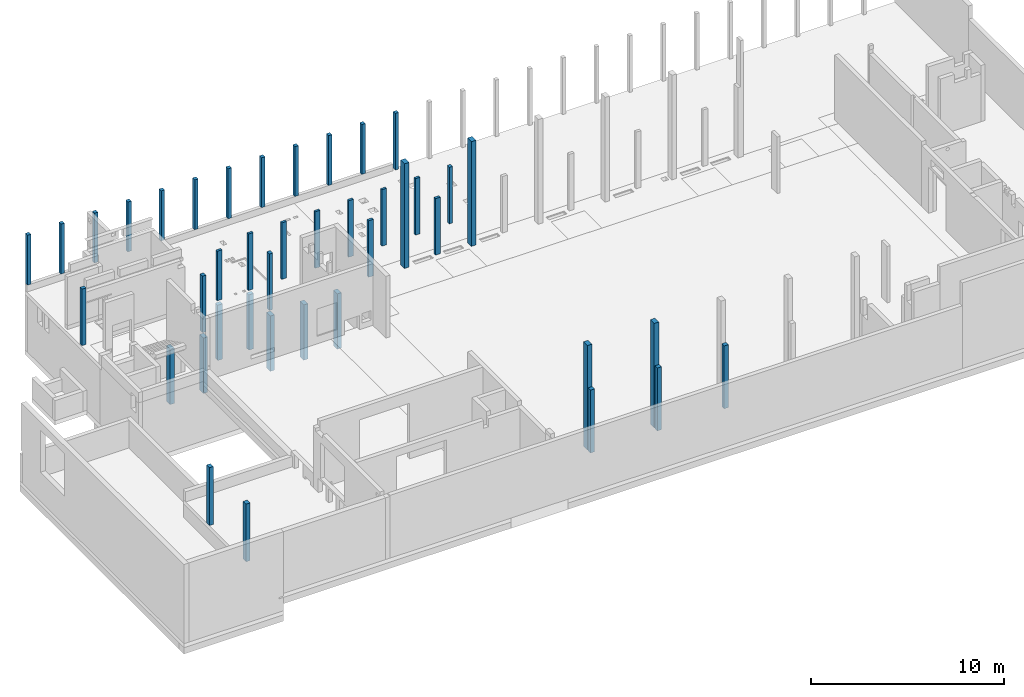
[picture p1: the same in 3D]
Properties of the parts of a building model (IFC2X3), part 5 of 6

# IfcSlab: Bodenplatte:WS_FDN_SLB_1025_Magerbeton, Bodenplatte:WS_FDN_SLB_1025_Magerbeton:3859108
Type - Sonstige - Kategorie: Fundamente; Familienname: Bodenplatte
Type - Konstruktion - Standarddicke: 1.025 m
Type - Bemaßungen - Fundamentstärke: 1.025 m
Type - Grafiken - Farbfüllung für groben Maßstab: 0; Füllmuster für groben Maßstab: WS_CONCRETE
Type - ID-Daten - Typenkommentare: Concrete; Typname: WS_FDN_SLB_1025_Magerbeton; WS_COMMENT_DIMENSION: Magerbetonplombe d=120cm
Type - Materialien und Oberflächen - Tragendes Material: WS_CONCRETE
Type - Analytische Eigenschaften - Absorptionsgrad: 0.1; Rauigkeit: 1
Pset_QuantityTakeOff - Reference: WS_FDN_SLB_1025_Magerbeton; sets with these values: 2
Pset_SlabCommon - IsExternal: no; LoadBearing: yes; PitchAngle: 0 deg; Reference: WS_FDN_SLB_1025_Magerbeton
Sonstige - Familie: Bodenplatte; Familie und Typ: Bodenplatte: WS_FDN_SLB_1025_Magerbeton; Typ: WS_FDN_SLB_1025_Magerbeton; Typ-ID: 3968798
Abhängigkeiten - Für Körper: no; Ebene: Dü_U01_OKRD_-0,12; Höhenversatz von Ebene: -1.1 m
Bemaßungen - Breite: 1.2 m; Dicke: 1.025 m; Fläche: 1.131 m2; Höhe oben: -1.22 m; Höhe oben Kern: -1.22 m; Höhe unten: -2.245 m; Höhe unten Kern: -2.245 m; Höhe Vermessung oben: 460.78 m; Höhe Vermessung unten: 459.755 m; Kernstärke: 1.025 m; Länge: 1.2 m; Umfang: 3.76991 m; Volumen: 1.15924 m3
ID-Daten - Hat Verknüpfung: no; WS_COMMENT_MATERIAL: Magerbeton; WS_POSITIONNUMBER: 020; WS_TYPE_BUILDING_ELEMENT: F
Phasen - Phase erstellt: Phase 1
Tragwerk - Betonüberdeckung - Andere Flächen: Bewehrungsüberdeckung 1 <25 mm>; Betonüberdeckung - Obere Fläche: Bewehrungsüberdeckung 1 <25 mm>; Betonüberdeckung - Untere Fläche: Bewehrungsüberdeckung 1 <25 mm>; Tragwerk: yes
Text - WS_LEVEL: U1

# IfcSlab: Bodenplatte:WS_FDN_SLB_1150_Magerbeton, Bodenplatte:WS_FDN_SLB_1150_Magerbeton:3859123
In: FB_U01_OKFB
Type - PredefinedType: BASESLAB; Material: WS_CONCRETE 1.15 m
Type - Sonstige - Kategorie: Fundamente; Familienname: Bodenplatte
Type - Konstruktion - Standarddicke: 1.15 m
Type - Bemaßungen - Fundamentstärke: 1.15 m
Type - Grafiken - Farbfüllung für groben Maßstab: 0; Füllmuster für groben Maßstab: WS_CONCRETE
Type - ID-Daten - Typenkommentare: Concrete; Typname: WS_FDN_SLB_1150_Magerbeton; WS_COMMENT_DIMENSION: Magerbetonplombe d=120cm
Type - Materialien und Oberflächen - Tragendes Material: WS_CONCRETE
Type - Analytische Eigenschaften - Absorptionsgrad: 0.1; Rauigkeit: 1
Pset_QuantityTakeOff - Reference: WS_FDN_SLB_1150_Magerbeton; sets with these values: 2
Pset_SlabCommon - IsExternal: no; LoadBearing: yes; PitchAngle: 0 deg; Reference: WS_FDN_SLB_1150_Magerbeton
Sonstige - Familie: Bodenplatte; Familie und Typ: Bodenplatte: WS_FDN_SLB_1150_Magerbeton; Typ: WS_FDN_SLB_1150_Magerbeton; Typ-ID: 3968758
Abhängigkeiten - Für Körper: no; Ebene: Dü_U01_OKRD_-0,12; Höhenversatz von Ebene: -1.1 m
Bemaßungen - Breite: 1.2 m; Dicke: 1.15 m; Fläche: 1.131 m2; Höhe oben: -1.22 m; Höhe oben Kern: -1.22 m; Höhe unten: -2.37 m; Höhe unten Kern: -2.37 m; Höhe Vermessung oben: 460.78 m; Höhe Vermessung unten: 459.63 m; Kernstärke: 1.15 m; Länge: 1.2 m; Umfang: 3.76991 m; Volumen: 1.30061 m3
ID-Daten - Hat Verknüpfung: no; WS_COMMENT_MATERIAL: Magerbeton; WS_POSITIONNUMBER: 020; WS_TYPE_BUILDING_ELEMENT: F
Phasen - Phase erstellt: Phase 1
Tragwerk - Betonüberdeckung - Andere Flächen: Bewehrungsüberdeckung 1 <25 mm>; Betonüberdeckung - Obere Fläche: Bewehrungsüberdeckung 1 <25 mm>; Betonüberdeckung - Untere Fläche: Bewehrungsüberdeckung 1 <25 mm>; Tragwerk: yes
Text - WS_LEVEL: U1

# IfcSlab: Bodenplatte:WS_FDN_SLB_1275_Magerbeton, Bodenplatte:WS_FDN_SLB_1275_Magerbeton:3859138
In: FB_U01_OKFB
Type - PredefinedType: BASESLAB; Material: WS_CONCRETE 1.275 m
Type - Sonstige - Kategorie: Fundamente; Familienname: Bodenplatte
Type - Konstruktion - Standarddicke: 1.275 m
Type - Bemaßungen - Fundamentstärke: 1.275 m
Type - Grafiken - Farbfüllung für groben Maßstab: 0; Füllmuster für groben Maßstab: WS_CONCRETE
Type - ID-Daten - Typenkommentare: Concrete; Typname: WS_FDN_SLB_1275_Magerbeton; WS_COMMENT_DIMENSION: Magerbetonplombe d=120cm
Type - Materialien und Oberflächen - Tragendes Material: WS_CONCRETE
Type - Analytische Eigenschaften - Absorptionsgrad: 0.1; Rauigkeit: 1
Pset_QuantityTakeOff - Reference: WS_FDN_SLB_1275_Magerbeton; sets with these values: 2
Pset_SlabCommon - IsExternal: no; LoadBearing: yes; PitchAngle: 0 deg; Reference: WS_FDN_SLB_1275_Magerbeton
Sonstige - Familie: Bodenplatte; Familie und Typ: Bodenplatte: WS_FDN_SLB_1275_Magerbeton; Typ: WS_FDN_SLB_1275_Magerbeton; Typ-ID: 3968718
Abhängigkeiten - Für Körper: no; Ebene: Dü_U01_OKRD_-0,12; Höhenversatz von Ebene: -1.1 m
Bemaßungen - Breite: 1.2 m; Dicke: 1.275 m; Fläche: 1.131 m2; Höhe oben: -1.22 m; Höhe oben Kern: -1.22 m; Höhe unten: -2.495 m; Höhe unten Kern: -2.495 m; Höhe Vermessung oben: 460.78 m; Höhe Vermessung unten: 459.505 m; Kernstärke: 1.275 m; Länge: 1.2 m; Umfang: 3.76991 m; Volumen: 1.44198 m3
ID-Daten - Hat Verknüpfung: no; WS_COMMENT_MATERIAL: Magerbeton; WS_POSITIONNUMBER: 020; WS_TYPE_BUILDING_ELEMENT: F
Phasen - Phase erstellt: Phase 1
Tragwerk - Betonüberdeckung - Andere Flächen: Bewehrungsüberdeckung 1 <25 mm>; Betonüberdeckung - Obere Fläche: Bewehrungsüberdeckung 1 <25 mm>; Betonüberdeckung - Untere Fläche: Bewehrungsüberdeckung 1 <25 mm>; Tragwerk: yes
Text - WS_LEVEL: U1

# IfcSlab: Bodenplatte:WS_FDN_SLB_1400_Magerbeton, Bodenplatte:WS_FDN_SLB_1400_Magerbeton:3924882
In: FB_U01_OKFB
Type - PredefinedType: BASESLAB; Material: WS_CONCRETE 1.4 m
Type - Sonstige - Kategorie: Fundamente; Familienname: Bodenplatte
Type - Konstruktion - Standarddicke: 1.4 m
Type - Bemaßungen - Fundamentstärke: 1.4 m
Type - Grafiken - Farbfüllung für groben Maßstab: 0; Füllmuster für groben Maßstab: WS_CONCRETE
Type - ID-Daten - Typenkommentare: Concrete; Typname: WS_FDN_SLB_1400_Magerbeton; WS_COMMENT_DIMENSION: Magerbetonplombe d=120cm
Type - Materialien und Oberflächen - Tragendes Material: WS_CONCRETE
Type - Analytische Eigenschaften - Absorptionsgrad: 0.1; Rauigkeit: 1
Pset_QuantityTakeOff - Reference: WS_FDN_SLB_1400_Magerbeton; sets with these values: 2
Pset_SlabCommon - IsExternal: no; LoadBearing: yes; PitchAngle: 0 deg; Reference: WS_FDN_SLB_1400_Magerbeton
Sonstige - Familie: Bodenplatte; Familie und Typ: Bodenplatte: WS_FDN_SLB_1400_Magerbeton; Typ: WS_FDN_SLB_1400_Magerbeton; Typ-ID: 3968096
Abhängigkeiten - Für Körper: no; Ebene: Dü_U01_OKRD_-0,12; Höhenversatz von Ebene: -1.1 m
Bemaßungen - Breite: 1.2 m; Dicke: 1.4 m; Fläche: 1.131 m2; Höhe oben: -1.22 m; Höhe oben Kern: -1.22 m; Höhe unten: -2.62 m; Höhe unten Kern: -2.62 m; Höhe Vermessung oben: 460.78 m; Höhe Vermessung unten: 459.38 m; Kernstärke: 1.4 m; Länge: 1.2 m; Umfang: 3.76991 m; Volumen: 1.58335 m3
ID-Daten - Hat Verknüpfung: no; WS_COMMENT_MATERIAL: Magerbeton; WS_POSITIONNUMBER: 020; WS_TYPE_BUILDING_ELEMENT: F
Phasen - Phase erstellt: Phase 1
Tragwerk - Betonüberdeckung - Andere Flächen: Bewehrungsüberdeckung 1 <25 mm>; Betonüberdeckung - Obere Fläche: Bewehrungsüberdeckung 1 <25 mm>; Betonüberdeckung - Untere Fläche: Bewehrungsüberdeckung 1 <25 mm>; Tragwerk: yes
Text - WS_LEVEL: U1

# IfcSlab: Bodenplatte:WS_FDN_SLB_300_WT, Bodenplatte:WS_FDN_SLB_300_WT:4342767
In: FB_U01_OKFB
Type - PredefinedType: BASESLAB; Material: WS_CONCRETE_REINFORCED_WATERTIGHT 0.3 m
Type - Sonstige - Kategorie: Fundamente; Familienname: Bodenplatte
Type - Konstruktion - Standarddicke: 0.3 m
Type - Bemaßungen - Fundamentstärke: 0.3 m
Type - Grafiken - Farbfüllung für groben Maßstab: 0; Füllmuster für groben Maßstab: WS_CONCRETE_REINFORCED_WATERTIGHT
Type - ID-Daten - Typenkommentare: Reinforced Concrete; Typname: WS_FDN_SLB_300_WT; WS_COMMENT_DIMENSION: h=30cm
Type - Materialien und Oberflächen - Tragendes Material: WS_CONCRETE_REINFORCED_WATERTIGHT
Type - Analytische Eigenschaften - Absorptionsgrad: 0.1; Rauigkeit: 1
Pset_QuantityTakeOff - Reference: WS_FDN_SLB_300_WT; sets with these values: 2
Pset_SlabCommon - IsExternal: no; LoadBearing: yes; PitchAngle: 0 deg; Reference: WS_FDN_SLB_300_WT
Sonstige - Familie: Bodenplatte; Familie und Typ: Bodenplatte: WS_FDN_SLB_300_WT; Typ: WS_FDN_SLB_300_WT; Typ-ID: 4216695
Abhängigkeiten - Für Körper: no; Höhenversatz von Ebene: 0 m; Ebene: Dü_U01_OKBP_-1,77_Bodenkanal_M
Bemaßungen - Breite: 34.765 m; Dicke: 0.3 m; Fläche: 83.309 m2; Höhe oben: -1.77 m; Höhe oben Kern: -1.77 m; Höhe unten: -2.07 m; Höhe unten Kern: -2.07 m; Höhe Vermessung oben: 460.23 m; Höhe Vermessung unten: 459.93 m; Kernstärke: 0.3 m; Länge: 3.55493 m; Umfang: 76.6399 m; Volumen: 24.9927 m3; WS_HEIGHT: 0.3 m
ID-Daten - Hat Verknüpfung: no; WS_COMMENT_MATERIAL: C25/30 WU; WS_POSITIONNUMBER: 006; WS_TYPE_BUILDING_ELEMENT: F
Phasen - Phase erstellt: Phase 1
Tragwerk - Betonüberdeckung - Andere Flächen: Bewehrungsüberdeckung 1 <25 mm>; Betonüberdeckung - Obere Fläche: Bewehrungsüberdeckung 1 <25 mm>; Betonüberdeckung - Untere Fläche: Bewehrungsüberdeckung 1 <25 mm>; Tragwerk: yes
Text - WS_LEVEL: U1

# IfcSlab: Bodenplatte:WS_FDN_SLB_400_Magerbeton, Bodenplatte:WS_FDN_SLB_400_Magerbeton:3791860
In: FB_U01_OKFB
Type - PredefinedType: BASESLAB; Material: WS_CONCRETE 0.4 m
Type - Sonstige - Kategorie: Fundamente; Familienname: Bodenplatte
Type - Konstruktion - Standarddicke: 0.4 m
Type - Bemaßungen - Fundamentstärke: 0.4 m
Type - Grafiken - Farbfüllung für groben Maßstab: 0; Füllmuster für groben Maßstab: WS_CONCRETE
Type - ID-Daten - Typenkommentare: Concrete; Typname: WS_FDN_SLB_400_Magerbeton; WS_COMMENT_DIMENSION: Magerbetonplombe d=120cm
Type - Materialien und Oberflächen - Tragendes Material: WS_CONCRETE
Type - Analytische Eigenschaften - Absorptionsgrad: 0.1; Rauigkeit: 1
Pset_QuantityTakeOff - Reference: WS_FDN_SLB_400_Magerbeton; sets with these values: 2
Pset_SlabCommon - IsExternal: no; LoadBearing: yes; PitchAngle: 0 deg; Reference: WS_FDN_SLB_400_Magerbeton
Sonstige - Familie: Bodenplatte; Familie und Typ: Bodenplatte: WS_FDN_SLB_400_Magerbeton; Typ: WS_FDN_SLB_400_Magerbeton; Typ-ID: 3968128
Abhängigkeiten - Für Körper: no; Ebene: Dü_U01_OKRD_-0,12; Höhenversatz von Ebene: -1.1 m
Bemaßungen - Breite: 1.2 m; Dicke: 0.4 m; Fläche: 1.131 m2; Höhe oben: -1.22 m; Höhe oben Kern: -1.22 m; Höhe unten: -1.62 m; Höhe unten Kern: -1.62 m; Höhe Vermessung oben: 460.78 m; Höhe Vermessung unten: 460.38 m; Kernstärke: 0.4 m; Länge: 1.2 m; Umfang: 3.76991 m; Volumen: 0.452386 m3
ID-Daten - Hat Verknüpfung: no; WS_COMMENT_MATERIAL: Magerbeton; WS_POSITIONNUMBER: 020; WS_TYPE_BUILDING_ELEMENT: F
Phasen - Phase erstellt: Phase 1
Tragwerk - Betonüberdeckung - Andere Flächen: Bewehrungsüberdeckung 1 <25 mm>; Betonüberdeckung - Obere Fläche: Bewehrungsüberdeckung 1 <25 mm>; Betonüberdeckung - Untere Fläche: Bewehrungsüberdeckung 1 <25 mm>; Tragwerk: yes
Text - WS_LEVEL: U1

# IfcSlab: Bodenplatte:WS_FDN_SLB_525_Magerbeton, Bodenplatte:WS_FDN_SLB_525_Magerbeton:3859038
In: FB_U01_OKFB
Type - PredefinedType: BASESLAB; Material: WS_CONCRETE 0.525 m
Type - Sonstige - Kategorie: Fundamente; Familienname: Bodenplatte
Type - Konstruktion - Standarddicke: 0.525 m
Type - Bemaßungen - Fundamentstärke: 0.525 m
Type - Grafiken - Farbfüllung für groben Maßstab: 0; Füllmuster für groben Maßstab: WS_CONCRETE
Type - ID-Daten - Typenkommentare: Concrete; Typname: WS_FDN_SLB_525_Magerbeton; WS_COMMENT_DIMENSION: Magerbetonplombe d=120cm
Type - Materialien und Oberflächen - Tragendes Material: WS_CONCRETE
Type - Analytische Eigenschaften - Absorptionsgrad: 0.1; Rauigkeit: 1
Pset_QuantityTakeOff - Reference: WS_FDN_SLB_525_Magerbeton; sets with these values: 2
Pset_SlabCommon - IsExternal: no; LoadBearing: yes; PitchAngle: 0 deg; Reference: WS_FDN_SLB_525_Magerbeton
Sonstige - Familie: Bodenplatte; Familie und Typ: Bodenplatte: WS_FDN_SLB_525_Magerbeton; Typ: WS_FDN_SLB_525_Magerbeton; Typ-ID: 3968958
Abhängigkeiten - Für Körper: no; Ebene: Dü_U01_OKRD_-0,12; Höhenversatz von Ebene: -1.1 m
Bemaßungen - Breite: 1.2 m; Dicke: 0.525 m; Fläche: 1.131 m2; Höhe oben: -1.22 m; Höhe oben Kern: -1.22 m; Höhe unten: -1.745 m; Höhe unten Kern: -1.745 m; Höhe Vermessung oben: 460.78 m; Höhe Vermessung unten: 460.255 m; Kernstärke: 0.525 m; Länge: 1.2 m; Umfang: 3.76991 m; Volumen: 0.593757 m3
ID-Daten - Hat Verknüpfung: no; WS_COMMENT_MATERIAL: Magerbeton; WS_POSITIONNUMBER: 020; WS_TYPE_BUILDING_ELEMENT: F
Phasen - Phase erstellt: Phase 1
Tragwerk - Betonüberdeckung - Andere Flächen: Bewehrungsüberdeckung 1 <25 mm>; Betonüberdeckung - Obere Fläche: Bewehrungsüberdeckung 1 <25 mm>; Betonüberdeckung - Untere Fläche: Bewehrungsüberdeckung 1 <25 mm>; Tragwerk: yes
Text - WS_LEVEL: U1

# IfcSlab: Bodenplatte:WS_FDN_SLB_650_Magerbeton, Bodenplatte:WS_FDN_SLB_650_Magerbeton:3859053
In: FB_U01_OKFB
Type - PredefinedType: BASESLAB; Material: WS_CONCRETE 0.65 m
Type - Sonstige - Kategorie: Fundamente; Familienname: Bodenplatte
Type - Konstruktion - Standarddicke: 0.65 m
Type - Bemaßungen - Fundamentstärke: 0.65 m
Type - Grafiken - Farbfüllung für groben Maßstab: 0; Füllmuster für groben Maßstab: WS_CONCRETE
Type - ID-Daten - Typenkommentare: Concrete; Typname: WS_FDN_SLB_650_Magerbeton; WS_COMMENT_DIMENSION: Magerbetonplombe d=120cm
Type - Materialien und Oberflächen - Tragendes Material: WS_CONCRETE
Type - Analytische Eigenschaften - Absorptionsgrad: 0.1; Rauigkeit: 1
Pset_QuantityTakeOff - Reference: WS_FDN_SLB_650_Magerbeton; sets with these values: 2
Pset_SlabCommon - IsExternal: no; LoadBearing: yes; PitchAngle: 0 deg; Reference: WS_FDN_SLB_650_Magerbeton
Sonstige - Familie: Bodenplatte; Familie und Typ: Bodenplatte: WS_FDN_SLB_650_Magerbeton; Typ: WS_FDN_SLB_650_Magerbeton; Typ-ID: 3968918
Abhängigkeiten - Für Körper: no; Ebene: Dü_U01_OKRD_-0,12; Höhenversatz von Ebene: -1.1 m
Bemaßungen - Breite: 1.2 m; Dicke: 0.65 m; Fläche: 1.131 m2; Höhe oben: -1.22 m; Höhe oben Kern: -1.22 m; Höhe unten: -1.87 m; Höhe unten Kern: -1.87 m; Höhe Vermessung oben: 460.78 m; Höhe Vermessung unten: 460.13 m; Kernstärke: 0.65 m; Länge: 1.2 m; Umfang: 3.76991 m; Volumen: 0.735128 m3
ID-Daten - Hat Verknüpfung: no; WS_COMMENT_MATERIAL: Magerbeton; WS_POSITIONNUMBER: 020; WS_TYPE_BUILDING_ELEMENT: F
Phasen - Phase erstellt: Phase 1
Tragwerk - Betonüberdeckung - Andere Flächen: Bewehrungsüberdeckung 1 <25 mm>; Betonüberdeckung - Obere Fläche: Bewehrungsüberdeckung 1 <25 mm>; Betonüberdeckung - Untere Fläche: Bewehrungsüberdeckung 1 <25 mm>; Tragwerk: yes
Text - WS_LEVEL: U1

# IfcSlab: Bodenplatte:WS_FDN_SLB_650_WT, Bodenplatte:WS_FDN_SLB_650_WT:3664736
In: FB_U01_OKFB
Type - PredefinedType: BASESLAB; Material: WS_CONCRETE_REINFORCED_WATERTIGHT 0.65 m
Type - Sonstige - Kategorie: Fundamente; Familienname: Bodenplatte
Type - Konstruktion - Standarddicke: 0.65 m
Type - Bemaßungen - Fundamentstärke: 0.65 m
Type - Grafiken - Farbfüllung für groben Maßstab: 0; Füllmuster für groben Maßstab: WS_CONCRETE_REINFORCED_WATERTIGHT
Type - ID-Daten - Typenkommentare: Reinforced Concrete; Typname: WS_FDN_SLB_650_WT; WS_COMMENT_DIMENSION: h=65cm
Type - Materialien und Oberflächen - Tragendes Material: WS_CONCRETE_REINFORCED_WATERTIGHT
Type - Analytische Eigenschaften - Absorptionsgrad: 0.1; Rauigkeit: 1
Pset_QuantityTakeOff - Reference: WS_FDN_SLB_650_WT; sets with these values: 2
Pset_SlabCommon - Reference: WS_FDN_SLB_650_WT; IsExternal: no; LoadBearing: yes; PitchAngle: 0 deg
Sonstige - Familie: Bodenplatte; Familie und Typ: Bodenplatte: WS_FDN_SLB_650_WT; Typ: WS_FDN_SLB_650_WT; Typ-ID: 3903083
Abhängigkeiten - Ebene: BP_UG1_OKBP_-5,30_Unterfahrt; Für Körper: no; Höhenversatz von Ebene: 0 m
Bemaßungen - Breite: 2.2 m; Dicke: 0.65 m; Fläche: 5.60991 m2; Höhe oben: -5.3 m; Höhe oben Kern: -5.3 m; Höhe unten: -5.95 m; Höhe unten Kern: -5.95 m; Höhe Vermessung oben: 456.7 m; Höhe Vermessung unten: 456.05 m; Kernstärke: 0.65 m; Länge: 2.54996 m; Umfang: 9.49992 m; Volumen: 3.64644 m3
ID-Daten - Hat Verknüpfung: no; WS_COMMENT_MATERIAL: C25/30 WU; WS_POSITIONNUMBER: 001; WS_TYPE_BUILDING_ELEMENT: F
Phasen - Phase erstellt: Phase 1
Tragwerk - Betonüberdeckung - Andere Flächen: Bewehrungsüberdeckung 1 <25 mm>; Betonüberdeckung - Obere Fläche: Bewehrungsüberdeckung 1 <25 mm>; Betonüberdeckung - Untere Fläche: Bewehrungsüberdeckung 1 <25 mm>; Tragwerk: yes
Text - WS_LEVEL: FU

# IfcSlab: Bodenplatte:WS_FDN_SLB_775_Magerbeton, Bodenplatte:WS_FDN_SLB_775_Magerbeton:3859070
In: FB_U01_OKFB
Type - PredefinedType: BASESLAB; Material: WS_CONCRETE 0.775 m
Type - Sonstige - Kategorie: Fundamente; Familienname: Bodenplatte
Type - Konstruktion - Standarddicke: 0.775 m
Type - Bemaßungen - Fundamentstärke: 0.775 m
Type - Grafiken - Farbfüllung für groben Maßstab: 0; Füllmuster für groben Maßstab: WS_CONCRETE
Type - ID-Daten - Typenkommentare: Concrete; Typname: WS_FDN_SLB_775_Magerbeton; WS_COMMENT_DIMENSION: Magerbetonplombe d=120cm
Type - Materialien und Oberflächen - Tragendes Material: WS_CONCRETE
Type - Analytische Eigenschaften - Absorptionsgrad: 0.1; Rauigkeit: 1
Pset_QuantityTakeOff - Reference: WS_FDN_SLB_775_Magerbeton; sets with these values: 2
Pset_SlabCommon - IsExternal: no; LoadBearing: yes; PitchAngle: 0 deg; Reference: WS_FDN_SLB_775_Magerbeton
Sonstige - Familie: Bodenplatte; Familie und Typ: Bodenplatte: WS_FDN_SLB_775_Magerbeton; Typ: WS_FDN_SLB_775_Magerbeton; Typ-ID: 3968878
Abhängigkeiten - Für Körper: no; Ebene: Dü_U01_OKRD_-0,12; Höhenversatz von Ebene: -1.1 m
Bemaßungen - Breite: 1.2 m; Dicke: 0.775 m; Fläche: 1.131 m2; Höhe oben: -1.22 m; Höhe oben Kern: -1.22 m; Höhe unten: -1.995 m; Höhe unten Kern: -1.995 m; Höhe Vermessung oben: 460.78 m; Höhe Vermessung unten: 460.005 m; Kernstärke: 0.775 m; Länge: 1.2 m; Umfang: 3.76991 m; Volumen: 0.876498 m3
ID-Daten - Hat Verknüpfung: no; WS_COMMENT_MATERIAL: Magerbeton; WS_POSITIONNUMBER: 020; WS_TYPE_BUILDING_ELEMENT: F
Phasen - Phase erstellt: Phase 1
Tragwerk - Betonüberdeckung - Andere Flächen: Bewehrungsüberdeckung 1 <25 mm>; Betonüberdeckung - Obere Fläche: Bewehrungsüberdeckung 1 <25 mm>; Betonüberdeckung - Untere Fläche: Bewehrungsüberdeckung 1 <25 mm>; Tragwerk: yes
Text - WS_LEVEL: U1

# IfcSlab: Bodenplatte:WS_FDN_SLB_900_Magerbeton, Bodenplatte:WS_FDN_SLB_900_Magerbeton:3859091
In: FB_U01_OKFB
Type - PredefinedType: BASESLAB; Material: WS_CONCRETE 0.9 m
Type - Sonstige - Kategorie: Fundamente; Familienname: Bodenplatte
Type - Konstruktion - Standarddicke: 0.9 m
Type - Bemaßungen - Fundamentstärke: 0.9 m
Type - Grafiken - Farbfüllung für groben Maßstab: 0; Füllmuster für groben Maßstab: WS_CONCRETE
Type - ID-Daten - Typenkommentare: Concrete; Typname: WS_FDN_SLB_900_Magerbeton; WS_COMMENT_DIMENSION: Magerbetonplombe d=120cm
Type - Materialien und Oberflächen - Tragendes Material: WS_CONCRETE
Type - Analytische Eigenschaften - Absorptionsgrad: 0.1; Rauigkeit: 1
Pset_QuantityTakeOff - Reference: WS_FDN_SLB_900_Magerbeton; sets with these values: 2
Pset_SlabCommon - IsExternal: no; LoadBearing: yes; PitchAngle: 0 deg; Reference: WS_FDN_SLB_900_Magerbeton
Sonstige - Familie: Bodenplatte; Familie und Typ: Bodenplatte: WS_FDN_SLB_900_Magerbeton; Typ: WS_FDN_SLB_900_Magerbeton; Typ-ID: 3968838
Abhängigkeiten - Für Körper: no; Ebene: Dü_U01_OKRD_-0,12; Höhenversatz von Ebene: -1.1 m
Bemaßungen - Breite: 1.2 m; Dicke: 0.9 m; Fläche: 1.131 m2; Höhe oben: -1.22 m; Höhe oben Kern: -1.22 m; Höhe unten: -2.12 m; Höhe unten Kern: -2.12 m; Höhe Vermessung oben: 460.78 m; Höhe Vermessung unten: 459.88 m; Kernstärke: 0.9 m; Länge: 1.2 m; Umfang: 3.76991 m; Volumen: 1.01787 m3
ID-Daten - Hat Verknüpfung: no; WS_COMMENT_MATERIAL: Magerbeton; WS_POSITIONNUMBER: 020; WS_TYPE_BUILDING_ELEMENT: F
Phasen - Phase erstellt: Phase 1
Tragwerk - Betonüberdeckung - Andere Flächen: Bewehrungsüberdeckung 1 <25 mm>; Betonüberdeckung - Obere Fläche: Bewehrungsüberdeckung 1 <25 mm>; Betonüberdeckung - Untere Fläche: Bewehrungsüberdeckung 1 <25 mm>; Tragwerk: yes
Text - WS_LEVEL: U1

# IfcSlab: Foyertreppe:Foyertreppe, Foyertreppe:Foyertreppe:4777356
In: FB_E00_OKFB
Type - PredefinedType: FLOOR; Material: WS_CONCRETE_REINFORCED_PRECAST
Type - Sonstige - Kategorie: Geschossdecken; Familienname: Foyertreppe
Type - ID-Daten - Typname: Foyertreppe
Pset_QuantityTakeOff - Reference: Foyertreppe; sets with these values: 2
Pset_SlabCommon - IsExternal: no; Reference: Foyertreppe
Sonstige - Familie: Foyertreppe; Familie und Typ: Foyertreppe: Foyertreppe; Typ: Foyertreppe; Typ-ID: 4777354
Abhängigkeiten - Raumbegrenzung: yes; Verschieben mit umliegenden Elementen: no; Ebene: Dü_EG_UKRD_+4,15
Bemaßungen - Fläche: 2.42864 m2; Volumen: 4.17726 m3
Phasen - Phase erstellt: Phase 1
Tragwerk - Betonüberdeckung: Bewehrungsüberdeckung 1 <25 mm>

# IfcSlab: Geschossdecke:WS_SLB_CON_100_PC, Geschossdecke:WS_SLB_CON_100_PC:3691767
In: FB_E00_OKFB
Type - PredefinedType: FLOOR; Material: WS_CONCRETE_PRECAST 0.1 m
Type - Sonstige - Kategorie: Geschossdecken; Familienname: Geschossdecke
Type - Konstruktion - Funktion: Innen; Standarddicke: 0.1 m
Type - Grafiken - Farbfüllung für groben Maßstab: 0; Füllmuster für groben Maßstab: WS_CONCRETE_PRECAST
Type - ID-Daten - Typenkommentare: Concrete precast; Typname: WS_SLB_CON_100_PC; WS_COMMENT_DIMENSION: h=10cm
Type - Materialien und Oberflächen - Tragendes Material: WS_CONCRETE_PRECAST
Type - Analytische Eigenschaften - Absorptionsgrad: 0.1; Rauigkeit: 1
Pset_QuantityTakeOff - Reference: WS_SLB_CON_100_PC; sets with these values: 2
Pset_SlabCommon - IsExternal: no; LoadBearing: yes; PitchAngle: 0 deg; Reference: WS_SLB_CON_100_PC
Sonstige - Familie: Geschossdecke; Familie und Typ: Geschossdecke: WS_SLB_CON_100_PC; Typ: WS_SLB_CON_100_PC; Typ-ID: 4372535
Abhängigkeiten - Für Körper: no; Raumbegrenzung: yes; Ebene: Dü_U01_OKBP_+0,78; Höhenversatz von Ebene: -0.42 m
Bemaßungen - Dicke: 0.1 m; Fläche: 2.992 m2; Höhe oben: 0.36 m; Höhe oben Kern: 0.36 m; Höhe unten: 0.26 m; Höhe unten Kern: 0.26 m; Höhe Vermessung oben: 462.36 m; Höhe Vermessung unten: 462.26 m; Kernstärke: 0.1 m; Umfang: 7.64 m; Volumen: 0.2992 m3
ID-Daten - Hat Verknüpfung: no; WS_COMMENT_MATERIAL: C35/45; WS_POSITIONNUMBER: 201; WS_TYPE_BUILDING_ELEMENT: F
Phasen - Phase erstellt: Phase 1
Tragwerk - Betonüberdeckung - Andere Flächen: Bewehrungsüberdeckung 1 <25 mm>; Betonüberdeckung - Obere Fläche: Bewehrungsüberdeckung 1 <25 mm>; Betonüberdeckung - Untere Fläche: Bewehrungsüberdeckung 1 <25 mm>; Tragwerk: yes
Text - WS_LEVEL: U1

# IfcSlab: Geschossdecke:WS_SLB_CON_150 (2)
In: FB_E00_OKFB
Type - PredefinedType: FLOOR; Material: WS_CONCRETE_REINFORCED 0.15 m
Type - Sonstige - Kategorie: Geschossdecken; Familienname: Geschossdecke
Type - Konstruktion - Funktion: Innen; Standarddicke: 0.15 m
Type - Grafiken - Farbfüllung für groben Maßstab: 0; Füllmuster für groben Maßstab: WS_CONCRETE_REINFORCED
Type - ID-Daten - Typenkommentare: Reinforced Concrete; Typname: WS_SLB_CON_150; WS_COMMENT_DIMENSION: h=15cm
Type - Materialien und Oberflächen - Tragendes Material: WS_CONCRETE_REINFORCED
Type - Analytische Eigenschaften - Absorptionsgrad: 0.1; Rauigkeit: 1
Pset_QuantityTakeOff - Reference: WS_SLB_CON_150; sets with these values: 2
Pset_SlabCommon - IsExternal: no; LoadBearing: yes; PitchAngle: 0 deg; Reference: WS_SLB_CON_150
Sonstige - Familie: Geschossdecke; Familie und Typ: Geschossdecke: WS_SLB_CON_150; Typ: WS_SLB_CON_150; Typ-ID: 4456106
Abhängigkeiten - Für Körper: no; Höhenversatz von Ebene: 0 m; Raumbegrenzung: yes; Ebene: Dü_OG1_OKRD_+8,065
Bemaßungen - Dicke: 0.15 m; Höhe oben: 8.065 m; Höhe oben Kern: 8.065 m; Höhe unten: 7.915 m; Höhe unten Kern: 7.915 m; Höhe Vermessung oben: 470.065 m; Höhe Vermessung unten: 469.915 m; Kernstärke: 0.15 m
ID-Daten - Hat Verknüpfung: no; WS_COMMENT_MATERIAL: C25/30 RC; WS_TYPE_BUILDING_ELEMENT: S
Phasen - Phase erstellt: Phase 1
Tragwerk - Betonüberdeckung - Andere Flächen: Bewehrungsüberdeckung 1 <25 mm>; Betonüberdeckung - Obere Fläche: Bewehrungsüberdeckung 1 <25 mm>; Betonüberdeckung - Untere Fläche: Bewehrungsüberdeckung 1 <25 mm>; Tragwerk: yes
Text - WS_LEVEL: 01
Name (Geschossdecke:WS_SLB_CON_150:...) | Fläche (m2) | Umfang (m) | Volumen (m3) | WS_POSITIONNUMBER
3711566 | 8.89346 | 12.6498 | 1.33402 | 003
3712874 | 5.24 | 9.3 | 0.786 | 004

# IfcSlab: Geschossdecke:WS_SLB_CON_200 (2)
In: FB_E00_OKFB
Type - PredefinedType: FLOOR; Material: WS_CONCRETE_REINFORCED 0.2 m
Type - Sonstige - Kategorie: Geschossdecken; Familienname: Geschossdecke
Type - Konstruktion - Funktion: Innen; Standarddicke: 0.2 m
Type - Grafiken - Farbfüllung für groben Maßstab: 0; Füllmuster für groben Maßstab: WS_CONCRETE
Type - ID-Daten - Typenkommentare: Concrete unreinforced; Typname: WS_SLB_CON_200; WS_COMMENT_DIMENSION: h=20cm
Type - Materialien und Oberflächen - Tragendes Material: WS_CONCRETE_REINFORCED
Type - Analytische Eigenschaften - Absorptionsgrad: 0.1; Rauigkeit: 1
Pset_QuantityTakeOff - Reference: WS_SLB_CON_200; sets with these values: 2
Pset_SlabCommon - IsExternal: no; LoadBearing: yes; PitchAngle: 0 deg; Reference: WS_SLB_CON_200
Sonstige - Familie: Geschossdecke; Familie und Typ: Geschossdecke: WS_SLB_CON_200; Typ: WS_SLB_CON_200; Typ-ID: 3551158
Abhängigkeiten - Für Körper: no; Höhenversatz von Ebene: 0 m; Raumbegrenzung: yes
Bemaßungen - Dicke: 0.2 m; Kernstärke: 0.2 m
ID-Daten - Hat Verknüpfung: no; WS_COMMENT_MATERIAL: C25/30 RC; WS_TYPE_BUILDING_ELEMENT: S
Phasen - Phase erstellt: Phase 1
Tragwerk - Betonüberdeckung - Andere Flächen: Bewehrungsüberdeckung 1 <25 mm>; Betonüberdeckung - Obere Fläche: Bewehrungsüberdeckung 1 <25 mm>; Betonüberdeckung - Untere Fläche: Bewehrungsüberdeckung 1 <25 mm>; Tragwerk: yes
Text - WS_LEVEL: 00
Name (Geschossdecke:WS_SLB_CON_200:...) | Ebene | Fläche (m2) | Höhe oben (m) = Höhe oben Kern (m) | Höhe unten (m) = Höhe unten Kern (m) | Höhe Vermessung oben (m) | Höhe Vermessung unten (m) | Umfang (m) | Volumen (m3) | WS_POSITIONNUMBER
3696179 | Dü_EG_OKRD_+2,86 | 3.13642 | 2.86 | 2.66 | 464.86 | 464.66 | 7.40013 | 0.627285 | 009
3876725 | Dü_EG_OKRD_+5,12 | 7.43947 | 5.12 | 4.92 | 467.12 | 466.92 | 17.9602 | 1.48789 | 010

# IfcSlab: Geschossdecke:WS_SLB_CON_250 (13)
Type - PredefinedType: FLOOR; Material: WS_CONCRETE_REINFORCED 0.25 m
Type - Sonstige - Kategorie: Geschossdecken; Familienname: Geschossdecke
Type - Konstruktion - Funktion: Innen; Standarddicke: 0.25 m
Type - Grafiken - Farbfüllung für groben Maßstab: 0; Füllmuster für groben Maßstab: WS_CONCRETE_REINFORCED
Type - ID-Daten - Typenkommentare: Reinforced Concrete; Typname: WS_SLB_CON_250; WS_COMMENT_DIMENSION: h=25cm
Type - Materialien und Oberflächen - Tragendes Material: WS_CONCRETE_REINFORCED
Type - Analytische Eigenschaften - Absorptionsgrad: 0.1; Rauigkeit: 1
Pset_QuantityTakeOff - Reference: WS_SLB_CON_250; sets with these values: 2
Pset_SlabCommon - IsExternal: no; LoadBearing: yes; PitchAngle: 0 deg; Reference: WS_SLB_CON_250
Sonstige - Familie: Geschossdecke; Familie und Typ: Geschossdecke: WS_SLB_CON_250; Typ: WS_SLB_CON_250; Typ-ID: 488538
Abhängigkeiten - Für Körper: no; Raumbegrenzung: yes
Bemaßungen - Dicke: 0.25 m; Kernstärke: 0.25 m
ID-Daten - Hat Verknüpfung: no
Phasen - Phase erstellt: Phase 1
Tragwerk - Betonüberdeckung - Andere Flächen: Bewehrungsüberdeckung 1 <25 mm>; Betonüberdeckung - Obere Fläche: Bewehrungsüberdeckung 1 <25 mm>; Betonüberdeckung - Untere Fläche: Bewehrungsüberdeckung 1 <25 mm>; Tragwerk: yes
Name (Geschossdecke:WS_SLB_CON_250:...) | In | Höhenversatz von Ebene (m) | Ebene | Fläche (m2) | Höhe oben (m) = Höhe oben Kern (m) | Höhe unten (m) = Höhe unten Kern (m) | Höhe Vermessung oben (m) | Höhe Vermessung unten (m) | Umfang (m) | Volumen (m3) | WS_COMMENT_MATERIAL | WS_POSITIONNUMBER | WS_TYPE_BUILDING_ELEMENT | WS_LEVEL
3671416 | FB_U01_OKFB | 0 | Dü_U01_OKRD_-0,12 | 145.004 | -0.12 | -0.37 | 461.88 | 461.63 | 69.0001 | 36.1677 | C25/30 RC | 001 | S | U1 | Material: WS_CONCRETE_REINFORCED
3684240 | FB_E00_OKFB | 0 | Dü_U01_OKBP_+0,78 | 104.015 | 0.78 | 0.53 | 462.78 | 462.53 | 56.918 | 25.9752 | C25/30 RC | 002 | F | U1
3697365 | FB_E00_OKFB | 0 | Dü_EG_OKRD_+3,985 | 19.6198 | 3.985 | 3.735 | 465.985 | 465.735 | 26.4298 | 4.87556 | C25/30 RC | 09 | S | 00
3698243 | FB_E00_OKFB | 0 | Dü_EG_OKRD_+3,68 | 120.608 | 3.68 | 3.43 | 465.68 | 465.43 | 51.05 | 30.1493 | C25/30 RC | 008 | S | 00
3702198 | FB_E00_OKFB | 0 | Dü_EG_OKRD_+4,035 | 317.083 | 4.035 | 3.785 | 466.035 | 465.785 | 90.14 | 79.0939 | C25/30 RC | 003 | S | 00 | Material: WS_CONCRETE_REINFORCED
3702850 | FB_E00_OKFB | 0 | Dü_EG_OKRD_+4,40 | 39.984 | 4.4 | 4.15 | 466.4 | 466.15 | 29.3598 | 9.996 | C25/30 RC | 005 | S | 00
3705441 | FB_U01_OKFB | 0 | Dü_U01_OKBP_-0,75_Hubtisch | 4.6006 | -0.75 | -1 | 461.25 | 461 | 8.62984 | 1.15015 | C25/30 RC | 002 | F | U1
3815343 | FB_U01_OKFB | 0 | Dü_U01_OKRD_-0,12 | 55.198 | -0.12 | -0.37 | 461.88 | 461.63 | 60.7499 | 13.7695 | C25/30 RC | 005 | F | U1 | Material: WS_CONCRETE_REINFORCED
3855979 | FB_U01_OKFB | 0 | Dü_U01_OKRD_-0,12 | 6.30187 | -0.12 | -0.37 | 461.88 | 461.63 | 11.1999 | 1.57547 | C25/30 RC |  |  | U1
4213655 | FB_U01_OKFB | 0 | Dü_U01_OKRD_-0,12 | 272.832 | -0.12 | -0.37 | 461.88 | 461.63 | 90.58 | 68.2079 | C25/30 RC | 003 | F | U1
4215173 | FB_U01_OKFB | 0 | Dü_U01_OKRD_-0,12 | 5.93483 | -0.12 | -0.37 | 461.88 | 461.63 | 13.7899 | 1.48371 | C25/30 RC | 005 | F | U1
4333588 | FB_E00_OKFB | -1.95 | Dü_EG_OKRD_+4,035 | 1.9425 | 2.085 | 1.835 | 464.085 | 463.835 | 5.72 | 0.426825
4747582 | FB_U01_OKFB | -1.775 | Dü_U01_OKRD_-0,12 | 3.4937 | -1.895 | -2.145 | 460.105 | 459.855 | 8.31008 | 0.829282 | Material: WS_CONCRETE_REINFORCED

# IfcSlab: Geschossdecke:WS_SLB_CON_250_FT (6)
In: FB_U01_OKFB
Type - PredefinedType: FLOOR; Material: WS_CONCRETE_PRECAST 0.25 m
Type - Sonstige - Kategorie: Geschossdecken; Familienname: Geschossdecke
Type - Konstruktion - Funktion: Innen; Standarddicke: 0.25 m
Type - Grafiken - Farbfüllung für groben Maßstab: 0; Füllmuster für groben Maßstab: WS_CONCRETE_REINFORCED_PRECAST
Type - ID-Daten - Typenkommentare: Reinforced Concrete; Typname: WS_SLB_CON_250_FT; WS_COMMENT_DIMENSION: h=25cm
Type - Materialien und Oberflächen - Tragendes Material: WS_CONCRETE_PRECAST
Type - Analytische Eigenschaften - Absorptionsgrad: 0.1; Rauigkeit: 1
Pset_QuantityTakeOff - Reference: WS_SLB_CON_250_FT; sets with these values: 2
Pset_SlabCommon - IsExternal: no; LoadBearing: yes; PitchAngle: 0 deg; Reference: WS_SLB_CON_250_FT
Sonstige - Familie: Geschossdecke; Familie und Typ: Geschossdecke: WS_SLB_CON_250_FT; Typ: WS_SLB_CON_250_FT; Typ-ID: 4838540
Abhängigkeiten - Für Körper: no; Höhenversatz von Ebene: 0 m; Raumbegrenzung: yes; Ebene: Dü_U01_OKRD_-0,12
Bemaßungen - Dicke: 0.25 m; Höhe oben: -0.12 m; Höhe oben Kern: -0.12 m; Höhe unten: -0.37 m; Höhe unten Kern: -0.37 m; Höhe Vermessung oben: 461.88 m; Höhe Vermessung unten: 461.63 m; Kernstärke: 0.25 m
ID-Daten - Hat Verknüpfung: no
Phasen - Phase erstellt: Phase 1
Tragwerk - Betonüberdeckung - Andere Flächen: Bewehrungsüberdeckung 1 <25 mm>; Betonüberdeckung - Obere Fläche: Bewehrungsüberdeckung 1 <25 mm>; Betonüberdeckung - Untere Fläche: Bewehrungsüberdeckung 1 <25 mm>; Tragwerk: yes
Name (Geschossdecke:WS_SLB_CON_250_FT:...) | Fläche (m2) | Umfang (m) | Volumen (m3)
4836965 | 4.832 | 9.42 | 1.208
4837419 | 3.6 | 7.6 | 0.9
4837495 | 3.6 | 7.6 | 0.9
4837512 | 3.6 | 7.6 | 0.9
4837527 | 3.6 | 7.6 | 0.9
4837544 | 2.7 | 6.6 | 0.675

# IfcSlab: Geschossdecke:WS_SLB_CON_250_WT (4)
In: FB_U01_OKFB
Type - PredefinedType: FLOOR; Material: WS_CONCRETE_REINFORCED_WATERTIGHT 0.25 m
Type - Sonstige - Kategorie: Geschossdecken; Familienname: Geschossdecke
Type - Konstruktion - Funktion: Innen; Standarddicke: 0.25 m
Type - Grafiken - Farbfüllung für groben Maßstab: 0; Füllmuster für groben Maßstab: WS_CONCRETE_REINFORCED_WATERTIGHT
Type - ID-Daten - Typenkommentare: Reinforced Concrete watertight; Typname: WS_SLB_CON_250_WT; WS_COMMENT_DIMENSION: h=25cm
Type - Materialien und Oberflächen - Tragendes Material: WS_CONCRETE_REINFORCED_WATERTIGHT
Type - Analytische Eigenschaften - Absorptionsgrad: 0.1; Rauigkeit: 1
Pset_QuantityTakeOff - Reference: WS_SLB_CON_250_WT; sets with these values: 2
Pset_SlabCommon - IsExternal: no; LoadBearing: yes; PitchAngle: 0 deg; Reference: WS_SLB_CON_250_WT
Sonstige - Familie: Geschossdecke; Familie und Typ: Geschossdecke: WS_SLB_CON_250_WT; Typ: WS_SLB_CON_250_WT; Typ-ID: 995882
Abhängigkeiten - Für Körper: no; Höhenversatz von Ebene: 0 m; Raumbegrenzung: yes
Bemaßungen - Dicke: 0.25 m; Kernstärke: 0.25 m
ID-Daten - Hat Verknüpfung: no; WS_COMMENT_MATERIAL: C25/30 WU; WS_TYPE_BUILDING_ELEMENT: F
Phasen - Phase erstellt: Phase 1
Tragwerk - Betonüberdeckung - Andere Flächen: Bewehrungsüberdeckung 1 <25 mm>; Betonüberdeckung - Obere Fläche: Bewehrungsüberdeckung 1 <25 mm>; Betonüberdeckung - Untere Fläche: Bewehrungsüberdeckung 1 <25 mm>; Tragwerk: yes
Text - WS_LEVEL: U1
Name (Geschossdecke:WS_SLB_CON_250_WT:...) | Ebene | Fläche (m2) | Höhe oben (m) = Höhe oben Kern (m) | Höhe unten (m) = Höhe unten Kern (m) | Höhe Vermessung oben (m) | Höhe Vermessung unten (m) | Umfang (m) | Volumen (m3) | WS_POSITIONNUMBER
3683003 | Dü_U01_OKBP_-1,22_RLT | 105.986 | -1.22 | -1.47 | 460.78 | 460.53 | 47.23 | 26.4964 | 004
3689124 | Dü_U01_OKRD_-0,12 | 206.253 | -0.12 | -0.37 | 461.88 | 461.63 | 65.5681 | 51.5633 | 005
4215301 | Dü_U01_OKRD_-0,12 | 91.8005 | -0.12 | -0.37 | 461.88 | 461.63 | 51.1699 | 22.9501 | 005
4216407 | Dü_U01_OKRD_-0,12 | 582.77 | -0.12 | -0.37 | 461.88 | 461.63 | 111.879 | 145.693 | 005

# IfcSlab: Geschossdecke:WS_SLB_CON_270_WT, Geschossdecke:WS_SLB_CON_270_WT:4425120
In: FB_U01_OKFB
Type - PredefinedType: FLOOR
Type - Sonstige - Kategorie: Geschossdecken; Familienname: Geschossdecke
Type - Konstruktion - Funktion: Innen; Standarddicke: 0.27 m
Type - Grafiken - Farbfüllung für groben Maßstab: 0; Füllmuster für groben Maßstab: WS_CONCRETE_REINFORCED_WATERTIGHT
Type - ID-Daten - Typenkommentare: Reinforced Concrete watertight; Typname: WS_SLB_CON_270_WT; WS_COMMENT_DIMENSION: h=27cm
Type - Materialien und Oberflächen - Tragendes Material: WS_CONCRETE_REINFORCED_WATERTIGHT
Type - Analytische Eigenschaften - Absorptionsgrad: 0.1; Rauigkeit: 1
Material: WS_CONCRETE_REINFORCED_WATERTIGHT
Pset_QuantityTakeOff - Reference: WS_SLB_CON_270_WT; sets with these values: 2
Pset_SlabCommon - IsExternal: no; LoadBearing: yes; PitchAngle: 0 deg; Reference: WS_SLB_CON_270_WT
Sonstige - Familie: Geschossdecke; Familie und Typ: Geschossdecke: WS_SLB_CON_270_WT; Typ: WS_SLB_CON_270_WT; Typ-ID: 4426496
Abhängigkeiten - Für Körper: no; Raumbegrenzung: yes; Ebene: Dü_U01_OKRD_-0,12; Höhenversatz von Ebene: -0.08 m
Bemaßungen - Dicke: 0.27 m; Fläche: 7.09679 m2; Höhe oben: -0.2 m; Höhe oben Kern: -0.2 m; Höhe unten: -0.47 m; Höhe unten Kern: -0.47 m; Höhe Vermessung oben: 461.8 m; Höhe Vermessung unten: 461.53 m; Kernstärke: 0.27 m; Umfang: 10.6701 m; Volumen: 1.47813 m3
ID-Daten - Hat Verknüpfung: no
Phasen - Phase erstellt: Phase 1
Tragwerk - Betonüberdeckung - Andere Flächen: Bewehrungsüberdeckung 1 <25 mm>; Betonüberdeckung - Obere Fläche: Bewehrungsüberdeckung 1 <25 mm>; Betonüberdeckung - Untere Fläche: Bewehrungsüberdeckung 1 <25 mm>; Tragwerk: yes

# IfcSlab: Geschossdecke:WS_SLB_CON_300, Geschossdecke:WS_SLB_CON_300:3699280
In: FB_E00_OKFB
Type - PredefinedType: FLOOR
Type - Sonstige - Kategorie: Geschossdecken; Familienname: Geschossdecke
Type - Konstruktion - Funktion: Innen; Standarddicke: 0.3 m
Type - Grafiken - Farbfüllung für groben Maßstab: 0; Füllmuster für groben Maßstab: WS_CONCRETE_REINFORCED
Type - ID-Daten - Typenkommentare: Reinforced Concrete; Typname: WS_SLB_CON_300; WS_COMMENT_DIMENSION: h=30cm
Type - Materialien und Oberflächen - Tragendes Material: WS_CONCRETE_REINFORCED
Type - Analytische Eigenschaften - Absorptionsgrad: 0.1; Rauigkeit: 1
Material: WS_CONCRETE_REINFORCED
Pset_QuantityTakeOff - Reference: WS_SLB_CON_300; sets with these values: 2
Pset_SlabCommon - IsExternal: no; LoadBearing: yes; PitchAngle: 0 deg; Reference: WS_SLB_CON_300
Sonstige - Familie: Geschossdecke; Familie und Typ: Geschossdecke: WS_SLB_CON_300; Typ: WS_SLB_CON_300; Typ-ID: 3698484
Abhängigkeiten - Für Körper: no; Höhenversatz von Ebene: 0 m; Raumbegrenzung: yes; Ebene: Dü_EG_OKRD_+4,15
Bemaßungen - Dicke: 0.3 m; Fläche: 117.081 m2; Höhe oben: 4.15 m; Höhe oben Kern: 4.15 m; Höhe unten: 3.85 m; Höhe unten Kern: 3.85 m; Höhe Vermessung oben: 466.15 m; Höhe Vermessung unten: 465.85 m; Kernstärke: 0.3 m; Umfang: 76.36 m; Volumen: 35.1144 m3
ID-Daten - Hat Verknüpfung: no; WS_COMMENT_MATERIAL: C25/30 RC; WS_POSITIONNUMBER: 006; WS_TYPE_BUILDING_ELEMENT: S
Phasen - Phase erstellt: Phase 1
Tragwerk - Betonüberdeckung - Andere Flächen: Bewehrungsüberdeckung 1 <25 mm>; Betonüberdeckung - Obere Fläche: Bewehrungsüberdeckung 1 <25 mm>; Betonüberdeckung - Untere Fläche: Bewehrungsüberdeckung 1 <25 mm>; Tragwerk: yes
Text - WS_LEVEL: 00

# IfcSlab: Geschossdecke:WS_SLB_CON_300_WT (2)
In: FB_U01_OKFB
Type - PredefinedType: FLOOR; Material: WS_CONCRETE_REINFORCED_WATERTIGHT 0.3 m
Type - Sonstige - Kategorie: Geschossdecken; Familienname: Geschossdecke
Type - Konstruktion - Funktion: Innen; Standarddicke: 0.3 m
Type - Grafiken - Farbfüllung für groben Maßstab: 0; Füllmuster für groben Maßstab: WS_CONCRETE_REINFORCED_WATERTIGHT
Type - ID-Daten - Typenkommentare: Reinforced Concrete watertight; Typname: WS_SLB_CON_300_WT; WS_COMMENT_DIMENSION: h=30cm
Type - Materialien und Oberflächen - Tragendes Material: WS_CONCRETE_REINFORCED_WATERTIGHT
Type - Analytische Eigenschaften - Absorptionsgrad: 0.1; Rauigkeit: 1
Pset_QuantityTakeOff - Reference: WS_SLB_CON_300_WT; sets with these values: 2
Pset_SlabCommon - IsExternal: no; LoadBearing: yes; Reference: WS_SLB_CON_300_WT
Sonstige - Familie: Geschossdecke; Familie und Typ: Geschossdecke: WS_SLB_CON_300_WT; Typ: WS_SLB_CON_300_WT; Typ-ID: 4153378
Abhängigkeiten - Für Körper: no; Raumbegrenzung: yes
Bemaßungen - Dicke: 0.3 m
ID-Daten - Hat Verknüpfung: no
Phasen - Phase erstellt: Phase 1
Tragwerk - Betonüberdeckung - Andere Flächen: Bewehrungsüberdeckung 1 <25 mm>; Betonüberdeckung - Obere Fläche: Bewehrungsüberdeckung 1 <25 mm>; Betonüberdeckung - Untere Fläche: Bewehrungsüberdeckung 1 <25 mm>; Tragwerk: yes
Name (Geschossdecke:WS_SLB_CON_300_WT:...) | PitchAngle (deg) | Höhenversatz von Ebene (m) | Ebene | Fläche (m2) | Umfang (m) | Volumen (m3)
3850799 | 0 | 0 | BP_UG1_OKBP_-3,87 | 184.915 | 63.0499 | 55.4745 | Bemaßungen - Höhe oben: -3.87 m; Höhe oben Kern: -3.87 m; Höhe unten: -4.17 m; Höhe unten Kern: -4.17 m; Höhe Vermessung oben: 458.13 m; Höhe Vermessung unten: 457.83 m; Kernstärke: 0.3 m; ID-Daten - WS_COMMENT_MATERIAL: C25/30 WU; WS_POSITIONNUMBER: 001; WS_TYPE_BUILDING_ELEMENT: F; Text - WS_LEVEL: FU
4346997 | 2.08079 | 0.2 | Dü_U01_OKBP_-1,77_Bodenkanal_M | 14.4883 | 45.85 | 4.34649

# IfcSlab: Geschossdecke:WS_SLB_CON_360, Geschossdecke:WS_SLB_CON_360:4439051
In: FB_E00_OKFB
Type - PredefinedType: FLOOR
Type - Sonstige - Kategorie: Geschossdecken; Familienname: Geschossdecke
Type - Konstruktion - Funktion: Innen; Standarddicke: 0.36 m
Type - Grafiken - Farbfüllung für groben Maßstab: 0; Füllmuster für groben Maßstab: WS_CONCRETE_REINFORCED
Type - ID-Daten - Typenkommentare: Reinforced Concrete; Typname: WS_SLB_CON_360; WS_COMMENT_DIMENSION: h=36cm
Type - Materialien und Oberflächen - Tragendes Material: WS_CONCRETE_REINFORCED
Type - Analytische Eigenschaften - Absorptionsgrad: 0.1; Rauigkeit: 1
Material: WS_CONCRETE_REINFORCED
Pset_QuantityTakeOff - Reference: WS_SLB_CON_360; sets with these values: 2
Pset_SlabCommon - IsExternal: no; LoadBearing: yes; PitchAngle: 0 deg; Reference: WS_SLB_CON_360
Sonstige - Familie: Geschossdecke; Familie und Typ: Geschossdecke: WS_SLB_CON_360; Typ: WS_SLB_CON_360; Typ-ID: 3877188
Abhängigkeiten - Für Körper: no; Raumbegrenzung: yes; Ebene: Dü_EG_OKRD_+4,15; Höhenversatz von Ebene: 0.06 m
Bemaßungen - Dicke: 0.36 m; Fläche: 5.72195 m2; Höhe oben: 4.21 m; Höhe oben Kern: 4.21 m; Höhe unten: 3.85 m; Höhe unten Kern: 3.85 m; Höhe Vermessung oben: 466.21 m; Höhe Vermessung unten: 465.85 m; Kernstärke: 0.36 m; Umfang: 18.1804 m; Volumen: 1.99713 m3
ID-Daten - Hat Verknüpfung: no; WS_COMMENT_MATERIAL: C25/30 RC; WS_POSITIONNUMBER: 007; WS_TYPE_BUILDING_ELEMENT: S
Phasen - Phase erstellt: Phase 1
Tragwerk - Betonüberdeckung - Andere Flächen: Bewehrungsüberdeckung 1 <25 mm>; Betonüberdeckung - Obere Fläche: Bewehrungsüberdeckung 1 <25 mm>; Betonüberdeckung - Untere Fläche: Bewehrungsüberdeckung 1 <25 mm>; Tragwerk: yes
Text - WS_LEVEL: 00

# IfcSlab: Geschossdecke:WS_SLB_CON_650, Geschossdecke:WS_SLB_CON_650:3855950
In: FB_U01_OKFB
Type - PredefinedType: FLOOR; Material: WS_CONCRETE_REINFORCED 0.65 m
Type - Sonstige - Kategorie: Geschossdecken; Familienname: Geschossdecke
Type - Konstruktion - Funktion: Innen; Standarddicke: 0.65 m
Type - Grafiken - Farbfüllung für groben Maßstab: 0; Füllmuster für groben Maßstab: WS_CONCRETE_REINFORCED
Type - ID-Daten - Typenkommentare: Reinforced Concrete; Typname: WS_SLB_CON_650; WS_COMMENT_DIMENSION: h=65cm
Type - Materialien und Oberflächen - Tragendes Material: WS_CONCRETE_REINFORCED
Type - Analytische Eigenschaften - Absorptionsgrad: 0.1; Rauigkeit: 1
Pset_QuantityTakeOff - Reference: WS_SLB_CON_650; sets with these values: 2
Pset_SlabCommon - IsExternal: no; LoadBearing: yes; PitchAngle: 0 deg; Reference: WS_SLB_CON_650
Sonstige - Familie: Geschossdecke; Familie und Typ: Geschossdecke: WS_SLB_CON_650; Typ: WS_SLB_CON_650; Typ-ID: 3815208
Abhängigkeiten - Für Körper: no; Höhenversatz von Ebene: 0 m; Raumbegrenzung: yes; Ebene: Dü_U01_OKRD_-0,12
Bemaßungen - Dicke: 0.65 m; Fläche: 3.35473 m2; Höhe oben: -0.12 m; Höhe oben Kern: -0.12 m; Höhe unten: -0.77 m; Höhe unten Kern: -0.77 m; Höhe Vermessung oben: 461.88 m; Höhe Vermessung unten: 461.23 m; Kernstärke: 0.65 m; Umfang: 8.98999 m; Volumen: 2.18057 m3
ID-Daten - Hat Verknüpfung: no; WS_COMMENT_MATERIAL: C25/30 RC; WS_POSITIONNUMBER: 003; WS_TYPE_BUILDING_ELEMENT: F
Phasen - Phase erstellt: Phase 1
Tragwerk - Betonüberdeckung - Andere Flächen: Bewehrungsüberdeckung 1 <25 mm>; Betonüberdeckung - Obere Fläche: Bewehrungsüberdeckung 1 <25 mm>; Betonüberdeckung - Untere Fläche: Bewehrungsüberdeckung 1 <25 mm>; Tragwerk: yes
Text - WS_LEVEL: U1

# IfcSlab: Geschossdecke:WS_SLB_CON_650_WT (3)
In: FB_U01_OKFB
Type - PredefinedType: FLOOR; Material: WS_CONCRETE_REINFORCED_WATERTIGHT 0.65 m
Type - Sonstige - Kategorie: Geschossdecken; Familienname: Geschossdecke
Type - Konstruktion - Funktion: Innen; Standarddicke: 0.65 m
Type - Grafiken - Farbfüllung für groben Maßstab: 0; Füllmuster für groben Maßstab: WS_CONCRETE_REINFORCED_WATERTIGHT
Type - ID-Daten - Typenkommentare: Reinforced Concrete; Typname: WS_SLB_CON_650_WT; WS_COMMENT_DIMENSION: h=65cm
Type - Materialien und Oberflächen - Tragendes Material: WS_CONCRETE_REINFORCED_WATERTIGHT
Type - Analytische Eigenschaften - Absorptionsgrad: 0.1; Rauigkeit: 1
Pset_QuantityTakeOff - Reference: WS_SLB_CON_650_WT; sets with these values: 2
Pset_SlabCommon - IsExternal: no; LoadBearing: yes; PitchAngle: 0 deg; Reference: WS_SLB_CON_650_WT
Sonstige - Familie: Geschossdecke; Familie und Typ: Geschossdecke: WS_SLB_CON_650_WT; Typ: WS_SLB_CON_650_WT; Typ-ID: 4042943
Abhängigkeiten - Für Körper: no; Höhenversatz von Ebene: 0 m; Raumbegrenzung: yes
Bemaßungen - Dicke: 0.65 m; Kernstärke: 0.65 m
ID-Daten - Hat Verknüpfung: no; WS_COMMENT_MATERIAL: C25/30 WU; WS_POSITIONNUMBER: 005; WS_TYPE_BUILDING_ELEMENT: F
Phasen - Phase erstellt: Phase 1
Tragwerk - Betonüberdeckung - Andere Flächen: Bewehrungsüberdeckung 1 <25 mm>; Betonüberdeckung - Obere Fläche: Bewehrungsüberdeckung 1 <25 mm>; Betonüberdeckung - Untere Fläche: Bewehrungsüberdeckung 1 <25 mm>; Tragwerk: yes
Text - WS_LEVEL: U1
Name (Geschossdecke:WS_SLB_CON_650_WT:...) | Ebene | Fläche (m2) | Höhe oben (m) = Höhe oben Kern (m) | Höhe unten (m) = Höhe unten Kern (m) | Höhe Vermessung oben (m) | Höhe Vermessung unten (m) | Umfang (m) | Volumen (m3)
3694142 | Dü_U01_OKBP_-1,40_Unterfahrt | 5.4 | -1.4 | -2.05 | 460.6 | 459.95 | 9.3 | 3.51
3815205 | Dü_U01_OKRD_-0,12 | 64.286 | -0.12 | -0.77 | 461.88 | 461.23 | 44.611 | 41.7859
3818305 | Dü_U01_OKRD_-0,12 | 56.6879 | -0.12 | -0.77 | 461.88 | 461.23 | 48.2101 | 36.8471

# IfcSlab: Geschossdecke:WS_SLB_TIM_100, Geschossdecke:WS_SLB_TIM_100:3738560
In: FB_E00_OKFB
Type - PredefinedType: FLOOR; Material: WS_TIMBER_GLT_0° 0.1 m
Type - Sonstige - Kategorie: Geschossdecken; Familienname: Geschossdecke
Type - Konstruktion - Funktion: Innen; Standarddicke: 0.1 m
Type - Grafiken - Farbfüllung für groben Maßstab: 0; Füllmuster für groben Maßstab: WS_TIMBER_GLT_90°
Type - ID-Daten - Typenkommentare: Timber; Typname: WS_SLB_TIM_100; WS_COMMENT_DIMENSION: BSP-Decke; CLT 100 L3s
Type - Materialien und Oberflächen - Tragendes Material: WS_TIMBER_GLT_0°
Type - Analytische Eigenschaften - Absorptionsgrad: 0.1; Rauigkeit: 1
Pset_QuantityTakeOff - Reference: WS_SLB_TIM_100; sets with these values: 2
Pset_SlabCommon - IsExternal: no; LoadBearing: yes; PitchAngle: 0 deg; Reference: WS_SLB_TIM_100
Sonstige - Familie: Geschossdecke; Familie und Typ: Geschossdecke: WS_SLB_TIM_100; Typ: WS_SLB_TIM_100; Typ-ID: 3738563
Abhängigkeiten - Für Körper: no; Höhenversatz von Ebene: 0 m; Raumbegrenzung: yes; Ebene: Dü_EG_OKHD_+4,035_Foyer 1
Bemaßungen - Dicke: 0.1 m; Fläche: 405.96 m2; Höhe oben: 4.035 m; Höhe oben Kern: 4.035 m; Höhe unten: 3.935 m; Höhe unten Kern: 3.935 m; Höhe Vermessung oben: 466.035 m; Höhe Vermessung unten: 465.935 m; Kernstärke: 0.1 m; Umfang: 121.55 m; Volumen: 40.596 m3
ID-Daten - Hat Verknüpfung: no; WS_COMMENT_MATERIAL: CLT 100 L3s; C24; WS_POSITIONNUMBER: 020; WS_TYPE_BUILDING_ELEMENT: S
Phasen - Phase erstellt: Phase 1
Tragwerk - Betonüberdeckung - Andere Flächen: Bewehrungsüberdeckung 1 <25 mm>; Betonüberdeckung - Obere Fläche: Bewehrungsüberdeckung 1 <25 mm>; Betonüberdeckung - Untere Fläche: Bewehrungsüberdeckung 1 <25 mm>; Tragwerk: yes
Text - WS_LEVEL: 00

# IfcSlab: Geschossdecke:WS_SLB_TIM_25, Geschossdecke:WS_SLB_TIM_25:3915004
In: FB_E00_OKFB
Type - PredefinedType: FLOOR; Material: WS_TIMBER_GLT_90° 0.025 m
Type - Sonstige - Kategorie: Geschossdecken; Familienname: Geschossdecke
Type - Konstruktion - Funktion: Innen; Standarddicke: 0.025 m
Type - Grafiken - Farbfüllung für groben Maßstab: 0; Füllmuster für groben Maßstab: WS_TIMBER_GLT_90°
Type - ID-Daten - Typenkommentare: Timber; Typname: WS_SLB_TIM_25; WS_COMMENT_DIMENSION: OSB 4 h=25mm
Type - Materialien und Oberflächen - Tragendes Material: WS_TIMBER_GLT_90°
Type - Analytische Eigenschaften - Absorptionsgrad: 0.1; Rauigkeit: 1
Pset_QuantityTakeOff - Reference: WS_SLB_TIM_25; sets with these values: 2
Pset_SlabCommon - IsExternal: no; LoadBearing: yes; PitchAngle: 0 deg; Reference: WS_SLB_TIM_25
Sonstige - Familie: Geschossdecke; Familie und Typ: Geschossdecke: WS_SLB_TIM_25; Typ: WS_SLB_TIM_25; Typ-ID: 3737491
Abhängigkeiten - Für Körper: no; Höhenversatz von Ebene: 0 m; Raumbegrenzung: yes; Ebene: Dü_OG1_OKHD_+8,065
Bemaßungen - Dicke: 0.025 m; Fläche: 653.475 m2; Höhe oben: 8.065 m; Höhe oben Kern: 8.065 m; Höhe unten: 8.04 m; Höhe unten Kern: 8.04 m; Höhe Vermessung oben: 470.065 m; Höhe Vermessung unten: 470.04 m; Kernstärke: 0.025 m; Umfang: 115.66 m; Volumen: 16.3369 m3
ID-Daten - Hat Verknüpfung: no; WS_COMMENT_MATERIAL: OSB 4; WS_POSITIONNUMBER: 001; WS_TYPE_BUILDING_ELEMENT: S
Phasen - Phase erstellt: Phase 1
Tragwerk - Betonüberdeckung - Andere Flächen: Bewehrungsüberdeckung 1 <25 mm>; Betonüberdeckung - Obere Fläche: Bewehrungsüberdeckung 1 <25 mm>; Betonüberdeckung - Untere Fläche: Bewehrungsüberdeckung 1 <25 mm>; Tragwerk: yes
Text - WS_LEVEL: 01

# IfcSlab: Geschossdecke:WS_SLB_TIM_60, Geschossdecke:WS_SLB_TIM_60:3737488
In: FB_E00_OKFB
Type - PredefinedType: FLOOR; Material: WS_TIMBER_GLT_0° 0.06 m
Type - Sonstige - Kategorie: Geschossdecken; Familienname: Geschossdecke
Type - Konstruktion - Funktion: Innen; Standarddicke: 0.06 m
Type - Grafiken - Farbfüllung für groben Maßstab: 0; Füllmuster für groben Maßstab: WS_TIMBER_GLT_90°
Type - ID-Daten - Typenkommentare: Timber; Typname: WS_SLB_TIM_60; WS_COMMENT_DIMENSION: BSP-Decke; CLT 60 L3s
Type - Materialien und Oberflächen - Tragendes Material: WS_TIMBER_GLT_0°
Type - Analytische Eigenschaften - Absorptionsgrad: 0.1; Rauigkeit: 1
Pset_QuantityTakeOff - Reference: WS_SLB_TIM_60; sets with these values: 2
Pset_SlabCommon - IsExternal: no; LoadBearing: yes; PitchAngle: 0 deg; Reference: WS_SLB_TIM_60
Sonstige - Familie: Geschossdecke; Familie und Typ: Geschossdecke: WS_SLB_TIM_60; Typ: WS_SLB_TIM_60; Typ-ID: 3915428
Abhängigkeiten - Für Körper: no; Höhenversatz von Ebene: 0 m; Raumbegrenzung: yes; Ebene: Dü_OG1_OKHD_+8,065
Bemaßungen - Dicke: 0.06 m; Fläche: 149.33 m2; Höhe oben: 8.065 m; Höhe oben Kern: 8.065 m; Höhe unten: 8.005 m; Höhe unten Kern: 8.005 m; Höhe Vermessung oben: 470.065 m; Höhe Vermessung unten: 470.005 m; Kernstärke: 0.06 m; Umfang: 59.2701 m; Volumen: 8.95977 m3
ID-Daten - Hat Verknüpfung: no; WS_COMMENT_MATERIAL: CLT 60 L3s; C24; WS_POSITIONNUMBER: 002; WS_TYPE_BUILDING_ELEMENT: S
Phasen - Phase erstellt: Phase 1
Tragwerk - Betonüberdeckung - Andere Flächen: Bewehrungsüberdeckung 1 <25 mm>; Betonüberdeckung - Obere Fläche: Bewehrungsüberdeckung 1 <25 mm>; Betonüberdeckung - Untere Fläche: Bewehrungsüberdeckung 1 <25 mm>; Tragwerk: yes
Text - WS_LEVEL: 01

# IfcSlab: Geschossdecke:WS_SLB_TIM_90, Geschossdecke:WS_SLB_TIM_90:3741551
In: FB_E00_OKFB
Type - PredefinedType: FLOOR; Material: WS_TIMBER_GLT_0° 0.09 m
Type - Sonstige - Kategorie: Geschossdecken; Familienname: Geschossdecke
Type - Konstruktion - Funktion: Innen; Standarddicke: 0.09 m
Type - Grafiken - Farbfüllung für groben Maßstab: 0; Füllmuster für groben Maßstab: WS_TIMBER_GLT_90°
Type - ID-Daten - Typenkommentare: Timber; Typname: WS_SLB_TIM_90; WS_COMMENT_DIMENSION: BSP-Decke; CLT 90 L3s
Type - Materialien und Oberflächen - Tragendes Material: WS_TIMBER_GLT_0°
Type - Analytische Eigenschaften - Absorptionsgrad: 0.1; Rauigkeit: 1
Pset_QuantityTakeOff - Reference: WS_SLB_TIM_90; sets with these values: 2
Pset_SlabCommon - IsExternal: no; LoadBearing: yes; PitchAngle: 0 deg; Reference: WS_SLB_TIM_90
Sonstige - Familie: Geschossdecke; Familie und Typ: Geschossdecke: WS_SLB_TIM_90; Typ: WS_SLB_TIM_90; Typ-ID: 3911040
Abhängigkeiten - Für Körper: no; Höhenversatz von Ebene: 0 m; Raumbegrenzung: yes; Ebene: Dü_EG_OKHD_+3,985_Foyer 2
Bemaßungen - Dicke: 0.09 m; Fläche: 109.255 m2; Höhe oben: 3.985 m; Höhe oben Kern: 3.985 m; Höhe unten: 3.895 m; Höhe unten Kern: 3.895 m; Höhe Vermessung oben: 465.985 m; Höhe Vermessung unten: 465.895 m; Kernstärke: 0.09 m; Umfang: 49.6999 m; Volumen: 9.83296 m3
ID-Daten - Hat Verknüpfung: no; WS_BUILDING_PART: 00; WS_COMMENT_MATERIAL: CLT 90 L3s; C24; WS_POSITIONNUMBER: 001; WS_TYPE_BUILDING_ELEMENT: S
Phasen - Phase erstellt: Phase 1
Tragwerk - Betonüberdeckung - Andere Flächen: Bewehrungsüberdeckung 1 <25 mm>; Betonüberdeckung - Obere Fläche: Bewehrungsüberdeckung 1 <25 mm>; Betonüberdeckung - Untere Fläche: Bewehrungsüberdeckung 1 <25 mm>; Tragwerk: yes
Text - WS_LEVEL: 00

# IfcSlab: Ortbetontreppe:Ortbetontreppe, Ortbetontreppe:Ortbetontreppe:4336291
In: FB_E00_OKFB
Type - PredefinedType: FLOOR; Material: WS_CONCRETE_REINFORCED
Type - Sonstige - Kategorie: Geschossdecken; Familienname: Ortbetontreppe
Type - ID-Daten - Typname: Ortbetontreppe
Type - Materialien und Oberflächen - Tragendes Material: WS_CONCRETE_REINFORCED
Pset_QuantityTakeOff - Reference: Ortbetontreppe; sets with these values: 2
Pset_SlabCommon - IsExternal: no; Reference: Ortbetontreppe
Sonstige - Familie: Ortbetontreppe; Familie und Typ: Ortbetontreppe: Ortbetontreppe; Typ: Ortbetontreppe; Typ-ID: 4336289
Abhängigkeiten - Raumbegrenzung: yes; Verschieben mit umliegenden Elementen: no; Höhe von Ebene: 0 m; Ebene: Dü_EG_OKRD_+5,12
Bemaßungen - Fläche: 3.51012 m2; Volumen: 7.19575 m3
Phasen - Phase erstellt: Phase 1
Tragwerk - Betonüberdeckung: Bewehrungsüberdeckung 1 <25 mm>

# IfcSlab: Treppe1:Treppe1, Treppe1:Treppe1:4755983
In: FB_U01_OKFB
Type - PredefinedType: FLOOR; Material: WS_CONCRETE_REINFORCED_PRECAST
Type - Sonstige - Kategorie: Geschossdecken; Familienname: Treppe1
Type - ID-Daten - Typname: Treppe1
Pset_QuantityTakeOff - Reference: Treppe1; sets with these values: 2
Pset_SlabCommon - IsExternal: no; Reference: Treppe1
Sonstige - Familie: Treppe1; Familie und Typ: Treppe1: Treppe1; Typ: Treppe1; Typ-ID: 4755981
Abhängigkeiten - Raumbegrenzung: yes; Verschieben mit umliegenden Elementen: no; Höhe von Ebene: 0 m; Ebene: Dü_U01_OKBP_-1,77_Bodenkanal_M
Bemaßungen - Fläche: 1.16139 m2; Volumen: 1.5011 m3
Phasen - Phase erstellt: Phase 1
Tragwerk - Betonüberdeckung: Bewehrungsüberdeckung 1 <25 mm>

# IfcSlab: Treppe:Treppe, Treppe:Treppe:4752891
In: FB_E00_OKFB
Type - PredefinedType: FLOOR; Material: WS_CONCRETE_REINFORCED_PRECAST
Type - Sonstige - Kategorie: Geschossdecken; Familienname: Treppe
Type - ID-Daten - Typname: Treppe
Pset_QuantityTakeOff - Reference: Treppe; sets with these values: 2
Pset_SlabCommon - IsExternal: no; Reference: Treppe
Sonstige - Familie: Treppe; Familie und Typ: Treppe: Treppe; Typ: Treppe; Typ-ID: 4752889
Abhängigkeiten - Raumbegrenzung: yes; Verschieben mit umliegenden Elementen: no; Höhe von Ebene: 0 m; Ebene: FB_E00_OKFB
Bemaßungen - Fläche: 1.10036 m2; Volumen: 1.42222 m3
Phasen - Phase erstellt: Phase 1
Tragwerk - Betonüberdeckung: Bewehrungsüberdeckung 1 <25 mm>

# IfcSlab: WS_FDN_PAD:FDN_PAD_1600x3000x650_WT (2)
In: FB_U01_OKFB
Type - PredefinedType: BASESLAB; Material: WS_CONCRETE_REINFORCED_WATERTIGHT
Type - Sonstige - Kategorie: Fundamente; Familienname: WS_FDN_PAD
Type - Bemaßungen - Breite: 1.6 m; Fundamentstärke: 0.65 m; Länge: 3 m; WS_HEIGHT: 0.65 m; WS_LENGTH: 3 m; WS_WIDTH: 1.6 m
Type - ID-Daten - Typname: FDN_PAD_1600x3000x650_WT; WS_COMMENT_DIMENSION: h=65cm
Type - Materialien und Oberflächen - Tragendes Material: WS_CONCRETE_REINFORCED_WATERTIGHT
Pset_QuantityTakeOff - Reference: FDN_PAD_1600x3000x650_WT; sets with these values: 2
Pset_SlabCommon - IsExternal: no; Reference: FDN_PAD_1600x3000x650_WT
Sonstige - Familie: WS_FDN_PAD; Familie und Typ: WS_FDN_PAD: FDN_PAD_1600x3000x650_WT; Typ: FDN_PAD_1600x3000x650_WT; Typ-ID: 3642462; WS_LENGTH+ex: 3.3 m; WS_WIDTH+ey: 1.8 m
Abhängigkeiten - Höhenversatz von Ebene: 0 m; Ebene: Dü_U01_OKRD_-0,12; Verschieben mit Raster: yes; Basisbauteil: Ebene : Dü_U01_OKRD_-0,12; ex: 0.3 m; ey: 0.2 m
Bemaßungen - Höhe oben: -0.12 m; Höhe unten: -0.77 m; Höhe Vermessung oben: 461.88 m; Höhe Vermessung unten: 461.23 m
ID-Daten - Hat Verknüpfung: no; WS_COMMENT_MATERIAL: C25/30 WU; WS_POSITIONNUMBER: 005; WS_TYPE_BUILDING_ELEMENT: F
Phasen - Phase erstellt: Phase 1
Tragwerk - Betonüberdeckung - Untere Fläche: Bewehrungsüberdeckung 1 <25 mm>
Text - WS_LEVEL: U1
Name (WS_FDN_PAD:FDN_PAD_1600x3000x650_WT:...) | Fläche (m2) | Volumen (m3)
3927257 | 4.56794 | 1.82717 | Pset_SlabCommon - PitchAngle: 0 deg
3928167 | 4.8 | 1.92

# IfcStair: Treppen 1:Treppen 1 (2)
In: FB_U01_OKFB
Type - Sonstige - Kategorie: Treppen; Familienname: Treppen 1
Type - ID-Daten - Typname: Treppen 1
Name (Treppen 1:Treppen 1:...)
4406342 | Material: WS_CONCRETE_REINFORCED_PRECAST
4406342 | Pset_QuantityTakeOff - Reference: Treppen 1; Pset_StairCommon - IsExternal: no; Reference: Treppen 1; Sonstige - Familie: Treppen 1; Familie und Typ: Treppen 1: Treppen 1; Typ: Treppen 1; Typ-ID: 4406340; Abhängigkeiten - Verschieben mit umliegenden Elementen: no; Höhe von Ebene: 0 m; Bemaßungen - Fläche: 0.602676 m2; Volumen: 1.0818 m3; Phasen - Phase erstellt: Phase 1; Tragwerk - Betonüberdeckung: Bewehrungsüberdeckung 1 <25 mm>

# IfcWall: Basiswand:WS_WAL_CON_250 (10)
Type - PredefinedType: STANDARD; Material: WS_CONCRETE_REINFORCED 0.25 m
Type - Sonstige - Kategorie: Wände; Familienname: Basiswand
Type - Konstruktion - Abschluss an Öffnungen: Keine; Abschluss an Wänden: Außen; Funktion: Außen; Breite: 0.25 m
Type - Grafiken - Farbfüllung für groben Maßstab: 8421504; Füllmuster für groben Maßstab: WS_CONCRETE
Type - ID-Daten - Beschreibung: Exterior or Interior wall; Typenkommentare: Concrete unreinforced; Typname: WS_WAL_CON_250; WS_COMMENT_DIMENSION: t=25cm
Type - Materialien und Oberflächen - Tragendes Material: WS_CONCRETE_REINFORCED
Type - Analytische Eigenschaften - Absorptionsgrad: 0.1; Rauigkeit: 1
Pset_QuantityTakeOff - Reference: WS_WAL_CON_250; sets with these values: 2
Pset_WallCommon - LoadBearing: yes; IsExternal: yes; Reference: WS_WAL_CON_250
Sonstige - Familie: Basiswand; Familie und Typ: Basiswand: WS_WAL_CON_250; Typ: WS_WAL_CON_250; Typ-ID: 329296
Abhängigkeiten - Für Körper: no; Basislinie: Tragende Schicht: Innenkante; Raumbegrenzung: yes; Unterkante ist fixiert: no; Verlängerungsabstand oben: 0 m; Verlängerungsabstand unten: 0 m; Versatz unten: 0 m
ID-Daten - Hat Verknüpfung: no; WS_COMMENT_MATERIAL: C25/30 RC; WS_TYPE_BUILDING_ELEMENT: W
Phasen - Phase erstellt: Phase 1
Tragwerk - Betonüberdeckung - Andere Flächen: Bewehrungsüberdeckung 1 <25 mm>; Tragwerk: yes; Betonüberdeckung - Außenfläche: Bewehrungsüberdeckung 1 <25 mm>; Betonüberdeckung - Innenfläche: Bewehrungsüberdeckung 1 <25 mm>; Tragwerksverwendung: Tragend
Querschnittsdefinition - Querschnitt: Vertikal
Name (Basiswand:WS_WAL_CON_250:...) | In | ExtendToStructure = Oberkante ist fixiert. | Versatz oben (m) | Abhängigkeit unten | Abhängigkeit oben | Nicht verknüpfte Höhe (m) | Fläche (m2) | Länge (m) | Volumen (m3) | WS_POSITIONNUMBER | WS_LEVEL
3674163 | FB_U01_OKFB | yes | 0 | Dü_U01_OKRD_-0,12 | Bis Ebene: Dü_EG_UKRD_+3,38 | 3.5 | 7.99625 | 2.55 | 1.99906 | 009.1 | 00
3674526 | FB_U01_OKFB | yes | 0 | Dü_U01_OKRD_-0,12 | Bis Ebene: Dü_EG_UKRD_+3,38 | 3.5 | 7.82125 | 2.55 | 1.95531 | 009.3 | 00
3675524 | FB_U01_OKFB | no | 0 | Dü_U01_OKRD_-0,12 | Bis Ebene: Dü_EG_UKRD1_+3,735 | 3.855 | 4.93403 | 2 | 1.2335 | 005.2 | 00
3676612 | FB_U01_OKFB | no | 0 | Dü_U01_OKRD_-0,12 | Bis Ebene: Dü_EG_UKRD_+3,85 | 3.97 | 11.1669 | 3.0251 | 2.79172 | 015 | 00
3677343 | FB_U01_OKFB | no | 0 | Dü_U01_OKRD_-0,12 | Bis Ebene: Dü_EG_UKRD_+4,15 | 4.27 | 27.256 | 10 | 6.81399 | 014 | 00
3680817 | FB_U01_OKFB | no | 0 | Dü_U01_OKRD_-0,12 | Bis Ebene: Dü_EG_UKRD_+3,785 | 3.905 | 4.1759 | 1.95 | 1.04397 | 010.5 | 00
3712653 | FB_E00_OKFB | no | 0.1 | Dü_EG_OKRD_+3,98 | Bis Ebene: Dü_OG1_UKRD_+7,815 | 3.935 | 3.90681 | 2 | 0.976701 | 006.2 | 01
3734379 | FB_E00_OKFB | no | 0 | Dü_EG_OKRD_+3,98 | Bis Ebene: Dü_OG1_OKHT_+8,005_Träger OG | 4.025 | 2.85356 | 0.834343 | 0.71339 | 006.1 | 01
4174075 | FB_U01_OKFB | no | -0.2 | Dü_U01_OKRD_-0,12 | Bis Ebene: Dü_EG_OKRD_+5,12 | 5.04 | 2.57012 | 0.740096 | 0.642529 | 016.4 | 00
4312363 | FB_U01_OKFB | no | -0.2 | Dü_U01_OKRD_-0,12 | Bis Ebene: Dü_EG_OKRD_+5,12 | 5.04 | 28.8912 | 5.625 | 7.22281 | 016.1 | 00

# IfcWall: Basiswand:WS_WAL_CON_250_WT, Basiswand:WS_WAL_CON_250_WT:3665463
In: FB_U01_OKFB
Type - PredefinedType: STANDARD; Material: WS_CONCRETE_REINFORCED_WATERTIGHT 0.25 m
Type - Sonstige - Kategorie: Wände; Familienname: Basiswand
Type - Konstruktion - Abschluss an Öffnungen: Keine; Abschluss an Wänden: Außen; Breite: 0.25 m; Funktion: Außen
Type - Grafiken - Füllmuster für groben Maßstab: WS_CONCRETE_REINFORCED_WATERTIGHT; Farbfüllung für groben Maßstab: 8421504
Type - ID-Daten - Beschreibung: Exterior or Interior wall; Typenkommentare: Concrete reinforced watertight; Typname: WS_WAL_CON_250_WT; WS_COMMENT_DIMENSION: t=25cm
Type - Materialien und Oberflächen - Tragendes Material: WS_CONCRETE_REINFORCED_WATERTIGHT
Type - Analytische Eigenschaften - Absorptionsgrad: 0.1; Rauigkeit: 1
Pset_QuantityTakeOff - Reference: WS_WAL_CON_250_WT; sets with these values: 2
Pset_WallCommon - LoadBearing: yes; Reference: WS_WAL_CON_250_WT; IsExternal: yes; ExtendToStructure: no
Sonstige - Familie: Basiswand; Familie und Typ: Basiswand: WS_WAL_CON_250_WT; Typ: WS_WAL_CON_250_WT; Typ-ID: 995991
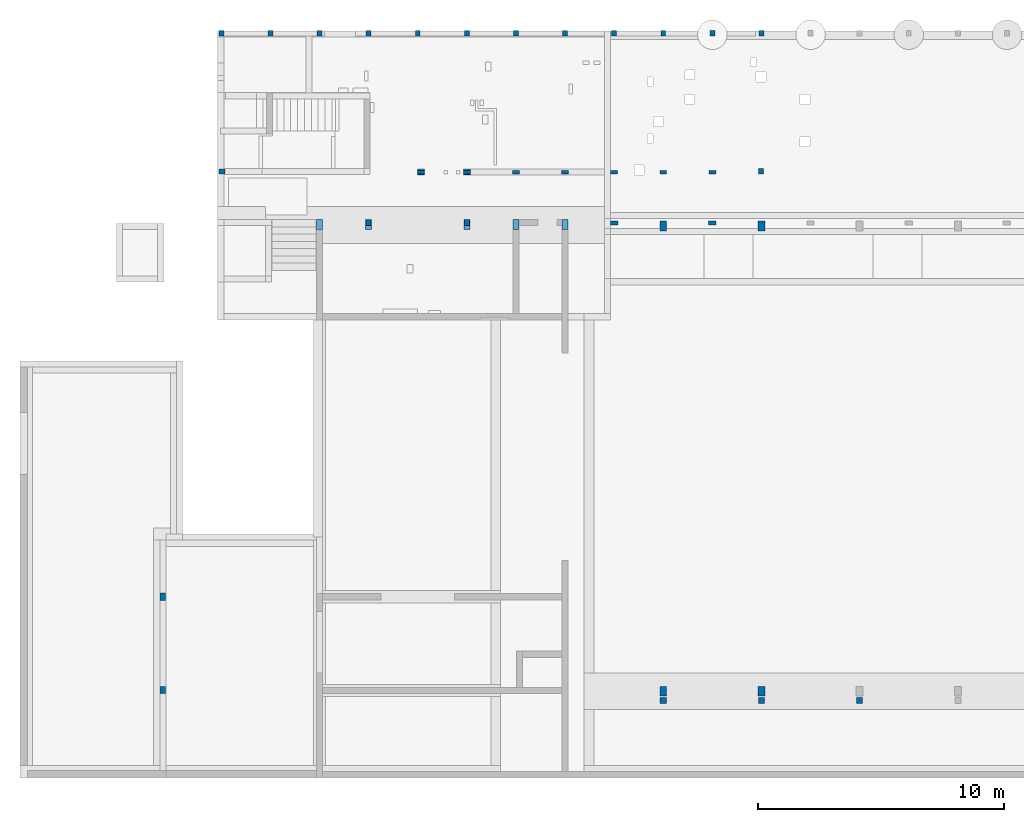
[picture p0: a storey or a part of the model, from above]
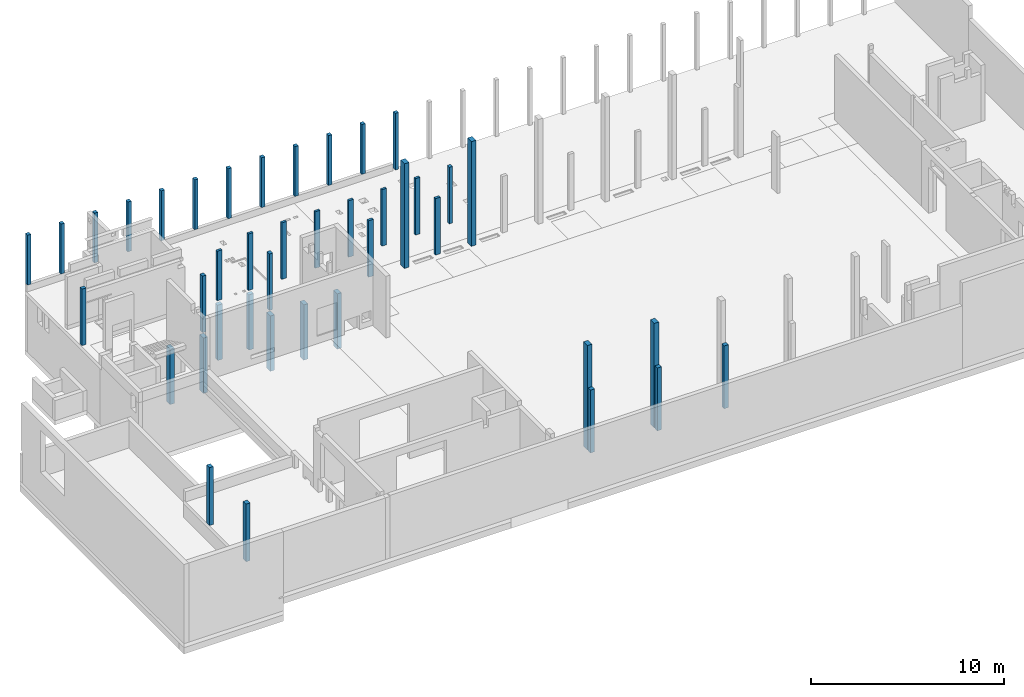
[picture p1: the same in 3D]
Properties of the parts of a building model (IFC2X3), part 6 of 6

# IfcWall: Basiswand:WS_WAL_CON_250_WT, Basiswand:WS_WAL_CON_250_WT:3665463
Abhängigkeiten - Für Körper: no; Abhängigkeit unten: BP_UG1_OKBP_-3,87; Basislinie: Tragende Schicht: Innenkante; Oberkante ist fixiert.: no; Raumbegrenzung: yes; Unterkante ist fixiert: no; Verlängerungsabstand oben: 0 m; Verlängerungsabstand unten: 0 m; Versatz oben: 0 m; Versatz unten: 0 m; Abhängigkeit oben: Bis Ebene: Dü_U01_OKRD_-0,12; Nicht verknüpfte Höhe: 3.75 m
Bemaßungen - Fläche: 54.6773 m2; Länge: 15.75 m; Volumen: 13.6693 m3
ID-Daten - Hat Verknüpfung: no; WS_COMMENT_MATERIAL: C25/30 WU; WS_POSITIONNUMBER: 102; WS_TYPE_BUILDING_ELEMENT: W
Phasen - Phase erstellt: Phase 1
Tragwerk - Betonüberdeckung - Andere Flächen: Bewehrungsüberdeckung 1 <25 mm>; Tragwerk: yes; Betonüberdeckung - Außenfläche: Bewehrungsüberdeckung 1 <25 mm>; Betonüberdeckung - Innenfläche: Bewehrungsüberdeckung 1 <25 mm>; Tragwerksverwendung: Tragend
Text - WS_LEVEL: U1
Querschnittsdefinition - Querschnitt: Vertikal

# IfcWall: Basiswand:WS_WAL_CON_300_WT, Basiswand:WS_WAL_CON_300_WT:3849443
In: FB_U01_OKFB
Type - PredefinedType: STANDARD; Material: WS_CONCRETE_REINFORCED_WATERTIGHT 0.3 m
Type - Sonstige - Kategorie: Wände; Familienname: Basiswand
Type - Konstruktion - Abschluss an Öffnungen: Keine; Abschluss an Wänden: Außen; Funktion: Außen; Breite: 0.3 m
Type - Grafiken - Füllmuster für groben Maßstab: <Flächenfüllung>; Farbfüllung für groben Maßstab: 8421504
Type - ID-Daten - Beschreibung: Stahlbeton 30 WU; Typenkommentare: Stahlbeton WU; Typname: WS_WAL_CON_300_WT; WS_COMMENT_DIMENSION: t=30cm
Type - Materialien und Oberflächen - Tragendes Material: WS_CONCRETE_REINFORCED_WATERTIGHT
Type - Analytische Eigenschaften - Absorptionsgrad: 0.1; Rauigkeit: 1
Pset_QuantityTakeOff - Reference: WS_WAL_CON_300_WT; sets with these values: 2
Pset_WallCommon - LoadBearing: yes; IsExternal: yes; ExtendToStructure: no; Reference: WS_WAL_CON_300_WT
Sonstige - Familie: Basiswand; Familie und Typ: Basiswand: WS_WAL_CON_300_WT; Typ: WS_WAL_CON_300_WT; Typ-ID: 745411
Abhängigkeiten - Für Körper: no; Basislinie: Tragende Schicht: Innenkante; Oberkante ist fixiert.: no; Raumbegrenzung: yes; Unterkante ist fixiert: no; Verlängerungsabstand oben: 0 m; Verlängerungsabstand unten: 0 m; Versatz oben: 0 m; Versatz unten: 0 m; Abhängigkeit oben: Bis Ebene: Dü_EG_UKRD_+3,785; Abhängigkeit unten: Dü_U01_OKBP_-1,22_RLT; Nicht verknüpfte Höhe: 5.005 m
Bemaßungen - Fläche: 77.4183 m2; Länge: 16.715 m; Volumen: 23.2255 m3
ID-Daten - Hat Verknüpfung: no; WS_COMMENT_MATERIAL: C25/30 WU; WS_POSITIONNUMBER: 101; WS_TYPE_BUILDING_ELEMENT: W
Phasen - Phase erstellt: Phase 1
Tragwerk - Betonüberdeckung - Andere Flächen: Bewehrungsüberdeckung 1 <25 mm>; Tragwerk: yes; Betonüberdeckung - Außenfläche: Bewehrungsüberdeckung 1 <25 mm>; Betonüberdeckung - Innenfläche: Bewehrungsüberdeckung 1 <25 mm>; Tragwerksverwendung: Tragend
Text - WS_LEVEL: 00
Querschnittsdefinition - Querschnitt: Vertikal

# IfcWall: Basiswand:WS_WAL_MAS_240 (3)
In: FB_U01_OKFB
Type - PredefinedType: STANDARD; Material: WS_MASONRY 0.24 m
Type - Sonstige - Kategorie: Wände; Familienname: Basiswand
Type - Konstruktion - Abschluss an Öffnungen: Keine; Abschluss an Wänden: Außen; Funktion: Außen; Breite: 0.24 m
Type - Grafiken - Füllmuster für groben Maßstab: <Flächenfüllung>; Farbfüllung für groben Maßstab: 8421504
Type - ID-Daten - Typenkommentare: Mauerwerk_Ausbau; Typname: WS_WAL_MAS_240; WS_COMMENT_DIMENSION: t=24cm
Type - Materialien und Oberflächen - Tragendes Material: WS_MASONRY
Type - Analytische Eigenschaften - Absorptionsgrad: 0.1; Rauigkeit: 1
Pset_QuantityTakeOff - Reference: WS_WAL_MAS_240; sets with these values: 2
Pset_WallCommon - LoadBearing: yes; IsExternal: yes; ExtendToStructure: no; Reference: WS_WAL_MAS_240
Sonstige - Familie: Basiswand; Familie und Typ: Basiswand: WS_WAL_MAS_240; Typ: WS_WAL_MAS_240; Typ-ID: 3204820
Abhängigkeiten - Für Körper: no; Basislinie: Tragende Schicht: Innenkante; Oberkante ist fixiert.: no; Raumbegrenzung: yes; Unterkante ist fixiert: no; Verlängerungsabstand oben: 0 m; Verlängerungsabstand unten: 0 m; Abhängigkeit unten: Dü_U01_OKRD_-0,12; Abhängigkeit oben: Bis Ebene: Dü_EG_OKHT_+3,935_Foyer 1; Versatz unten: 0.25 m
ID-Daten - Hat Verknüpfung: no; WS_COMMENT_MATERIAL: KS 20-2,0 M2,5; WS_TYPE_BUILDING_ELEMENT: W
Phasen - Phase erstellt: Phase 1
Tragwerk - Betonüberdeckung - Andere Flächen: Bewehrungsüberdeckung 1 <25 mm>; Tragwerk: yes; Betonüberdeckung - Außenfläche: Bewehrungsüberdeckung 1 <25 mm>; Betonüberdeckung - Innenfläche: Bewehrungsüberdeckung 1 <25 mm>; Tragwerksverwendung: Tragend
Text - WS_LEVEL: 00
Querschnittsdefinition - Querschnitt: Vertikal
Name (Basiswand:WS_WAL_MAS_240:...) | Nicht verknüpfte Höhe (m) | Versatz oben (m) | Fläche (m2) | Länge (m) | Volumen (m3) | WS_POSITIONNUMBER
3798993 | 3.795 | -0.01 | 13.7499 | 3.965 | 3.29998 | 020.1
3799543 | 3.79 | -0.015 | 6.54883 | 1.9899 | 1.57172 | 020.5
3799918 | 3.79 | -0.015 | 17.3002 | 5.9099 | 4.15204 | 020.3

# IfcWallStandardCase: Basiswand:WS_WAL_CON_100_PC (3)
In: FB_E00_OKFB
Type - PredefinedType: STANDARD; Material: WS_CONCRETE_REINFORCED_PRECAST 0.1 m
Type - Sonstige - Kategorie: Wände; Familienname: Basiswand
Type - Konstruktion - Abschluss an Öffnungen: Keine; Abschluss an Wänden: Außen; Funktion: Außen; Breite: 0.1 m
Type - Grafiken - Farbfüllung für groben Maßstab: 8421504; Füllmuster für groben Maßstab: WS_CONCRETE_REINFORCED_PRECAST
Type - ID-Daten - Beschreibung: Exterior or Interior wall; Typenkommentare: Concrete precast; Typname: WS_WAL_CON_100_PC; WS_COMMENT_DIMENSION: t=10cm
Type - Materialien und Oberflächen - Tragendes Material: WS_CONCRETE_REINFORCED_PRECAST
Type - Analytische Eigenschaften - Absorptionsgrad: 0.1; Rauigkeit: 1
Pset_QuantityTakeOff - Reference: WS_WAL_CON_100_PC; sets with these values: 2
Pset_WallCommon - LoadBearing: yes; IsExternal: yes; ExtendToStructure: no; Reference: WS_WAL_CON_100_PC
Sonstige - Familie: Basiswand; Familie und Typ: Basiswand: WS_WAL_CON_100_PC; Typ: WS_WAL_CON_100_PC; Typ-ID: 4372306
Abhängigkeiten - Für Körper: no; Basislinie: Tragende Schicht: Innenkante; Oberkante ist fixiert.: no; Raumbegrenzung: yes; Unterkante ist fixiert: no; Verlängerungsabstand oben: 0 m; Verlängerungsabstand unten: 0 m; Abhängigkeit unten: Dü_U01_OKBP_+0,78; Abhängigkeit oben: Bis Ebene: Dü_EG_OKRD_+4,15; Nicht verknüpfte Höhe: 3.99 m; Versatz oben: 0.2 m; Versatz unten: -0.42 m
ID-Daten - Hat Verknüpfung: no; WS_COMMENT_MATERIAL: C25/30 RC; WS_TYPE_BUILDING_ELEMENT: W
Phasen - Phase erstellt: Phase 1
Tragwerk - Betonüberdeckung - Andere Flächen: Bewehrungsüberdeckung 1 <25 mm>; Tragwerk: yes; Betonüberdeckung - Außenfläche: Bewehrungsüberdeckung 1 <25 mm>; Betonüberdeckung - Innenfläche: Bewehrungsüberdeckung 1 <25 mm>; Tragwerksverwendung: Tragend
Text - WS_LEVEL: 00
Querschnittsdefinition - Querschnitt: Vertikal
Name (Basiswand:WS_WAL_CON_100_PC:...) | Fläche (m2) | Länge (m) | Volumen (m3) | WS_POSITIONNUMBER
3681174 | 4.389 | 1.05 | 0.4389 | 212
3681235 | 10.4538 | 2.62 | 1.04538 | 211
3681292 | 3.99 | 1.05 | 0.399 | 210

# IfcWallStandardCase: Basiswand:WS_WAL_CON_240 (9)
Type - PredefinedType: STANDARD; Material: WS_CONCRETE_REINFORCED 0.24 m
Type - Sonstige - Kategorie: Wände; Familienname: Basiswand
Type - Konstruktion - Abschluss an Öffnungen: Keine; Abschluss an Wänden: Außen; Funktion: Außen; Breite: 0.24 m
Type - Grafiken - Füllmuster für groben Maßstab: <Flächenfüllung>; Farbfüllung für groben Maßstab: 8421504
Type - ID-Daten - Beschreibung: Stahlbeton 24; Typenkommentare: Stahlbeton; Typname: WS_WAL_CON_240; WS_COMMENT_DIMENSION: t=24cm
Type - Materialien und Oberflächen - Tragendes Material: WS_CONCRETE_REINFORCED
Type - Analytische Eigenschaften - Absorptionsgrad: 0.1; Rauigkeit: 1
Pset_QuantityTakeOff - Reference: WS_WAL_CON_240; sets with these values: 2
Pset_WallCommon - LoadBearing: yes; IsExternal: yes; ExtendToStructure: no; Reference: WS_WAL_CON_240
Sonstige - Familie: Basiswand; Familie und Typ: Basiswand: WS_WAL_CON_240; Typ: WS_WAL_CON_240; Typ-ID: 1204113
Abhängigkeiten - Für Körper: no; Basislinie: Tragende Schicht: Innenkante; Oberkante ist fixiert.: no; Raumbegrenzung: yes; Unterkante ist fixiert: no; Verlängerungsabstand oben: 0 m; Verlängerungsabstand unten: 0 m
ID-Daten - Hat Verknüpfung: no; WS_COMMENT_MATERIAL: KS 20-2,0 M2,5; WS_TYPE_BUILDING_ELEMENT: W
Phasen - Phase erstellt: Phase 1
Tragwerk - Tragwerk: yes; Betonüberdeckung - Außenfläche: Bewehrungsüberdeckung 1 <25 mm>; Betonüberdeckung - Innenfläche: Bewehrungsüberdeckung 1 <25 mm>; Tragwerksverwendung: Tragend
Text - WS_LEVEL: 00
Querschnittsdefinition - Querschnitt: Vertikal
Name (Basiswand:WS_WAL_CON_240:...) | In | Abhängigkeit oben | Abhängigkeit unten | Nicht verknüpfte Höhe (m) | Versatz oben (m) | Versatz unten (m) | Fläche (m2) | Länge (m) | Volumen (m3) | WS_POSITIONNUMBER | Betonüberdeckung - Andere Flächen
4526237 | FB_E00_OKFB | Bis Ebene: Dü_EG_UKRD_+3,38 | Dü_EG_UKRD_+3,38 | 0.238 | 0.05 | -0.188 | 1.34944 | 5.6699 | 0.323865 | 020.4 | Bewehrungsüberdeckung 1 <25 mm>
4526298 | FB_E00_OKFB | Bis Ebene: Dü_EG_UKRD_+3,38 | Dü_EG_UKRD_+3,38 | 0.238 | 0.545 | 0.307 | 0.610461 | 2.56496 | 0.146511 | 020.4 | Bewehrungsüberdeckung 1 <25 mm>
4527321 | FB_E00_OKFB | Bis Ebene: Dü_EG_UKRD_+3,38 | Dü_EG_UKRD_+3,38 | 0.238 | 0.05 | -0.188 | 1.00079 | 3.965 | 0.24019 | 020.1 | Bewehrungsüberdeckung 1 <25 mm>
4527502 | FB_E00_OKFB | Bis Ebene: Dü_EG_UKRD_+3,38 | Dü_EG_UKRD_+3,38 | 0.238 | 0.05 | -0.188 | 0.681879 | 2.98504 | 0.163651 | 020.2 | Bewehrungsüberdeckung 1 <25 mm>
4527830 | FB_E00_OKFB | Bis Ebene: Dü_EG_UKRD_+3,38 | Dü_EG_UKRD_+3,38 | 0.238 | 0.05 | -0.188 | 0.33916 | 1.42504 | 0.0813983 | 020.4 | Bewehrungsüberdeckung 1 <25 mm>
4528053 | FB_E00_OKFB | Bis Ebene: Dü_EG_UKRD_+3,38 | Dü_EG_UKRD_+3,38 | 0.238 | 0.05 | -0.188 | 0.445036 | 1.9899 | 0.106809 | 020.1 | Bewehrungsüberdeckung 1 <25 mm>
4531206 | FB_U01_OKFB | Bis Ebene: Dü_U01_OKRD_-0,12 | Dü_U01_OKRD_-0,12 | 0.071 | 2.691 | 2.62 | 0.107144 | 1.50907 | 0.0257146 | 020.4 | Bewehrungsüberdeckung 1 <25 mm>
4533356 | FB_E00_OKFB | Bis Ebene: Dü_EG_UKRD_+2,66 | Dü_EG_UKRD_+2,66 | 0.25 | 0.33 | 0.08 | 0.1 | 0.28 | 0.024 | 020.2 | Bewehrungsüberdeckung 1 <25 mm>
4534266 | FB_E00_OKFB | Bis Ebene: Dü_EG_UKRD_+2,66 | Dü_EG_UKRD_+2,66 | 0.25 | 0.33 | 0.08 | 0.0399967 | 0.279987 | 0.0095992 | 020.2

# IfcWallStandardCase: Basiswand:WS_WAL_CON_250 (60)
Type - PredefinedType: STANDARD; Material: WS_CONCRETE_REINFORCED 0.25 m
Type - Sonstige - Kategorie: Wände; Familienname: Basiswand
Type - Konstruktion - Abschluss an Öffnungen: Keine; Abschluss an Wänden: Außen; Funktion: Außen; Breite: 0.25 m
Type - Grafiken - Farbfüllung für groben Maßstab: 8421504; Füllmuster für groben Maßstab: WS_CONCRETE
Type - ID-Daten - Beschreibung: Exterior or Interior wall; Typenkommentare: Concrete unreinforced; Typname: WS_WAL_CON_250; WS_COMMENT_DIMENSION: t=25cm
Type - Materialien und Oberflächen - Tragendes Material: WS_CONCRETE_REINFORCED
Type - Analytische Eigenschaften - Absorptionsgrad: 0.1; Rauigkeit: 1
Pset_QuantityTakeOff - Reference: WS_WAL_CON_250; sets with these values: 2
Pset_WallCommon - LoadBearing: yes; IsExternal: yes; Reference: WS_WAL_CON_250
Sonstige - Familie: Basiswand; Familie und Typ: Basiswand: WS_WAL_CON_250; Typ: WS_WAL_CON_250; Typ-ID: 329296
Abhängigkeiten - Für Körper: no; Basislinie: Tragende Schicht: Innenkante; Raumbegrenzung: yes; Unterkante ist fixiert: no; Verlängerungsabstand oben: 0 m; Verlängerungsabstand unten: 0 m
ID-Daten - Hat Verknüpfung: no
Phasen - Phase erstellt: Phase 1
Tragwerk - Tragwerk: yes; Betonüberdeckung - Außenfläche: Bewehrungsüberdeckung 1 <25 mm>; Betonüberdeckung - Innenfläche: Bewehrungsüberdeckung 1 <25 mm>; Tragwerksverwendung: Tragend
Querschnittsdefinition - Querschnitt: Vertikal
Name (Basiswand:WS_WAL_CON_250:...) | In | ExtendToStructure = Oberkante ist fixiert. | Abhängigkeit oben | Abhängigkeit unten | Versatz oben (m) | Versatz unten (m) | Nicht verknüpfte Höhe (m) | Fläche (m2) | Länge (m) | Volumen (m3) | WS_COMMENT_MATERIAL | WS_POSITIONNUMBER | WS_TYPE_BUILDING_ELEMENT | Betonüberdeckung - Andere Flächen | WS_LEVEL
3665651 | FB_U01_OKFB | no | Bis Ebene: Dü_U01_UKRD_-0,37 | BP_UG1_OKBP_-3,87 | 0 | 0 | 3.5 | 4.1166 | 1.95 | 1.02915 | C25/30 RC | 010.1 | W | Bewehrungsüberdeckung 1 <25 mm> | U1
3665755 | FB_U01_OKFB | no | Bis Ebene: Dü_U01_UKBP_+0,53 | BP_UG1_OKBP_-3,87 | 0 | 0 | 4.4 | 10.1198 | 2.29996 | 2.52996 | C25/30 RC | 010.2 | W | Bewehrungsüberdeckung 1 <25 mm> | U1
3665812 | FB_U01_OKFB | no | Bis Ebene: Dü_U01_UKBP_+0,53 | BP_UG1_OKBP_-3,87 | 0 | 0 | 4.4 | 7.48 | 1.95 | 1.87 | C25/30 RC | 010.3 | W | Bewehrungsüberdeckung 1 <25 mm> | U1
3667695 | FB_U01_OKFB | no | Bis Ebene: Dü_U01_UKRD_-0,37 | Dü_U01_OKBP_-1,77_Bodenkanal_M | 0 | 0 | 1.4 | 3.738 | 2.42 | 0.9345 | C25/30 WU | 006 | F | Bewehrungsüberdeckung 1 <25 mm> | U1
3674303 | FB_U01_OKFB | yes | Bis Ebene: Dü_EG_UKRD_+3,38 | Dü_U01_OKRD_-0,12 | 0 | 0 | 3.5 | 4.45527 | 1.25501 | 1.11382 | C25/30 RC | 009.2 | W | Bewehrungsüberdeckung 1 <25 mm> | 00
3674773 | FB_U01_OKFB | no | Bis Ebene: Dü_EG_UKRD1_+3,735 | Dü_U01_OKRD_-0,12 | 0 | 0 | 3.855 | 6.74626 | 2 | 1.68656 | C25/30 RC | 006.3 | W | Bewehrungsüberdeckung 1 <25 mm> | 00
3675762 | FB_U01_OKFB | no | Bis Ebene: Dü_EG_UKRD1_+3,735 | Dü_U01_OKRD_-0,12 | 0 | 0 | 3.855 | 4.07866 | 2 | 1.01966 | C25/30 RC | 006.2 | W | Bewehrungsüberdeckung 1 <25 mm> | 00
3676359 | FB_U01_OKFB | no | Bis Ebene: Dü_EG_UKRD_+3,85 | Dü_U01_OKRD_-0,12 | 0 | 0 | 3.97 | 2.40829 | 0.725096 | 0.602072 | C25/30 RC | 016.2 | W | Bewehrungsüberdeckung 1 <25 mm> | 00
3676966 | FB_U01_OKFB | no | Bis Ebene: Dü_EG_UKRD_+4,15 | Dü_U01_OKRD_-0,12 | 0 | 0 | 4.27 | 33.8037 | 8.72001 | 8.45092 | C25/30 RC | 004 | W | Bewehrungsüberdeckung 1 <25 mm> | 00
3677671 | FB_U01_OKFB | no | Bis Ebene: Dü_EG_UKRD_+4,15 | Dü_U01_OKRD_-0,12 | 0 | 0 | 4.27 | 5.5996 | 1.48 | 1.3999 | C25/30 RC | 201 | W | Bewehrungsüberdeckung 1 <25 mm> | 00
3677925 | FB_U01_OKFB | no | Bis Ebene: Dü_EG_UKRD_+4,15 | Dü_U01_OKRD_-0,12 | 0 | 0 | 4.27 | 30.8725 | 10 | 7.71813 | C25/30 RC | 003 | W | Bewehrungsüberdeckung 1 <25 mm> | 00
3678293 | FB_U01_OKFB | no | Bis Ebene: Dü_EG_UKRD_+3,785 | Dü_U01_OKRD_-0,12 | 0 | 0 | 3.905 | 18.8116 | 7.38001 | 4.7029 | C25/30 RC | 013 | W | Bewehrungsüberdeckung 1 <25 mm> | 00
3678847 | FB_U01_OKFB | no | Bis Ebene: Dü_EG_UKRD_+3,735 | Dü_U01_OKRD_-0,12 | 0.05 | 0 | 3.905 | 21.2042 | 5.305 | 5.30104 | C25/30 RC | 002 | W | Bewehrungsüberdeckung 1 <25 mm> | 00
3679313 | FB_U01_OKFB | no | Bis Ebene: Dü_EG_UKRD_+3,735 | Dü_U01_OKRD_-0,12 | 0.05 | 0 | 3.905 | 5.97353 | 2 | 1.49327 | C25/30 RC | 012.2 | W | Bewehrungsüberdeckung 1 <25 mm> | 00
3679501 | FB_U01_OKFB | no | Bis Ebene: Dü_EG_UKRD_+3,735 | Dü_U01_OKRD_-0,12 | 0.05 | 0 | 3.905 | 12.2194 | 3.84 | 3.05485 | C25/30 RC | 012.1 | W | Bewehrungsüberdeckung 1 <25 mm> | 00
3679661 | FB_U01_OKFB | no | Bis Ebene: Dü_EG_UKRD_+3,735 | Dü_U01_OKRD_-0,12 | 0.05 | 0 | 3.905 | 36.5837 | 10 | 8.97242 | C25/30 RC | 001 | W | Bewehrungsüberdeckung 1 <25 mm> | 00
3680038 | FB_E00_OKFB | no | Bis Ebene: Dü_EG_UKRD_+3,785 | Dü_U01_OKBP_+0,78 | 0 | 0 | 3.005 | 6.91138 | 2.29996 | 1.72785 | C25/30 RC | 010.4 | W | Bewehrungsüberdeckung 1 <25 mm> | 00
3680377 | FB_E00_OKFB | no | Bis Ebene: Dü_EG_UKRD_+3,785 | Dü_U01_OKBP_+0,78 | 0 | 0 | 3.005 | 11.2711 | 8.13999 | 2.81777 | C25/30 RC | 010.1 | W | Bewehrungsüberdeckung 1 <25 mm> | 00
3680535 | FB_E00_OKFB | no | Bis Ebene: Dü_EG_UKRD_+3,785 | Dü_U01_OKBP_+0,78 | 0 | 0 | 3.005 | 5.67933 | 2.13996 | 1.41983 | C25/30 RC | 010.2 | W |  | 00
3680735 | FB_E00_OKFB | no | Bis Ebene: Dü_EG_UKRD_+3,785 | Dü_U01_OKBP_+0,78 | 0 | 0 | 3.005 | 6.91138 | 2.29996 | 1.72785 | C25/30 RC | 010.3 | W | Bewehrungsüberdeckung 1 <25 mm> | 00
3683917 | FB_U01_OKFB | no | Bis Ebene: Dü_EG_UKRD_+3,785 | Dü_U01_OKRD_-0,12 | 0 | 0 | 3.905 | 15.1466 | 4.09 | 3.78664 | C25/30 RC | 011 | W | Bewehrungsüberdeckung 1 <25 mm> | 00
3687736 | FB_U01_OKFB | no | Bis Ebene: Dü_U01_OKBP_+0,78 | Dü_U01_OKRD_-0,12 | 0 | 0 | 0.9 | 1.158 | 2.425 | 0.2895 | C25/30 RC | 021 | W | Bewehrungsüberdeckung 1 <25 mm> | U1
3705855 | FB_U01_OKFB | no | Bis Ebene: Dü_U01_OKBP_+0,78 | Dü_U01_OKBP_-0,75_Hubtisch | 0 | 0 | 1.53 | 3.05915 | 2.26496 | 0.764787 | C25/30 RC | 002 | F | Bewehrungsüberdeckung 1 <25 mm> | U1
3705924 | FB_U01_OKFB | no | Bis Ebene: Dü_U01_UKBP_+0,53 | Dü_U01_OKBP_-0,75_Hubtisch | 0 | 0 | 1.28 | 2.144 | 1.675 | 0.536 | C25/30 RC | 002 | F | Bewehrungsüberdeckung 1 <25 mm> | U1
3705982 | FB_U01_OKFB | no | Bis Ebene: Dü_U01_OKBP_+0,78 | Dü_U01_OKBP_-0,75_Hubtisch | 0 | 0 | 1.53 | 2.73915 | 2.13996 | 0.684787 | C25/30 RC | 002 | F | Bewehrungsüberdeckung 1 <25 mm> | U1
3709035 | FB_E00_OKFB | no | Bis Ebene: Dü_OG1_OKHT_+8,040_Nebenträger Halle | Dü_EG_OKRD_+4,035 | 0 | 0 | 4.005 | 16.1806 | 3.95504 | 4.04514 | C25/30 RC | 002 | W | Bewehrungsüberdeckung 1 <25 mm> | 01
3709263 | FB_E00_OKFB | no | Bis Ebene: Dü_OG1_OKHT_+8,040_Nebenträger Halle | Dü_EG_OKRD_+4,035 | 0 | 0 | 4.005 | 38.9887 | 10.0075 | 9.74717 | C25/30 RC | 001 | W | Bewehrungsüberdeckung 1 <25 mm> | 01
3710817 | FB_E00_OKFB | no | Bis Ebene: Dü_OG1_OKHT_+8,040_Nebenträger Halle | Dü_EG_OKRD_+4,40 | 0 | 0 | 3.64 | 35.2029 | 10.0075 | 8.80073 | C25/30 RC | 003 | W | Bewehrungsüberdeckung 1 <25 mm> | 01
3710940 | FB_E00_OKFB | no | Bis Ebene: Dü_OG1_OKHT_+7,780_Binder | Dü_EG_UKRD_+4,15 | -0.8 | 0 | 2.83 | 3.7922 | 1.465 | 0.94805 | C25/30 RC | 004 | W | Bewehrungsüberdeckung 1 <25 mm> | 01
3711501 | FB_E00_OKFB | no | Bis Ebene: Dü_OG1_UKRD_+7,765 | Dü_EG_OKRD_+4,40 | 0.15 | 0 | 3.515 | 5.05046 | 1.75991 | 1.26262 | C25/30 RC | 201 | W | Bewehrungsüberdeckung 1 <25 mm> | 01
3711878 | FB_E00_OKFB | no | Bis Ebene: Dü_OG1_OKHT_+8,005_Träger OG | Dü_EG_OKRD_+3,985 | 0 | 0 | 4.02 | 38.7723 | 9.74 | 9.69308 | C25/30 RC | 005 | W | Bewehrungsüberdeckung 1 <25 mm> | 01
3712221 | FB_E00_OKFB | no | Bis Ebene: Dü_OG1_UKRD_+7,815 | Dü_EG_OKRD_+3,985 | 0.1 | 0 | 3.93 | 9.432 | 2.15 | 2.358 | C25/30 RC | 006.1 | W | Bewehrungsüberdeckung 1 <25 mm> | 01
3712432 | FB_E00_OKFB | no | Bis Ebene: Dü_OG1_UKRD_+7,815 | Dü_EG_OKRD_+3,985 | 0.1 | 0 | 3.93 | 9.432 | 2.15 | 2.358 | C25/30 RC | 101 | W | Bewehrungsüberdeckung 1 <25 mm> | 01
3712536 | FB_E00_OKFB | no | Bis Ebene: Dü_OG1_UKRD_+7,815 | Dü_EG_OKRD_+3,98 | 0.1 | 0 | 3.935 | 6.87751 | 2 | 1.71938 | C25/30 RC | 006.3 | W |  | 01
3734314 | FB_E00_OKFB | no | Bis Ebene: Dü_OG1_UKHT_+7,605_Träger OG | Dü_EG_OKRD_+3,98 | 0 | 0 | 3.625 | 2.56782 | 0.834343 | 0.641956 | C25/30 RC | 101 | W | Bewehrungsüberdeckung 1 <25 mm> | 01
3843718 | FB_E00_OKFB | no | Bis Ebene: Dü_OG1_UKRD_+7,765 | Dü_EG_OKRD_+4,40 | 0.15 | 0 | 3.515 | 13.9774 | 4.08991 | 3.49435 | C25/30 RC | 004 | W | Bewehrungsüberdeckung 1 <25 mm> | 01
3844012 | FB_E00_OKFB | no | Bis Ebene: Dü_OG1_OKHT_+7,780_Binder | Dü_EG_UKRD_+3,735 | -0.8 | 0.05 | 3.195 | 4.2813 | 1.465 | 1.07032 | C25/30 RC | 002 | W | Bewehrungsüberdeckung 1 <25 mm> | 01
3845556 | FB_U01_OKFB | no | Bis Ebene: Dü_EG_UKRD_+3,43 | Dü_U01_OKRD_-0,12 | 0 | 0 | 3.55 | 32.921 | 9.63 | 8.20021 | C25/30 RC | 008 | W | Bewehrungsüberdeckung 1 <25 mm> | 00
3845893 | FB_E00_OKFB | no | Bis Ebene: Dü_EG_UKRD1_+3,735 | Dü_EG_OKRD_+3,68 | 0 | 0 | 0.055 | 0.580252 | 10.55 | 0.145063 | C25/30 | 009 | W | Bewehrungsüberdeckung 1 <25 mm> | 00
3846240 | FB_U01_OKFB | no | Bis Ebene: Dü_EG_UKRD_+3,43 | Dü_U01_OKRD_-0,12 | 0 | 0 | 3.55 | 20.8278 | 7.675 | 5.20696 | C25/30 | 007 | W | Bewehrungsüberdeckung 1 <25 mm> | 00
3856122 | FB_U01_OKFB | no | Bis Ebene: Dü_U01_UKRD_-0,37 | BP_UG1_OKBP_-3,87 | 0 | 0 | 3.5 | 17.3484 | 5.96 | 4.33711 | KS 20-2,0 M2,5 | 020.1 | W | Bewehrungsüberdeckung 1 <25 mm> | U1
3856753 | FB_U01_OKFB | no | Bis Ebene: Dü_U01_UKRD_-0,37 | BP_UG1_OKBP_-3,87 | 0 | 0 | 3.5 | 16.4734 | 5.96 | 4.11836 | KS 20-2,0 M2,5 | 020.3 | W | Bewehrungsüberdeckung 1 <25 mm> | U1
3856766 | FB_U01_OKFB | no | Bis Ebene: Dü_U01_UKRD_-0,37 | BP_UG1_OKBP_-3,87 | 0 | 0 | 3.5 | 10.8151 | 3.09004 | 2.70378 | KS 20-2,0 M2,5 | 020.2 | W | Bewehrungsüberdeckung 1 <25 mm> | U1
3876193 | FB_E00_OKFB | no | Bis Ebene: Dü_EG_UKRD_+3,785 | Dü_U01_OKBP_+0,78 | 0 | 0 | 3.005 | 28.1815 | 11.275 | 7.04537 | C25/30 RC | 021 | W | Bewehrungsüberdeckung 1 <25 mm> | 00
3903789 | FB_U01_OKFB | no | Bis Ebene: Dü_U01_UKBP_+0,53 | Dü_U01_OKBP_-0,75_Hubtisch | -0.53 | 0 | 0.75 | 1.06875 | 1.55 | 0.267187 | C25/30 RC | 002 | F | Bewehrungsüberdeckung 1 <25 mm> | U1
4045907 | FB_E00_OKFB | yes | Bis Ebene: Dü_OG1_UKRD_+7,765 | Dü_EG_OKRD_+4,40 | 0.15 | 0 | 3.515 | 5.65915 | 1.86 | 1.41479 | C25/30 RC | 202 | W | Bewehrungsüberdeckung 1 <25 mm> | 01
4046476 | FB_U01_OKFB | no | Bis Ebene: Dü_EG_UKRD_+4,15 | Dü_U01_OKRD_-0,12 | 0 | 0 | 4.27 | 6.8747 | 1.86 | 1.71867 | C25/30 RC | 202 | W | Bewehrungsüberdeckung 1 <25 mm> | 00
4156973 | FB_E00_OKFB | no | Bis Ebene: Dü_EG_UKRD_+3,785 | Dü_U01_OKBP_+0,78 | 0 | 0 | 3.005 | 13.6051 | 8.025 | 3.40127 | C25/30 RC | 107 | W | Bewehrungsüberdeckung 1 <25 mm> | 00
4169833 | FB_E00_OKFB | no | Bis Ebene: Dü_EG_UKRD_+3,85 | Dü_EG_UKRD_+2,66 | 0 | 0 | 1.19 | 2.36115 | 2.635 | 0.590288 | C25/30 RC | 016.1 | W |  | 00
4170054 | FB_U01_OKFB | no | Bis Ebene: Dü_EG_UKRD_+3,85 | Dü_U01_OKRD_-0,12 | 0 | 0 | 3.97 | 4.30745 | 1.21 | 1.07686 | C25/30 RC | 016.3 | W | Bewehrungsüberdeckung 1 <25 mm> | 00
4170478 | FB_U01_OKFB | no | Bis Ebene: Dü_EG_OKRD_+2,86 | Dü_U01_OKRD_-0,12 | 0 | 0 | 2.98 | 1.0131 | 0.464967 | 0.253275 | C25/30 RC | 016.2 | W | Bewehrungsüberdeckung 1 <25 mm> | 00
4170537 | FB_U01_OKFB | no | Bis Ebene: Dü_EG_OKRD_+2,86 | Dü_U01_OKRD_-0,12 | 0 | 0 | 2.98 | 1.3856 | 0.464967 | 0.3464 | C25/30 RC | 015 | W | Bewehrungsüberdeckung 1 <25 mm> | 00
4170949 | FB_E00_OKFB | no | Bis Ebene: Dü_EG_UKRD_+3,85 | Dü_EG_OKRD_+2,86 | 0 | 0 | 0.99 | 2.36115 | 2.635 | 0.590288 | C25/30 RC | 016.3 | W |  | 00
4172292 | FB_U01_OKFB | no | Bis Ebene: Dü_EG_UKRD_+3,85 | Dü_U01_OKRD_-0,12 | 0 | 0 | 3.97 | 6.19321 | 1.435 | 1.5483 | C25/30 RC | 016.1 | W | Bewehrungsüberdeckung 1 <25 mm> | 00
4174867 | FB_U01_OKFB | no | Bis Ebene: Dü_EG_UKRD1_+3,735 | Dü_U01_OKRD_-0,12 | 0 | 0 | 3.855 | 28.2037 | 10.575 | 7.05093 | C25/30 RC | 016.4 | W | Bewehrungsüberdeckung 1 <25 mm> | 00
4175413 | FB_U01_OKFB | no | Bis Ebene: Dü_EG_UKRD1_+3,735 | Dü_U01_OKRD_-0,12 | 0 | 0 | 3.855 | 3.63041 | 2 | 0.907602 | C25/30 RC | 016.5 | W | Bewehrungsüberdeckung 1 <25 mm> | 00
4176002 | FB_E00_OKFB | no | Bis Ebene: Dü_EG_OKRD_+5,12 | Dü_EG_UKRD_+4,15 | -0.2 | 0.06 | 0.71 | 1.33125 | 2 | 0.332813 | C25/30 RC | 016.1 | W | Bewehrungsüberdeckung 1 <25 mm> | 00
4179083 | FB_U01_OKFB | no | Bis Ebene: Dü_EG_OKRD_+3,985 | Dü_U01_OKRD_-0,12 | 0 | 0 | 4.105 | 37.1281 | 9.04491 | 9.28203 | C25/30 RC | 005.1 | W | Bewehrungsüberdeckung 1 <25 mm> | 00
4439165 | FB_E00_OKFB | no | Bis Ebene: Dü_EG_OKRD_+5,12 | Dü_EG_OKRD_+4,15 | -0.2 | 0.06 | 0.71 | 5.68355 | 8.13 | 1.42089 | C25/30 RC | 016.1 | W | Bewehrungsüberdeckung 1 <25 mm> | 00
4617103 | FB_U01_OKFB | no | Bis Ebene: Dü_EG_OKHT_+4,655_Randträger Foyer 2 | Dü_U01_OKRD_-0,12 | -1.2 | 0 | 3.575 | 1.21538 | 0.464967 | 0.303845 | C25/30 RC | 016.2 | W | Bewehrungsüberdeckung 1 <25 mm> | 00

# IfcWallStandardCase: Basiswand:WS_WAL_CON_250_WT (31)
In: FB_U01_OKFB
Type - PredefinedType: STANDARD; Material: WS_CONCRETE_REINFORCED_WATERTIGHT 0.25 m
Type - Sonstige - Kategorie: Wände; Familienname: Basiswand
Type - Konstruktion - Abschluss an Öffnungen: Keine; Abschluss an Wänden: Außen; Breite: 0.25 m; Funktion: Außen
Type - Grafiken - Füllmuster für groben Maßstab: WS_CONCRETE_REINFORCED_WATERTIGHT; Farbfüllung für groben Maßstab: 8421504
Type - ID-Daten - Beschreibung: Exterior or Interior wall; Typenkommentare: Concrete reinforced watertight; Typname: WS_WAL_CON_250_WT; WS_COMMENT_DIMENSION: t=25cm
Type - Materialien und Oberflächen - Tragendes Material: WS_CONCRETE_REINFORCED_WATERTIGHT
Type - Analytische Eigenschaften - Absorptionsgrad: 0.1; Rauigkeit: 1
Pset_QuantityTakeOff - Reference: WS_WAL_CON_250_WT; sets with these values: 2
Pset_WallCommon - LoadBearing: yes; Reference: WS_WAL_CON_250_WT; IsExternal: yes; ExtendToStructure: no
Sonstige - Familie: Basiswand; Familie und Typ: Basiswand: WS_WAL_CON_250_WT; Typ: WS_WAL_CON_250_WT; Typ-ID: 995991
Abhängigkeiten - Für Körper: no; Basislinie: Tragende Schicht: Innenkante; Oberkante ist fixiert.: no; Raumbegrenzung: yes; Unterkante ist fixiert: no; Verlängerungsabstand oben: 0 m; Verlängerungsabstand unten: 0 m
ID-Daten - Hat Verknüpfung: no; WS_COMMENT_MATERIAL: C25/30 WU
Phasen - Phase erstellt: Phase 1
Tragwerk - Tragwerk: yes; Betonüberdeckung - Außenfläche: Bewehrungsüberdeckung 1 <25 mm>; Betonüberdeckung - Innenfläche: Bewehrungsüberdeckung 1 <25 mm>; Tragwerksverwendung: Tragend
Querschnittsdefinition - Querschnitt: Vertikal
Name (Basiswand:WS_WAL_CON_250_WT:...) | Abhängigkeit oben | Abhängigkeit unten | Nicht verknüpfte Höhe (m) | Versatz oben (m) | Versatz unten (m) | Fläche (m2) | Länge (m) | Volumen (m3) | WS_POSITIONNUMBER | WS_TYPE_BUILDING_ELEMENT | Betonüberdeckung - Andere Flächen | WS_LEVEL
3665461 | Bis Ebene: Dü_U01_UKRD_-0,37 | BP_UG1_OKBP_-3,87 | 3.5 | 0 | 0 | 54.081 | 15.75 | 13.5202 | 104 | W | Bewehrungsüberdeckung 1 <25 mm> | U1
3665462 | Bis Ebene: Dü_U01_OKRD_-0,12 | BP_UG1_OKBP_-3,87 | 3.75 | 0 | 0 | 14.4375 | 3.84 | 3.60938 | 101 | W | Bewehrungsüberdeckung 1 <25 mm> | U1
3665464 | Bis Ebene: Dü_U01_UKRD_-0,37 | BP_UG1_OKBP_-3,87 | 3.5 | 0 | 0 | 36.8375 | 11.525 | 9.20937 | 103 | W | Bewehrungsüberdeckung 1 <25 mm> | U1
3665906 | Bis Ebene: BP_UG1_UKBP_-4,12 | BP_UG1_OKBP_-5,30_Unterfahrt | 1.18 | 0 | 0 | 2.2035 | 1.95 | 0.550875 | 001 | F | Bewehrungsüberdeckung 1 <25 mm> | FU
3665907 | Bis Ebene: BP_UG1_UKBP_-4,12 | BP_UG1_OKBP_-5,30_Unterfahrt | 1.18 | 0 | 0 | 2.59896 | 2.29996 | 0.649739 | 001 | F | Bewehrungsüberdeckung 1 <25 mm> | FU
3665908 | Bis Ebene: BP_UG1_UKBP_-4,12 | BP_UG1_OKBP_-5,30_Unterfahrt | 1.18 | 0 | 0 | 2.2035 | 1.95 | 0.550875 | 001 | F | Bewehrungsüberdeckung 1 <25 mm> | FU
3665909 | Bis Ebene: BP_UG1_UKBP_-4,12 | BP_UG1_OKBP_-5,30_Unterfahrt | 1.18 | 0 | 0 | 2.59896 | 2.29996 | 0.649739 | 001 | F | Bewehrungsüberdeckung 1 <25 mm> | FU
3667265 | Bis Ebene: Dü_U01_UKRD_-0,37 | Dü_U01_OKBP_-1,77_Bodenkanal_M | 1.4 | 0 | 0 | 43.863 | 32.345 | 10.9657 | 006 | F | Bewehrungsüberdeckung 1 <25 mm> | U1
3667354 | Bis Ebene: Dü_U01_UKRD_-0,37 | Dü_U01_OKBP_-1,77_Bodenkanal_M | 1.4 | 0 | 0 | 48.671 | 34.765 | 12.1677 | 006 | F | Bewehrungsüberdeckung 1 <25 mm> | U1
3667361 | Bis Ebene: Dü_U01_UKRD_-0,37 | Dü_U01_OKBP_-1,77_Bodenkanal_M | 1.4 | 0 | 0 | 17.7163 | 22.275 | 4.42908 | 006 | F | Bewehrungsüberdeckung 1 <25 mm> | U1
3667767 | Bis Ebene: Dü_U01_UKRD_-0,37 | Dü_U01_OKBP_-1,77_Bodenkanal_M | 1.4 | 0 | 0 | 1.40695 | 1.25497 | 0.351738 | 006 | F |  | U1
3667891 | Bis Ebene: Dü_U01_UKRD_-0,37 | Dü_U01_OKBP_-1,77_Bodenkanal_M | 1.4 | 0 | 0 | 4.2769 | 3.30493 | 1.06923 | 006 | F |  | U1
3668072 | Bis Ebene: Dü_U01_UKRD_-0,37 | Dü_U01_OKBP_-1,77_Bodenkanal_M | 0.41 | 0 | 0.99 | 0.15991 | 0.65 | 0.0395233 | 006 | F |  | U1
3673569 | Bis Ebene: Dü_EG_UKRD_+3,43 | Dü_U01_OKRD_-0,12 | 3.55 | 0 | 0 | 21.3887 | 6.025 | 5.34719 | 105 | W | Bewehrungsüberdeckung 1 <25 mm> | 00
3673909 | Bis Ebene: Dü_EG_UKRD_+3,43 | Dü_U01_OKRD_-0,12 | 3.55 | 0 | 0 | 67.8227 | 19.23 | 16.9557 | 106 | W | Bewehrungsüberdeckung 1 <25 mm> | 00
3681901 | Bis Ebene: Dü_U01_UKRD_-0,37 | Dü_U01_OKBP_-1,22_RLT | 0.85 | 0 | 0 | 8.18551 | 9.65501 | 2.04638 | 004 | F | Bewehrungsüberdeckung 1 <25 mm> | U1
3682086 | Bis Ebene: Dü_U01_UKRD_-0,37 | Dü_U01_OKBP_-1,22_RLT | 0.85 | 0 | 0 | 0.577177 | 0.679032 | 0.144294 | 004 | F | Bewehrungsüberdeckung 1 <25 mm> | U1
3682745 | Bis Ebene: Dü_U01_UKBP_+0,53 | Dü_U01_OKBP_-1,22_RLT | 1.75 | 0 | 0 | 12.355 | 7.06 | 3.08875 | 004 | F | Bewehrungsüberdeckung 1 <25 mm> | U1
3682840 | Bis Ebene: Dü_U01_UKBP_+0,53 | Dü_U01_OKBP_-1,22_RLT | 1.75 | 0 | 0 | 11.1562 | 6.35 | 2.78906 | 004 | F | Bewehrungsüberdeckung 1 <25 mm> | U1
3687641 | Bis Ebene: Dü_U01_UKBP_+0,53 | Dü_U01_OKRD_-0,12 | 0.65 | 0 | 0 | 4.14637 | 6.50403 | 1.02644 | 005 | F | Bewehrungsüberdeckung 1 <25 mm> | U1
3694122 | Bis Ebene: Dü_U01_UKRD_-0,80 | Dü_U01_OKBP_-1,40_Unterfahrt | 0.63 | 0.03 | 0 | 1.26 | 2 | 0.315 | 005 | F | Bewehrungsüberdeckung 1 <25 mm> | U1
3694123 | Bis Ebene: Dü_U01_UKRD_-0,80 | Dü_U01_OKBP_-1,40_Unterfahrt | 0.63 | 0.03 | 0 | 1.3545 | 2.15 | 0.338625 | 005 | F | Bewehrungsüberdeckung 1 <25 mm> | U1
3694124 | Bis Ebene: Dü_U01_UKRD_-0,80 | Dü_U01_OKBP_-1,40_Unterfahrt | 0.63 | 0.03 | 0 | 1.26 | 2 | 0.315 | 005 | F | Bewehrungsüberdeckung 1 <25 mm> | U1
3694125 | Bis Ebene: Dü_U01_UKRD_-0,80 | Dü_U01_OKBP_-1,40_Unterfahrt | 0.63 | 0.03 | 0 | 1.3545 | 2.15 | 0.338625 | 005 | F | Bewehrungsüberdeckung 1 <25 mm> | U1
3708113 | Bis Ebene: Dü_U01_UKBP_+0,53 | Dü_U01_OKRD_-0,12 | 0.65 | 0 | 0 | 2.396 | 3.84 | 0.599 | 101 | W | Bewehrungsüberdeckung 1 <25 mm> | U1
3708233 | Bis Ebene: Dü_U01_UKBP_+0,53 | Dü_U01_OKRD_-0,12 | 0.65 | 0 | 0 | 2.45375 | 4.025 | 0.613437 | 102 | W | Bewehrungsüberdeckung 1 <25 mm> | U1
3847320 | Bis Ebene: Dü_EG_OKRD_+3,68 | Dü_U01_OKRD_-0,12 | 4.385 | 0.585 | 0 | 33.5891 | 7.66 | 8.39727 | 106 | W | Bewehrungsüberdeckung 1 <25 mm> | 00
3848552 | Bis Ebene: Dü_EG_UKRD_+3,85 | Dü_U01_OKRD_-0,12 | 3.97 | 0 | 0 | 135.973 | 34.375 | 33.9931 | 103 | W | Bewehrungsüberdeckung 1 <25 mm> | 00
4173215 | Bis Ebene: Dü_EG_OKRD_+5,12 | Dü_U01_OKRD_-0,12 | 5.42 | 0.18 | 0 | 42.005 | 7.75 | 10.5012 | 103 | W | Bewehrungsüberdeckung 1 <25 mm> | 00
4218239 | Bis Ebene: Dü_U01_UKRD_-0,37 | BP_UG1_OKBP_-3,87 | 3.5 | 0 | 0 | 25.46 | 7.685 | 6.365 | 101 | W | Bewehrungsüberdeckung 1 <25 mm> | U1
4311298 | Bis Ebene: Dü_EG_OKRD_+5,12 | Dü_U01_OKRD_-0,12 | 5.37 | 0.13 | 0 | 17.3987 | 3.30501 | 4.34967 | 104 | W | Bewehrungsüberdeckung 1 <25 mm> | 00

# IfcWallStandardCase: Basiswand:WS_WAL_CON_300, Basiswand:WS_WAL_CON_300:3672051
In: FB_E00_OKFB
Type - PredefinedType: STANDARD; Material: WS_CONCRETE_REINFORCED 0.3 m
Type - Sonstige - Kategorie: Wände; Familienname: Basiswand
Type - Konstruktion - Abschluss an Öffnungen: Keine; Abschluss an Wänden: Außen; Funktion: Außen; Breite: 0.3 m
Type - Grafiken - Farbfüllung für groben Maßstab: 8421504; Füllmuster für groben Maßstab: <Flächenfüllung>
Type - ID-Daten - Beschreibung: Stahlbeton 30; Typenkommentare: Stahlbeton; Typname: WS_WAL_CON_300; WS_COMMENT_DIMENSION: t=30cm
Type - Materialien und Oberflächen - Tragendes Material: WS_CONCRETE_REINFORCED
Type - Analytische Eigenschaften - Absorptionsgrad: 0.1; Rauigkeit: 1
Pset_QuantityTakeOff - Reference: WS_WAL_CON_300; sets with these values: 2
Pset_WallCommon - LoadBearing: yes; IsExternal: yes; ExtendToStructure: no; Reference: WS_WAL_CON_300
Sonstige - Familie: Basiswand; Familie und Typ: Basiswand: WS_WAL_CON_300; Typ: WS_WAL_CON_300; Typ-ID: 1405397
Abhängigkeiten - Für Körper: no; Basislinie: Tragende Schicht: Innenkante; Oberkante ist fixiert.: no; Raumbegrenzung: yes; Unterkante ist fixiert: no; Verlängerungsabstand oben: 0 m; Verlängerungsabstand unten: 0 m; Versatz oben: 0 m; Versatz unten: 0 m; Abhängigkeit oben: Bis Ebene: Dü_EG_UKRD_+3,785; Abhängigkeit unten: Dü_U01_OKBP_+0,78; Nicht verknüpfte Höhe: 3.005 m
Bemaßungen - Fläche: 17.1886 m2; Länge: 5.59501 m; Volumen: 5.15659 m3
ID-Daten - Hat Verknüpfung: no; WS_COMMENT_MATERIAL: C25/30 RC; WS_POSITIONNUMBER: 101; WS_TYPE_BUILDING_ELEMENT: W
Phasen - Phase erstellt: Phase 1
Tragwerk - Betonüberdeckung - Andere Flächen: Bewehrungsüberdeckung 1 <25 mm>; Tragwerk: yes; Betonüberdeckung - Außenfläche: Bewehrungsüberdeckung 1 <25 mm>; Betonüberdeckung - Innenfläche: Bewehrungsüberdeckung 1 <25 mm>; Tragwerksverwendung: Tragend
Text - WS_LEVEL: 00
Querschnittsdefinition - Querschnitt: Vertikal

# IfcWallStandardCase: Basiswand:WS_WAL_CON_300_WT (2)
In: FB_U01_OKFB
Type - PredefinedType: STANDARD; Material: WS_CONCRETE_REINFORCED_WATERTIGHT 0.3 m
Type - Sonstige - Kategorie: Wände; Familienname: Basiswand
Type - Konstruktion - Abschluss an Öffnungen: Keine; Abschluss an Wänden: Außen; Funktion: Außen; Breite: 0.3 m
Type - Grafiken - Füllmuster für groben Maßstab: <Flächenfüllung>; Farbfüllung für groben Maßstab: 8421504
Type - ID-Daten - Beschreibung: Stahlbeton 30 WU; Typenkommentare: Stahlbeton WU; Typname: WS_WAL_CON_300_WT; WS_COMMENT_DIMENSION: t=30cm
Type - Materialien und Oberflächen - Tragendes Material: WS_CONCRETE_REINFORCED_WATERTIGHT
Type - Analytische Eigenschaften - Absorptionsgrad: 0.1; Rauigkeit: 1
Pset_QuantityTakeOff - Reference: WS_WAL_CON_300_WT; sets with these values: 2
Pset_WallCommon - LoadBearing: yes; IsExternal: yes; ExtendToStructure: no; Reference: WS_WAL_CON_300_WT
Sonstige - Familie: Basiswand; Familie und Typ: Basiswand: WS_WAL_CON_300_WT; Typ: WS_WAL_CON_300_WT; Typ-ID: 745411
Abhängigkeiten - Für Körper: no; Basislinie: Tragende Schicht: Innenkante; Oberkante ist fixiert.: no; Raumbegrenzung: yes; Unterkante ist fixiert: no; Verlängerungsabstand oben: 0 m; Verlängerungsabstand unten: 0 m; Versatz oben: 0 m; Versatz unten: 0 m; Abhängigkeit oben: Bis Ebene: Dü_EG_UKRD_+3,785
ID-Daten - Hat Verknüpfung: no; WS_COMMENT_MATERIAL: C25/30 WU; WS_POSITIONNUMBER: 102; WS_TYPE_BUILDING_ELEMENT: W
Phasen - Phase erstellt: Phase 1
Tragwerk - Tragwerk: yes; Betonüberdeckung - Außenfläche: Bewehrungsüberdeckung 1 <25 mm>; Betonüberdeckung - Innenfläche: Bewehrungsüberdeckung 1 <25 mm>; Tragwerksverwendung: Tragend
Text - WS_LEVEL: 00
Querschnittsdefinition - Querschnitt: Vertikal
Name (Basiswand:WS_WAL_CON_300_WT:...) | Abhängigkeit unten | Nicht verknüpfte Höhe (m) | Fläche (m2) | Länge (m) | Volumen (m3)
3672347 | Dü_U01_OKBP_-1,22_RLT | 5.005 | 27.7074 | 5.67097 | 8.31223 | Tragwerk - Betonüberdeckung - Andere Flächen: Bewehrungsüberdeckung 1 <25 mm>
3848628 | Dü_U01_OKRD_-0,12 | 3.905 | 24.422 | 6.37903 | 7.3266

# IfcWallStandardCase: Basiswand:WS_WAL_CON_375_WT, Basiswand:WS_WAL_CON_375_WT:4222900
In: FB_U01_OKFB
Type - PredefinedType: STANDARD; Material: WS_CONCRETE_REINFORCED_WATERTIGHT 0.375 m
Type - Sonstige - Kategorie: Wände; Familienname: Basiswand
Type - Konstruktion - Abschluss an Öffnungen: Keine; Abschluss an Wänden: Außen; Funktion: Außen; Breite: 0.375 m
Type - Grafiken - Füllmuster für groben Maßstab: <Flächenfüllung>; Farbfüllung für groben Maßstab: 8421504
Type - ID-Daten - Beschreibung: Stahlbeton 37,5; Typenkommentare: Stahlbeton; Typname: WS_WAL_CON_375_WT; WS_COMMENT_DIMENSION: t=37,5cm
Type - Materialien und Oberflächen - Tragendes Material: WS_CONCRETE_REINFORCED_WATERTIGHT
Type - Analytische Eigenschaften - Absorptionsgrad: 0.1; Rauigkeit: 1
Pset_QuantityTakeOff - Reference: WS_WAL_CON_375_WT; sets with these values: 2
Pset_WallCommon - LoadBearing: yes; IsExternal: yes; ExtendToStructure: no; Reference: WS_WAL_CON_375_WT
Sonstige - Familie: Basiswand; Familie und Typ: Basiswand: WS_WAL_CON_375_WT; Typ: WS_WAL_CON_375_WT; Typ-ID: 4042839
Abhängigkeiten - Für Körper: no; Basislinie: Tragende Schicht: Innenkante; Oberkante ist fixiert.: no; Raumbegrenzung: yes; Unterkante ist fixiert: no; Verlängerungsabstand oben: 0 m; Verlängerungsabstand unten: 0 m; Versatz oben: 0 m; Versatz unten: 0 m; Abhängigkeit oben: Bis Ebene: Dü_U01_UKBP_+0,53; Abhängigkeit unten: Dü_U01_OKRD_-0,12; Nicht verknüpfte Höhe: 0.65 m
Bemaßungen - Fläche: 5.7525 m2; Länge: 8.975 m; Volumen: 2.15719 m3
ID-Daten - Hat Verknüpfung: no; WS_COMMENT_MATERIAL: C25/30 WU; WS_POSITIONNUMBER: 005; WS_TYPE_BUILDING_ELEMENT: F
Phasen - Phase erstellt: Phase 1
Tragwerk - Betonüberdeckung - Andere Flächen: Bewehrungsüberdeckung 1 <25 mm>; Tragwerk: yes; Betonüberdeckung - Außenfläche: Bewehrungsüberdeckung 1 <25 mm>; Betonüberdeckung - Innenfläche: Bewehrungsüberdeckung 1 <25 mm>; Tragwerksverwendung: Tragend
Text - WS_LEVEL: U1
Querschnittsdefinition - Querschnitt: Vertikal

# IfcWallStandardCase: Basiswand:WS_WAL_MAS_240 (9)
In: FB_U01_OKFB
Type - PredefinedType: STANDARD; Material: WS_MASONRY 0.24 m
Type - Sonstige - Kategorie: Wände; Familienname: Basiswand
Type - Konstruktion - Abschluss an Öffnungen: Keine; Abschluss an Wänden: Außen; Funktion: Außen; Breite: 0.24 m
Type - Grafiken - Füllmuster für groben Maßstab: <Flächenfüllung>; Farbfüllung für groben Maßstab: 8421504
Type - ID-Daten - Typenkommentare: Mauerwerk_Ausbau; Typname: WS_WAL_MAS_240; WS_COMMENT_DIMENSION: t=24cm
Type - Materialien und Oberflächen - Tragendes Material: WS_MASONRY
Type - Analytische Eigenschaften - Absorptionsgrad: 0.1; Rauigkeit: 1
Pset_QuantityTakeOff - Reference: WS_WAL_MAS_240; sets with these values: 2
Pset_WallCommon - LoadBearing: yes; IsExternal: yes; ExtendToStructure: no; Reference: WS_WAL_MAS_240
Sonstige - Familie: Basiswand; Familie und Typ: Basiswand: WS_WAL_MAS_240; Typ: WS_WAL_MAS_240; Typ-ID: 3204820
Abhängigkeiten - Für Körper: no; Basislinie: Tragende Schicht: Innenkante; Oberkante ist fixiert.: no; Raumbegrenzung: yes; Unterkante ist fixiert: no; Verlängerungsabstand oben: 0 m; Verlängerungsabstand unten: 0 m; Abhängigkeit unten: Dü_U01_OKRD_-0,12
ID-Daten - Hat Verknüpfung: no; WS_COMMENT_MATERIAL: KS 20-2,0 M2,5; WS_TYPE_BUILDING_ELEMENT: W
Phasen - Phase erstellt: Phase 1
Tragwerk - Betonüberdeckung - Andere Flächen: Bewehrungsüberdeckung 1 <25 mm>; Tragwerk: yes; Betonüberdeckung - Außenfläche: Bewehrungsüberdeckung 1 <25 mm>; Betonüberdeckung - Innenfläche: Bewehrungsüberdeckung 1 <25 mm>; Tragwerksverwendung: Tragend
Text - WS_LEVEL: 00
Querschnittsdefinition - Querschnitt: Vertikal
Name (Basiswand:WS_WAL_MAS_240:...) | Abhängigkeit oben | Nicht verknüpfte Höhe (m) | Versatz oben (m) | Versatz unten (m) | Fläche (m2) | Länge (m) | Volumen (m3) | WS_POSITIONNUMBER
3799305 | Bis Ebene: Dü_EG_OKHT_+3,935_Foyer 1 | 3.557 | -0.248 | 0.25 | 8.17988 | 2.32496 | 1.96317 | 020.6
3799667 | Bis Ebene: Dü_EG_UKRD_+3,38 | 3.062 | -0.188 | 0.25 | 5.09835 | 1.42504 | 1.2236 | 020.4
3799806 | Bis Ebene: Dü_EG_UKRD_+3,38 | 3.062 | -0.188 | 0.25 | 8.66127 | 3.08004 | 2.0787 | 020.2
4524972 | Bis Ebene: Dü_U01_OKRD_-0,12 | 0.25 | 0.25 | 0 | 0.99125 | 3.965 | 0.2379 | 020.1
4524975 | Bis Ebene: Dü_U01_OKRD_-0,12 | 0.25 | 0.25 | 0 | 0.41626 | 1.42504 | 0.0999024 | 020.4
4524976 | Bis Ebene: Dü_U01_OKRD_-0,12 | 0.25 | 0.25 | 0 | 0.77001 | 3.08004 | 0.184802 | 020.2
4525484 | Bis Ebene: Dü_U01_OKRD_-0,12 | 0.25 | 0.25 | 0 | 0.467475 | 1.9899 | 0.112194 | 020.4
4525559 | Bis Ebene: Dü_U01_OKRD_-0,12 | 0.25 | 0.25 | 0 | 0.58124 | 2.44496 | 0.139498 | 020.4
4526020 | Bis Ebene: Dü_U01_OKRD_-0,12 | 0.25 | 0.25 | 0 | 1.09997 | 4.5199 | 0.263994 | 020.4

# IfcWallStandardCase: Basiswand:WS_WAL_TIM_305 (2)
In: FB_E00_OKFB
Type - PredefinedType: STANDARD; Material: WS_INSULATION_HARD 0.28 m, WS_TIMBER 0.015 m
Type - Sonstige - Kategorie: Wände; Familienname: Basiswand
Type - Konstruktion - Abschluss an Öffnungen: Keine; Abschluss an Wänden: Außen; Funktion: Außen; Breite: 0.295 m
Type - Grafiken - Füllmuster für groben Maßstab: <Flächenfüllung>; Farbfüllung für groben Maßstab: 8421504
Type - ID-Daten - Typenkommentare: Timber; Typname: WS_WAL_TIM_305; WS_COMMENT_DIMENSION: t=30,5cm
Type - Materialien und Oberflächen - Tragendes Material: WS_TIMBER
Type - Analytische Eigenschaften - Absorptionsgrad: 0.1; Rauigkeit: 1
Pset_QuantityTakeOff - Reference: WS_WAL_TIM_305; sets with these values: 2
Pset_WallCommon - LoadBearing: yes; IsExternal: yes; ExtendToStructure: no; Reference: WS_WAL_TIM_305
Sonstige - Familie: Basiswand; Familie und Typ: Basiswand: WS_WAL_TIM_305; Typ: WS_WAL_TIM_305; Typ-ID: 3864228
Abhängigkeiten - Für Körper: no; Basislinie: Tragende Schicht: Innenkante; Oberkante ist fixiert.: no; Raumbegrenzung: yes; Unterkante ist fixiert: no; Verlängerungsabstand oben: 0 m; Verlängerungsabstand unten: 0 m; Versatz oben: 0 m; Abhängigkeit unten: Dü_EG_OKRD_+4,035; Abhängigkeit oben: Bis Ebene: Dü_OG1_OKHT_+7,780_Binder
ID-Daten - Hat Verknüpfung: no; WS_POSITIONNUMBER: 104; WS_TYPE_BUILDING_ELEMENT: W
Phasen - Phase erstellt: Phase 1
Tragwerk - Betonüberdeckung - Andere Flächen: Bewehrungsüberdeckung 1 <25 mm>; Tragwerk: yes; Betonüberdeckung - Außenfläche: Bewehrungsüberdeckung 1 <25 mm>; Betonüberdeckung - Innenfläche: Bewehrungsüberdeckung 1 <25 mm>; Tragwerksverwendung: Tragend
Text - WS_LEVEL: 01
Querschnittsdefinition - Querschnitt: Vertikal
Name (Basiswand:WS_WAL_TIM_305:...) | Nicht verknüpfte Höhe (m) | Versatz unten (m) | Fläche (m2) | Länge (m) | Volumen (m3)
3808074 | 2.98 | 0.765 | 47.5586 | 16.9224 | 14.0298
4166193 | 1.98 | 1.765 | 4.80662 | 2.42759 | 1.41795
